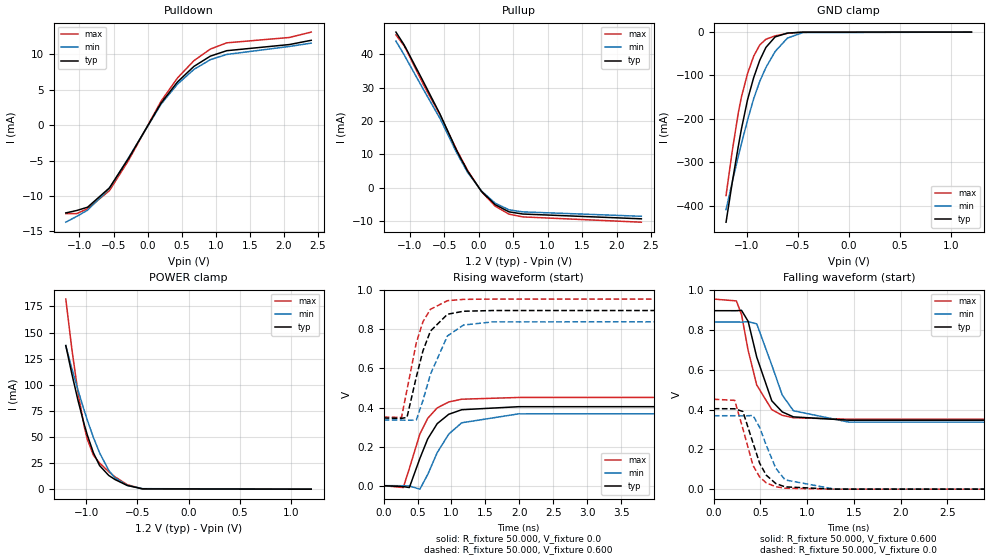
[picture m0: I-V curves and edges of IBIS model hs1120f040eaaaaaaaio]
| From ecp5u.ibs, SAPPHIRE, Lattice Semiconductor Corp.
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|   Model hs1120f040eaaaaaaaio
[Model] hs1120f040eaaaaaaaio
Model_type I/O
Polarity   Non-Inverting
Enable   Active-Low
Vinl =  0.500V
Vinh =  0.700V
Vmeas =  0.600V
Cref =  20.000pF
Rref =  50.000
Vref =  0.600V
C_comp   5.000pF   4.000pF   5.500pF
[Temperature Range]   25.000   0.125k   -40.000
[Voltage Range]   1.200V   1.140V   1.260V
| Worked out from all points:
|   slope of the pulldown table from 0 to 0.18 V, typ, clamps not added: 62.6 ohm
|   slope of the pullup table from 0 to 0.18 V, typ, clamps not added: 44.5 ohm
|   GND clamp passes 1 mA (typ) near -0.54 V on its own axis
|   POWER clamp passes 1 mA (typ) near -0.51 V on its own axis
|   rising waveform, R_fixture 50.000, V_fixture 0.0: 20-80 % time 327ps typ, 376ps min, 303ps max; typ from 0 V to 0.404 V
|   rising waveform, R_fixture 50.000, V_fixture 0.600: 20-80 % time 264ps typ, 305ps min, 239ps max; typ from 0.346 V to 0.897 V
|   falling waveform, R_fixture 50.000, V_fixture 0.600: 20-80 % time 201ps typ, 222ps min, 189ps max; typ from 0.897 V to 0.346 V
|   falling waveform, R_fixture 50.000, V_fixture 0.0: 20-80 % time 182ps typ, 204ps min, 167ps max; typ from 0.404 V to 0 V
[Pulldown]
|Voltage   I(typ)   I(min)   I(max)
-1.2V     -12.39mA   -13.7mA    -12.49mA
-1.04V    -12.05mA   -12.88mA   -12.49mA
-880mV    -11.58mA   -12mA      -11.79mA
-560mV    -8.851mA   -8.925mA   -9.245mA
-280mV    -4.688mA   -4.607mA   -4.974mA
200mV     3.164mA    3.008mA    3.437mA
440mV     6.136mA    5.828mA    6.7mA
680mV     8.315mA    7.89mA     9.126mA
920mV     9.761mA    9.262mA    10.76mA
1.16V     10.53mA    9.999mA    11.64mA
2.08V     11.4mA     11.13mA    12.4mA
2.4V      12mA       11.6mA     13.16mA
[Pullup]
|Voltage   I(typ)   I(min)   I(max)
-1.2V     46.58mA    43.89mA    45.74mA
-1.08V    42.72mA    39.74mA    42.43mA
-1.04V    41.15mA    38.23mA    40.88mA
-800mV    31.67mA    29.37mA    30.83mA
-560mV    22.01mA    20.73mA    21.77mA
-320mV    11.18mA    10.54mA    11.37mA
-160mV    4.974mA    4.595mA    5.205mA
40mV      -1.043mA   -938.5uA   -1.131mA
240mV     -5.059mA   -4.599mA   -5.498mA
440mV     -7.189mA   -6.594mA   -7.881mA
640mV     -7.846mA   -7.203mA   -8.71mA
2.36V     -9.281mA   -8.526mA   -10.29mA
[GND_clamp]
|Voltage   I(typ)   I(min)   I(max)
-1.2V     -438mA     -409mA     -376.5mA
-1.14V    -347.3mA   -346mA     -274.9mA
-1.08V    -262.9mA   -286.2mA   -185.9mA
-1.05V    -223.7mA   -257.6mA   -150mA
-990mV    -156.1mA   -203.2mA   -95.66mA
-930mV    -105mA     -153.7mA   -55.58mA
-870mV    -64.74mA   -113.2mA   -29.56mA
-810mV    -35.2mA    -81.56mA   -16.45mA
-720mV    -11.09mA   -44.69mA   -8.691mA
-600mV    -2.287mA   -13.94mA   -2.904mA
-450mV    -166.2uA   -1.247mA   -164.1uA
1.2V      0A         0A         0A
[POWER_clamp]
|Voltage   I(typ)   I(min)   I(max)
-1.2V     137.6mA    137.3mA    182.1mA
-1.14V    110.1mA    115.3mA    133.6mA
-1.08V    84.76mA    94.63mA    92.15mA
-1.02V    62.11mA    75.36mA    59.94mA
-990mV    52mA       66.3mA     47.89mA
-930mV    34.81mA    49.51mA    32.55mA
-870mV    22.62mA    34.86mA    25.07mA
-780mV    13.14mA    18.01mA    16.74mA
-720mV    9.284mA    10.72mA    11.88mA
-600mV    3.553mA    3.709mA    4.373mA
-450mV    294.8uA    471.6uA    256.4uA
1.2V      0A         0A         0A
[Ramp]
| variable   typ   min   max
dV/dt_r 0.243/0.326n   0.221/0.376n   0.271/0.306n
dV/dt_f 0.266/0.237n   0.247/0.244n   0.295/0.221n
R_load = 50.000
[Rising Waveform]
R_fixture= 50.000
V_fixture= 0.0
V_fixture_min= 0.0
V_fixture_max= 0.0
|time   V(typ)   V(min)   V(max)
0s        0V         0V         0V
289ps     -4.789mV   -413.9uV   -9.697mV
379ps     -9.66mV    -1.515mV   88.12mV
534ps     139.4mV    -17.96mV   264.5mV
650ps     239.8mV    57.5mV     344.9mV
790ps     317.5mV    169.3mV    398.1mV
960ps     365.4mV    264.1mV    428.4mV
1.151ns   388.6mV    321.8mV    442.5mV
1.99ns    404.1mV    367.5mV    451.4mV
10ns      404.4mV    368.9mV    451.6mV
[Rising Waveform]
R_fixture= 50.000
V_fixture= 0.600
V_fixture_min= 0.571
V_fixture_max= 0.631
|time   V(typ)   V(min)   V(max)
0s        346.3mV    335.9mV    351.2mV
263ps     344.3mV    335.7mV    349mV
344ps     349.5mV    334.8mV    489.9mV
481ps     555.6mV    335.6mV    730.8mV
579ps     689.6mV    435.6mV    838.7mV
690ps     791.3mV    570.7mV    902.8mV
941ps     877.3mV    766.6mV    946.7mV
1.179ns   892.7mV    822.2mV    953.5mV
1.61ns    896.3mV    838.2mV    954.9mV
10ns      896.6mV    839.7mV    955mV
[Falling Waveform]
R_fixture= 50.000
V_fixture= 0.600
V_fixture_min= 0.571
V_fixture_max= 0.631
|time   V(typ)   V(min)   V(max)
0s        896.6mV    839.7mV    955mV
242ps     896.5mV    839.7mV    945.7mV
297ps     898.2mV    839.3mV    877.3mV
368ps     843mV      841.5mV    696.6mV
460ps     663.2mV    830.3mV    523.1mV
621ps     443.8mV    623.4mV    399.5mV
733ps     388.1mV    472.9mV    371mV
853ps     363.1mV    393.9mV    358.8mV
1.445ns   346.5mV    336.8mV    351.3mV
10ns      346.3mV    335.9mV    351.2mV
[Falling Waveform]
R_fixture= 50.000
V_fixture= 0.0
V_fixture_min= 0.0
V_fixture_max= 0.0
|time   V(typ)   V(min)   V(max)
0s        404.4mV    368.9mV    451.6mV
224ps     403.8mV    368.9mV    446.2mV
312ps     390.1mV    368mV      302.8mV
420ps     232.1mV    370mV      118.9mV
491ps     130.3mV    310.5mV    61.37mV
561ps     70.66mV    221.5mV    31.86mV
664ps     28.26mV    105.2mV    12.12mV
764ps     11.56mV    46.42mV    4.735mV
1.291ns   123uV      636.8uV    38.25uV
10ns      0V         0V         0V
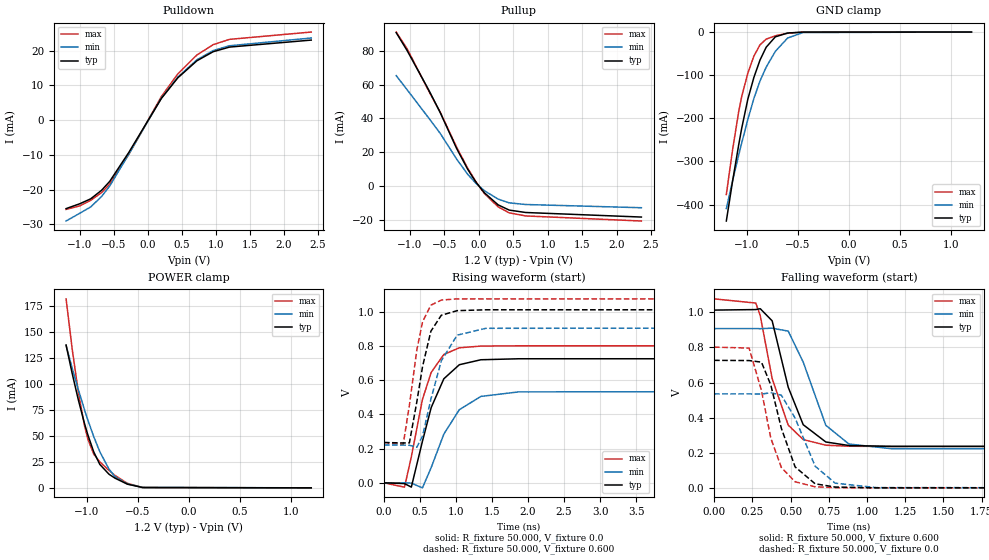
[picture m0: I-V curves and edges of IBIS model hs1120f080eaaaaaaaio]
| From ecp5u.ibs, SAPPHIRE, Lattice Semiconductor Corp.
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|   Model hs1120f080eaaaaaaaio
[Model] hs1120f080eaaaaaaaio
Model_type I/O
Polarity   Non-Inverting
Enable   Active-Low
Vinl =  0.500V
Vinh =  0.700V
Vmeas =  0.600V
Cref =  20.000pF
Rref =  50.000
Vref =  0.600V
C_comp   5.000pF   4.000pF   5.500pF
[Temperature Range]   25.000   0.125k   -40.000
[Voltage Range]   1.200V   1.140V   1.260V
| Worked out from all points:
|   slope of the pulldown table from 0 to 0.18 V, typ, clamps not added: 31.5 ohm
|   slope of the pullup table from 0 to 0.18 V, typ, clamps not added: 22.6 ohm
|   GND clamp passes 1 mA (typ) near -0.54 V on its own axis
|   POWER clamp passes 1 mA (typ) near -0.51 V on its own axis
|   rising waveform, R_fixture 50.000, V_fixture 0.0: 20-80 % time 307ps typ, 377ps min, 267ps max; typ from 0 V to 0.727 V
|   rising waveform, R_fixture 50.000, V_fixture 0.600: 20-80 % time 202ps typ, 266ps min, 177ps max; typ from 0.236 V to 1.01 V
|   falling waveform, R_fixture 50.000, V_fixture 0.600: 20-80 % time 151ps typ, 165ps min, 138ps max; typ from 1.01 V to 0.236 V
|   falling waveform, R_fixture 50.000, V_fixture 0.0: 20-80 % time 141ps typ, 161ps min, 125ps max; typ from 0.727 V to 0 V
[Pulldown]
|Voltage   I(typ)   I(min)   I(max)
-1.2V     -25.46mA   -29.03mA   -25.7mA
-1V       -24.07mA   -26.8mA    -24.67mA
-840mV    -22.66mA   -25mA      -23.11mA
-680mV    -20.21mA   -22.01mA   -20.87mA
-560mV    -17.64mA   -18.97mA   -18.42mA
-280mV    -9.315mA   -9.799mA   -9.876mA
200mV     6.283mA    6.399mA    6.82mA
440mV     12.18mA    12.4mA     13.3mA
720mV     17.09mA    17.37mA    18.76mA
960mV     19.72mA    20.05mA    21.74mA
1.2V      21.05mA    21.43mA    23.27mA
2.4V      23.06mA    23.66mA    25.38mA
[Pullup]
|Voltage   I(typ)   I(min)   I(max)
-1.2V     90.66mA    65.26mA    91.02mA
-1.04V    79.98mA    56.85mA    81mA
-720mV    56.18mA    39.79mA    55.6mA
-560mV    43.33mA    31.08mA    43.6mA
-320mV    22.01mA    15.8mA     22.77mA
-160mV    9.797mA    6.888mA    10.43mA
-40mV     2.216mA    1.527mA    2.421mA
80mV      -3.948mA   -2.709mA   -4.356mA
280mV     -11.09mA   -7.687mA   -12.27mA
440mV     -14.17mA   -9.883mA   -15.79mA
680mV     -15.6mA    -10.88mA   -17.63mA
2.36V     -18.29mA   -12.78mA   -20.63mA
[GND_clamp]
|Voltage   I(typ)   I(min)   I(max)
-1.2V     -438mA     -409mA     -376.5mA
-1.14V    -347.3mA   -346mA     -274.9mA
-1.08V    -262.9mA   -286.2mA   -185.9mA
-1.05V    -223.7mA   -257.6mA   -150mA
-990mV    -156.1mA   -203.2mA   -95.66mA
-930mV    -105mA     -153.7mA   -55.58mA
-870mV    -64.74mA   -113.2mA   -29.56mA
-810mV    -35.2mA    -81.56mA   -16.45mA
-720mV    -11.09mA   -44.69mA   -8.691mA
-600mV    -2.287mA   -13.94mA   -2.904mA
-450mV    -166.2uA   -1.247mA   -164.1uA
1.2V      0A         0A         0A
[POWER_clamp]
|Voltage   I(typ)   I(min)   I(max)
-1.2V     137.6mA    137.3mA    182.1mA
-1.14V    110.1mA    115.3mA    133.6mA
-1.08V    84.76mA    94.63mA    92.15mA
-1.02V    62.11mA    75.36mA    59.94mA
-990mV    52mA       66.3mA     47.89mA
-930mV    34.81mA    49.51mA    32.55mA
-870mV    22.62mA    34.86mA    25.07mA
-780mV    13.14mA    18.01mA    16.74mA
-720mV    9.284mA    10.72mA    11.88mA
-600mV    3.553mA    3.709mA    4.373mA
-450mV    294.8uA    471.6uA    256.4uA
1.2V      0A         0A         0A
[Ramp]
| variable   typ   min   max
dV/dt_r 0.436/0.309n   0.321/0.378n   0.481/0.269n
dV/dt_f 0.411/0.174n   0.397/0.185n   0.448/0.159n
R_load = 50.000
[Rising Waveform]
R_fixture= 50.000
V_fixture= 0.0
V_fixture_min= 0.0
V_fixture_max= 0.0
|time   V(typ)   V(min)   V(max)
0s        0V         0V         0V
285ps     -4.631mV   -474.9uV   -25.7mV
380ps     -25.16mV   -1.901mV   151.7mV
534ps     242.9mV    -29.51mV   488.3mV
656ps     441.2mV    89.85mV    646.8mV
831ps     609.1mV    285.2mV    751.4mV
1.046ns   691.4mV    428.1mV    790.5mV
1.345ns   720.5mV    505.8mV    800.6mV
1.871ns   726.3mV    532.4mV    802.1mV
10ns      726.6mV    535.5mV    802.1mV
[Rising Waveform]
R_fixture= 50.000
V_fixture= 0.600
V_fixture_min= 0.571
V_fixture_max= 0.631
|time   V(typ)   V(min)   V(max)
0s        236.1mV    221.1mV    235.9mV
267ps     233.3mV    220.9mV    224.6mV
353ps     233.7mV    219.7mV    453.6mV
456ps     473.6mV    208mV      777.3mV
536ps     681.3mV    275mV      943mV
651ps     887.3mV    488.6mV    1.04V
796ps     981.1mV    714.6mV    1.07V
1.016ns   1.008V     864.5mV    1.077V
1.415ns   1.013V     904.6mV    1.077V
10ns      1.013V     907.6mV    1.077V
[Falling Waveform]
R_fixture= 50.000
V_fixture= 0.600
V_fixture_min= 0.571
V_fixture_max= 0.631
|time   V(typ)   V(min)   V(max)
0s        1.013V     907.6mV    1.077V
273ps     1.016V     907.8mV    1.053V
302ps     1.021V     907.2mV    981.7mV
380ps     951.7mV    909.9mV    622.4mV
485ps     573.5mV    893.1mV    357.5mV
583ps     359.9mV    716.7mV    275.2mV
731ps     261.4mV    356.3mV    243mV
882ps     241.2mV    249.8mV    237.2mV
1.161ns   236.4mV    223mV      236mV
10ns      236.1mV    221.1mV    235.9mV
[Falling Waveform]
R_fixture= 50.000
V_fixture= 0.0
V_fixture_min= 0.0
V_fixture_max= 0.0
|time   V(typ)   V(min)   V(max)
0s        726.6mV    535.5mV    802.1mV
229ps     725.4mV    535.5mV    796.5mV
310ps     716.4mV    534.3mV    555.1mV
371ps     586.4mV    542.1mV    283.1mV
440ps     339.7mV    527.6mV    116.1mV
530ps     119.4mV    398mV      34.62mV
661ps     23.14mV    123.6mV    5.973mV
792ps     4.578mV    26.73mV    1.078mV
1.062ns   220uV      1.267mV    44.45uV
10ns      0V         0V         0V
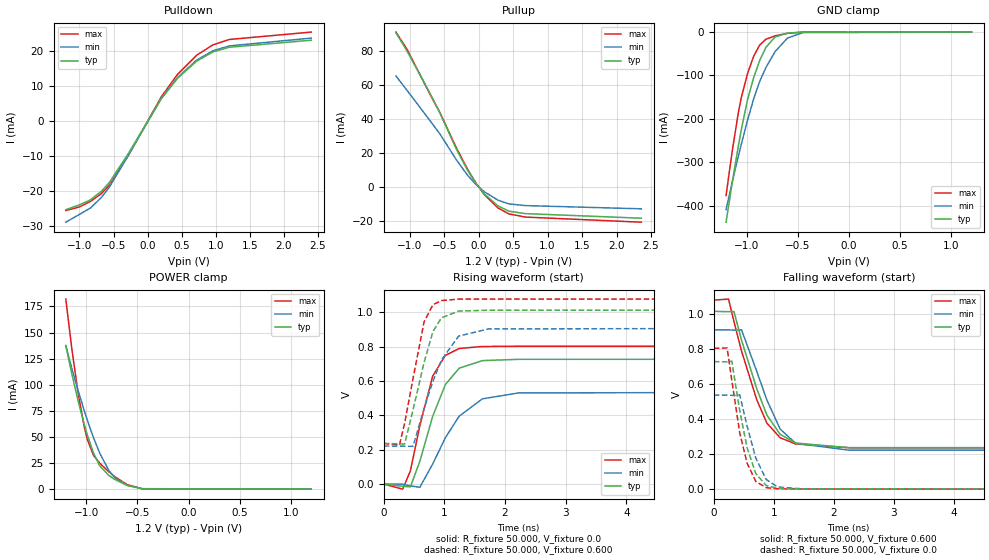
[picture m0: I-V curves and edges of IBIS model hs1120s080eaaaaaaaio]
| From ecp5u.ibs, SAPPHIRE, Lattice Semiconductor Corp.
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|   Model hs1120s080eaaaaaaaio
[Model] hs1120s080eaaaaaaaio
Model_type I/O
Polarity   Non-Inverting
Enable   Active-Low
Vinl =  0.500V
Vinh =  0.700V
Vmeas =  0.600V
Cref =  20.000pF
Rref =  50.000
Vref =  0.600V
C_comp   5.000pF   4.000pF   5.500pF
[Temperature Range]   25.000   0.125k   -40.000
[Voltage Range]   1.200V   1.140V   1.260V
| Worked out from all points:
|   slope of the pulldown table from 0 to 0.18 V, typ, clamps not added: 31.5 ohm
|   slope of the pullup table from 0 to 0.18 V, typ, clamps not added: 22.6 ohm
|   GND clamp passes 1 mA (typ) near -0.54 V on its own axis
|   POWER clamp passes 1 mA (typ) near -0.51 V on its own axis
|   rising waveform, R_fixture 50.000, V_fixture 0.0: 20-80 % time 414ps typ, 535ps min, 329ps max; typ from 0 V to 0.727 V
|   rising waveform, R_fixture 50.000, V_fixture 0.600: 20-80 % time 324ps typ, 423ps min, 265ps max; typ from 0.236 V to 1.01 V
|   falling waveform, R_fixture 50.000, V_fixture 0.600: 20-80 % time 475ps typ, 467ps min, 475ps max; typ from 1.01 V to 0.236 V
|   falling waveform, R_fixture 50.000, V_fixture 0.0: 20-80 % time 259ps typ, 268ps min, 252ps max; typ from 0.727 V to 0 V
[Pulldown]
|Voltage   I(typ)   I(min)   I(max)
-1.2V     -25.46mA   -29.03mA   -25.7mA
-1V       -24.07mA   -26.8mA    -24.67mA
-840mV    -22.66mA   -25mA      -23.11mA
-680mV    -20.21mA   -22.01mA   -20.87mA
-560mV    -17.64mA   -18.97mA   -18.42mA
-280mV    -9.315mA   -9.799mA   -9.876mA
200mV     6.283mA    6.399mA    6.82mA
440mV     12.18mA    12.4mA     13.3mA
720mV     17.09mA    17.37mA    18.76mA
960mV     19.72mA    20.05mA    21.74mA
1.2V      21.05mA    21.43mA    23.27mA
2.4V      23.06mA    23.66mA    25.38mA
[Pullup]
|Voltage   I(typ)   I(min)   I(max)
-1.2V     90.66mA    65.25mA    91.02mA
-1.04V    79.98mA    56.85mA    81mA
-720mV    56.18mA    39.79mA    55.6mA
-560mV    43.33mA    31.08mA    43.6mA
-320mV    22.01mA    15.8mA     22.77mA
-160mV    9.797mA    6.888mA    10.43mA
-40mV     2.216mA    1.527mA    2.421mA
80mV      -3.948mA   -2.709mA   -4.356mA
280mV     -11.09mA   -7.687mA   -12.27mA
440mV     -14.17mA   -9.883mA   -15.79mA
680mV     -15.6mA    -10.88mA   -17.63mA
2.36V     -18.29mA   -12.78mA   -20.63mA
[GND_clamp]
|Voltage   I(typ)   I(min)   I(max)
-1.2V     -438mA     -409mA     -376.5mA
-1.14V    -347.3mA   -346mA     -274.9mA
-1.08V    -262.9mA   -286.2mA   -185.9mA
-1.05V    -223.7mA   -257.6mA   -150mA
-990mV    -156.1mA   -203.2mA   -95.66mA
-930mV    -105mA     -153.7mA   -55.58mA
-870mV    -64.74mA   -113.2mA   -29.56mA
-810mV    -35.2mA    -81.56mA   -16.45mA
-720mV    -11.09mA   -44.69mA   -8.691mA
-600mV    -2.287mA   -13.94mA   -2.904mA
-450mV    -166.2uA   -1.247mA   -164.1uA
1.2V      0A         0A         0A
[POWER_clamp]
|Voltage   I(typ)   I(min)   I(max)
-1.2V     137.6mA    137.3mA    182.1mA
-1.14V    110.1mA    115.3mA    133.6mA
-1.08V    84.76mA    94.63mA    92.15mA
-1.02V    62.11mA    75.36mA    59.94mA
-990mV    52mA       66.3mA     47.89mA
-930mV    34.81mA    49.51mA    32.55mA
-870mV    22.62mA    34.86mA    25.07mA
-780mV    13.14mA    18.01mA    16.74mA
-720mV    9.284mA    10.72mA    11.88mA
-600mV    3.553mA    3.709mA    4.373mA
-450mV    294.8uA    471.6uA    256.4uA
1.2V      0A         0A         0A
[Ramp]
| variable   typ   min   max
dV/dt_r 0.436/0.416n   0.321/0.536n   0.481/0.332n
dV/dt_f 0.411/0.487n   0.397/0.446n   0.448/0.513n
R_load = 50.000
[Rising Waveform]
R_fixture= 50.000
V_fixture= 0.0
V_fixture_min= 0.0
V_fixture_max= 0.0
|time   V(typ)   V(min)   V(max)
0s        0V         0V         0V
314ps     -13.54mV   -930.2uV   -30.05mV
441ps     -16.38mV   -11.15mV   77.16mV
597ps     132.9mV    -18.84mV   340.3mV
808ps     394mV      116.3mV    628.2mV
1.017ns   578.9mV    269.4mV    749.1mV
1.244ns   674.3mV    394.5mV    789mV
1.627ns   718.6mV    495.9mV    800.9mV
2.225ns   726.1mV    530.5mV    802.1mV
10ns      726.6mV    535.5mV    802.1mV
[Rising Waveform]
R_fixture= 50.000
V_fixture= 0.600
V_fixture_min= 0.571
V_fixture_max= 0.631
|time   V(typ)   V(min)   V(max)
0s        236.1mV    221.1mV    235.9mV
260ps     233.9mV    221mV      227mV
345ps     233.3mV    219.8mV    352.8mV
484ps     430.9mV    219.4mV    613.9mV
666ps     707.8mV    440.6mV    943.8mV
812ps     887.4mV    597.6mV    1.044V
952ps     967.7mV    722.5mV    1.068V
1.236ns   1.007V     861mV      1.077V
1.726ns   1.012V     903.2mV    1.077V
10ns      1.013V     907.6mV    1.077V
[Falling Waveform]
R_fixture= 50.000
V_fixture= 0.600
V_fixture_min= 0.571
V_fixture_max= 0.631
|time   V(typ)   V(min)   V(max)
0s        1.013V     907.6mV    1.077V
246ps     1.011V     907.6mV    1.083V
337ps     1.012V     905.8mV    954mV
462ps     849.9mV    908.1mV    787.6mV
716ps     573.1mV    672.1mV    510mV
885ps     422.3mV    508.4mV    376.4mV
1.107ns   312.1mV    342.2mV    292.9mV
1.365ns   262.7mV    261.3mV    257.4mV
2.251ns   236.5mV    222.3mV    236.1mV
10ns      236.1mV    221.1mV    235.9mV
[Falling Waveform]
R_fixture= 50.000
V_fixture= 0.0
V_fixture_min= 0.0
V_fixture_max= 0.0
|time   V(typ)   V(min)   V(max)
0s        726.6mV    535.5mV    802.1mV
222ps     725.1mV    535.5mV    804.5mV
300ps     729.6mV    534.5mV    622mV
433ps     446.5mV    537mV      320.6mV
557ps     235.1mV    357.4mV    146.9mV
701ps     88.27mV    176.6mV    43.82mV
875ps     20.57mV    54.78mV    8.524mV
1.066ns   4.516mV    12.43mV    2.225mV
1.491ns   1.094mV    1.706mV    959.9uV
10ns      0V         0V         0V
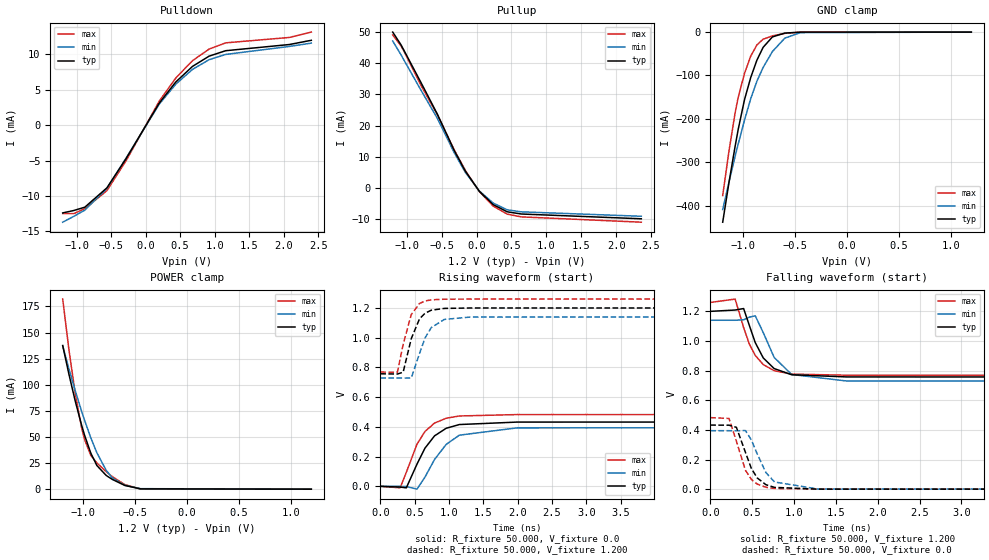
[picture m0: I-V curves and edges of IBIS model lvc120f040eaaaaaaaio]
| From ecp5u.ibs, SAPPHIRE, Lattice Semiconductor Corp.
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|   Model lvc120f040eaaaaaaaio
[Model] lvc120f040eaaaaaaaio
Model_type I/O
Polarity   Non-Inverting
Enable   Active-Low
Vinl =  0.420V
Vinh =  0.780V
Vmeas =  0.600V
Cref =  0.0F
Rref =  1.000M
Vref =  0.0V
C_comp   5.000pF   4.000pF   5.500pF
[Temperature Range]   25.000   0.125k   -40.000
[Voltage Range]   1.200V   1.140V   1.260V
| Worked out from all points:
|   slope of the pulldown table from 0 to 0.18 V, typ, clamps not added: 62.6 ohm
|   slope of the pullup table from 0 to 0.18 V, typ, clamps not added: 41.4 ohm
|   GND clamp passes 1 mA (typ) near -0.54 V on its own axis
|   POWER clamp passes 1 mA (typ) near -0.51 V on its own axis
|   rising waveform, R_fixture 50.000, V_fixture 0.0: 20-80 % time 327ps typ, 376ps min, 303ps max; typ from 0 V to 0.433 V
|   rising waveform, R_fixture 50.000, V_fixture 1.200: 20-80 % time 175ps typ, 206ps min, 158ps max; typ from 0.757 V to 1.2 V
|   falling waveform, R_fixture 50.000, V_fixture 1.200: 20-80 % time 229ps typ, 242ps min, 221ps max; typ from 1.2 V to 0.757 V
|   falling waveform, R_fixture 50.000, V_fixture 0.0: 20-80 % time 182ps typ, 204ps min, 167ps max; typ from 0.433 V to 0 V
[Pulldown]
|Voltage   I(typ)   I(min)   I(max)
-1.2V     -12.39mA   -13.7mA    -12.49mA
-1.04V    -12.05mA   -12.88mA   -12.49mA
-880mV    -11.58mA   -12mA      -11.79mA
-560mV    -8.851mA   -8.925mA   -9.245mA
-280mV    -4.688mA   -4.607mA   -4.974mA
200mV     3.164mA    3.008mA    3.437mA
440mV     6.136mA    5.828mA    6.7mA
680mV     8.315mA    7.89mA     9.126mA
920mV     9.761mA    9.262mA    10.76mA
1.16V     10.53mA    9.999mA    11.64mA
2.08V     11.4mA     11.13mA    12.4mA
2.4V      12mA       11.6mA     13.16mA
[Pullup]
|Voltage   I(typ)   I(min)   I(max)
-1.2V     50.07mA    47.18mA    49.17mA
-1.08V    45.93mA    42.73mA    45.61mA
-1.04V    44.24mA    41.1mA     43.95mA
-800mV    34.04mA    31.57mA    33.14mA
-560mV    23.66mA    22.29mA    23.4mA
-320mV    12.02mA    11.33mA    12.22mA
-160mV    5.347mA    4.94mA     5.595mA
40mV      -1.121mA   -1.009mA   -1.216mA
240mV     -5.438mA   -4.944mA   -5.91mA
440mV     -7.728mA   -7.089mA   -8.472mA
640mV     -8.434mA   -7.743mA   -9.364mA
2.36V     -9.976mA   -9.166mA   -11.07mA
[GND_clamp]
|Voltage   I(typ)   I(min)   I(max)
-1.2V     -438mA     -409mA     -376.5mA
-1.14V    -347.3mA   -346mA     -274.9mA
-1.08V    -262.9mA   -286.2mA   -185.9mA
-1.05V    -223.7mA   -257.6mA   -150mA
-990mV    -156.1mA   -203.2mA   -95.66mA
-930mV    -105mA     -153.7mA   -55.58mA
-870mV    -64.74mA   -113.2mA   -29.56mA
-810mV    -35.2mA    -81.56mA   -16.45mA
-720mV    -11.09mA   -44.69mA   -8.691mA
-600mV    -2.287mA   -13.94mA   -2.904mA
-450mV    -166.2uA   -1.247mA   -164.1uA
1.2V      0A         0A         0A
[POWER_clamp]
|Voltage   I(typ)   I(min)   I(max)
-1.2V     137.6mA    137.3mA    182.1mA
-1.14V    110.1mA    115.3mA    133.6mA
-1.08V    84.76mA    94.63mA    92.15mA
-1.02V    62.11mA    75.36mA    59.94mA
-990mV    52mA       66.3mA     47.89mA
-930mV    34.81mA    49.51mA    32.55mA
-870mV    22.62mA    34.86mA    25.07mA
-780mV    13.14mA    18.01mA    16.74mA
-720mV    9.284mA    10.72mA    11.88mA
-600mV    3.553mA    3.709mA    4.373mA
-450mV    294.8uA    471.6uA    256.4uA
1.2V      0A         0A         0A
[Ramp]
| variable   typ   min   max
dV/dt_r   0.260/0.326n   0.237/0.376n   0.290/0.306n
dV/dt_f   0.266/0.237n   0.247/0.244n   0.295/0.221n
R_load = 50.000
[Rising Waveform]
R_fixture= 50.000
V_fixture= 0.0
V_fixture_min= 0.0
V_fixture_max= 0.0
|time   V(typ)   V(min)   V(max)
0s        0V         0V         0V
289ps     -5.122mV   -442.6uV   -10.37mV
379ps     -10.33mV   -1.62mV    94.23mV
534ps     149mV      -19.21mV   282.9mV
650ps     256.4mV    61.5mV     368.9mV
790ps     339.6mV    181mV      425.7mV
960ps     390.8mV    282.4mV    458.2mV
1.151ns   415.6mV    344.2mV    473.3mV
1.99ns    432.2mV    393.1mV    482.7mV
10ns      432.5mV    394.5mV    482.9mV
[Rising Waveform]
R_fixture= 50.000
V_fixture= 1.200
V_fixture_min= 1.140
V_fixture_max= 1.260
|time   V(typ)   V(min)   V(max)
0s        757.1mV    728.8mV    768.8mV
249ps     755.6mV    728.8mV    767.7mV
333ps     768mV      727.8mV    954.4mV
451ps     993.7mV    728.5mV    1.156V
571ps     1.127V     893.7mV    1.23V
652ps     1.165V     998.9mV    1.247V
742ps     1.185V     1.068V     1.255V
932ps     1.197V     1.123V     1.259V
1.311ns   1.2V       1.139V     1.26V
10ns      1.2V       1.14V      1.26V
[Falling Waveform]
R_fixture= 50.000
V_fixture= 1.200
V_fixture_min= 1.140
V_fixture_max= 1.260
|time   V(typ)   V(min)   V(max)
0s        1.2V       1.14V      1.26V
297ps     1.209V     1.14V      1.283V
398ps     1.219V     1.143V     1.091V
466ps     1.106V     1.161V     980mV
537ps     989.3mV    1.17V      902.9mV
633ps     885.5mV    1.056V     840.7mV
763ps     813.8mV    889mV      799.4mV
972ps     772.2mV    773.8mV    776.6mV
1.633ns   757.4mV    729.7mV    769mV
10ns      757.1mV    728.8mV    768.8mV
[Falling Waveform]
R_fixture= 50.000
V_fixture= 0.0
V_fixture_min= 0.0
V_fixture_max= 0.0
|time   V(typ)   V(min)   V(max)
0s        432.5mV    394.5mV    482.9mV
224ps     431.8mV    394.5mV    477.2mV
312ps     417.3mV    393.6mV    323.8mV
420ps     248.2mV    395.7mV    127.2mV
491ps     139.3mV    332mV      65.66mV
561ps     75.6mV     236.9mV    34.09mV
664ps     30.23mV    112.5mV    12.97mV
767ps     12.04mV    48.49mV    4.923mV
1.291ns   131.7uV    681.6uV    38.3uV
10ns      0V         0V         0V
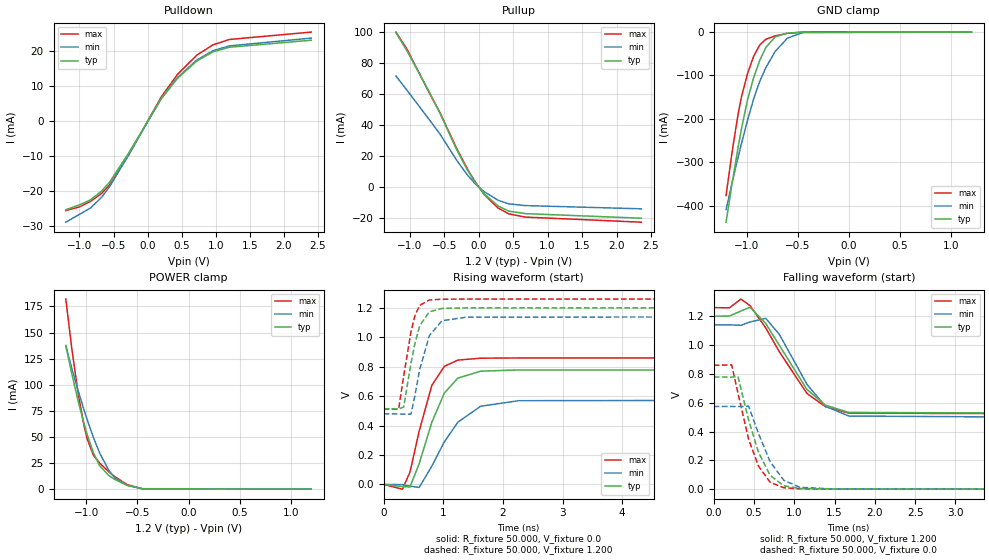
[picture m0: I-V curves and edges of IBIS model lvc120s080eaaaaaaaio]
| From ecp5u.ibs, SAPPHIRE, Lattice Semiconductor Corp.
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|   Model lvc120s080eaaaaaaaio
[Model] lvc120s080eaaaaaaaio
Model_type I/O
Polarity   Non-Inverting
Enable   Active-Low
Vinl =  0.420V
Vinh =  0.780V
Vmeas =  0.600V
Cref =  0.0F
Rref =  1.000M
Vref =  0.0V
C_comp   5.000pF   4.000pF   5.500pF
[Temperature Range]   25.000   0.125k   -40.000
[Voltage Range]   1.200V   1.140V   1.260V
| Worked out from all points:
|   slope of the pulldown table from 0 to 0.18 V, typ, clamps not added: 31.5 ohm
|   slope of the pullup table from 0 to 0.18 V, typ, clamps not added: 20.5 ohm
|   GND clamp passes 1 mA (typ) near -0.54 V on its own axis
|   POWER clamp passes 1 mA (typ) near -0.51 V on its own axis
|   rising waveform, R_fixture 50.000, V_fixture 0.0: 20-80 % time 414ps typ, 535ps min, 329ps max; typ from 0 V to 0.779 V
|   rising waveform, R_fixture 50.000, V_fixture 1.200: 20-80 % time 206ps typ, 235ps min, 188ps max; typ from 0.515 V to 1.2 V
|   falling waveform, R_fixture 50.000, V_fixture 1.200: 20-80 % time 477ps typ, 429ps min, 505ps max; typ from 1.2 V to 0.515 V
|   falling waveform, R_fixture 50.000, V_fixture 0.0: 20-80 % time 260ps typ, 268ps min, 253ps max; typ from 0.779 V to 0 V
[Pulldown]
|Voltage   I(typ)   I(min)   I(max)
-1.2V     -25.46mA   -29.03mA   -25.7mA
-1V       -24.07mA   -26.8mA    -24.67mA
-840mV    -22.66mA   -25mA      -23.11mA
-680mV    -20.21mA   -22.01mA   -20.87mA
-560mV    -17.64mA   -18.97mA   -18.42mA
-280mV    -9.315mA   -9.799mA   -9.876mA
200mV     6.283mA    6.399mA    6.82mA
440mV     12.18mA    12.4mA     13.3mA
720mV     17.09mA    17.37mA    18.76mA
960mV     19.72mA    20.05mA    21.74mA
1.2V      21.05mA    21.43mA    23.27mA
2.4V      23.06mA    23.66mA    25.38mA
[Pullup]
|Voltage   I(typ)   I(min)   I(max)
-1.2V     99.72mA    71.77mA    100.1mA
-1.04V    87.98mA    62.54mA    89.1mA
-720mV    61.79mA    43.77mA    61.16mA
-560mV    47.66mA    34.19mA    47.95mA
-320mV    24.22mA    17.38mA    25.05mA
-160mV    10.78mA    7.577mA    11.47mA
-40mV     2.437mA    1.679mA    2.663mA
80mV      -4.343mA   -2.98mA    -4.792mA
280mV     -12.2mA    -8.456mA   -13.5mA
440mV     -15.58mA   -10.87mA   -17.37mA
680mV     -17.16mA   -11.97mA   -19.4mA
2.36V     -20.12mA   -14.05mA   -22.69mA
[GND_clamp]
|Voltage   I(typ)   I(min)   I(max)
-1.2V     -438mA     -409mA     -376.5mA
-1.14V    -347.3mA   -346mA     -274.9mA
-1.08V    -262.9mA   -286.2mA   -185.9mA
-1.05V    -223.7mA   -257.6mA   -150mA
-990mV    -156.1mA   -203.2mA   -95.66mA
-930mV    -105mA     -153.7mA   -55.58mA
-870mV    -64.74mA   -113.2mA   -29.56mA
-810mV    -35.2mA    -81.56mA   -16.45mA
-720mV    -11.09mA   -44.69mA   -8.691mA
-600mV    -2.287mA   -13.94mA   -2.904mA
-450mV    -166.2uA   -1.247mA   -164.1uA
1.2V      0A         0A         0A
[POWER_clamp]
|Voltage   I(typ)   I(min)   I(max)
-1.2V     137.6mA    137.3mA    182.1mA
-1.14V    110.1mA    115.3mA    133.6mA
-1.08V    84.76mA    94.63mA    92.15mA
-1.02V    62.11mA    75.36mA    59.94mA
-990mV    52mA       66.3mA     47.89mA
-930mV    34.81mA    49.51mA    32.55mA
-870mV    22.62mA    34.86mA    25.07mA
-780mV    13.14mA    18.01mA    16.74mA
-720mV    9.284mA    10.72mA    11.88mA
-600mV    3.553mA    3.709mA    4.373mA
-450mV    294.8uA    471.6uA    256.4uA
1.2V      0A         0A         0A
[Ramp]
| variable   typ   min   max
dV/dt_r   0.463/0.416n   0.349/0.536n   0.507/0.332n
dV/dt_f   0.411/0.487n   0.397/0.446n   0.448/0.513n
R_load = 50.000
[Rising Waveform]
R_fixture= 50.000
V_fixture= 0.0
V_fixture_min= 0.0
V_fixture_max= 0.0
|time   V(typ)   V(min)   V(max)
0s        0V         0V         0V
314ps     -14.51mV   -996.9uV   -32.2mV
441ps     -17.55mV   -11.95mV   82.69mV
597ps     142.4mV    -20.19mV   364.6mV
808ps     422.2mV    124.7mV    673.1mV
1.017ns   620.4mV    288.7mV    802.6mV
1.244ns   722.5mV    422.7mV    845.1mV
1.627ns   770mV      531.5mV    858.1mV
2.264ns   778.1mV    569.2mV    859.6mV
10ns      778.7mV    573.9mV    859.6mV
[Rising Waveform]
R_fixture= 50.000
V_fixture= 1.200
V_fixture_min= 1.140
V_fixture_max= 1.260
|time   V(typ)   V(min)   V(max)
0s        515.1mV    479.1mV    513.2mV
252ps     513mV      479mV      512.4mV
336ps     526.3mV    477.7mV    737.4mV
458ps     823.1mV    478mV      1.037V
525ps     957.9mV    606.2mV    1.149V
605ps     1.079V     781.8mV    1.217V
767ps     1.174V     1.012V     1.254V
979ps     1.196V     1.113V     1.259V
1.39ns    1.2V       1.137V     1.26V
10ns      1.2V       1.14V      1.26V
[Falling Waveform]
R_fixture= 50.000
V_fixture= 1.200
V_fixture_min= 1.140
V_fixture_max= 1.260
|time   V(typ)   V(min)   V(max)
0s        1.2V       1.14V      1.26V
194ps     1.201V     1.14V      1.258V
337ps     1.236V     1.137V     1.319V
451ps     1.262V     1.16V      1.273V
645ps     1.15V      1.185V     1.119V
815ps     996.7mV    1.073V     952.5mV
1.157ns   691.8mV    727.3mV    663.9mV
1.385ns   582.9mV    575.8mV    572.6mV
1.676ns   532.5mV    507.4mV    527.5mV
10ns      515.1mV    479.1mV    513.2mV
[Falling Waveform]
R_fixture= 50.000
V_fixture= 0.0
V_fixture_min= 0.0
V_fixture_max= 0.0
|time   V(typ)   V(min)   V(max)
0s        778.7mV    573.9mV    859.6mV
222ps     777.1mV    573.9mV    862.2mV
300ps     782mV      572.8mV    666.8mV
433ps     478.7mV    575.5mV    344.7mV
556ps     254.3mV    384.7mV    159.3mV
700ps     95.85mV    190.4mV    47.69mV
868ps     23.47mV    61.85mV    9.803mV
1.07ns    4.721mV    12.95mV    2.348mV
1.469ns   1.251mV    1.979mV    1.064mV
10ns      0V         0V         0V
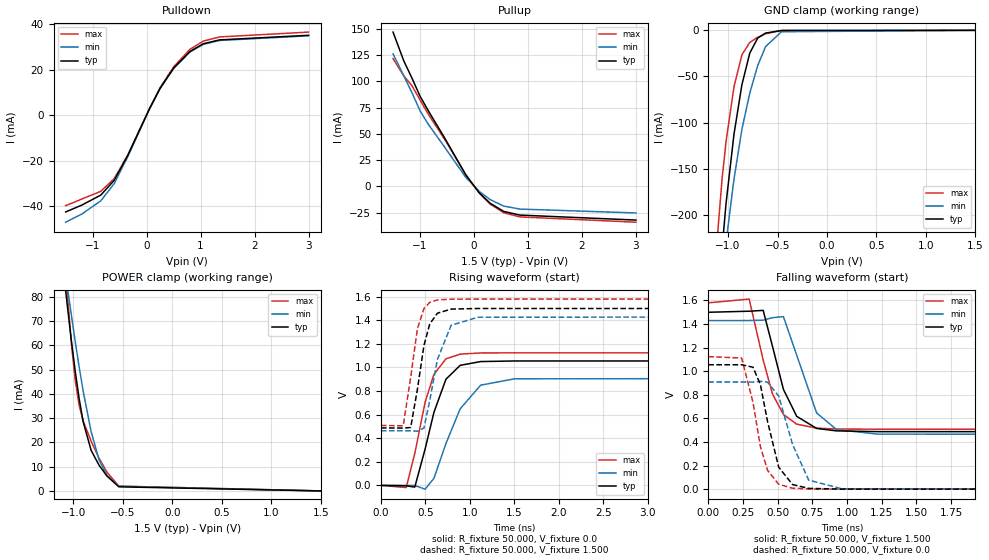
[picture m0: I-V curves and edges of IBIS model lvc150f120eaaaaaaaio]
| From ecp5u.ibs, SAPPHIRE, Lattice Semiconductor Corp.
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|   Model lvc150f120eaaaaaaaio
[Model] lvc150f120eaaaaaaaio
Model_type I/O
Polarity   Non-Inverting
Enable   Active-Low
Vinl =  0.375V
Vinh =  1.125V
Vmeas =  0.750V
Cref =  0.0F
Rref =  1.000M
Vref =  0.0V
C_comp   5.000pF   4.000pF   5.500pF
[Temperature Range]   25.000   0.125k   -40.000
[Voltage Range]   1.500V   1.430V   1.580V
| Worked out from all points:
|   slope of the pulldown table from 0 to 0.225 V, typ, clamps not added: 21 ohm
|   slope of the pullup table from 0 to 0.225 V, typ, clamps not added: 17.7 ohm
|   GND clamp passes 1 mA (typ) near -0.54 V on its own axis
|   POWER clamp passes 1 mA (typ) near -0.51 V on its own axis
|   rising waveform, R_fixture 50.000, V_fixture 0.0: 20-80 % time 227ps typ, 298ps min, 204ps max; typ from 0 V to 1.05 V
|   rising waveform, R_fixture 50.000, V_fixture 1.500: 20-80 % time 130ps typ, 162ps min, 118ps max; typ from 0.487 V to 1.5 V
|   falling waveform, R_fixture 50.000, V_fixture 1.500: 20-80 % time 149ps typ, 160ps min, 143ps max; typ from 1.5 V to 0.487 V
|   falling waveform, R_fixture 50.000, V_fixture 0.0: 20-80 % time 115ps typ, 133ps min, 105ps max; typ from 1.05 V to 0 V
[Pulldown]
|Voltage   I(typ)   I(min)   I(max)
-1.5V     -42.59mA   -47.09mA   -39.82mA
-1.2V     -39.57mA   -43.49mA   -36.91mA
-850mV    -35.19mA   -37.71mA   -33.53mA
-600mV    -28.67mA   -30.1mA    -27.92mA
-350mV    -17.76mA   -18.32mA   -17.6mA
50mV      2.612mA    2.594mA    2.654mA
250mV     11.78mA    11.69mA    12.02mA
500mV     20.64mA    20.46mA    21.18mA
800mV     27.91mA    27.63mA    28.82mA
1.05V     31.33mA    31.05mA    32.49mA
1.35V     33.02mA    32.77mA    34.32mA
3V        35.04mA    34.81mA    36.45mA
[Pullup]
|Voltage   I(typ)   I(min)   I(max)
-1.5V     146.9mA    126.2mA    121.7mA
-1.3V     119.4mA    105.3mA    105.2mA
-1.15V    103.2mA    89.23mA    95.91mA
-1V       85.93mA    72.1mA     82.36mA
-850mV    72.31mA    59.42mA    69.07mA
-550mV    46.67mA    37.82mA    45.33mA
-150mV    10.81mA    8.517mA    11.05mA
100mV     -6.214mA   -4.811mA   -6.519mA
300mV     -16.04mA   -12.52mA   -16.81mA
550mV     -23.77mA   -18.7mA    -24.99mA
850mV     -27.28mA   -21.54mA   -29.02mA
3V        -32mA      -25.22mA   -34.03mA
[GND_clamp]
|Voltage   I(typ)   I(min)   I(max)
-1.5V     -960.1mA   -762.7mA   -1.034A
-1.14V    -347.3mA   -346mA     -275mA
-1.1V     -290.2mA   -305.8mA   -213.7mA
-1.06V    -236.5mA   -267.1mA   -161mA
-1.02V    -187.7mA   -229.9mA   -120.7mA
-940mV    -112.8mA   -161.5mA   -61.34mA
-860mV    -59.06mA   -107.5mA   -26.59mA
-780mV    -24.6mA    -67.97mA   -13.06mA
-700mV    -8.431mA   -38.1mA    -7.531mA
-620mV    -2.969mA   -17.61mA   -3.668mA
-460mV    -207.8uA   -1.521mA   -211uA
1.5V      0A         0A         0A
[POWER_clamp]
|Voltage   I(typ)   I(min)   I(max)
-1.5V     267.6mA    236.4mA    479.7mA
-1.1V     90.92mA    95.54mA    105.5mA
-1.06V    76.14mA    83.93mA    81.29mA
-1.02V    62.03mA    72.49mA    60.96mA
-980mV    49.07mA    61.38mA    45.36mA
-940mV    37.73mA    50.83mA    34.98mA
-900mV    28.44mA    41.02mA    28.75mA
-820mV    16.72mA    24.41mA    20.46mA
-740mV    10.6mA     12.83mA    13.51mA
-660mV    6.131mA    6.445mA    7.75mA
-540mV    1.697mA    1.964mA    1.966mA
1.5V      0A         0A         0A
[Ramp]
| variable   typ   min   max
dV/dt_r 0.633/0.227n   0.545/0.299n   0.675/0.206n
dV/dt_f 0.608/0.153n   0.580/0.164n   0.643/0.148n
R_load = 50.000
[Rising Waveform]
R_fixture= 50.000
V_fixture= 0.0
V_fixture_min= 0.0
V_fixture_max= 0.0
|time   V(typ)   V(min)   V(max)
0s        0V         0V         0V
285ps     -3.711mV   -326.9uV   -18.48mV
381ps     -14.46mV   -1.488mV   271.3mV
497ps     308.6mV    -32.17mV   705.4mV
596ps     619.3mV    59.81mV    941.7mV
731ps     900.3mV    354.7mV    1.073V
891ps     1.018V     649.4mV    1.113V
1.121ns   1.05V      849.8mV    1.123V
1.501ns   1.055V     903.7mV    1.124V
10ns      1.055V     909mV      1.124V
[Rising Waveform]
R_fixture= 50.000
V_fixture= 1.500
V_fixture_min= 1.430
V_fixture_max= 1.580
|time   V(typ)   V(min)   V(max)
0s        487.2mV    463.2mV    508.2mV
251ps     485.9mV    463.2mV    504.8mV
335ps     490.9mV    462.4mV    917.8mV
411ps     818mV      459.3mV    1.33V
484ps     1.187V     486.7mV    1.5V
549ps     1.369V     720.3mV    1.552V
635ps     1.46V      1.068V     1.573V
790ps     1.495V     1.358V     1.579V
1.091ns   1.5V       1.426V     1.58V
10ns      1.5V       1.43V      1.58V
[Falling Waveform]
R_fixture= 50.000
V_fixture= 1.500
V_fixture_min= 1.430
V_fixture_max= 1.580
|time   V(typ)   V(min)   V(max)
0s        1.5V       1.43V      1.58V
295ps     1.509V     1.43V      1.612V
396ps     1.516V     1.433V     1.095V
463ps     1.212V     1.454V     807.2mV
542ps     845.9mV    1.463V     633.3mV
638ps     617.4mV    1.135V     551.2mV
781ps     515.1mV    647.3mV    517.4mV
925ps     494.3mV    504.6mV    510.3mV
1.225ns   487.9mV    466.6mV    508.5mV
10ns      487.2mV    463.2mV    508.2mV
[Falling Waveform]
R_fixture= 50.000
V_fixture= 0.0
V_fixture_min= 0.0
V_fixture_max= 0.0
|time   V(typ)   V(min)   V(max)
0s        1.055V     909mV      1.124V
241ps     1.055V     909mV      1.112V
323ps     1.034V     908mV      733.9mV
376ps     886.7mV    914.4mV    360.4mV
428ps     571.4mV    907.4mV    159mV
508ps     186.2mV    788.7mV    41.73mV
608ps     38.95mV    378.6mV    7.885mV
724ps     6.58mV     76.69mV    1.561mV
963ps     561.4uV    3.246mV    108.8uV
10ns      0V         0V         0V
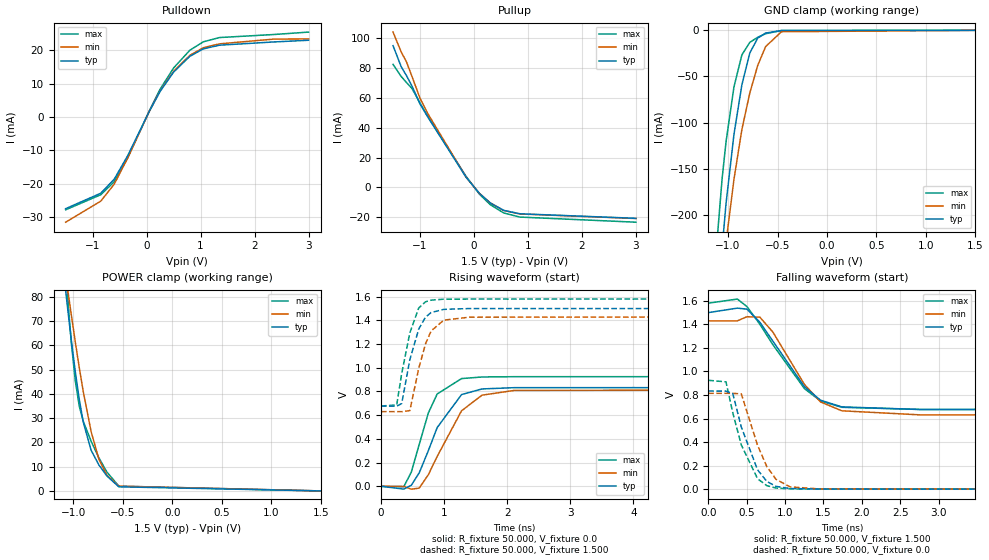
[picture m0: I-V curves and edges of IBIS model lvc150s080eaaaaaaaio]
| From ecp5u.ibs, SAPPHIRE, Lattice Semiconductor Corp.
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|   Model lvc150s080eaaaaaaaio
[Model] lvc150s080eaaaaaaaio
Model_type I/O
Polarity   Non-Inverting
Enable   Active-Low
Vinl =  0.375V
Vinh =  1.125V
Vmeas =  0.750V
Cref =  0.0F
Rref =  1.000M
Vref =  0.0V
C_comp   5.000pF   4.000pF   5.500pF
[Temperature Range]   25.000   0.125k   -40.000
[Voltage Range]   1.500V   1.430V   1.580V
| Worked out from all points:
|   slope of the pulldown table from 0 to 0.225 V, typ, clamps not added: 32.3 ohm
|   slope of the pullup table from 0 to 0.225 V, typ, clamps not added: 27.3 ohm
|   GND clamp passes 1 mA (typ) near -0.54 V on its own axis
|   POWER clamp passes 1 mA (typ) near -0.51 V on its own axis
|   rising waveform, R_fixture 50.000, V_fixture 0.0: 20-80 % time 409ps typ, 487ps min, 327ps max; typ from 0 V to 0.834 V
|   rising waveform, R_fixture 50.000, V_fixture 1.500: 20-80 % time 230ps typ, 235ps min, 210ps max; typ from 0.677 V to 1.5 V
|   falling waveform, R_fixture 50.000, V_fixture 1.500: 20-80 % time 531ps typ, 470ps min, 573ps max; typ from 1.5 V to 0.677 V
|   falling waveform, R_fixture 50.000, V_fixture 0.0: 20-80 % time 260ps typ, 270ps min, 256ps max; typ from 0.834 V to 0 V
[Pulldown]
|Voltage   I(typ)   I(min)   I(max)
-1.5V     -27.39mA   -31.43mA   -27.72mA
-850mV    -22.78mA   -25.14mA   -23.23mA
-600mV    -18.58mA   -20.07mA   -19.34mA
-350mV    -11.53mA   -12.21mA   -12.18mA
50mV      1.697mA    1.729mA    1.836mA
250mV     7.652mA    7.792mA    8.316mA
500mV     13.41mA    13.64mA    14.65mA
800mV     18.13mA    18.42mA    19.93mA
1.05V     20.35mA    20.7mA     22.46mA
1.35V     21.45mA    21.85mA    23.73mA
2.35V     22.41mA    23.26mA    24.63mA
3V        22.92mA    23.32mA    25.36mA
[Pullup]
|Voltage   I(typ)   I(min)   I(max)
-1.5V     95.01mA    104.1mA    82.46mA
-1.35V    81.01mA    90.92mA    74.41mA
-1.25V    74.86mA    84.05mA    70.27mA
-1.15V    68.02mA    74.47mA    66.36mA
-1V       55.88mA    59.73mA    56.56mA
-850mV    46.85mA    49.11mA    47.35mA
-150mV    6.997mA    7.036mA    7.57mA
100mV     -4.023mA   -3.974mA   -4.467mA
300mV     -10.39mA   -10.34mA   -11.52mA
550mV     -15.39mA   -15.45mA   -17.12mA
850mV     -17.67mA   -17.8mA    -19.88mA
3V        -20.72mA   -20.84mA   -23.31mA
[GND_clamp]
|Voltage   I(typ)   I(min)   I(max)
-1.5V     -960.1mA   -762.7mA   -1.034A
-1.14V    -347.3mA   -346mA     -275mA
-1.1V     -290.2mA   -305.8mA   -213.7mA
-1.06V    -236.5mA   -267.1mA   -161mA
-1.02V    -187.7mA   -229.9mA   -120.7mA
-940mV    -112.8mA   -161.5mA   -61.34mA
-860mV    -59.06mA   -107.5mA   -26.59mA
-780mV    -24.6mA    -67.97mA   -13.06mA
-700mV    -8.431mA   -38.1mA    -7.531mA
-620mV    -2.969mA   -17.61mA   -3.668mA
-460mV    -207.8uA   -1.521mA   -211uA
1.5V      0A         0A         0A
[POWER_clamp]
|Voltage   I(typ)   I(min)   I(max)
-1.5V     267.6mA    236.4mA    479.7mA
-1.1V     90.92mA    95.54mA    105.5mA
-1.06V    76.14mA    83.93mA    81.29mA
-1.02V    62.03mA    72.49mA    60.96mA
-980mV    49.07mA    61.38mA    45.36mA
-940mV    37.73mA    50.83mA    34.98mA
-900mV    28.44mA    41.02mA    28.75mA
-820mV    16.72mA    24.41mA    20.46mA
-740mV    10.6mA     12.83mA    13.51mA
-660mV    6.131mA    6.445mA    7.75mA
-540mV    1.697mA    1.964mA    1.966mA
1.5V      0A         0A         0A
[Ramp]
| variable   typ   min   max
dV/dt_r 0.500/0.414n   0.489/0.489n   0.555/0.333n
dV/dt_f 0.494/0.536n   0.480/0.489n   0.542/0.579n
R_load = 50.000
[Rising Waveform]
R_fixture= 50.000
V_fixture= 0.0
V_fixture_min= 0.0
V_fixture_max= 0.0
|time   V(typ)   V(min)   V(max)
0s        0V         0V         0V
363ps     -23.75mV   -946.7uV   -3.677mV
482ps     8.457mV    -24.36mV   119.4mV
608ps     114.1mV    -15.2mV    353.8mV
752ps     300.2mV    97.79mV    618.9mV
892ps     495.5mV    251.8mV    778.8mV
1.278ns   773.8mV    636.9mV    908.9mV
1.602ns   821.5mV    769mV      922.4mV
2.117ns   832.3mV    809.2mV    924.9mV
10ns      833.6mV    814.4mV    925.1mV
[Rising Waveform]
R_fixture= 50.000
V_fixture= 1.500
V_fixture_min= 1.430
V_fixture_max= 1.580
|time   V(typ)   V(min)   V(max)
0s        676.8mV    630.1mV    677mV
251ps     675.9mV    630.1mV    687mV
330ps     698.2mV    629.3mV    951.7mV
459ps     1.069V     638.7mV    1.295V
600ps     1.327V     995.5mV    1.505V
708ps     1.428V     1.203V     1.557V
795ps     1.466V     1.31V      1.571V
996ps     1.493V     1.402V     1.579V
1.398ns   1.5V       1.427V     1.58V
10ns      1.5V       1.43V      1.58V
[Falling Waveform]
R_fixture= 50.000
V_fixture= 1.500
V_fixture_min= 1.430
V_fixture_max= 1.580
|time   V(typ)   V(min)   V(max)
0s        1.5V       1.43V      1.58V
379ps     1.538V     1.43V      1.615V
504ps     1.529V     1.465V     1.551V
672ps     1.418V     1.461V     1.401V
842ps     1.257V     1.334V     1.227V
1.252ns   870mV      889.9mV    854.2mV
1.462ns   755.8mV    740.9mV    749.2mV
1.739ns   698.8mV    665.7mV    695.5mV
2.754ns   677.1mV    631.3mV    677.2mV
10ns      676.8mV    630.1mV    677mV
[Falling Waveform]
R_fixture= 50.000
V_fixture= 0.0
V_fixture_min= 0.0
V_fixture_max= 0.0
|time   V(typ)   V(min)   V(max)
0s        833.6mV    814.4mV    925.1mV
231ps     832.8mV    814.4mV    911.5mV
320ps     811.6mV    813.8mV    648.1mV
430ps     528.6mV    810mV      376.1mV
642ps     164.4mV    372.7mV    88.69mV
762ps     65.9mV     192.7mV    29.96mV
882ps     23.6mV     83.96mV    9.679mV
1.062ns   5.627mV    19.89mV    2.532mV
1.432ns   1.372mV    2.658mV    1.057mV
10ns      0V         535.1nV    0V
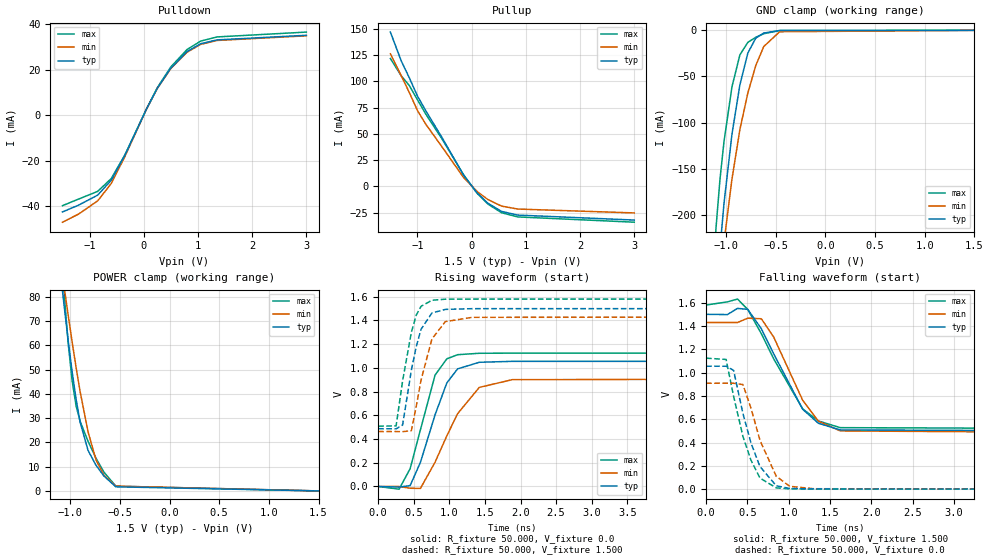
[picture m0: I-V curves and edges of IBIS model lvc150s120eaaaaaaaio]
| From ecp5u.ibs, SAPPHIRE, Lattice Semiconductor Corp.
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|   Model lvc150s120eaaaaaaaio
[Model] lvc150s120eaaaaaaaio
Model_type I/O
Polarity   Non-Inverting
Enable   Active-Low
Vinl =  0.375V
Vinh =  1.125V
Vmeas =  0.750V
Cref =  0.0F
Rref =  1.000M
Vref =  0.0V
C_comp   5.000pF   4.000pF   5.500pF
[Temperature Range]   25.000   0.125k   -40.000
[Voltage Range]   1.500V   1.430V   1.580V
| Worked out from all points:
|   slope of the pulldown table from 0 to 0.225 V, typ, clamps not added: 21 ohm
|   slope of the pullup table from 0 to 0.225 V, typ, clamps not added: 17.7 ohm
|   GND clamp passes 1 mA (typ) near -0.54 V on its own axis
|   POWER clamp passes 1 mA (typ) near -0.51 V on its own axis
|   rising waveform, R_fixture 50.000, V_fixture 0.0: 20-80 % time 344ps typ, 452ps min, 286ps max; typ from 0 V to 1.05 V
|   rising waveform, R_fixture 50.000, V_fixture 1.500: 20-80 % time 201ps typ, 220ps min, 189ps max; typ from 0.487 V to 1.5 V
|   falling waveform, R_fixture 50.000, V_fixture 1.500: 20-80 % time 438ps typ, 397ps min, 485ps max; typ from 1.5 V to 0.487 V
|   falling waveform, R_fixture 50.000, V_fixture 0.0: 20-80 % time 252ps typ, 256ps min, 249ps max; typ from 1.05 V to 0 V
[Pulldown]
|Voltage   I(typ)   I(min)   I(max)
-1.5V     -42.59mA   -47.09mA   -39.82mA
-1.2V     -39.57mA   -43.49mA   -36.91mA
-850mV    -35.19mA   -37.71mA   -33.53mA
-600mV    -28.67mA   -30.1mA    -27.92mA
-350mV    -17.76mA   -18.32mA   -17.6mA
50mV      2.612mA    2.594mA    2.654mA
250mV     11.78mA    11.69mA    12.02mA
500mV     20.64mA    20.46mA    21.18mA
800mV     27.91mA    27.63mA    28.82mA
1.05V     31.33mA    31.05mA    32.49mA
1.35V     33.02mA    32.77mA    34.32mA
3V        35.04mA    34.81mA    36.45mA
[Pullup]
|Voltage   I(typ)   I(min)   I(max)
-1.5V     146.8mA    126.1mA    121.7mA
-1.3V     119.4mA    105.3mA    105.2mA
-1.15V    103.2mA    89.22mA    95.91mA
-1V       85.93mA    72.1mA     82.36mA
-850mV    72.31mA    59.42mA    69.07mA
-550mV    46.67mA    37.82mA    45.33mA
-150mV    10.81mA    8.517mA    11.05mA
100mV     -6.214mA   -4.811mA   -6.519mA
300mV     -16.04mA   -12.52mA   -16.81mA
550mV     -23.77mA   -18.7mA    -24.99mA
850mV     -27.28mA   -21.54mA   -29.02mA
3V        -32mA      -25.22mA   -34.03mA
[GND_clamp]
|Voltage   I(typ)   I(min)   I(max)
-1.5V     -960.1mA   -762.7mA   -1.034A
-1.14V    -347.3mA   -346mA     -275mA
-1.1V     -290.2mA   -305.8mA   -213.7mA
-1.06V    -236.5mA   -267.1mA   -161mA
-1.02V    -187.7mA   -229.9mA   -120.7mA
-940mV    -112.8mA   -161.5mA   -61.34mA
-860mV    -59.06mA   -107.5mA   -26.59mA
-780mV    -24.6mA    -67.97mA   -13.06mA
-700mV    -8.431mA   -38.1mA    -7.531mA
-620mV    -2.969mA   -17.61mA   -3.668mA
-460mV    -207.8uA   -1.521mA   -211uA
1.5V      0A         0A         0A
[POWER_clamp]
|Voltage   I(typ)   I(min)   I(max)
-1.5V     267.6mA    236.4mA    479.7mA
-1.1V     90.92mA    95.54mA    105.5mA
-1.06V    76.14mA    83.93mA    81.29mA
-1.02V    62.03mA    72.49mA    60.96mA
-980mV    49.07mA    61.38mA    45.36mA
-940mV    37.73mA    50.83mA    34.98mA
-900mV    28.44mA    41.02mA    28.75mA
-820mV    16.72mA    24.41mA    20.46mA
-740mV    10.6mA     12.83mA    13.51mA
-660mV    6.131mA    6.445mA    7.75mA
-540mV    1.697mA    1.964mA    1.966mA
1.5V      0A         0A         0A
[Ramp]
| variable   typ   min   max
dV/dt_r 0.633/0.346n   0.545/0.462n   0.675/0.290n
dV/dt_f 0.608/0.446n   0.580/0.405n   0.643/0.500n
R_load = 50.000
[Rising Waveform]
R_fixture= 50.000
V_fixture= 0.0
V_fixture_min= 0.0
V_fixture_max= 0.0
|time   V(typ)   V(min)   V(max)
0s        0V         0V         0V
294ps     -4.994mV   -422.3uV   -22.58mV
449ps     7.477mV    -14.74mV   150.4mV
593ps     203.1mV    -16.42mV   477.1mV
799ps     603.6mV    204.4mV    938.7mV
964ps     872.7mV    426.3mV    1.076V
1.116ns   991.6mV    613.9mV    1.111V
1.421ns   1.047V     835.5mV    1.123V
1.885ns   1.055V     900.6mV    1.124V
10ns      1.055V     908.9mV    1.124V
[Rising Waveform]
R_fixture= 50.000
V_fixture= 1.500
V_fixture_min= 1.430
V_fixture_max= 1.580
|time   V(typ)   V(min)   V(max)
0s        487.2mV    463.2mV    508.2mV
252ps     485.9mV    463.2mV    511mV
343ps     518.3mV    462.3mV    890.4mV
466ps     980.1mV    470mV      1.299V
535ps     1.179V     675.7mV    1.445V
602ps     1.325V     896.8mV    1.519V
756ps     1.463V     1.245V     1.57V
944ps     1.493V     1.39V      1.579V
1.321ns   1.499V     1.426V     1.58V
10ns      1.5V       1.43V      1.58V
[Falling Waveform]
R_fixture= 50.000
V_fixture= 1.500
V_fixture_min= 1.430
V_fixture_max= 1.580
|time   V(typ)   V(min)   V(max)
0s        1.5V       1.43V      1.58V
258ps     1.498V     1.43V      1.607V
380ps     1.551V     1.43V      1.631V
504ps     1.543V     1.467V     1.542V
669ps     1.376V     1.462V     1.333V
819ps     1.16V      1.304V     1.117V
1.169ns   685.5mV    762.9mV    689.3mV
1.359ns   565.5mV    583.2mV    585.3mV
1.624ns   508.2mV    499.7mV    527.7mV
10ns      487.2mV    463.2mV    508.2mV
[Falling Waveform]
R_fixture= 50.000
V_fixture= 0.0
V_fixture_min= 0.0
V_fixture_max= 0.0
|time   V(typ)   V(min)   V(max)
0s        1.055V     909mV      1.124V
242ps     1.055V     909mV      1.113V
333ps     1.019V     908.6mV    796.8mV
446ps     648.6mV    897.3mV    452.1mV
543ps     396.5mV    695.4mV    248.8mV
652ps     194mV      419.4mV    95.26mV
849ps     29.36mV    110.6mV    11.11mV
1.011ns   6.285mV    24.71mV    2.82mV
1.308ns   1.948mV    3.688mV    1.355mV
10ns      0V         0V         0V
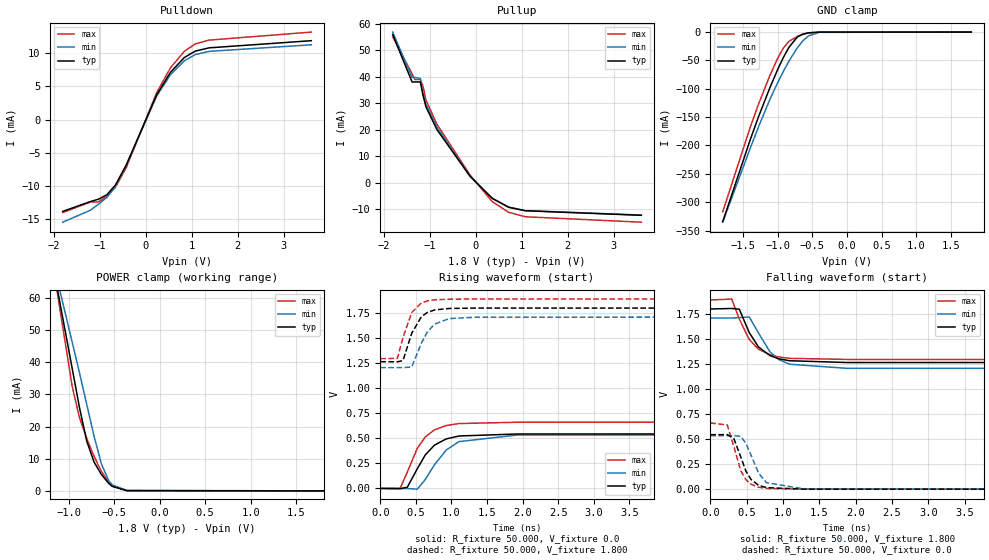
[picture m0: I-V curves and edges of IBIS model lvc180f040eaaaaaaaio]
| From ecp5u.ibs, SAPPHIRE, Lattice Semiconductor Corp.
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|   Model lvc180f040eaaaaaaaio
[Model] lvc180f040eaaaaaaaio
Model_type I/O
Polarity   Non-Inverting
Enable   Active-Low
Vinl =  0.630V
Vinh =  1.170V
Vmeas =  0.900V
Cref =  0.0F
Rref =  1.000M
Vref =  0.0V
C_comp   5.000pF   4.000pF   5.500pF
[Temperature Range]   25.000   0.125k   -40.000
[Voltage Range]   1.800V   1.710V   1.890V
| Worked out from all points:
|   slope of the pulldown table from 0 to 0.27 V, typ, clamps not added: 65.7 ohm
|   slope of the pullup table from 0 to 0.27 V, typ, clamps not added: 58.5 ohm
|   GND clamp passes 1 mA (typ) near -0.54 V on its own axis
|   POWER clamp passes 1 mA (typ) near -0.49 V on its own axis
|   rising waveform, R_fixture 50.000, V_fixture 0.0: 20-80 % time 308ps typ, 356ps min, 289ps max; typ from 0 V to 0.544 V
|   rising waveform, R_fixture 50.000, V_fixture 1.800: 20-80 % time 187ps typ, 211ps min, 167ps max; typ from 1.26 V to 1.8 V
|   falling waveform, R_fixture 50.000, V_fixture 1.800: 20-80 % time 275ps typ, 288ps min, 271ps max; typ from 1.8 V to 1.26 V
|   falling waveform, R_fixture 50.000, V_fixture 0.0: 20-80 % time 178ps typ, 202ps min, 163ps max; typ from 0.544 V to 0 V
[Pulldown]
|Voltage   I(typ)   I(min)   I(max)
-1.8V     -13.87mA   -15.5mA    -14.05mA
-1.2V     -12.39mA   -13.7mA    -12.46mA
-1.02V    -12.02mA   -12.76mA   -12.43mA
-840mV    -11.35mA   -11.76mA   -11.57mA
-660mV    -9.94mA    -10.14mA   -10.28mA
-420mV    -6.892mA   -6.861mA   -7.26mA
240mV     3.719mA    3.535mA    4.043mA
540mV     7.135mA    6.775mA    7.808mA
840mV     9.359mA    8.879mA    10.3mA
1.08V     10.34mA    9.815mA    11.42mA
1.38V     10.83mA    10.3mA     12mA
3.6V      11.91mA    11.29mA    13.21mA
[Pullup]
|Voltage   I(typ)   I(min)   I(max)
-1.8V     56.01mA    56.94mA    55.18mA
-1.38V    38.11mA    39.82mA    41.18mA
-1.32V    38.11mA    39.82mA    39.03mA
-1.2V     38.11mA    39.44mA    39.03mA
-1.14V    33.01mA    33.46mA    36.38mA
-1.08V    28.81mA    29.83mA    31.39mA
-840mV    20.13mA    21.04mA    22.15mA
-120mV    2.493mA    2.469mA    2.972mA
360mV     -5.841mA   -5.755mA   -7.05mA
720mV     -9.228mA   -9.168mA   -11.13mA
1.08V     -10.53mA   -10.48mA   -12.8mA
3.6V      -12.25mA   -12.16mA   -14.85mA
[GND_clamp]
|Voltage   I(typ)   I(min)   I(max)
-1.8V     -334.4mA   -335.3mA   -317.1mA
-1.4V     -189.3mA   -204.4mA   -167.3mA
-1.28V    -148.9mA   -166.7mA   -126.7mA
-1.12V    -99.04mA   -119.7mA   -77.45mA
-1V       -64.9mA    -88.2mA    -45.18mA
-920mV    -44.4mA    -68.92mA   -27.88mA
-840mV    -26.71mA   -51.09mA   -16.18mA
-720mV    -8.754mA   -27.82mA   -7.821mA
-640mV    -3.53mA    -15.52mA   -4.188mA
-560mV    -1.27mA    -6.791mA   -1.597mA
-400mV    -49.63uA   -425.4uA   -44.12uA
1.8V      0A         0A         0A
[POWER_clamp]
|Voltage   I(typ)   I(min)   I(max)
-1.8V     174.6mA    158.5mA    191.6mA
-1.36V    100.3mA    96.28mA    105.7mA
-1.12V    62.39mA    65.2mA     61.09mA
-960mV    38.11mA    46.28mA    32.52mA
-880mV    25.96mA    36.75mA    22.79mA
-800mV    15.45mA    26.86mA    16.3mA
-720mV    9.004mA    17.05mA    10.75mA
-640mV    5.132mA    8.487mA    6.134mA
-560mV    2.382mA    3.217mA    2.693mA
-520mV    1.425mA    1.849mA    1.506mA
-360mV    88.16uA    177.6uA    42.1uA
1.8V      0A         0A         0A
[Ramp]
| variable   typ   min   max
dV/dt_r   0.324/0.307n   0.319/0.365n   0.393/0.289n
dV/dt_f   0.321/0.278n   0.302/0.293n   0.357/0.278n
R_load = 50.000
[Rising Waveform]
R_fixture= 50.000
V_fixture= 0.0
V_fixture_min= 0.0
V_fixture_max= 0.0
|time   V(typ)   V(min)   V(max)
0s        0V         0V         0V
279ps     -2.329mV   -136.9uV   1.158mV
380ps     12.42mV    -943.8uV   162.8mV
519ps     194.9mV    -7.141mV   399.6mV
632ps     333.8mV    88.21mV    513.3mV
762ps     432.3mV    236.9mV    584.7mV
928ps     494.8mV    383.9mV    628.1mV
1.107ns   523.5mV    467.5mV    647.6mV
1.922ns   543.5mV    532.7mV    660.8mV
10ns      544mV      534.5mV    661.1mV
[Rising Waveform]
R_fixture= 50.000
V_fixture= 1.800
V_fixture_min= 1.710
V_fixture_max= 1.890
|time   V(typ)   V(min)   V(max)
0s        1.265V     1.206V     1.295V
241ps     1.264V     1.206V     1.299V
319ps     1.276V     1.206V     1.506V
442ps     1.549V     1.212V     1.755V
579ps     1.715V     1.452V     1.852V
667ps     1.759V     1.568V     1.873V
768ps     1.782V     1.641V     1.883V
968ps     1.796V     1.695V     1.889V
1.337ns   1.8V       1.709V     1.89V
10ns      1.8V       1.71V      1.89V
[Falling Waveform]
R_fixture= 50.000
V_fixture= 1.800
V_fixture_min= 1.710
V_fixture_max= 1.890
|time   V(typ)   V(min)   V(max)
0s        1.8V       1.71V      1.89V
295ps     1.805V     1.71V      1.899V
399ps     1.798V     1.713V     1.7V
536ps     1.565V     1.721V     1.495V
663ps     1.421V     1.561V     1.399V
821ps     1.335V     1.372V     1.342V
941ps     1.303V     1.296V     1.321V
1.091ns   1.283V     1.248V     1.307V
1.882ns   1.265V     1.207V     1.296V
10ns      1.265V     1.206V     1.295V
[Falling Waveform]
R_fixture= 50.000
V_fixture= 0.0
V_fixture_min= 0.0
V_fixture_max= 0.0
|time   V(typ)   V(min)   V(max)
0s        544mV      534.5mV    661.1mV
234ps     545mV      534.5mV    641.7mV
323ps     507.8mV    535.5mV    428.8mV
420ps     321.2mV    526.5mV    183.2mV
491ps     179.1mV    456.5mV    94.65mV
561ps     96.87mV    339.3mV    49.45mV
663ps     39.2mV     162.1mV    19.42mV
773ps     15.08mV    65.24mV    7.291mV
1.302ns   380.4uV    1.425mV    139.2uV
10ns      0V         0V         0V
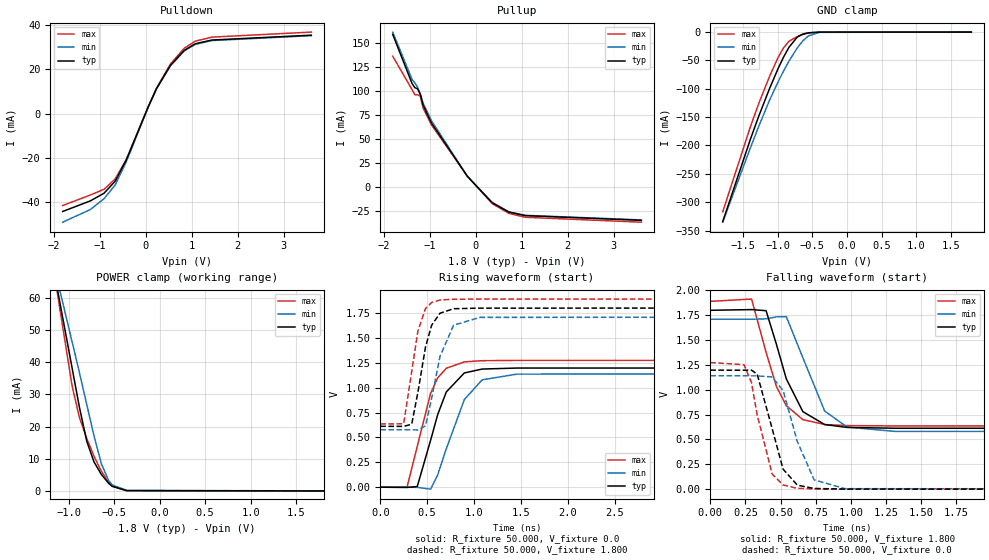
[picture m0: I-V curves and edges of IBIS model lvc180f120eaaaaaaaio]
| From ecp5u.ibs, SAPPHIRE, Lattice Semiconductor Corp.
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|   Model lvc180f120eaaaaaaaio
[Model] lvc180f120eaaaaaaaio
Model_type I/O
Polarity   Non-Inverting
Enable   Active-Low
Vinl =  0.630V
Vinh =  1.170V
Vmeas =  0.900V
Cref =  0.0F
Rref =  1.000M
Vref =  0.0V
C_comp   5.000pF   4.000pF   5.500pF
[Temperature Range]   25.000   0.125k   -40.000
[Voltage Range]   1.800V   1.710V   1.890V
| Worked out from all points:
|   slope of the pulldown table from 0 to 0.27 V, typ, clamps not added: 21.5 ohm
|   slope of the pullup table from 0 to 0.27 V, typ, clamps not added: 20.5 ohm
|   GND clamp passes 1 mA (typ) near -0.54 V on its own axis
|   POWER clamp passes 1 mA (typ) near -0.49 V on its own axis
|   rising waveform, R_fixture 50.000, V_fixture 0.0: 20-80 % time 230ps typ, 264ps min, 209ps max; typ from 0 V to 1.2 V
|   rising waveform, R_fixture 50.000, V_fixture 1.800: 20-80 % time 140ps typ, 160ps min, 120ps max; typ from 0.612 V to 1.8 V
|   falling waveform, R_fixture 50.000, V_fixture 1.800: 20-80 % time 171ps typ, 181ps min, 166ps max; typ from 1.8 V to 0.612 V
|   falling waveform, R_fixture 50.000, V_fixture 0.0: 20-80 % time 115ps typ, 136ps min, 107ps max; typ from 1.2 V to 0 V
[Pulldown]
|Voltage   I(typ)   I(min)   I(max)
-1.8V     -44.35mA   -49.21mA   -41.67mA
-1.2V     -39.57mA   -43.49mA   -36.91mA
-900mV    -36.06mA   -38.52mA   -34.28mA
-660mV    -30.62mA   -32.33mA   -29.62mA
-420mV    -21.11mA   -21.89mA   -20.84mA
60mV      3.118mA    3.096mA    3.169mA
240mV     11.37mA    11.28mA    11.6mA
540mV     21.82mA    21.62mA    22.4mA
840mV     28.62mA    28.33mA    29.57mA
1.08V     31.6mA     31.31mA    32.77mA
1.44V     33.27mA    33.03mA    34.59mA
3.6V      35.47mA    35.25mA    36.87mA
[Pullup]
|Voltage   I(typ)   I(min)   I(max)
-1.8V     158.9mA    161.3mA    136.2mA
-1.38V    107.7mA    112mA      101.3mA
-1.32V    103.4mA    108.4mA    95.98mA
-1.26V    102.1mA    103.9mA    95.98mA
-1.2V     96.41mA    96.5mA     94.37mA
-1.14V    84.99mA    87.29mA    82.11mA
-960mV    66.58mA    69.12mA    64.56mA
-180mV    10.92mA    10.85mA    11.24mA
360mV     -16.7mA    -16.38mA   -17.56mA
720mV     -26.4mA    -26.09mA   -27.73mA
1.08V     -30.14mA   -29.82mA   -31.87mA
3.6V      -35.05mA   -34.61mA   -36.99mA
[GND_clamp]
|Voltage   I(typ)   I(min)   I(max)
-1.8V     -334.4mA   -335.3mA   -317.1mA
-1.4V     -189.3mA   -204.4mA   -167.3mA
-1.28V    -148.9mA   -166.7mA   -126.7mA
-1.12V    -99.04mA   -119.7mA   -77.45mA
-1V       -64.9mA    -88.2mA    -45.18mA
-920mV    -44.4mA    -68.92mA   -27.88mA
-840mV    -26.71mA   -51.09mA   -16.18mA
-720mV    -8.754mA   -27.82mA   -7.821mA
-640mV    -3.53mA    -15.52mA   -4.188mA
-560mV    -1.27mA    -6.791mA   -1.597mA
-400mV    -49.63uA   -425.4uA   -44.12uA
1.8V      0A         0A         0A
[POWER_clamp]
|Voltage   I(typ)   I(min)   I(max)
-1.8V     174.6mA    158.5mA    191.6mA
-1.36V    100.3mA    96.28mA    105.7mA
-1.12V    62.39mA    65.2mA     61.09mA
-960mV    38.11mA    46.28mA    32.52mA
-880mV    25.96mA    36.75mA    22.79mA
-800mV    15.45mA    26.86mA    16.3mA
-720mV    9.004mA    17.05mA    10.75mA
-640mV    5.132mA    8.487mA    6.134mA
-560mV    2.382mA    3.217mA    2.693mA
-520mV    1.425mA    1.849mA    1.506mA
-360mV    88.16uA    177.6uA    42.1uA
1.8V      0A         0A         0A
[Ramp]
| variable   typ   min   max
dV/dt_r 0.719/0.233n   0.684/0.266n   0.764/0.210n
dV/dt_f 0.713/0.173n   0.679/0.185n   0.752/0.167n
R_load = 50.000
[Rising Waveform]
R_fixture= 50.000
V_fixture= 0.0
V_fixture_min= 0.0
V_fixture_max= 0.0
|time   V(typ)   V(min)   V(max)
0s        0V         0V         0V
285ps     -2.369mV   -204.9uV   1.232mV
394ps     7.143mV    -1.553mV   411.2mV
537ps     473.9mV    -19.6mV    944.8mV
612ps     730.3mV    124.1mV    1.099V
704ps     957.7mV    387.5mV    1.195V
896ps     1.148V     880.6mV    1.259V
1.086ns   1.187V     1.079V     1.271V
1.457ns   1.197V     1.136V     1.274V
10ns      1.198V     1.141V     1.274V
[Rising Waveform]
R_fixture= 50.000
V_fixture= 1.800
V_fixture_min= 1.710
V_fixture_max= 1.890
|time   V(typ)   V(min)   V(max)
0s        611.8mV    577.6mV    636mV
249ps     611mV      577.6mV    636.8mV
335ps     632.9mV    577mV      1.162V
401ps     953.6mV    575.4mV    1.57V
482ps     1.408V     615.4mV    1.795V
548ps     1.629V     896.8mV    1.856V
637ps     1.748V     1.316V     1.881V
781ps     1.793V     1.627V     1.888V
1.061ns   1.799V     1.706V     1.89V
10ns      1.8V       1.71V      1.89V
[Falling Waveform]
R_fixture= 50.000
V_fixture= 1.800
V_fixture_min= 1.710
V_fixture_max= 1.890
|time   V(typ)   V(min)   V(max)
0s        1.8V       1.71V      1.89V
294ps     1.807V     1.71V      1.913V
397ps     1.796V     1.714V     1.377V
471ps     1.456V     1.734V     1.032V
541ps     1.11V      1.736V     839.7mV
659ps     780mV      1.322V     700.1mV
814ps     650.3mV    786.3mV    650.3mV
973ps     621.4mV    624.8mV    640mV
1.313ns   613.2mV    581.3mV    636.4mV
10ns      611.8mV    577.6mV    636mV
[Falling Waveform]
R_fixture= 50.000
V_fixture= 0.0
V_fixture_min= 0.0
V_fixture_max= 0.0
|time   V(typ)   V(min)   V(max)
0s        1.198V     1.141V     1.274V
240ps     1.197V     1.141V     1.253V
293ps     1.198V     1.14V      1.073V
334ps     1.157V     1.14V      746.9mV
440ps     611mV      1.129V     152.9mV
518ps     201.7mV    992.3mV    41.6mV
620ps     40.1mV     477.5mV    8.677mV
739ps     6.928mV    93.55mV    2.14mV
959ps     1.176mV    4.74mV     392.8uV
10ns      0V         0V         0V
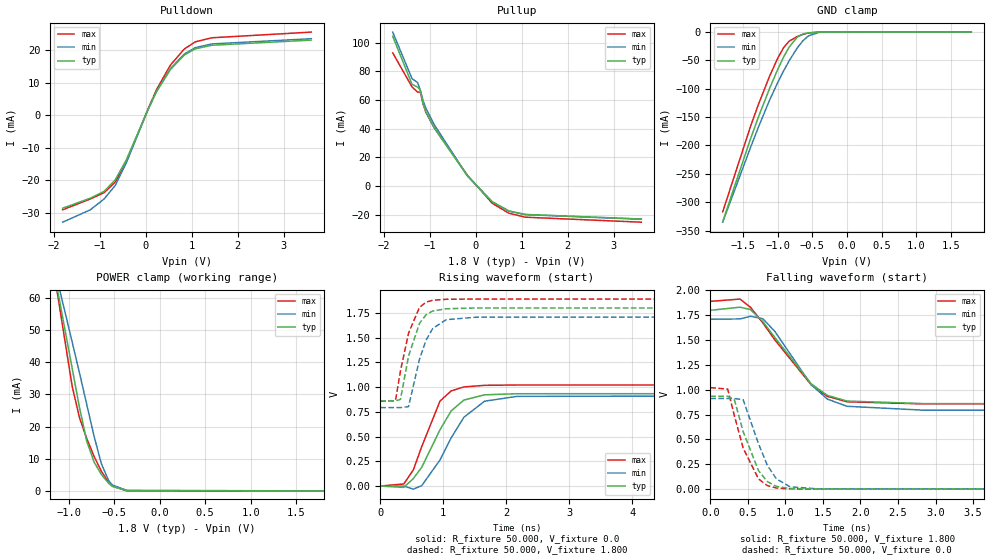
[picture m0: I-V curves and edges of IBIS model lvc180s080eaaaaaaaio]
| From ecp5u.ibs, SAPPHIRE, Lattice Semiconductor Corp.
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|   Model lvc180s080eaaaaaaaio
[Model] lvc180s080eaaaaaaaio
Model_type I/O
Polarity   Non-Inverting
Enable   Active-Low
Vinl =  0.630V
Vinh =  1.170V
Vmeas =  0.900V
Cref =  0.0F
Rref =  1.000M
Vref =  0.0V
C_comp   5.000pF   4.000pF   5.500pF
[Temperature Range]   25.000   0.125k   -40.000
[Voltage Range]   1.800V   1.710V   1.890V
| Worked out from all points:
|   slope of the pulldown table from 0 to 0.27 V, typ, clamps not added: 33.1 ohm
|   slope of the pullup table from 0 to 0.27 V, typ, clamps not added: 31.2 ohm
|   GND clamp passes 1 mA (typ) near -0.54 V on its own axis
|   POWER clamp passes 1 mA (typ) near -0.49 V on its own axis
|   rising waveform, R_fixture 50.000, V_fixture 0.0: 20-80 % time 456ps typ, 496ps min, 353ps max; typ from 0 V to 0.934 V
|   rising waveform, R_fixture 50.000, V_fixture 1.800: 20-80 % time 226ps typ, 253ps min, 221ps max; typ from 0.86 V to 1.8 V
|   falling waveform, R_fixture 50.000, V_fixture 1.800: 20-80 % time 584ps typ, 520ps min, 635ps max; typ from 1.8 V to 0.86 V
|   falling waveform, R_fixture 50.000, V_fixture 0.0: 20-80 % time 260ps typ, 271ps min, 254ps max; typ from 0.934 V to 0 V
[Pulldown]
|Voltage   I(typ)   I(min)   I(max)
-1.8V     -28.53mA   -32.84mA   -29.01mA
-1.2V     -25.46mA   -29.03mA   -25.7mA
-900mV    -23.35mA   -25.68mA   -23.75mA
-660mV    -19.84mA   -21.55mA   -20.51mA
-420mV    -13.7mA    -14.59mA   -14.42mA
60mV      2.026mA    2.064mA    2.192mA
240mV     7.384mA    7.52mA     8.023mA
540mV     14.17mA    14.41mA    15.5mA
840mV     18.59mA    18.89mA    20.45mA
1.08V     20.52mA    20.88mA    22.66mA
1.44V     21.61mA    22.02mA    23.91mA
3.6V      23.2mA     23.62mA    25.66mA
[Pullup]
|Voltage   I(typ)   I(min)   I(max)
-1.8V     104.4mA    107.3mA    92.82mA
-1.38V    70.9mA     74.87mA    69.09mA
-1.26V    68.99mA    72.12mA    65.48mA
-1.2V     66.93mA    66.81mA    65.48mA
-1.14V    57.38mA    59.48mA    57.36mA
-1.08V    51.83mA    54.35mA    51.48mA
-900mV    40.67mA    42.94mA    40.69mA
-180mV    7.161mA    7.234mA    7.646mA
360mV     -10.95mA   -10.92mA   -11.94mA
720mV     -17.31mA   -17.4mA    -18.86mA
1.08V     -19.76mA   -19.89mA   -21.68mA
3.6V      -22.97mA   -23.08mA   -25.16mA
[GND_clamp]
|Voltage   I(typ)   I(min)   I(max)
-1.8V     -334.4mA   -335.3mA   -317.1mA
-1.4V     -189.3mA   -204.4mA   -167.3mA
-1.28V    -148.9mA   -166.7mA   -126.7mA
-1.12V    -99.04mA   -119.7mA   -77.45mA
-1V       -64.9mA    -88.2mA    -45.18mA
-920mV    -44.4mA    -68.92mA   -27.88mA
-840mV    -26.71mA   -51.09mA   -16.18mA
-720mV    -8.754mA   -27.82mA   -7.821mA
-640mV    -3.53mA    -15.52mA   -4.188mA
-560mV    -1.27mA    -6.791mA   -1.597mA
-400mV    -49.63uA   -425.4uA   -44.12uA
1.8V      0A         0A         0A
[POWER_clamp]
|Voltage   I(typ)   I(min)   I(max)
-1.8V     174.6mA    158.5mA    191.6mA
-1.36V    100.3mA    96.28mA    105.7mA
-1.12V    62.39mA    65.2mA     61.09mA
-960mV    38.11mA    46.28mA    32.52mA
-880mV    25.96mA    36.75mA    22.79mA
-800mV    15.45mA    26.86mA    16.3mA
-720mV    9.004mA    17.05mA    10.75mA
-640mV    5.132mA    8.487mA    6.134mA
-560mV    2.382mA    3.217mA    2.693mA
-520mV    1.425mA    1.849mA    1.506mA
-360mV    88.16uA    177.6uA    42.1uA
1.8V      0A         0A         0A
[Ramp]
| variable   typ   min   max
dV/dt_r 0.561/0.465n   0.547/0.507n   0.613/0.354n
dV/dt_f 0.564/0.599n   0.550/0.531n   0.620/0.643n
R_load = 50.000
[Rising Waveform]
R_fixture= 50.000
V_fixture= 0.0
V_fixture_min= 0.0
V_fixture_max= 0.0
|time   V(typ)   V(min)   V(max)
0s        0V         0V         0V
373ps     -13.84mV   -622.3uV   20.67mV
525ps     75.33mV    -31.78mV   162.8mV
658ps     189mV      3.753mV    397.8mV
949ps     569mV      263.7mV    858.7mV
1.127ns   760mV      487.9mV    961.8mV
1.329ns   869.1mV    695.7mV    1.002V
1.657ns   922mV      857.5mV    1.018V
2.172ns   933mV      906.4mV    1.021V
10ns      934.5mV    912.4mV    1.022V
[Rising Waveform]
R_fixture= 50.000
V_fixture= 1.800
V_fixture_min= 1.710
V_fixture_max= 1.890
|time   V(typ)   V(min)   V(max)
0s        860mV      793.1mV    857.1mV
241ps     859.4mV    793.1mV    862.2mV
321ps     875.9mV    792.7mV    1.165V
449ps     1.314V     802.6mV    1.545V
623ps     1.645V     1.282V     1.807V
729ps     1.732V     1.476V     1.859V
832ps     1.769V     1.592V     1.878V
1.049ns   1.792V     1.682V     1.888V
1.529ns   1.8V       1.707V     1.89V
10ns      1.8V       1.71V      1.89V
[Falling Waveform]
R_fixture= 50.000
V_fixture= 1.800
V_fixture_min= 1.710
V_fixture_max= 1.890
|time   V(typ)   V(min)   V(max)
0s        1.8V       1.71V      1.89V
396ps     1.831V     1.713V     1.913V
536ps     1.807V     1.74V      1.83V
700ps     1.686V     1.715V     1.673V
860ps     1.526V     1.587V     1.502V
1.345ns   1.059V     1.05V      1.049V
1.56ns    943.1mV    906mV      933.6mV
1.821ns   886.5mV    834mV      879.1mV
2.852ns   860.5mV    794.4mV    857.5mV
10ns      860mV      793.1mV    857.1mV
[Falling Waveform]
R_fixture= 50.000
V_fixture= 0.0
V_fixture_min= 0.0
V_fixture_max= 0.0
|time   V(typ)   V(min)   V(max)
0s        934.5mV    912.4mV    1.022V
232ps     934.8mV    912.4mV    1.007V
321ps     899.4mV    912.1mV    740.2mV
438ps     579.8mV    900.2mV    412.2mV
642ps     186.2mV    457.6mV    103.3mV
760ps     76.64mV    240.2mV    35.79mV
879ps     28.1mV     104.9mV    11.78mV
1.06ns    6.621mV    24.3mV     3.046mV
1.428ns   1.58mV     3.197mV    1.122mV
10ns      0V         0V         0V
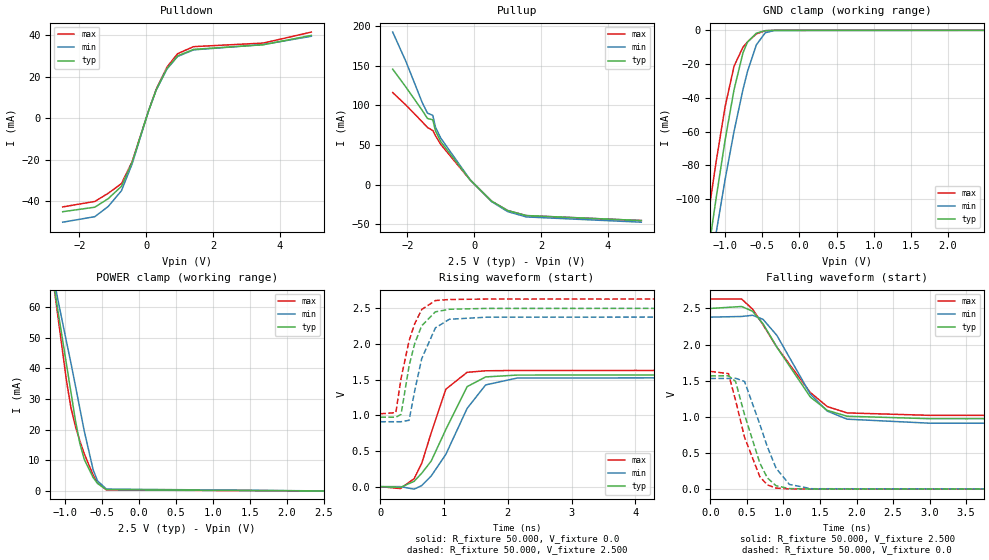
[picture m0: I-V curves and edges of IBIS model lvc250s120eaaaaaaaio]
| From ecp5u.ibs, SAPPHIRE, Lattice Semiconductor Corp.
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|   Model lvc250s120eaaaaaaaio
[Model] lvc250s120eaaaaaaaio
Model_type I/O
Polarity   Non-Inverting
Enable   Active-Low
Vinl =  0.700V
Vinh =  1.700V
Vmeas =  1.250V
Cref =  0.0F
Rref =  1.000M
Vref =  0.0V
C_comp   5.000pF   4.000pF   5.500pF
[Temperature Range]   25.000   0.125k   -40.000
[Voltage Range]   2.500V   2.380V   2.630V
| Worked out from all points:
|   slope of the pulldown table from 0 to 0.375 V, typ, clamps not added: 22.6 ohm
|   slope of the pullup table from 0 to 0.375 V, typ, clamps not added: 23.7 ohm
|   GND clamp passes 1 mA (typ) near -0.54 V on its own axis
|   POWER clamp passes 1 mA (typ) near -0.49 V on its own axis
|   rising waveform, R_fixture 50.000, V_fixture 0.0: 20-80 % time 483ps typ, 508ps min, 346ps max; typ from 0 V to 1.57 V
|   rising waveform, R_fixture 50.000, V_fixture 2.500: 20-80 % time 243ps typ, 255ps min, 253ps max; typ from 0.973 V to 2.5 V
|   falling waveform, R_fixture 50.000, V_fixture 2.500: 20-80 % time 586ps typ, 523ps min, 663ps max; typ from 2.5 V to 0.973 V
|   falling waveform, R_fixture 50.000, V_fixture 0.0: 20-80 % time 284ps typ, 314ps min, 272ps max; typ from 1.57 V to 0 V
[Pulldown]
|Voltage   I(typ)   I(min)   I(max)
-2.5V     -45.07mA   -50.12mA   -42.75mA
-1.54V    -42.89mA   -47.46mA   -40.12mA
-1.14V    -38.8mA    -42.57mA   -36.2mA
-740mV    -32.8mA    -34.91mA   -31.49mA
-420mV    -21.11mA   -21.89mA   -20.84mA
60mV      3.118mA    3.096mA    3.169mA
300mV     13.77mA    13.66mA    14.07mA
620mV     23.97mA    23.74mA    24.66mA
940mV     30.11mA    29.82mA    31.17mA
1.42V     33.22mA    32.98mA    34.53mA
3.5V      35.44mA    35.53mA    36.25mA
4.94V     39.95mA    39.54mA    41.55mA
[Pullup]
|Voltage   I(typ)   I(min)   I(max)
-2.44V    145.8mA    192.6mA    116.3mA
-2.04V    122.9mA    155.1mA    100.3mA
-1.56V    93.98mA    104mA      79.5mA
-1.4V     83.62mA    90.33mA    72.23mA
-1.24V    81.93mA    87.51mA    68.33mA
-1.16V    67.84mA    72.48mA    61.87mA
-1V       54.24mA    58.71mA    50.67mA
-120mV    5.946mA    6.135mA    5.92mA
520mV     -20.73mA   -21.37mA   -20.78mA
1V        -32.6mA    -33.92mA   -32.6mA
1.56V     -38.91mA   -40.68mA   -39.04mA
5V        -45.23mA   -47.3mA    -45.24mA
[GND_clamp]
|Voltage   I(typ)   I(min)   I(max)
-2.5V     -600.3mA   -576.2mA   -594.4mA
-1.24V    -136mA     -154.5mA   -113.9mA
-1.18V    -117.2mA   -136.7mA   -95.27mA
-1.12V    -99.04mA   -119.7mA   -77.45mA
-1V       -64.9mA    -88.21mA   -45.19mA
-880mV    -35.12mA   -59.82mA   -21.21mA
-760mV    -13.33mA   -35.03mA   -10mA
-700mV    -7.01mA    -24.46mA   -6.829mA
-580mV    -1.679mA   -8.593mA   -2.127mA
-460mV    -210.1uA   -1.441mA   -213.7uA
-340mV    -8.598uA   -109.2uA   -6.553uA
2.48V     0A         0A         0A
[POWER_clamp]
|Voltage   I(typ)   I(min)   I(max)
-2.48V    301.8mA    269mA      334.4mA
-1.16V    68.59mA    70.21mA    68.47mA
-1.1V     59.33mA    62.74mA    57.51mA
-980mV    41.18mA    48.59mA    35.82mA
-920mV    32.13mA    41.65mA    27.11mA
-860mV    23.04mA    34.34mA    21.08mA
-800mV    15.49mA    26.9mA     16.35mA
-740mV    10.29mA    19.52mA    12.1mA
-620mV    4.381mA    6.888mA    5.184mA
-560mV    2.412mA    3.25mA     2.719mA
-440mV    397.7uA    604uA      311uA
2.5V      0A         0A         0A
[Ramp]
| variable   typ   min   max
dV/dt_r 0.940/0.491n   0.919/0.522n   0.978/0.357n
dV/dt_f 0.916/0.594n   0.882/0.527n   0.965/0.667n
R_load = 50.000
[Rising Waveform]
R_fixture= 50.000
V_fixture= 0.0
V_fixture_min= 0.0
V_fixture_max= 0.0
|time   V(typ)   V(min)   V(max)
0s        0V         0V         0V
315ps     -11.33mV   -168.5uV   -27.9mV
531ps     74.25mV    -36.01mV   111.7mV
650ps     187.7mV    13.88mV    325.3mV
799ps     359.2mV    149.4mV    755.6mV
1.028ns   800.9mV    452.2mV    1.366V
1.362ns   1.402V     1.097V     1.603V
1.652ns   1.538V     1.426V     1.624V
2.144ns   1.564V     1.522V     1.629V
10ns      1.567V     1.532V     1.63V
[Rising Waveform]
R_fixture= 50.000
V_fixture= 2.500
V_fixture_min= 2.380
V_fixture_max= 2.630
|time   V(typ)   V(min)   V(max)
0s        973.5mV    909.7mV    1.021V
244ps     973.1mV    909.7mV    1.037V
326ps     1.013V     909.4mV    1.519V
452ps     1.694V     930.1mV    2.047V
540ps     2.008V     1.344V     2.285V
650ps     2.256V     1.795V     2.484V
864ps     2.451V     2.226V     2.609V
1.084ns   2.487V     2.347V     2.624V
1.67ns    2.499V     2.376V     2.63V
10ns      2.5V       2.38V      2.63V
[Falling Waveform]
R_fixture= 50.000
V_fixture= 2.500
V_fixture_min= 2.380
V_fixture_max= 2.630
|time   V(typ)   V(min)   V(max)
0s        2.5V       2.38V      2.63V
429ps     2.527V     2.389V     2.63V
578ps     2.462V     2.406V     2.491V
721ps     2.289V     2.35V      2.275V
911ps     1.964V     2.127V     1.964V
1.368ns   1.275V     1.316V     1.337V
1.6ns     1.09V      1.08V      1.143V
1.87ns    1.009V     968.5mV    1.055V
3.01ns    974.7mV    912.3mV    1.021V
10ns      973.5mV    909.7mV    1.021V
[Falling Waveform]
R_fixture= 50.000
V_fixture= 0.0
V_fixture_min= 0.0
V_fixture_max= 0.0
|time   V(typ)   V(min)   V(max)
0s        1.567V     1.532V     1.63V
249ps     1.569V     1.532V     1.598V
346ps     1.49V      1.534V     1.229V
469ps     1.029V     1.49V      717.4mV
677ps     363.3mV    899.6mV    173mV
780ps     156.9mV    588.3mV    59.33mV
900ps     47.1mV     289.8mV    15.18mV
1.082ns   7.941mV    65.53mV    3.066mV
1.384ns   2.033mV    6.038mV    1.34mV
10ns      0V         0V         0V
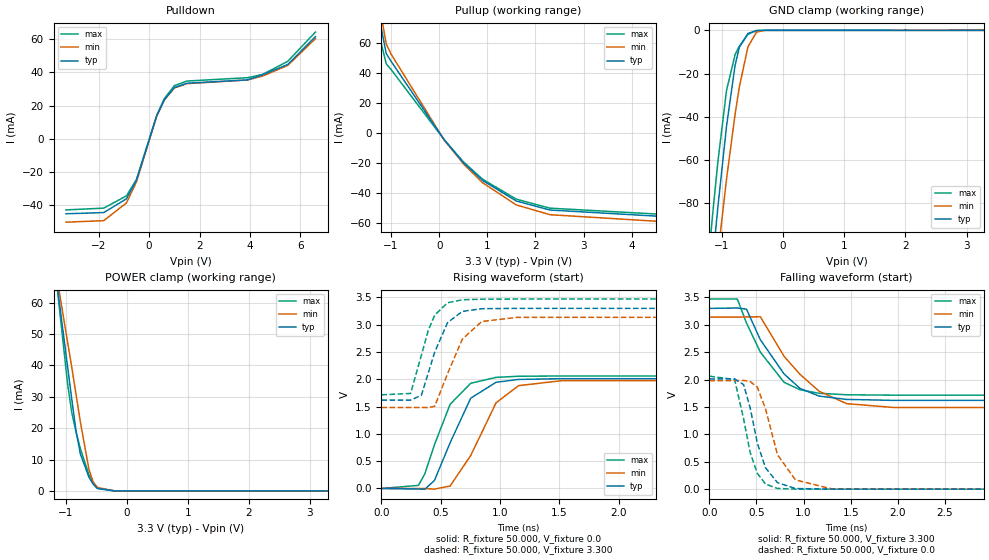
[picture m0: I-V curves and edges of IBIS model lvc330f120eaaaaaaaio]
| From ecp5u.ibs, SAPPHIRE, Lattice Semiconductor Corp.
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|   Model lvc330f120eaaaaaaaio
[Model] lvc330f120eaaaaaaaio
Model_type I/O
Polarity   Non-Inverting
Enable   Active-Low
Vinl =  0.800V
Vinh =  2.000V
Vmeas =  1.650V
Cref =  0.0F
Rref =  1.000M
Vref =  0.0V
C_comp   5.000pF   4.000pF   5.500pF
[Temperature Range]   25.000   0.125k   -40.000
[Voltage Range]   3.300V   3.140V   3.470V
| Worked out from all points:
|   slope of the pulldown table from 0 to 0.495 V, typ, clamps not added: 24.2 ohm
|   slope of the pullup table from 0 to 0.495 V, typ, clamps not added: 25.4 ohm
|   GND clamp passes 1 mA (typ) near -0.54 V on its own axis
|   POWER clamp passes 1 mA (typ) near -0.49 V on its own axis
|   rising waveform, R_fixture 50.000, V_fixture 0.0: 20-80 % time 231ps typ, 266ps min, 218ps max; typ from 0 V to 2.01 V
|   rising waveform, R_fixture 50.000, V_fixture 3.300: 20-80 % time 162ps typ, 191ps min, 142ps max; typ from 1.62 V to 3.3 V
|   falling waveform, R_fixture 50.000, V_fixture 3.300: 20-80 % time 400ps typ, 492ps min, 339ps max; typ from 3.3 V to 1.62 V
|   falling waveform, R_fixture 50.000, V_fixture 0.0: 20-80 % time 174ps typ, 208ps min, 151ps max; typ from 2.01 V to 0 V
[Pulldown]
|Voltage   I(typ)   I(min)   I(max)
-3.3V     -45.07mA   -50.13mA   -42.75mA
-1.8V     -44.35mA   -49.21mA   -41.67mA
-900mV    -36.06mA   -38.52mA   -34.28mA
-500mV    -24.74mA   -25.78mA   -24.33mA
300mV     13.77mA    13.66mA    14.07mA
600mV     23.46mA    23.24mA    24.12mA
1V        30.83mA    30.54mA    31.94mA
1.5V      33.4mA     33.17mA    34.73mA
3.9V      35.43mA    35.37mA    36.75mA
4.5V      38.49mA    37.71mA    38.7mA
5.5V      44.71mA    44.12mA    46.58mA
6.6V      61.45mA    60.23mA    64.17mA
[Pullup]
|Voltage   I(typ)   I(min)   I(max)
-3.3V     151.1mA    218mA      117.3mA
-2.3V     110.2mA    146.2mA    89.03mA
-1.4V     69.13mA    80.22mA    59.03mA
-1.2V     69.13mA    77.28mA    59.03mA
-1.1V     52.93mA    59.34mA    46.15mA
-1V       47.8mA     52.6mA     42.33mA
100mV     -4.377mA   -4.525mA   -4.284mA
500mV     -19.65mA   -20.46mA   -19.16mA
900mV     -31.58mA   -33.1mA    -30.74mA
1.6V      -45.31mA   -47.9mA    -44.09mA
2.3V      -51.33mA   -54.44mA   -50.09mA
6.6V      -59.22mA   -62.94mA   -57.69mA
[GND_clamp]
|Voltage   I(typ)   I(min)   I(max)
-3.3V     -912.7mA   -861.5mA   -922.5mA
-1.27V    -145.6mA   -163.6mA   -123.5mA
-1.2V     -123.4mA   -142.6mA   -101.4mA
-1.13V    -102mA     -122.4mA   -80.37mA
-1.06V    -81.56mA   -103.5mA   -60.64mA
-920mV    -44.4mA    -68.93mA   -27.87mA
-780mV    -16.18mA   -38.86mA   -11.24mA
-710mV    -7.839mA   -26.12mA   -7.318mA
-570mV    -1.464mA   -7.654mA   -1.852mA
-430mV    -105.8uA   -801.1uA   -99.73uA
-290mV    -1.56uA    -33.42uA   -868.4nA
3.28V     0A         0A         0A
[POWER_clamp]
|Voltage   I(typ)   I(min)   I(max)
-3.28V    471.5mA    421.2mA    516.6mA
-1.18V    71.72mA    72.75mA    72.14mA
-1.11V    60.88mA    63.98mA    59.38mA
-970mV    39.73mA    47.46mA    34.21mA
-900mV    29.12mA    39.28mA    24.89mA
-830mV    19.01mA    30.67mA    18.7mA
-760mV    11.8mA     22.01mA    13.51mA
-620mV    4.416mA    6.921mA    5.219mA
-550mV    2.174mA    2.865mA    2.414mA
-480mV    813uA      1.102mA    758.3uA
-200mV    3.62uA     22.61uA    424nA
3.3V      0A         0A         0A
[Ramp]
| variable   typ   min   max
dV/dt_r 1.207/0.233n   1.189/0.269n   1.237/0.218n
dV/dt_f 1.008/0.408n   0.994/0.499n   1.053/0.343n
R_load = 50.000
[Rising Waveform]
R_fixture= 50.000
V_fixture= 0.0
V_fixture_min= 0.0
V_fixture_max= 0.0
|time   V(typ)   V(min)   V(max)
0s        0V         0V         0V
312ps     -9.786mV   -123.4uV   56.98mV
367ps     -12.45mV   -588.9uV   273.2mV
447ps     147.2mV    -12.26mV   801.5mV
579ps     837mV      44.92mV    1.542V
753ps     1.655V     604.7mV    1.927V
967ps     1.946V     1.571V     2.036V
1.157ns   1.998V     1.884V     2.056V
1.52ns    2.011V     1.975V     2.061V
10ns      2.012V     1.981V     2.062V
[Rising Waveform]
R_fixture= 50.000
V_fixture= 3.300
V_fixture_min= 3.140
V_fixture_max= 3.470
|time   V(typ)   V(min)   V(max)
0s        1.619V     1.483V     1.716V
246ps     1.619V     1.483V     1.741V
337ps     1.708V     1.483V     2.442V
394ps     2.11V      1.482V     2.89V
449ps     2.496V     1.505V     3.176V
557ps     3.037V     2.101V     3.402V
682ps     3.244V     2.736V     3.457V
846ps     3.293V     3.059V     3.468V
1.143ns   3.3V       3.135V     3.47V
10ns      3.3V       3.14V      3.47V
[Falling Waveform]
R_fixture= 50.000
V_fixture= 3.300
V_fixture_min= 3.140
V_fixture_max= 3.470
|time   V(typ)   V(min)   V(max)
0s        3.3V       3.14V      3.47V
297ps     3.307V     3.14V      3.47V
394ps     3.286V     3.144V     3.034V
541ps     2.728V     3.147V     2.501V
793ps     2.102V     2.424V     1.95V
963ps     1.838V     2.094V     1.814V
1.165ns   1.699V     1.788V     1.75V
1.456ns   1.638V     1.561V     1.723V
1.956ns   1.621V     1.491V     1.716V
10ns      1.619V     1.483V     1.716V
[Falling Waveform]
R_fixture= 50.000
V_fixture= 0.0
V_fixture_min= 0.0
V_fixture_max= 0.0
|time   V(typ)   V(min)   V(max)
0s        2.012V     1.981V     2.062V
268ps     2.014V     1.981V     2.002V
364ps     1.907V     1.985V     1.279V
433ps     1.484V     1.964V     668.3mV
509ps     841.9mV    1.861V     289mV
595ps     392.1mV    1.472V     94.25mV
723ps     118.6mV    628mV      13.12mV
914ps     11.52mV    167.9mV    1.169mV
1.297ns   411.8uV    5.666mV    46.7uV
10ns      0V         0V         0V
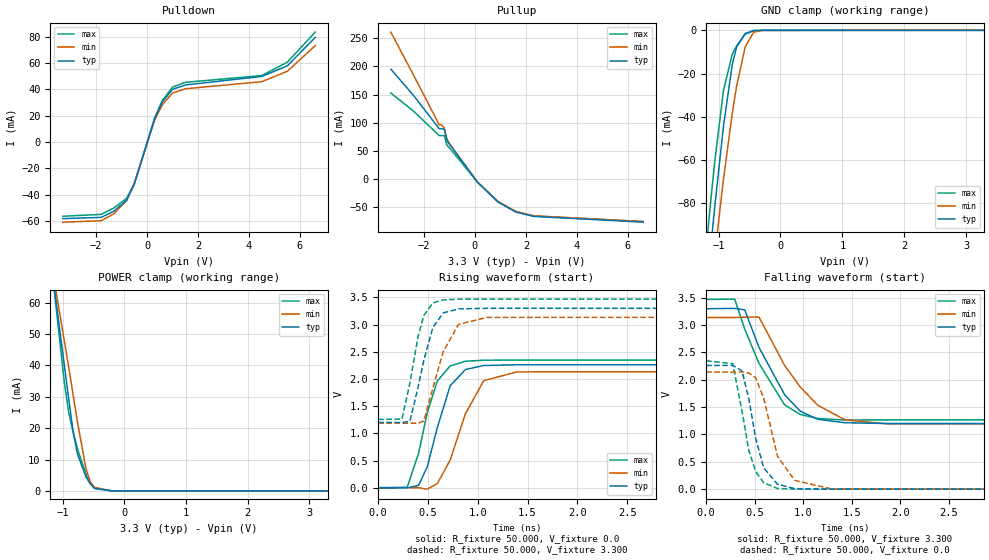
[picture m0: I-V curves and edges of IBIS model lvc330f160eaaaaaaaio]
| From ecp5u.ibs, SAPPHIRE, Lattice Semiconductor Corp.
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|   Model lvc330f160eaaaaaaaio
[Model] lvc330f160eaaaaaaaio
Model_type I/O
Polarity   Non-Inverting
Enable   Active-Low
Vinl =  0.800V
Vinh =  2.000V
Vmeas =  1.650V
Cref =  0.0F
Rref =  1.000M
Vref =  0.0V
C_comp   5.000pF   4.000pF   5.500pF
[Temperature Range]   25.000   0.125k   -40.000
[Voltage Range]   3.300V   3.140V   3.470V
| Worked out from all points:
|   slope of the pulldown table from 0 to 0.495 V, typ, clamps not added: 18.7 ohm
|   slope of the pullup table from 0 to 0.495 V, typ, clamps not added: 19.7 ohm
|   GND clamp passes 1 mA (typ) near -0.54 V on its own axis
|   POWER clamp passes 1 mA (typ) near -0.49 V on its own axis
|   rising waveform, R_fixture 50.000, V_fixture 0.0: 20-80 % time 203ps typ, 248ps min, 187ps max; typ from 0 V to 2.26 V
|   rising waveform, R_fixture 50.000, V_fixture 3.300: 20-80 % time 160ps typ, 189ps min, 134ps max; typ from 1.2 V to 3.3 V
|   falling waveform, R_fixture 50.000, V_fixture 3.300: 20-80 % time 376ps typ, 463ps min, 351ps max; typ from 3.3 V to 1.2 V
|   falling waveform, R_fixture 50.000, V_fixture 0.0: 20-80 % time 155ps typ, 190ps min, 145ps max; typ from 2.26 V to 0 V
[Pulldown]
|Voltage   I(typ)   I(min)   I(max)
-3.3V     -58.2mA    -60.91mA   -56.39mA
-1.8V     -57.26mA   -59.78mA   -54.99mA
-1.3V     -52.58mA   -54.51mA   -50.15mA
-800mV    -44.22mA   -44.44mA   -42.72mA
-500mV    -32.04mA   -31.37mA   -31.77mA
300mV     17.85mA    16.63mA    18.36mA
600mV     30.4mA     28.29mA    31.47mA
1V        39.96mA    37.2mA     41.67mA
1.5V      43.3mA     40.41mA    45.3mA
4.5V      49.76mA    45.79mA    50.43mA
5.5V      57.79mA    53.65mA    60.58mA
6.6V      79.4mA     73.23mA    83.46mA
[Pullup]
|Voltage   I(typ)   I(min)   I(max)
-3.3V     195.1mA    260.9mA    152.7mA
-2.4V     147.9mA    183.8mA    120.2mA
-1.4V     89.27mA    96.16mA    77.06mA
-1.3V     89.27mA    96.16mA    77.06mA
-1.2V     88.02mA    90.25mA    77.06mA
-1.1V     68.34mA    71.02mA    60.08mA
-1V       61.82mA    63.09mA    55.35mA
100mV     -5.661mA   -5.428mA   -5.612mA
900mV     -40.84mA   -39.7mA    -40.26mA
1.6V      -58.61mA   -57.46mA   -57.75mA
2.3V      -66.4mA    -65.3mA    -65.61mA
6.6V      -76.66mA   -75.54mA   -75.6mA
[GND_clamp]
|Voltage   I(typ)   I(min)   I(max)
-3.3V     -912.7mA   -861.5mA   -922.5mA
-1.27V    -145.6mA   -163.6mA   -123.5mA
-1.2V     -123.4mA   -142.6mA   -101.4mA
-1.13V    -102mA     -122.4mA   -80.37mA
-1.06V    -81.56mA   -103.5mA   -60.64mA
-920mV    -44.4mA    -68.93mA   -27.87mA
-780mV    -16.18mA   -38.86mA   -11.24mA
-710mV    -7.839mA   -26.12mA   -7.318mA
-570mV    -1.464mA   -7.654mA   -1.852mA
-430mV    -105.8uA   -801.1uA   -99.73uA
-290mV    -1.56uA    -33.42uA   -868.4nA
3.28V     0A         0A         0A
[POWER_clamp]
|Voltage   I(typ)   I(min)   I(max)
-3.28V    471.5mA    421.2mA    516.6mA
-1.18V    71.72mA    72.75mA    72.14mA
-1.11V    60.88mA    63.98mA    59.38mA
-970mV    39.73mA    47.46mA    34.21mA
-900mV    29.12mA    39.28mA    24.89mA
-830mV    19.01mA    30.67mA    18.7mA
-760mV    11.8mA     22.01mA    13.51mA
-620mV    4.416mA    6.921mA    5.219mA
-550mV    2.174mA    2.865mA    2.414mA
-480mV    813uA      1.102mA    758.3uA
-200mV    3.62uA     22.61uA    424nA
3.3V      0A         0A         0A
[Ramp]
| variable   typ   min   max
dV/dt_r 1.357/0.204n   1.285/0.251n   1.409/0.192n
dV/dt_f 1.260/0.379n   1.172/0.466n   1.328/0.354n
R_load = 50.000
[Rising Waveform]
R_fixture= 50.000
V_fixture= 0.0
V_fixture_min= 0.0
V_fixture_max= 0.0
|time   V(typ)   V(min)   V(max)
0s        0V         0V         0V
291ps     -3.333mV   -85.98uV   7.874mV
405ps     42.29mV    -1.906mV   627.2mV
492ps     383mV      -26.76mV   1.374V
594ps     1.108V     76.72mV    1.964V
723ps     1.876V     508.6mV    2.24V
876ps     2.174V     1.36V      2.326V
1.06ns    2.248V     1.969V     2.345V
1.394ns   2.261V     2.131V     2.348V
10ns      2.262V     2.142V     2.348V
[Rising Waveform]
R_fixture= 50.000
V_fixture= 3.300
V_fixture_min= 3.140
V_fixture_max= 3.470
|time   V(typ)   V(min)   V(max)
0s        1.2V       1.187V     1.256V
239ps     1.2V       1.187V     1.262V
318ps     1.219V     1.187V     1.921V
399ps     1.838V     1.185V     2.769V
458ps     2.341V     1.227V     3.167V
548ps     2.942V     1.825V     3.397V
652ps     3.214V     2.5V       3.455V
807ps     3.29V      3.005V     3.468V
1.096ns   3.3V       3.133V     3.47V
10ns      3.3V       3.14V      3.47V
[Falling Waveform]
R_fixture= 50.000
V_fixture= 3.300
V_fixture_min= 3.140
V_fixture_max= 3.470
|time   V(typ)   V(min)   V(max)
0s        3.3V       3.14V      3.47V
294ps     3.307V     3.14V      3.477V
398ps     3.279V     3.145V     2.926V
544ps     2.593V     3.149V     2.302V
808ps     1.728V     2.264V     1.541V
969ps     1.427V     1.869V     1.367V
1.149ns   1.278V     1.535V     1.294V
1.429ns   1.215V     1.268V     1.264V
1.859ns   1.201V     1.195V     1.268V
10ns      1.2V       1.187V     1.256V
[Falling Waveform]
R_fixture= 50.000
V_fixture= 0.0
V_fixture_min= 0.0
V_fixture_max= 0.0
|time   V(typ)   V(min)   V(max)
0s        2.262V     2.142V     2.348V
274ps     2.264V     2.142V     2.295V
369ps     2.166V     2.146V     1.434V
439ps     1.66V      2.126V     714.7mV
510ps     928.1mV    2.038V     323.4mV
593ps     391.9mV    1.663V     117.9mV
735ps     89.87mV    601.6mV    12.48mV
912ps     9.019mV    159.8mV    1.297mV
1.29ns    358.3uV    5.314mV    69.35uV
10ns      0V         0V         0V
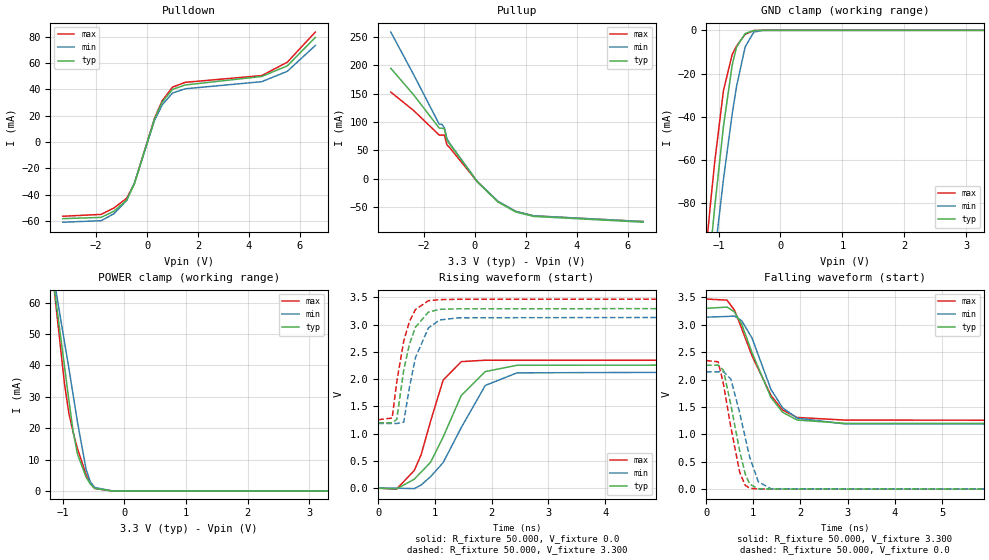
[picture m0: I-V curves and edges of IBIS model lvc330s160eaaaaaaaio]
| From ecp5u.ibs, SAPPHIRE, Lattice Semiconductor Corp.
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|   Model lvc330s160eaaaaaaaio
[Model] lvc330s160eaaaaaaaio
Model_type I/O
Polarity   Non-Inverting
Enable   Active-Low
Vinl =  0.800V
Vinh =  2.000V
Vmeas =  1.650V
Cref =  0.0F
Rref =  1.000M
Vref =  0.0V
C_comp   5.000pF   4.000pF   5.500pF
[Temperature Range]   25.000   0.125k   -40.000
[Voltage Range]   3.300V   3.140V   3.470V
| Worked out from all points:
|   slope of the pulldown table from 0 to 0.495 V, typ, clamps not added: 18.7 ohm
|   slope of the pullup table from 0 to 0.495 V, typ, clamps not added: 19.7 ohm
|   GND clamp passes 1 mA (typ) near -0.54 V on its own axis
|   POWER clamp passes 1 mA (typ) near -0.49 V on its own axis
|   rising waveform, R_fixture 50.000, V_fixture 0.0: 20-80 % time 619ps typ, 637ps min, 399ps max; typ from 0 V to 2.26 V
|   rising waveform, R_fixture 50.000, V_fixture 3.300: 20-80 % time 252ps typ, 262ps min, 242ps max; typ from 1.2 V to 3.3 V
|   falling waveform, R_fixture 50.000, V_fixture 3.300: 20-80 % time 598ps typ, 557ps min, 670ps max; typ from 3.3 V to 1.2 V
|   falling waveform, R_fixture 50.000, V_fixture 0.0: 20-80 % time 312ps typ, 346ps min, 293ps max; typ from 2.26 V to 0 V
[Pulldown]
|Voltage   I(typ)   I(min)   I(max)
-3.3V     -58.2mA    -60.91mA   -56.39mA
-1.8V     -57.26mA   -59.78mA   -54.99mA
-1.3V     -52.58mA   -54.51mA   -50.15mA
-800mV    -44.22mA   -44.44mA   -42.72mA
-500mV    -32.04mA   -31.37mA   -31.77mA
300mV     17.85mA    16.63mA    18.36mA
600mV     30.4mA     28.29mA    31.47mA
1V        39.96mA    37.2mA     41.67mA
1.5V      43.3mA     40.41mA    45.3mA
4.5V      49.76mA    45.79mA    50.43mA
5.5V      57.79mA    53.65mA    60.58mA
6.6V      79.4mA     73.23mA    83.46mA
[Pullup]
|Voltage   I(typ)   I(min)   I(max)
-3.3V     194.9mA    258.8mA    152.9mA
-2.4V     147.8mA    183.3mA    120.2mA
-1.4V     89.27mA    96.15mA    77.06mA
-1.3V     89.27mA    96.15mA    77.06mA
-1.2V     88.02mA    90.25mA    77.06mA
-1.1V     68.34mA    71.02mA    60.08mA
-1V       61.82mA    63.09mA    55.35mA
100mV     -5.661mA   -5.428mA   -5.612mA
900mV     -40.84mA   -39.7mA    -40.26mA
1.6V      -58.61mA   -57.46mA   -57.75mA
2.3V      -66.4mA    -65.3mA    -65.61mA
6.6V      -76.66mA   -75.54mA   -75.6mA
[GND_clamp]
|Voltage   I(typ)   I(min)   I(max)
-3.3V     -912.7mA   -861.5mA   -922.5mA
-1.27V    -145.6mA   -163.6mA   -123.5mA
-1.2V     -123.4mA   -142.6mA   -101.4mA
-1.13V    -102mA     -122.4mA   -80.37mA
-1.06V    -81.56mA   -103.5mA   -60.64mA
-920mV    -44.4mA    -68.93mA   -27.87mA
-780mV    -16.18mA   -38.86mA   -11.24mA
-710mV    -7.839mA   -26.12mA   -7.318mA
-570mV    -1.464mA   -7.654mA   -1.852mA
-430mV    -105.8uA   -801.1uA   -99.73uA
-290mV    -1.56uA    -33.42uA   -868.4nA
3.28V     0A         0A         0A
[POWER_clamp]
|Voltage   I(typ)   I(min)   I(max)
-3.28V    471.5mA    421.2mA    516.6mA
-1.18V    71.72mA    72.75mA    72.14mA
-1.11V    60.88mA    63.98mA    59.38mA
-970mV    39.73mA    47.46mA    34.21mA
-900mV    29.12mA    39.28mA    24.89mA
-830mV    19.01mA    30.67mA    18.7mA
-760mV    11.8mA     22.01mA    13.51mA
-620mV    4.416mA    6.921mA    5.219mA
-550mV    2.174mA    2.865mA    2.414mA
-480mV    813uA      1.102mA    758.3uA
-200mV    3.62uA     22.61uA    424nA
3.3V      0A         0A         0A
[Ramp]
| variable   typ   min   max
dV/dt_r 1.357/0.622n   1.285/0.642n   1.409/0.408n
dV/dt_f 1.260/0.609n   1.172/0.566n   1.328/0.673n
R_load = 50.000
[Rising Waveform]
R_fixture= 50.000
V_fixture= 0.0
V_fixture_min= 0.0
V_fixture_max= 0.0
|time   V(typ)   V(min)   V(max)
0s        0V         0V         0V
322ps     -15.25mV   -163.2uV   -18.77mV
634ps     162.8mV    -9.253mV   322.3mV
754ps     291.3mV    56.62mV    605.9mV
924ps     476.8mV    211.7mV    1.232V
1.144ns   936.7mV    468.1mV    1.982V
1.465ns   1.703V     1.114V     2.322V
1.886ns   2.139V     1.884V     2.348V
2.446ns   2.255V     2.116V     2.348V
10ns      2.262V     2.142V     2.348V
[Rising Waveform]
R_fixture= 50.000
V_fixture= 3.300
V_fixture_min= 3.140
V_fixture_max= 3.470
|time   V(typ)   V(min)   V(max)
0s        1.2V       1.187V     1.256V
246ps     1.2V       1.187V     1.286V
327ps     1.26V      1.187V     1.948V
450ps     2.168V     1.213V     2.7V
549ps     2.635V     1.841V     3.053V
656ps     2.953V     2.395V     3.277V
885ps     3.231V     2.94V      3.44V
1.081ns   3.281V     3.086V     3.459V
1.416ns   3.291V     3.126V     3.466V
10ns      3.3V       3.14V      3.47V
[Falling Waveform]
R_fixture= 50.000
V_fixture= 3.300
V_fixture_min= 3.140
V_fixture_max= 3.470
|time   V(typ)   V(min)   V(max)
0s        3.3V       3.14V      3.47V
444ps     3.324V     3.152V     3.451V
601ps     3.235V     3.161V     3.268V
753ps     3.014V     3.076V     2.935V
974ps     2.49V      2.758V     2.432V
1.373ns   1.676V     1.824V     1.714V
1.621ns   1.404V     1.486V     1.446V
1.931ns   1.262V     1.296V     1.309V
2.943ns   1.201V     1.191V     1.261V
10ns      1.2V       1.187V     1.256V
[Falling Waveform]
R_fixture= 50.000
V_fixture= 0.0
V_fixture_min= 0.0
V_fixture_max= 0.0
|time   V(typ)   V(min)   V(max)
0s        2.262V     2.142V     2.348V
256ps     2.264V     2.142V     2.325V
368ps     2.168V     2.147V     1.919V
524ps     1.538V     2.009V     1.13V
712ps     696.6mV    1.394V     309.6mV
829ps     277.3mV    940.4mV    69.75mV
926ps     88.38mV    578.5mV    17.78mV
1.108ns   8.78mV     133.7mV    2.914mV
1.378ns   2.285mV    7.959mV    1.464mV
10ns      0V         0V         0V
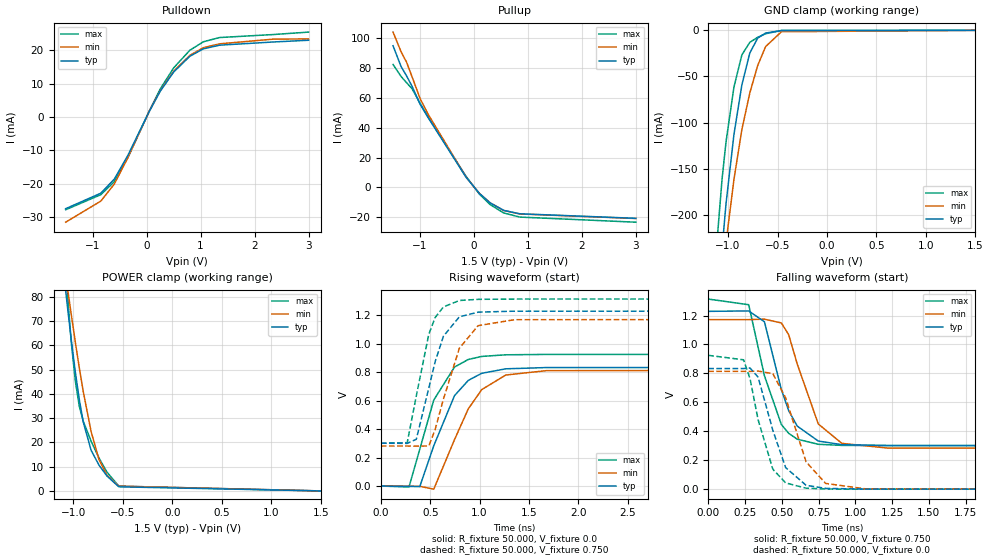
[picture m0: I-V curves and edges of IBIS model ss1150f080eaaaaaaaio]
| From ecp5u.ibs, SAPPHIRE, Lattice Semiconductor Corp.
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|   Model ss1150f080eaaaaaaaio
[Model] ss1150f080eaaaaaaaio
Model_type I/O
Polarity   Non-Inverting
Enable   Active-Low
Vinl =  0.650V
Vinh =  0.850V
Vmeas =  0.750V
Cref =  30.000pF
Rref =  50.000
Vref =  0.750V
C_comp   5.000pF   4.000pF   5.500pF
[Temperature Range]   25.000   0.125k   -40.000
[Voltage Range]   1.500V   1.430V   1.580V
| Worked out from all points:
|   slope of the pulldown table from 0 to 0.225 V, typ, clamps not added: 32.3 ohm
|   slope of the pullup table from 0 to 0.225 V, typ, clamps not added: 27.3 ohm
|   GND clamp passes 1 mA (typ) near -0.54 V on its own axis
|   POWER clamp passes 1 mA (typ) near -0.51 V on its own axis
|   rising waveform, R_fixture 50.000, V_fixture 0.0: 20-80 % time 294ps typ, 330ps min, 261ps max; typ from 0 V to 0.834 V
|   rising waveform, R_fixture 50.000, V_fixture 0.750: 20-80 % time 208ps typ, 237ps min, 179ps max; typ from 0.301 V to 1.23 V
|   falling waveform, R_fixture 50.000, V_fixture 0.750: 20-80 % time 159ps typ, 172ps min, 147ps max; typ from 1.23 V to 0.301 V
|   falling waveform, R_fixture 50.000, V_fixture 0.0: 20-80 % time 139ps typ, 160ps min, 127ps max; typ from 0.834 V to 0 V
[Pulldown]
|Voltage   I(typ)   I(min)   I(max)
-1.5V     -27.39mA   -31.43mA   -27.72mA
-850mV    -22.78mA   -25.14mA   -23.23mA
-600mV    -18.58mA   -20.07mA   -19.34mA
-350mV    -11.53mA   -12.21mA   -12.18mA
50mV      1.697mA    1.729mA    1.836mA
250mV     7.652mA    7.792mA    8.316mA
500mV     13.41mA    13.64mA    14.65mA
800mV     18.13mA    18.42mA    19.93mA
1.05V     20.35mA    20.7mA     22.46mA
1.35V     21.45mA    21.85mA    23.73mA
2.35V     22.41mA    23.26mA    24.63mA
3V        22.92mA    23.32mA    25.36mA
[Pullup]
|Voltage   I(typ)   I(min)   I(max)
-1.5V     95.03mA    104.2mA    82.46mA
-1.35V    81.02mA    90.95mA    74.41mA
-1.25V    74.86mA    84.06mA    70.27mA
-1.15V    68.02mA    74.48mA    66.36mA
-1V       55.88mA    59.73mA    56.56mA
-850mV    46.85mA    49.11mA    47.35mA
-150mV    6.997mA    7.036mA    7.57mA
100mV     -4.023mA   -3.974mA   -4.467mA
300mV     -10.39mA   -10.34mA   -11.52mA
550mV     -15.39mA   -15.45mA   -17.12mA
850mV     -17.67mA   -17.8mA    -19.88mA
3V        -20.72mA   -20.84mA   -23.31mA
[GND_clamp]
|Voltage   I(typ)   I(min)   I(max)
-1.5V     -960.1mA   -762.7mA   -1.034A
-1.14V    -347.3mA   -346mA     -275mA
-1.1V     -290.2mA   -305.8mA   -213.7mA
-1.06V    -236.5mA   -267.1mA   -161mA
-1.02V    -187.7mA   -229.9mA   -120.7mA
-940mV    -112.8mA   -161.5mA   -61.34mA
-860mV    -59.06mA   -107.5mA   -26.59mA
-780mV    -24.6mA    -67.97mA   -13.06mA
-700mV    -8.431mA   -38.1mA    -7.531mA
-620mV    -2.969mA   -17.61mA   -3.668mA
-460mV    -207.8uA   -1.521mA   -211uA
1.5V      0A         0A         0A
[POWER_clamp]
|Voltage   I(typ)   I(min)   I(max)
-1.5V     267.6mA    236.4mA    479.7mA
-1.1V     90.92mA    95.54mA    105.5mA
-1.06V    76.14mA    83.93mA    81.29mA
-1.02V    62.03mA    72.49mA    60.96mA
-980mV    49.07mA    61.38mA    45.36mA
-940mV    37.73mA    50.83mA    34.98mA
-900mV    28.44mA    41.02mA    28.75mA
-820mV    16.72mA    24.41mA    20.46mA
-740mV    10.6mA     12.83mA    13.51mA
-660mV    6.131mA    6.445mA    7.75mA
-540mV    1.697mA    1.964mA    1.966mA
1.5V      0A         0A         0A
[Ramp]
| variable   typ   min   max
dV/dt_r 0.500/0.298n   0.489/0.332n   0.555/0.259n
dV/dt_f 0.494/0.195n   0.480/0.206n   0.542/0.189n
R_load = 50.000
[Rising Waveform]
R_fixture= 50.000
V_fixture= 0.0
V_fixture_min= 0.0
V_fixture_max= 0.0
|time   V(typ)   V(min)   V(max)
0s        0V         0V         0V
285ps     -2.262mV   -324.7uV   -6.263mV
394ps     -3.981mV   -1.649mV   258.6mV
536ps     283.3mV    -21.78mV   604.6mV
746ps     635.2mV    325.9mV    836.1mV
886ps     742.6mV    542.8mV    889.6mV
1.022ns   792.3mV    677.7mV    910.9mV
1.266ns   823.9mV    780.3mV    922.4mV
1.682ns   832.8mV    811.3mV    925mV
10ns      833.6mV    814.4mV    925.1mV
[Rising Waveform]
R_fixture= 50.000
V_fixture= 0.750
V_fixture_min= 0.713
V_fixture_max= 0.789
|time   V(typ)   V(min)   V(max)
0s        301.2mV    281.5mV    301mV
267ps     299.9mV    281.4mV    305.1mV
359ps     328.7mV    280.5mV    633.8mV
486ps     689.5mV    281.8mV    1.068V
550ps     874.3mV    397.2mV    1.184V
634ps     1.053V     611mV      1.259V
795ps     1.189V     968.2mV    1.304V
985ps     1.222V     1.127V     1.312V
1.354ns   1.229V     1.169V     1.314V
10ns      1.229V     1.172V     1.314V
[Falling Waveform]
R_fixture= 50.000
V_fixture= 0.750
V_fixture_min= 0.713
V_fixture_max= 0.789
|time   V(typ)   V(min)   V(max)
0s        1.229V     1.172V     1.314V
275ps     1.232V     1.172V     1.275V
382ps     1.157V     1.175V     783.6mV
497ps     688.4mV    1.149V     446.9mV
547ps     542.2mV    1.067V     385.6mV
605ps     435.8mV    864.5mV    345.4mV
748ps     332.6mV    450.5mV    310.2mV
908ps     307.6mV    316.6mV    302.6mV
1.223ns   301.6mV    283.7mV    301.1mV
10ns      301.2mV    281.5mV    301mV
[Falling Waveform]
R_fixture= 50.000
V_fixture= 0.0
V_fixture_min= 0.0
V_fixture_max= 0.0
|time   V(typ)   V(min)   V(max)
0s        833.6mV    814.4mV    925.1mV
240ps     833.9mV    814.5mV    894.3mV
284ps     837.4mV    813.9mV    764.6mV
339ps     773.9mV    816.1mV    479.8mV
439ps     407mV      798.5mV    138.2mV
526ps     149.4mV    631.3mV    43.24mV
665ps     26.75mV    188.8mV    6.811mV
798ps     5.472mV    39.61mV    1.229mV
1.068ns   349.5uV    2.304mV    51.38uV
10ns      0V         0V         0V
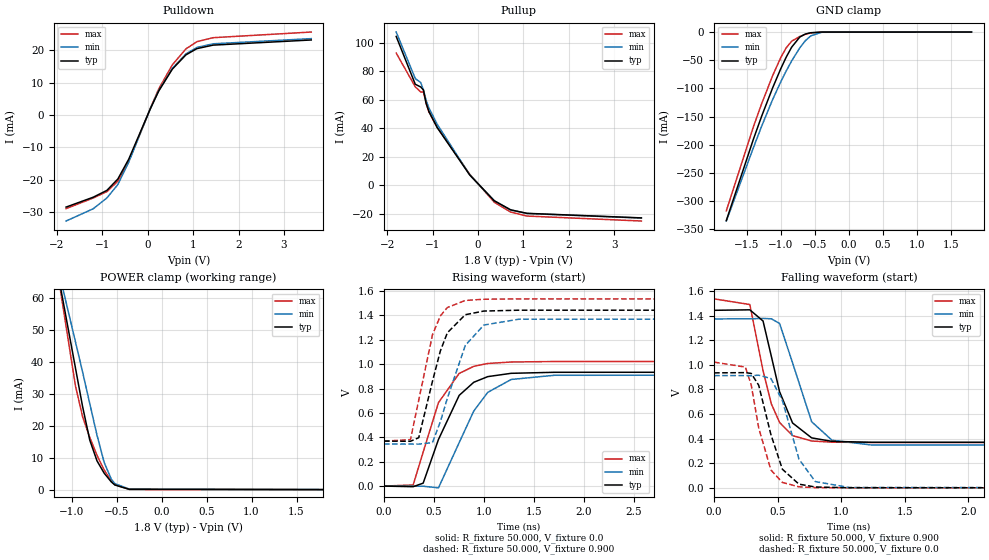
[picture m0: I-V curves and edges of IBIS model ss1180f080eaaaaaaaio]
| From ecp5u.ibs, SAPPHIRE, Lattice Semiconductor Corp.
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|   Model ss1180f080eaaaaaaaio
[Model] ss1180f080eaaaaaaaio
Model_type I/O
Polarity   Non-Inverting
Enable   Active-Low
Vinl =  0.775V
Vinh =  1.025V
Vmeas =  0.900V
Cref =  30.000pF
Rref =  50.000
Vref =  0.900V
C_comp   5.000pF   4.000pF   5.500pF
[Temperature Range]   25.000   0.125k   -40.000
[Voltage Range]   1.800V   1.710V   1.890V
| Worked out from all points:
|   slope of the pulldown table from 0 to 0.27 V, typ, clamps not added: 33.1 ohm
|   slope of the pullup table from 0 to 0.27 V, typ, clamps not added: 31.2 ohm
|   GND clamp passes 1 mA (typ) near -0.54 V on its own axis
|   POWER clamp passes 1 mA (typ) near -0.49 V on its own axis
|   rising waveform, R_fixture 50.000, V_fixture 0.0: 20-80 % time 287ps typ, 325ps min, 262ps max; typ from 0 V to 0.934 V
|   rising waveform, R_fixture 50.000, V_fixture 0.900: 20-80 % time 209ps typ, 249ps min, 185ps max; typ from 0.369 V to 1.44 V
|   falling waveform, R_fixture 50.000, V_fixture 0.900: 20-80 % time 167ps typ, 179ps min, 155ps max; typ from 1.44 V to 0.369 V
|   falling waveform, R_fixture 50.000, V_fixture 0.0: 20-80 % time 140ps typ, 159ps min, 125ps max; typ from 0.934 V to 0 V
[Pulldown]
|Voltage   I(typ)   I(min)   I(max)
-1.8V     -28.53mA   -32.84mA   -29.01mA
-1.2V     -25.46mA   -29.03mA   -25.7mA
-900mV    -23.35mA   -25.68mA   -23.75mA
-660mV    -19.84mA   -21.55mA   -20.51mA
-420mV    -13.7mA    -14.59mA   -14.42mA
60mV      2.026mA    2.064mA    2.192mA
240mV     7.384mA    7.52mA     8.023mA
540mV     14.17mA    14.41mA    15.5mA
840mV     18.59mA    18.89mA    20.45mA
1.08V     20.52mA    20.88mA    22.66mA
1.44V     21.61mA    22.02mA    23.91mA
3.6V      23.2mA     23.62mA    25.66mA
[Pullup]
|Voltage   I(typ)   I(min)   I(max)
-1.8V     104.5mA    107.6mA    92.84mA
-1.38V    70.9mA     74.9mA     69.09mA
-1.26V    68.99mA    72.12mA    65.48mA
-1.2V     66.93mA    66.81mA    65.48mA
-1.14V    57.38mA    59.48mA    57.36mA
-1.08V    51.83mA    54.35mA    51.48mA
-900mV    40.67mA    42.94mA    40.69mA
-180mV    7.161mA    7.234mA    7.646mA
360mV     -10.95mA   -10.92mA   -11.94mA
720mV     -17.31mA   -17.4mA    -18.86mA
1.08V     -19.76mA   -19.89mA   -21.68mA
3.6V      -22.97mA   -23.08mA   -25.16mA
[GND_clamp]
|Voltage   I(typ)   I(min)   I(max)
-1.8V     -334.4mA   -335.3mA   -317.1mA
-1.4V     -189.3mA   -204.4mA   -167.3mA
-1.28V    -148.9mA   -166.7mA   -126.7mA
-1.12V    -99.04mA   -119.7mA   -77.45mA
-1V       -64.9mA    -88.2mA    -45.18mA
-920mV    -44.4mA    -68.92mA   -27.88mA
-840mV    -26.71mA   -51.09mA   -16.18mA
-720mV    -8.754mA   -27.82mA   -7.821mA
-640mV    -3.53mA    -15.52mA   -4.188mA
-560mV    -1.27mA    -6.791mA   -1.597mA
-400mV    -49.63uA   -425.4uA   -44.12uA
1.8V      0A         0A         0A
[POWER_clamp]
|Voltage   I(typ)   I(min)   I(max)
-1.8V     174.6mA    158.5mA    191.6mA
-1.36V    100.3mA    96.28mA    105.7mA
-1.12V    62.39mA    65.2mA     61.09mA
-960mV    38.11mA    46.28mA    32.52mA
-880mV    25.96mA    36.75mA    22.79mA
-800mV    15.45mA    26.86mA    16.3mA
-720mV    9.004mA    17.05mA    10.75mA
-640mV    5.132mA    8.487mA    6.134mA
-560mV    2.382mA    3.217mA    2.693mA
-520mV    1.425mA    1.849mA    1.506mA
-360mV    88.16uA    177.6uA    42.1uA
1.8V      0A         0A         0A
[Ramp]
| variable   typ   min   max
dV/dt_r 0.561/0.291n   0.547/0.326n   0.613/0.263n
dV/dt_f 0.564/0.228n   0.550/0.234n   0.620/0.216n
R_load = 50.000
[Rising Waveform]
R_fixture= 50.000
V_fixture= 0.0
V_fixture_min= 0.0
V_fixture_max= 0.0
|time   V(typ)   V(min)   V(max)
0s        0V         0V         0V
292ps     -4.86mV    -190.7uV   9.259mV
392ps     24.06mV    -902.6uV   278.6mV
545ps     382.2mV    -14.42mV   684.7mV
752ps     744.1mV    356.4mV    924.1mV
898ps     851.8mV    616mV      982.6mV
1.038ns   898.1mV    769.1mV    1.006V
1.272ns   925.2mV    874.8mV    1.018V
1.704ns   933.6mV    909.1mV    1.022V
10ns      934.5mV    912.4mV    1.022V
[Rising Waveform]
R_fixture= 50.000
V_fixture= 0.900
V_fixture_min= 0.856
V_fixture_max= 0.946
|time   V(typ)   V(min)   V(max)
0s        369.2mV    344.8mV    368.5mV
265ps     367.6mV    344.8mV    381.3mV
348ps     397.2mV    344.3mV    706.5mV
485ps     859.5mV    357mV      1.241V
564ps     1.109V     528.3mV    1.396V
634ps     1.258V     720.9mV    1.465V
813ps     1.406V     1.154V     1.523V
998ps     1.436V     1.321V     1.533V
1.348ns   1.443V     1.369V     1.536V
10ns      1.443V     1.373V     1.536V
[Falling Waveform]
R_fixture= 50.000
V_fixture= 0.900
V_fixture_min= 0.856
V_fixture_max= 0.946
|time   V(typ)   V(min)   V(max)
0s        1.443V     1.373V     1.536V
281ps     1.447V     1.374V     1.49V
385ps     1.356V     1.377V     952.6mV
450ps     1.07V      1.374V     683.4mV
515ps     781.1mV    1.336V     531mV
617ps     527.2mV    1.016V     424.7mV
767ps     406.1mV    537.3mV    380.8mV
927ps     377.7mV    386.9mV    371.3mV
1.237ns   370.2mV    348.3mV    368.8mV
10ns      369.2mV    344.8mV    368.5mV
[Falling Waveform]
R_fixture= 50.000
V_fixture= 0.0
V_fixture_min= 0.0
V_fixture_max= 0.0
|time   V(typ)   V(min)   V(max)
0s        934.5mV    912.4mV    1.022V
246ps     936.4mV    912.5mV    981.5mV
292ps     930.1mV    911.7mV    836.5mV
351ps     833.7mV    915.7mV    486.3mV
447ps     432.2mV    888.4mV    144.9mV
537ps     151.3mV    709.7mV    43.85mV
667ps     30.08mV    233.8mV    8.455mV
796ps     6.839mV    50.87mV    2.073mV
1.06ns    835.9uV    3.264mV    272.9uV
10ns      0V         0V         0V
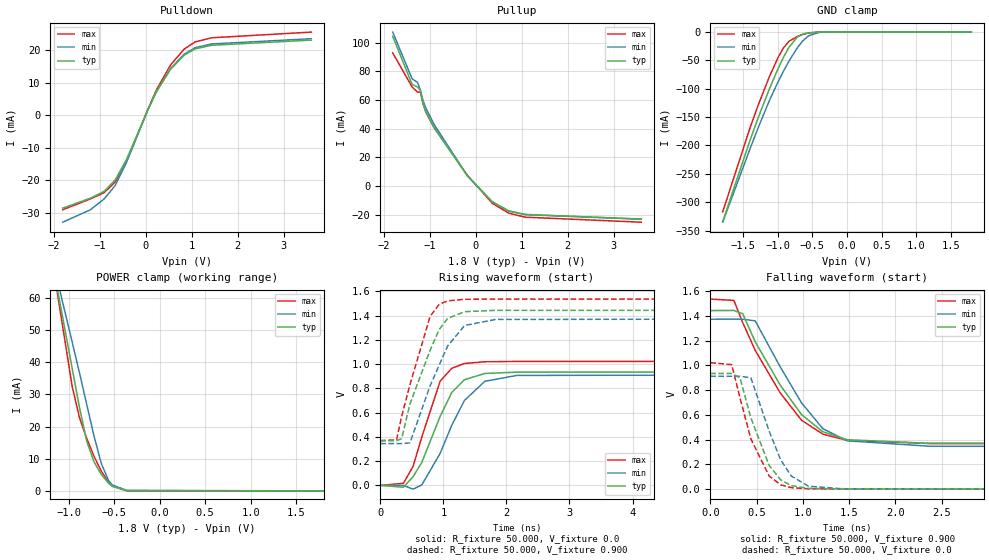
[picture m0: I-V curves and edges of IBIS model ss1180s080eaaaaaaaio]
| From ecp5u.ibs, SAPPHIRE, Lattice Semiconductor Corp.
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|   Model ss1180s080eaaaaaaaio
[Model] ss1180s080eaaaaaaaio
Model_type I/O
Polarity   Non-Inverting
Enable   Active-Low
Vinl =  0.775V
Vinh =  1.025V
Vmeas =  0.900V
Cref =  30.000pF
Rref =  50.000
Vref =  0.900V
C_comp   5.000pF   4.000pF   5.500pF
[Temperature Range]   25.000   0.125k   -40.000
[Voltage Range]   1.800V   1.710V   1.890V
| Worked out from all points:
|   slope of the pulldown table from 0 to 0.27 V, typ, clamps not added: 33.1 ohm
|   slope of the pullup table from 0 to 0.27 V, typ, clamps not added: 31.2 ohm
|   GND clamp passes 1 mA (typ) near -0.54 V on its own axis
|   POWER clamp passes 1 mA (typ) near -0.49 V on its own axis
|   rising waveform, R_fixture 50.000, V_fixture 0.0: 20-80 % time 456ps typ, 496ps min, 353ps max; typ from 0 V to 0.934 V
|   rising waveform, R_fixture 50.000, V_fixture 0.900: 20-80 % time 455ps typ, 498ps min, 372ps max; typ from 0.369 V to 1.44 V
|   falling waveform, R_fixture 50.000, V_fixture 0.900: 20-80 % time 546ps typ, 499ps min, 556ps max; typ from 1.44 V to 0.369 V
|   falling waveform, R_fixture 50.000, V_fixture 0.0: 20-80 % time 258ps typ, 269ps min, 252ps max; typ from 0.934 V to 0 V
[Pulldown]
|Voltage   I(typ)   I(min)   I(max)
-1.8V     -28.53mA   -32.84mA   -29.01mA
-1.2V     -25.46mA   -29.03mA   -25.7mA
-900mV    -23.35mA   -25.68mA   -23.75mA
-660mV    -19.84mA   -21.55mA   -20.51mA
-420mV    -13.7mA    -14.59mA   -14.42mA
60mV      2.026mA    2.064mA    2.192mA
240mV     7.384mA    7.52mA     8.023mA
540mV     14.17mA    14.41mA    15.5mA
840mV     18.59mA    18.89mA    20.45mA
1.08V     20.52mA    20.88mA    22.66mA
1.44V     21.61mA    22.02mA    23.91mA
3.6V      23.2mA     23.62mA    25.66mA
[Pullup]
|Voltage   I(typ)   I(min)   I(max)
-1.8V     104.4mA    107.3mA    92.82mA
-1.38V    70.9mA     74.87mA    69.09mA
-1.26V    68.99mA    72.12mA    65.48mA
-1.2V     66.93mA    66.81mA    65.48mA
-1.14V    57.38mA    59.48mA    57.36mA
-1.08V    51.83mA    54.35mA    51.48mA
-900mV    40.67mA    42.94mA    40.69mA
-180mV    7.161mA    7.234mA    7.646mA
360mV     -10.95mA   -10.92mA   -11.94mA
720mV     -17.31mA   -17.4mA    -18.86mA
1.08V     -19.76mA   -19.89mA   -21.68mA
3.6V      -22.97mA   -23.08mA   -25.16mA
[GND_clamp]
|Voltage   I(typ)   I(min)   I(max)
-1.8V     -334.4mA   -335.3mA   -317.1mA
-1.4V     -189.3mA   -204.4mA   -167.3mA
-1.28V    -148.9mA   -166.7mA   -126.7mA
-1.12V    -99.04mA   -119.7mA   -77.45mA
-1V       -64.9mA    -88.2mA    -45.18mA
-920mV    -44.4mA    -68.92mA   -27.88mA
-840mV    -26.71mA   -51.09mA   -16.18mA
-720mV    -8.754mA   -27.82mA   -7.821mA
-640mV    -3.53mA    -15.52mA   -4.188mA
-560mV    -1.27mA    -6.791mA   -1.597mA
-400mV    -49.63uA   -425.4uA   -44.12uA
1.8V      0A         0A         0A
[POWER_clamp]
|Voltage   I(typ)   I(min)   I(max)
-1.8V     174.6mA    158.5mA    191.6mA
-1.36V    100.3mA    96.28mA    105.7mA
-1.12V    62.39mA    65.2mA     61.09mA
-960mV    38.11mA    46.28mA    32.52mA
-880mV    25.96mA    36.75mA    22.79mA
-800mV    15.45mA    26.86mA    16.3mA
-720mV    9.004mA    17.05mA    10.75mA
-640mV    5.132mA    8.487mA    6.134mA
-560mV    2.382mA    3.217mA    2.693mA
-520mV    1.425mA    1.849mA    1.506mA
-360mV    88.16uA    177.6uA    42.1uA
1.8V      0A         0A         0A
[Ramp]
| variable   typ   min   max
dV/dt_r 0.561/0.465n   0.547/0.507n   0.613/0.353n
dV/dt_f 0.564/0.598n   0.550/0.531n   0.620/0.637n
R_load = 50.000
[Rising Waveform]
R_fixture= 50.000
V_fixture= 0.0
V_fixture_min= 0.0
V_fixture_max= 0.0
|time   V(typ)   V(min)   V(max)
0s        0V         0V         0V
367ps     -15.02mV   -588.7uV   17.05mV
520ps     71.57mV    -31.08mV   156.2mV
658ps     189mV      3.754mV    397.9mV
949ps     569.1mV    263.8mV    859.3mV
1.133ns   765.1mV    495.3mV    964.9mV
1.334ns   871.3mV    699.9mV    1.005V
1.658ns   922.7mV    858.1mV    1.019V
2.168ns   933.6mV    906.7mV    1.022V
10ns      934.5mV    912.4mV    1.022V
[Rising Waveform]
R_fixture= 50.000
V_fixture= 0.900
V_fixture_min= 0.856
V_fixture_max= 0.946
|time   V(typ)   V(min)   V(max)
0s        369.2mV    344.8mV    368.5mV
258ps     368.1mV    344.8mV    375.3mV
339ps     385.5mV    344.4mV    569.6mV
470ps     670.9mV    350.5mV    829.2mV
789ps     1.113V     819.6mV    1.392V
933ps     1.284V     990.1mV    1.492V
1.066ns   1.375V     1.147V     1.521V
1.337ns   1.432V     1.318V     1.534V
1.826ns   1.443V     1.368V     1.536V
10ns      1.443V     1.373V     1.536V
[Falling Waveform]
R_fixture= 50.000
V_fixture= 0.900
V_fixture_min= 0.856
V_fixture_max= 0.946
|time   V(typ)   V(min)   V(max)
0s        1.443V     1.373V     1.536V
255ps     1.444V     1.374V     1.525V
351ps     1.417V     1.373V     1.345V
485ps     1.191V     1.36V      1.122V
755ps     841.1mV    988.9mV    778.2mV
986ps     602.4mV    697.1mV    556.9mV
1.216ns   463.8mV    488.6mV    444.6mV
1.477ns   399.6mV    390.9mV    394.5mV
2.376ns   369.7mV    346.4mV    368.7mV
10ns      369.2mV    344.8mV    368.5mV
[Falling Waveform]
R_fixture= 50.000
V_fixture= 0.0
V_fixture_min= 0.0
V_fixture_max= 0.0
|time   V(typ)   V(min)   V(max)
0s        934.5mV    912.4mV    1.022V
232ps     934.8mV    912.4mV    1.006V
321ps     899.3mV    912.1mV    738.4mV
438ps     577.6mV    900.2mV    406.9mV
635ps     192.4mV    471.3mV    107.4mV
760ps     75.42mV    237.3mV    34.98mV
876ps     28.16mV    105.7mV    11.82mV
1.06ns    6.458mV    23.98mV    2.995mV
1.43ns    1.554mV    3.082mV    1.112mV
10ns      0V         0V         0V
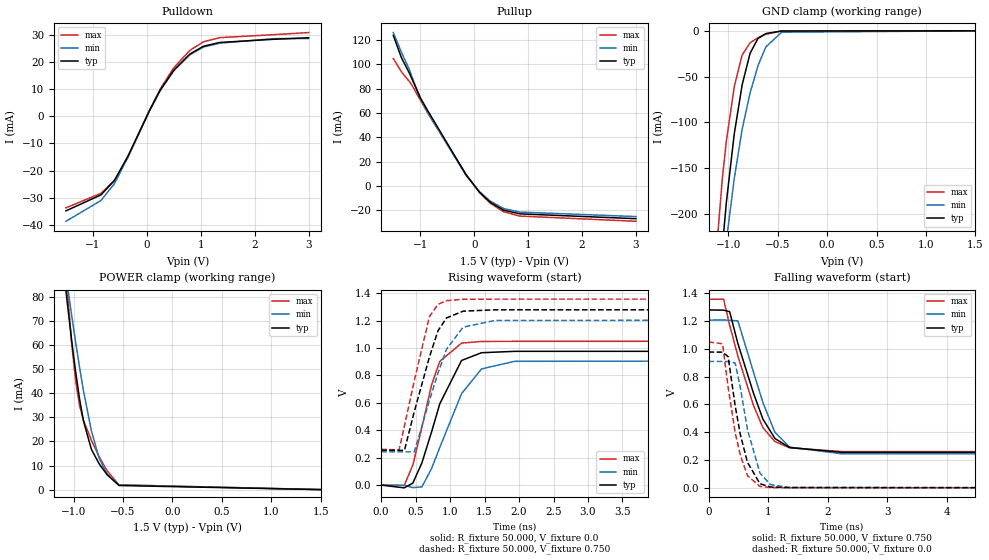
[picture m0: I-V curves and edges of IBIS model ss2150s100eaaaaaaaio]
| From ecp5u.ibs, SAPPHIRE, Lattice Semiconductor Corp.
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|   Model ss2150s100eaaaaaaaio
[Model] ss2150s100eaaaaaaaio
Model_type I/O
Polarity   Non-Inverting
Enable   Active-Low
Vinl =  0.650V
Vinh =  0.850V
Vmeas =  0.750V
Cref =  30.000pF
Rref =  50.000
Vref =  0.750V
C_comp   5.000pF   4.000pF   5.500pF
[Temperature Range]   25.000   0.125k   -40.000
[Voltage Range]   1.500V   1.430V   1.580V
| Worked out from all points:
|   slope of the pulldown table from 0 to 0.225 V, typ, clamps not added: 25.4 ohm
|   slope of the pullup table from 0 to 0.225 V, typ, clamps not added: 21 ohm
|   GND clamp passes 1 mA (typ) near -0.54 V on its own axis
|   POWER clamp passes 1 mA (typ) near -0.51 V on its own axis
|   rising waveform, R_fixture 50.000, V_fixture 0.0: 20-80 % time 375ps typ, 453ps min, 303ps max; typ from 0 V to 0.977 V
|   rising waveform, R_fixture 50.000, V_fixture 0.750: 20-80 % time 344ps typ, 374ps min, 284ps max; typ from 0.255 V to 1.28 V
|   falling waveform, R_fixture 50.000, V_fixture 0.750: 20-80 % time 481ps typ, 442ps min, 485ps max; typ from 1.28 V to 0.255 V
|   falling waveform, R_fixture 50.000, V_fixture 0.0: 20-80 % time 258ps typ, 261ps min, 252ps max; typ from 0.977 V to 0 V
[Pulldown]
|Voltage   I(typ)   I(min)   I(max)
-1.5V     -34.87mA   -38.73mA   -33.76mA
-850mV    -28.97mA   -31.05mA   -28.4mA
-600mV    -23.63mA   -24.79mA   -23.65mA
-350mV    -14.66mA   -15.1mA    -14.92mA
50mV      2.157mA    2.138mA    2.25mA
250mV     9.728mA    9.636mA    10.19mA
500mV     17.05mA    16.87mA    17.95mA
800mV     23.06mA    22.79mA    24.41mA
1.05V     25.89mA    25.61mA    27.52mA
1.35V     27.29mA    27.03mA    29.07mA
2.35V     28.47mA    28.7mA     30.17mA
3V        29.03mA    28.77mA    30.95mA
[Pullup]
|Voltage   I(typ)   I(min)   I(max)
-1.5V     123.8mA    126.1mA    104.7mA
-1.35V    105.5mA    109.9mA    93.88mA
-1.2V     92.59mA    95.57mA    85.71mA
-1.15V    87.55mA    89.22mA    82.57mA
-1V       72.57mA    72.1mA     70.63mA
-850mV    60.98mA    59.42mA    59.15mA
-150mV    9.109mA    8.517mA    9.454mA
100mV     -5.237mA   -4.811mA   -5.577mA
300mV     -13.52mA   -12.52mA   -14.38mA
550mV     -20.03mA   -18.7mA    -21.38mA
850mV     -22.99mA   -21.54mA   -24.82mA
3V        -26.97mA   -25.22mA   -29.11mA
[GND_clamp]
|Voltage   I(typ)   I(min)   I(max)
-1.5V     -960.1mA   -762.7mA   -1.034A
-1.14V    -347.3mA   -346mA     -275mA
-1.1V     -290.2mA   -305.8mA   -213.7mA
-1.06V    -236.5mA   -267.1mA   -161mA
-1.02V    -187.7mA   -229.9mA   -120.7mA
-940mV    -112.8mA   -161.5mA   -61.34mA
-860mV    -59.06mA   -107.5mA   -26.59mA
-780mV    -24.6mA    -67.97mA   -13.06mA
-700mV    -8.431mA   -38.1mA    -7.531mA
-620mV    -2.969mA   -17.61mA   -3.668mA
-460mV    -207.8uA   -1.521mA   -211uA
1.5V      0A         0A         0A
[POWER_clamp]
|Voltage   I(typ)   I(min)   I(max)
-1.5V     267.6mA    236.4mA    479.7mA
-1.1V     90.92mA    95.54mA    105.5mA
-1.06V    76.14mA    83.93mA    81.29mA
-1.02V    62.03mA    72.49mA    60.96mA
-980mV    49.07mA    61.38mA    45.36mA
-940mV    37.73mA    50.83mA    34.98mA
-900mV    28.44mA    41.02mA    28.75mA
-820mV    16.72mA    24.41mA    20.46mA
-740mV    10.6mA     12.83mA    13.51mA
-660mV    6.131mA    6.445mA    7.75mA
-540mV    1.697mA    1.964mA    1.966mA
1.5V      0A         0A         0A
[Ramp]
| variable   typ   min   max
dV/dt_r 0.586/0.379n   0.545/0.456n   0.630/0.307n
dV/dt_f 0.560/0.504n   0.534/0.448n   0.600/0.536n
R_load = 50.000
[Rising Waveform]
R_fixture= 50.000
V_fixture= 0.0
V_fixture_min= 0.0
V_fixture_max= 0.0
|time   V(typ)   V(min)   V(max)
0s        0V         0V         0V
334ps     -20.28mV   -767.3uV   -3.031mV
459ps     14.25mV    -18.27mV   146.1mV
590ps     160.8mV    -13.56mV   420.1mV
731ps     388mV      120.8mV    731.4mV
850ps     592.9mV    274.5mV    902.4mV
1.166ns   909.5mV    667.2mV    1.036V
1.456ns   965.9mV    847.9mV    1.048V
1.936ns   976mV      903mV      1.049V
10ns      976.6mV    909mV      1.049V
[Rising Waveform]
R_fixture= 50.000
V_fixture= 0.750
V_fixture_min= 0.713
V_fixture_max= 0.789
|time   V(typ)   V(min)   V(max)
0s        255mV      243mV      260.7mV
260ps     253.6mV    242.9mV    257.3mV
338ps     253.7mV    242.1mV    433mV
481ps     537.3mV    242.1mV    761.7mV
700ps     934.6mV    618.9mV    1.229V
824ps     1.126V     817.6mV    1.319V
949ps     1.22V      992.1mV    1.346V
1.188ns   1.269V     1.152V     1.356V
1.647ns   1.279V     1.201V     1.357V
10ns      1.279V     1.206V     1.357V
[Falling Waveform]
R_fixture= 50.000
V_fixture= 0.750
V_fixture_min= 0.713
V_fixture_max= 0.789
|time   V(typ)   V(min)   V(max)
0s        1.279V     1.206V     1.357V
253ps     1.278V     1.207V     1.356V
354ps     1.267V     1.205V     1.171V
493ps     1.037V     1.2V       947.1mV
753ps     682.7mV    834.1mV    594mV
913ps     494mV      612.7mV    432.4mV
1.114ns   355mV      399.3mV    332.9mV
1.359ns   289.8mV    293.4mV    288.4mV
2.239ns   255.6mV    244.5mV    260.9mV
10ns      255mV      243mV      260.7mV
[Falling Waveform]
R_fixture= 50.000
V_fixture= 0.0
V_fixture_min= 0.0
V_fixture_max= 0.0
|time   V(typ)   V(min)   V(max)
0s        976.6mV    909mV      1.049V
235ps     975.8mV    909mV      1.036V
329ps     943.8mV    908.2mV    722.9mV
446ps     592mV      897.9mV    399.6mV
534ps     382.1mV    721.2mV    233.8mV
653ps     183.6mV    419.2mV    87.71mV
863ps     29.53mV    106.3mV    10.32mV
1.039ns   6.089mV    23.17mV    2.553mV
1.353ns   1.794mV    3.382mV    1.215mV
10ns      0V         0V         0V
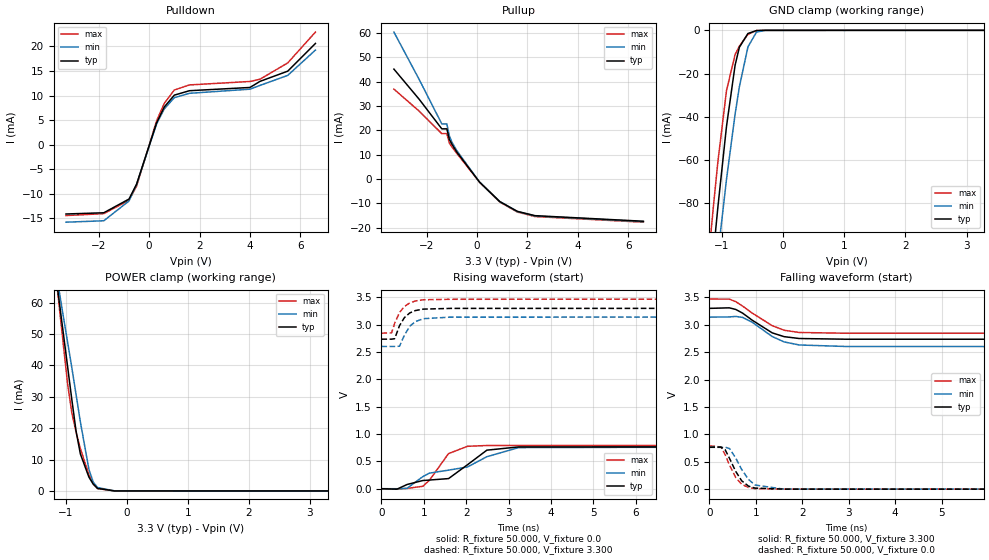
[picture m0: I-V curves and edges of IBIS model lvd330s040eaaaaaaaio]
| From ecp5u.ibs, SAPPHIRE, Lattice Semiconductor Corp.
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|   Model lvd330s040eaaaaaaaio
[Model] lvd330s040eaaaaaaaio
Model_type I/O
Polarity   Non-Inverting
Enable   Active-Low
Vinl =  0.800V
Vinh =  2.000V
Vmeas =  1.650V
Cref =  0.0F
Rref =  1.000M
Vref =  0.0V
C_comp   5.000pF   4.000pF   5.500pF
[Temperature Range]   25.000   0.125k   -40.000
[Voltage Range]   3.300V   3.140V   3.470V
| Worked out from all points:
|   slope of the pulldown table from 0 to 0.495 V, typ, clamps not added: 73.9 ohm
|   slope of the pullup table from 0 to 0.495 V, typ, clamps not added: 86.8 ohm
|   GND clamp passes 1 mA (typ) near -0.54 V on its own axis
|   POWER clamp passes 1 mA (typ) near -0.49 V on its own axis
|   rising waveform, R_fixture 50.000, V_fixture 0.0: 20-80 % time 1.24ns typ, 1.67ns min, 436ps max; typ from 0 V to 0.766 V
|   rising waveform, R_fixture 50.000, V_fixture 3.300: 20-80 % time 255ps typ, 259ps min, 269ps max; typ from 2.74 V to 3.3 V
|   falling waveform, R_fixture 50.000, V_fixture 3.300: 20-80 % time 606ps typ, 585ps min, 676ps max; typ from 3.3 V to 2.74 V
|   falling waveform, R_fixture 50.000, V_fixture 0.0: 20-80 % time 289ps typ, 327ps min, 275ps max; typ from 0.766 V to 0 V
[Pulldown]
|Voltage   I(typ)   I(min)   I(max)
-3.3V     -14.12mA   -15.79mA   -14.44mA
-1.8V     -13.87mA   -15.5mA    -14.05mA
-800mV    -11.08mA   -11.47mA   -11.33mA
-500mV    -8.065mA   -8.084mA   -8.464mA
300mV     4.505mA    4.281mA    4.905mA
600mV     7.672mA    7.282mA    8.406mA
1V        10.09mA    9.572mA    11.13mA
1.6V      10.99mA    10.46mA    12.17mA
4V        11.65mA    11.3mA     12.87mA
4.4V      12.89mA    12.07mA    13.33mA
5.5V      14.97mA    14.11mA    16.65mA
6.6V      20.62mA    19.27mA    22.93mA
[Pullup]
|Voltage   I(typ)   I(min)   I(max)
-3.3V     45.12mA    60.32mA    36.91mA
-2.3V     32.78mA    40.92mA    27.9mA
-1.4V     20.6mA     22.62mA    18.63mA
-1.2V     20.6mA     22.62mA    18.63mA
-1.1V     16.28mA    17.72mA    14.76mA
-1V       14.3mA     15.15mA    13.16mA
-800mV    10.99mA    11.6mA     10.49mA
100mV     -1.283mA   -1.261mA   -1.317mA
900mV     -9.251mA   -9.225mA   -9.451mA
1.6V      -13.28mA   -13.35mA   -13.56mA
2.3V      -15.04mA   -15.17mA   -15.41mA
6.6V      -17.33mA   -17.5mA    -17.72mA
[GND_clamp]
|Voltage   I(typ)   I(min)   I(max)
-3.3V     -912.7mA   -861.5mA   -922.5mA
-1.27V    -145.6mA   -163.6mA   -123.5mA
-1.2V     -123.4mA   -142.6mA   -101.4mA
-1.13V    -102mA     -122.4mA   -80.37mA
-1.06V    -81.56mA   -103.5mA   -60.64mA
-920mV    -44.4mA    -68.93mA   -27.87mA
-780mV    -16.18mA   -38.86mA   -11.24mA
-710mV    -7.839mA   -26.12mA   -7.318mA
-570mV    -1.464mA   -7.654mA   -1.852mA
-430mV    -105.8uA   -801.1uA   -99.73uA
-290mV    -1.56uA    -33.42uA   -868.4nA
3.28V     0A         0A         0A
[POWER_clamp]
|Voltage   I(typ)   I(min)   I(max)
-3.28V    471.5mA    421.2mA    516.6mA
-1.18V    71.72mA    72.75mA    72.14mA
-1.11V    60.88mA    63.98mA    59.38mA
-970mV    39.73mA    47.46mA    34.21mA
-900mV    29.12mA    39.28mA    24.89mA
-830mV    19.01mA    30.67mA    18.7mA
-760mV    11.8mA     22.01mA    13.51mA
-620mV    4.416mA    6.921mA    5.219mA
-550mV    2.174mA    2.865mA    2.414mA
-480mV    813uA      1.102mA    758.3uA
-200mV    3.62uA     22.61uA    424nA
3.3V      0A         0A         0A
[Ramp]
| variable   typ   min   max
dV/dt_r 0.460/1.202n   0.458/1.651n   0.475/0.445n
dV/dt_f 0.338/0.612n   0.322/0.595n   0.375/0.683n
R_load = 50.000
[Rising Waveform]
R_fixture= 50.000
V_fixture= 0.0
V_fixture_min= 0.0
V_fixture_max= 0.0
|time   V(typ)   V(min)   V(max)
0s        0V         0V         0V
367ps     -8.56mV    -500.4uV   -7.617mV
605ps     76.98mV    7.013mV    5.424mV
977ps     149.7mV    220.9mV    44.21mV
1.131ns   158.2mV    284.9mV    153.3mV
1.584ns   184.9mV    339.9mV    642.4mV
2.031ns   438.6mV    397.7mV    775.8mV
2.488ns   705.2mV    585.5mV    790.3mV
3.238ns   764.3mV    752.2mV    791.8mV
10ns      765.9mV    763.5mV    791.9mV
[Rising Waveform]
R_fixture= 50.000
V_fixture= 3.300
V_fixture_min= 3.140
V_fixture_max= 3.470
|time   V(typ)   V(min)   V(max)
0s        2.736V     2.603V     2.846V
239ps     2.736V     2.603V     2.852V
312ps     2.745V     2.603V     3.026V
426ps     2.982V     2.607V     3.223V
541ps     3.13V      2.807V     3.333V
668ps     3.216V     2.972V     3.399V
801ps     3.26V      3.058V     3.435V
991ps     3.286V     3.111V     3.457V
1.614ns   3.299V     3.139V     3.466V
10ns      3.3V       3.14V      3.47V
[Falling Waveform]
R_fixture= 50.000
V_fixture= 3.300
V_fixture_min= 3.140
V_fixture_max= 3.470
|time   V(typ)   V(min)   V(max)
0s        3.3V       3.14V      3.47V
429ps     3.31V      3.144V     3.469V
569ps     3.28V      3.153V     3.422V
716ps     3.213V     3.135V     3.341V
923ps     3.084V     3.047V     3.214V
1.353ns   2.853V     2.786V     2.984V
1.609ns   2.784V     2.688V     2.901V
1.933ns   2.75V      2.632V     2.86V
2.953ns   2.737V     2.604V     2.846V
10ns      2.736V     2.603V     2.846V
[Falling Waveform]
R_fixture= 50.000
V_fixture= 0.0
V_fixture_min= 0.0
V_fixture_max= 0.0
|time   V(typ)   V(min)   V(max)
0s        765.9mV    763.5mV    791.8mV
250ps     767.5mV    763.5mV    769.7mV
340ps     719.8mV    766.1mV    628.3mV
433ps     563.3mV    741.5mV    440.1mV
566ps     326.1mV    570.6mV    213.6mV
695ps     153.7mV    359.4mV    89.77mV
842ps     55.24mV    178.1mV    29.77mV
982ps     19.56mV    75.42mV    10.04mV
1.599ns   639.8uV    1.688mV    664.8uV
10ns      0V         0V         0V
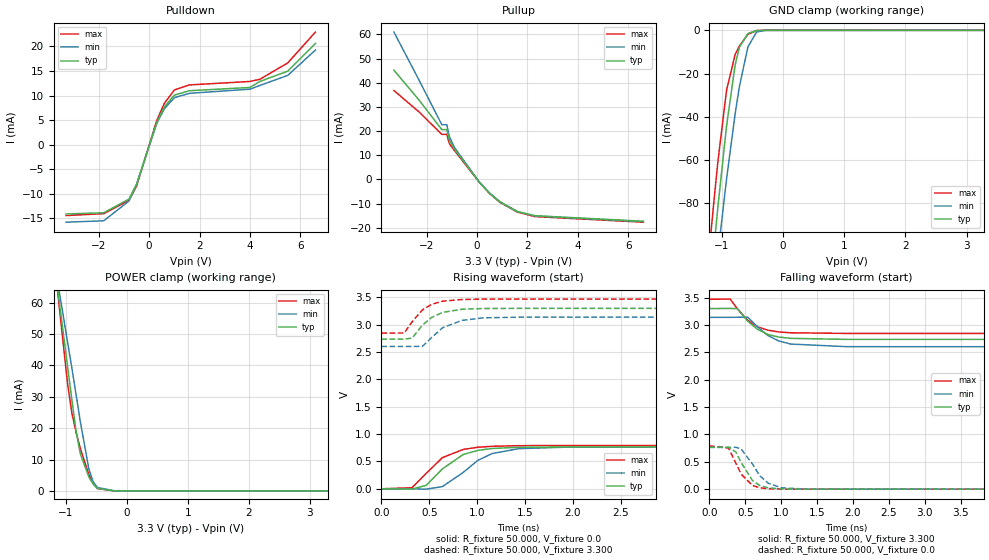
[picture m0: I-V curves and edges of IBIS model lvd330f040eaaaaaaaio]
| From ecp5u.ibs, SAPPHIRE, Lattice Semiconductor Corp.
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|   Model lvd330f040eaaaaaaaio
[Model] lvd330f040eaaaaaaaio
Model_type I/O
Polarity   Non-Inverting
Enable   Active-Low
Vinl =  0.800V
Vinh =  2.000V
Vmeas =  1.650V
Cref =  0.0F
Rref =  1.000M
Vref =  0.0V
C_comp   5.000pF   4.000pF   5.500pF
[Temperature Range]   25.000   0.125k   -40.000
[Voltage Range]   3.300V   3.140V   3.470V
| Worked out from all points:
|   slope of the pulldown table from 0 to 0.495 V, typ, clamps not added: 73.9 ohm
|   slope of the pullup table from 0 to 0.495 V, typ, clamps not added: 86.8 ohm
|   GND clamp passes 1 mA (typ) near -0.54 V on its own axis
|   POWER clamp passes 1 mA (typ) near -0.49 V on its own axis
|   rising waveform, R_fixture 50.000, V_fixture 0.0: 20-80 % time 307ps typ, 345ps min, 291ps max; typ from 0 V to 0.766 V
|   rising waveform, R_fixture 50.000, V_fixture 3.300: 20-80 % time 219ps typ, 243ps min, 200ps max; typ from 2.74 V to 3.3 V
|   falling waveform, R_fixture 50.000, V_fixture 3.300: 20-80 % time 312ps typ, 338ps min, 302ps max; typ from 3.3 V to 2.74 V
|   falling waveform, R_fixture 50.000, V_fixture 0.0: 20-80 % time 206ps typ, 232ps min, 187ps max; typ from 0.766 V to 0 V
[Pulldown]
|Voltage   I(typ)   I(min)   I(max)
-3.3V     -14.12mA   -15.79mA   -14.44mA
-1.8V     -13.87mA   -15.5mA    -14.05mA
-800mV    -11.08mA   -11.47mA   -11.33mA
-500mV    -8.065mA   -8.084mA   -8.464mA
300mV     4.505mA    4.281mA    4.905mA
600mV     7.672mA    7.282mA    8.406mA
1V        10.09mA    9.572mA    11.13mA
1.6V      10.99mA    10.46mA    12.17mA
4V        11.65mA    11.3mA     12.87mA
4.4V      12.89mA    12.07mA    13.33mA
5.5V      14.97mA    14.11mA    16.65mA
6.6V      20.62mA    19.27mA    22.93mA
[Pullup]
|Voltage   I(typ)   I(min)   I(max)
-3.3V     45.2mA     60.96mA    36.78mA
-2.3V     32.8mA     41.03mA    27.88mA
-1.4V     20.6mA     22.63mA    18.63mA
-1.2V     20.6mA     22.63mA    18.63mA
-1.1V     16.28mA    17.72mA    14.76mA
-900mV    12.53mA    13.27mA    11.96mA
100mV     -1.283mA   -1.261mA   -1.317mA
500mV     -5.756mA   -5.702mA   -5.893mA
900mV     -9.251mA   -9.225mA   -9.451mA
1.6V      -13.28mA   -13.35mA   -13.56mA
2.3V      -15.04mA   -15.17mA   -15.41mA
6.6V      -17.33mA   -17.5mA    -17.72mA
[GND_clamp]
|Voltage   I(typ)   I(min)   I(max)
-3.3V     -912.7mA   -861.5mA   -922.5mA
-1.27V    -145.6mA   -163.6mA   -123.5mA
-1.2V     -123.4mA   -142.6mA   -101.4mA
-1.13V    -102mA     -122.4mA   -80.37mA
-1.06V    -81.56mA   -103.5mA   -60.64mA
-920mV    -44.4mA    -68.93mA   -27.87mA
-780mV    -16.18mA   -38.86mA   -11.24mA
-710mV    -7.839mA   -26.12mA   -7.318mA
-570mV    -1.464mA   -7.654mA   -1.852mA
-430mV    -105.8uA   -801.1uA   -99.73uA
-290mV    -1.56uA    -33.42uA   -868.4nA
3.28V     0A         0A         0A
[POWER_clamp]
|Voltage   I(typ)   I(min)   I(max)
-3.28V    471.5mA    421.2mA    516.6mA
-1.18V    71.72mA    72.75mA    72.14mA
-1.11V    60.88mA    63.98mA    59.38mA
-970mV    39.73mA    47.46mA    34.21mA
-900mV    29.12mA    39.28mA    24.89mA
-830mV    19.01mA    30.67mA    18.7mA
-760mV    11.8mA     22.01mA    13.51mA
-620mV    4.416mA    6.921mA    5.219mA
-550mV    2.174mA    2.865mA    2.414mA
-480mV    813uA      1.102mA    758.3uA
-200mV    3.62uA     22.61uA    424nA
3.3V      0A         0A         0A
[Ramp]
| variable   typ   min   max
dV/dt_r 0.460/0.311n   0.458/0.346n   0.475/0.292n
dV/dt_f 0.338/0.317n   0.322/0.336n   0.375/0.301n
R_load = 50.000
[Rising Waveform]
R_fixture= 50.000
V_fixture= 0.0
V_fixture_min= 0.0
V_fixture_max= 0.0
|time   V(typ)   V(min)   V(max)
0s        0V         0V         0V
319ps     -6.333mV   -79.81uV   18.62mV
467ps     62.16mV    -7.378mV   281.7mV
637ps     364.7mV    40.03mV    570mV
854ps     627.1mV    299.6mV    719.5mV
1.005ns   701.8mV    518.1mV    758.8mV
1.154ns   736.1mV    643.4mV    776.6mV
1.432ns   758.8mV    733.3mV    788.3mV
1.926ns   765.4mV    760.9mV    791.6mV
10ns      765.9mV    763.5mV    791.9mV
[Rising Waveform]
R_fixture= 50.000
V_fixture= 3.300
V_fixture_min= 3.140
V_fixture_max= 3.470
|time   V(typ)   V(min)   V(max)
0s        2.736V     2.603V     2.846V
238ps     2.736V     2.603V     2.85V
321ps     2.757V     2.603V     3.057V
427ps     2.992V     2.605V     3.271V
522ps     3.132V     2.762V     3.373V
638ps     3.226V     2.945V     3.431V
841ps     3.284V     3.08V      3.462V
1.06ns    3.297V     3.126V     3.469V
1.452ns   3.3V       3.139V     3.47V
10ns      3.3V       3.14V      3.47V
[Falling Waveform]
R_fixture= 50.000
V_fixture= 3.300
V_fixture_min= 3.140
V_fixture_max= 3.470
|time   V(typ)   V(min)   V(max)
0s        3.3V       3.14V      3.47V
289ps     3.303V     3.14V      3.474V
390ps     3.299V     3.142V     3.296V
533ps     3.071V     3.144V     3.088V
670ps     2.922V     2.968V     2.968V
820ps     2.825V     2.803V     2.904V
969ps     2.779V     2.708V     2.873V
1.131ns   2.756V     2.652V     2.858V
1.911ns   2.737V     2.604V     2.846V
10ns      2.736V     2.603V     2.846V
[Falling Waveform]
R_fixture= 50.000
V_fixture= 0.0
V_fixture_min= 0.0
V_fixture_max= 0.0
|time   V(typ)   V(min)   V(max)
0s        765.9mV    763.5mV    791.8mV
269ps     765.6mV    763.2mV    749.9mV
370ps     677.8mV    765.3mV    471.5mV
443ps     485.6mV    733.2mV    275.5mV
600ps     159.4mV    461.1mV    67.23mV
702ps     66.66mV    244.8mV    25.81mV
821ps     23.06mV    107.1mV    8.501mV
1.011ns   4.353mV    23.66mV    1.479mV
1.361ns   244.8uV    1.445mV    68.1uV
10ns      0V         0V         0V
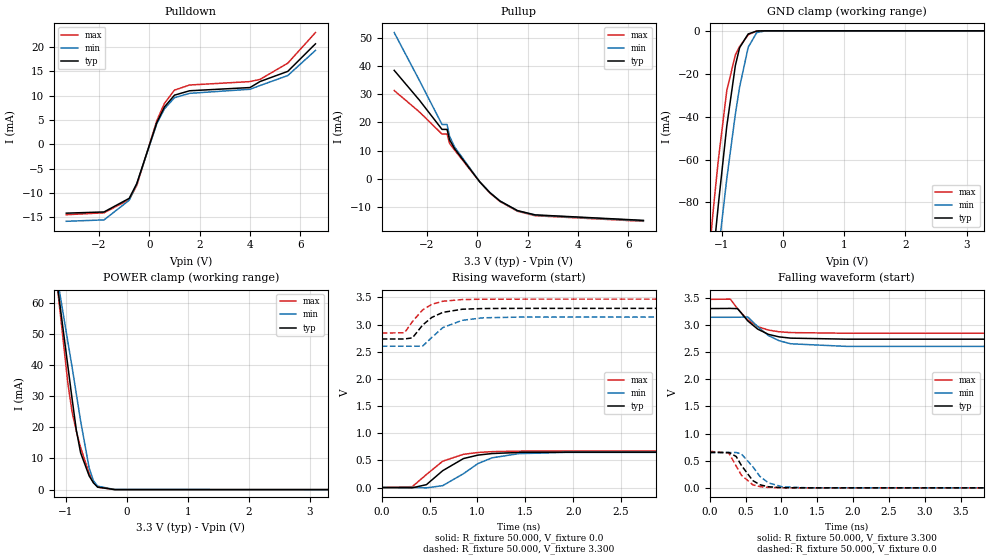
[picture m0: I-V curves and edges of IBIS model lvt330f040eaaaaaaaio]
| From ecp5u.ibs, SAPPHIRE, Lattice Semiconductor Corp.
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|   Model lvt330f040eaaaaaaaio
[Model] lvt330f040eaaaaaaaio
Model_type I/O
Polarity   Non-Inverting
Enable   Active-Low
Vinl =  0.800V
Vinh =  2.000V
Vmeas =  1.650V
Cref =  0.0F
Rref =  1.000M
Vref =  0.0V
C_comp   5.000pF   4.000pF   5.500pF
[Temperature Range]   25.000   0.125k   -40.000
[Voltage Range]   3.300V   3.140V   3.470V
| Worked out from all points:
|   slope of the pulldown table from 0 to 0.495 V, typ, clamps not added: 73.9 ohm
|   slope of the pullup table from 0 to 0.495 V, typ, clamps not added: 102 ohm
|   GND clamp passes 1 mA (typ) near -0.54 V on its own axis
|   POWER clamp passes 1 mA (typ) near -0.49 V on its own axis
|   rising waveform, R_fixture 50.000, V_fixture 0.0: 20-80 % time 307ps typ, 345ps min, 291ps max; typ from 0 V to 0.652 V
|   rising waveform, R_fixture 50.000, V_fixture 3.300: 20-80 % time 219ps typ, 243ps min, 200ps max; typ from 2.74 V to 3.3 V
|   falling waveform, R_fixture 50.000, V_fixture 3.300: 20-80 % time 312ps typ, 338ps min, 302ps max; typ from 3.3 V to 2.74 V
|   falling waveform, R_fixture 50.000, V_fixture 0.0: 20-80 % time 206ps typ, 232ps min, 187ps max; typ from 0.652 V to 0 V
[Pulldown]
|Voltage   I(typ)   I(min)   I(max)
-3.3V     -14.12mA   -15.79mA   -14.44mA
-1.8V     -13.87mA   -15.5mA    -14.05mA
-800mV    -11.08mA   -11.47mA   -11.33mA
-500mV    -8.065mA   -8.084mA   -8.464mA
300mV     4.505mA    4.281mA    4.905mA
600mV     7.672mA    7.282mA    8.406mA
1V        10.09mA    9.572mA    11.13mA
1.6V      10.99mA    10.46mA    12.17mA
4V        11.65mA    11.3mA     12.87mA
4.4V      12.89mA    12.07mA    13.33mA
5.5V      14.97mA    14.11mA    16.65mA
6.6V      20.62mA    19.27mA    22.93mA
[Pullup]
|Voltage   I(typ)   I(min)   I(max)
-3.3V     38.45mA    51.85mA    31.29mA
-2.3V     27.9mA     34.9mA     23.72mA
-1.4V     17.52mA    19.25mA    15.85mA
-1.2V     17.52mA    19.25mA    15.85mA
-1.1V     13.85mA    15.07mA    12.55mA
-900mV    10.66mA    11.29mA    10.18mA
100mV     -1.091mA   -1.073mA   -1.12mA
500mV     -4.896mA   -4.85mA    -5.012mA
900mV     -7.869mA   -7.846mA   -8.039mA
1.6V      -11.29mA   -11.36mA   -11.53mA
2.3V      -12.79mA   -12.9mA    -13.1mA
6.6V      -14.74mA   -14.89mA   -15.07mA
[GND_clamp]
|Voltage   I(typ)   I(min)   I(max)
-3.3V     -912.7mA   -861.5mA   -922.5mA
-1.27V    -145.6mA   -163.6mA   -123.5mA
-1.2V     -123.4mA   -142.6mA   -101.4mA
-1.13V    -102mA     -122.4mA   -80.37mA
-1.06V    -81.56mA   -103.5mA   -60.64mA
-920mV    -44.4mA    -68.93mA   -27.87mA
-780mV    -16.18mA   -38.86mA   -11.24mA
-710mV    -7.839mA   -26.12mA   -7.318mA
-570mV    -1.464mA   -7.654mA   -1.852mA
-430mV    -105.8uA   -801.1uA   -99.73uA
-290mV    -1.56uA    -33.42uA   -868.4nA
3.28V     0A         0A         0A
[POWER_clamp]
|Voltage   I(typ)   I(min)   I(max)
-3.28V    471.5mA    421.2mA    516.6mA
-1.18V    71.72mA    72.75mA    72.14mA
-1.11V    60.88mA    63.98mA    59.38mA
-970mV    39.73mA    47.46mA    34.21mA
-900mV    29.12mA    39.28mA    24.89mA
-830mV    19.01mA    30.67mA    18.7mA
-760mV    11.8mA     22.01mA    13.51mA
-620mV    4.416mA    6.921mA    5.219mA
-550mV    2.174mA    2.865mA    2.414mA
-480mV    813uA      1.102mA    758.3uA
-200mV    3.62uA     22.61uA    424nA
3.3V      0A         0A         0A
[Ramp]
| variable   typ   min   max
dV/dt_r   0.394/0.311n   0.393/0.346n   0.407/0.292n
dV/dt_f   0.338/0.317n   0.322/0.336n   0.375/0.301n
R_load = 50.000
[Rising Waveform]
R_fixture= 50.000
V_fixture= 0.0
V_fixture_min= 0.0
V_fixture_max= 0.0
|time   V(typ)   V(min)   V(max)
0s        0V         0V         0V
319ps     -5.387mV   -79.81uV   15.84mV
467ps     52.87mV    -6.276mV   239.6mV
637ps     310.2mV    34.05mV    484.8mV
854ps     533.4mV    254.8mV    612mV
1.005ns   596.9mV    440.7mV    645.4mV
1.154ns   626.1mV    547.3mV    660.6mV
1.432ns   645.4mV    623.8mV    670.5mV
1.926ns   651mV      647.2mV    673.3mV
10ns      651.5mV    649.4mV    673.5mV
[Rising Waveform]
R_fixture= 50.000
V_fixture= 3.300
V_fixture_min= 3.140
V_fixture_max= 3.470
|time   V(typ)   V(min)   V(max)
0s        2.736V     2.603V     2.846V
238ps     2.736V     2.603V     2.85V
321ps     2.757V     2.603V     3.057V
427ps     2.992V     2.605V     3.271V
522ps     3.132V     2.762V     3.373V
638ps     3.226V     2.945V     3.431V
841ps     3.284V     3.08V      3.462V
1.06ns    3.297V     3.126V     3.469V
1.452ns   3.3V       3.139V     3.47V
10ns      3.3V       3.14V      3.47V
[Falling Waveform]
R_fixture= 50.000
V_fixture= 3.300
V_fixture_min= 3.140
V_fixture_max= 3.470
|time   V(typ)   V(min)   V(max)
0s        3.3V       3.14V      3.47V
289ps     3.303V     3.14V      3.474V
390ps     3.299V     3.142V     3.296V
533ps     3.071V     3.144V     3.088V
670ps     2.922V     2.968V     2.968V
820ps     2.825V     2.803V     2.904V
969ps     2.779V     2.708V     2.873V
1.131ns   2.756V     2.652V     2.858V
1.911ns   2.737V     2.604V     2.846V
10ns      2.736V     2.603V     2.846V
[Falling Waveform]
R_fixture= 50.000
V_fixture= 0.0
V_fixture_min= 0.0
V_fixture_max= 0.0
|time   V(typ)   V(min)   V(max)
0s        651.5mV    649.4mV    673.5mV
269ps     651.2mV    649.2mV    637.8mV
370ps     576.6mV    651mV      401mV
443ps     413mV      623.7mV    234.3mV
600ps     135.6mV    392.2mV    57.19mV
702ps     56.7mV     208.3mV    21.95mV
821ps     19.62mV    91.12mV    7.231mV
1.011ns   3.702mV    20.12mV    1.258mV
1.361ns   208.2uV    1.229mV    68.1uV
10ns      0V         0V         0V
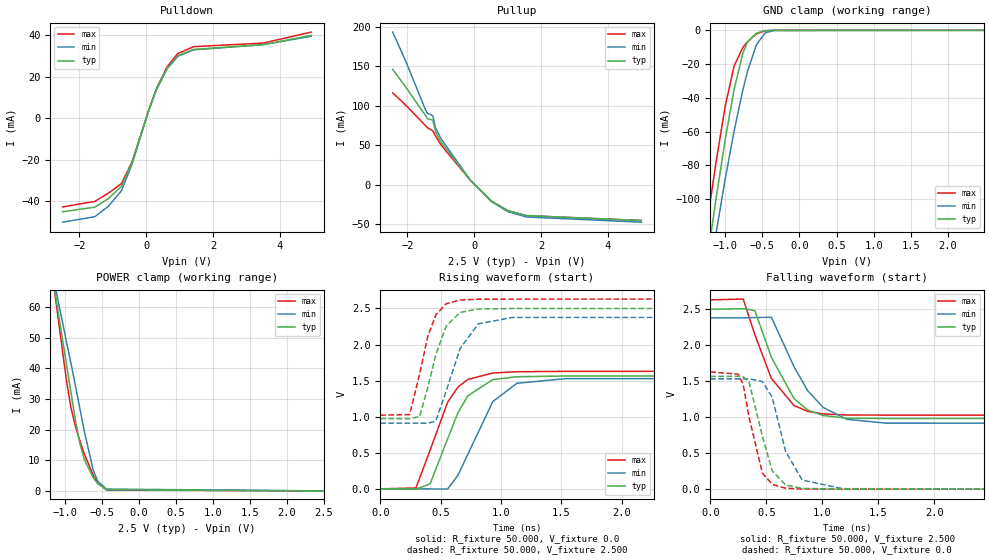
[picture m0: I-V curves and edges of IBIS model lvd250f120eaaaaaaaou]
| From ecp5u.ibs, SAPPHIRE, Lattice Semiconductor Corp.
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|   Model lvd250f120eaaaaaaaou
[Model] lvd250f120eaaaaaaaou
Model_type  Output
Polarity   Non-Inverting
Enable   Active-Low
Vmeas =  1.250V
Cref =  0.0F
Rref =  1.000M
Vref =  0.0V
C_comp   5.000pF   4.000pF   5.500pF
[Temperature Range]   25.000   0.125k   -40.000
[Voltage Range]   2.500V   2.380V   2.630V
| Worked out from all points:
|   slope of the pulldown table from 0 to 0.375 V, typ, clamps not added: 22.6 ohm
|   slope of the pullup table from 0 to 0.375 V, typ, clamps not added: 23.7 ohm
|   GND clamp passes 1 mA (typ) near -0.54 V on its own axis
|   POWER clamp passes 1 mA (typ) near -0.49 V on its own axis
|   rising waveform, R_fixture 50.000, V_fixture 0.0: 20-80 % time 230ps typ, 260ps min, 218ps max; typ from 0 V to 1.57 V
|   rising waveform, R_fixture 50.000, V_fixture 2.500: 20-80 % time 151ps typ, 182ps min, 136ps max; typ from 0.973 V to 2.5 V
|   falling waveform, R_fixture 50.000, V_fixture 2.500: 20-80 % time 269ps typ, 316ps min, 255ps max; typ from 2.5 V to 0.973 V
|   falling waveform, R_fixture 50.000, V_fixture 0.0: 20-80 % time 135ps typ, 163ps min, 123ps max; typ from 1.57 V to 0 V
[Pulldown]
|Voltage   I(typ)   I(min)   I(max)
-2.5V     -45.07mA   -50.12mA   -42.75mA
-1.54V    -42.89mA   -47.46mA   -40.12mA
-1.14V    -38.8mA    -42.57mA   -36.2mA
-740mV    -32.8mA    -34.91mA   -31.49mA
-420mV    -21.11mA   -21.89mA   -20.84mA
60mV      3.118mA    3.096mA    3.169mA
300mV     13.77mA    13.66mA    14.07mA
620mV     23.97mA    23.75mA    24.66mA
940mV     30.11mA    29.82mA    31.17mA
1.42V     33.22mA    32.98mA    34.53mA
3.5V      35.44mA    35.53mA    36.25mA
4.94V     39.95mA    39.54mA    41.55mA
[Pullup]
|Voltage   I(typ)   I(min)   I(max)
-2.44V    146mA      193.2mA    116.3mA
-2.04V    123mA      155.4mA    100.3mA
-1.48V    88.98mA    97.05mA    75.83mA
-1.4V     83.62mA    90.35mA    72.23mA
-1.24V    81.93mA    87.51mA    68.33mA
-1.16V    67.84mA    72.48mA    61.87mA
-1V       54.24mA    58.71mA    50.67mA
-120mV    5.946mA    6.135mA    5.92mA
520mV     -20.73mA   -21.37mA   -20.78mA
1V        -32.6mA    -33.92mA   -32.6mA
1.56V     -38.91mA   -40.68mA   -39.04mA
5V        -45.23mA   -47.3mA    -45.24mA
[GND_clamp]
|Voltage   I(typ)   I(min)   I(max)
-2.5V     -600.3mA   -576.2mA   -594.4mA
-1.24V    -136mA     -154.5mA   -113.9mA
-1.18V    -117.2mA   -136.7mA   -95.27mA
-1.12V    -99.04mA   -119.7mA   -77.45mA
-1V       -64.9mA    -88.21mA   -45.19mA
-880mV    -35.12mA   -59.82mA   -21.21mA
-760mV    -13.33mA   -35.03mA   -10mA
-700mV    -7.01mA    -24.46mA   -6.829mA
-580mV    -1.679mA   -8.593mA   -2.127mA
-460mV    -210.1uA   -1.441mA   -213.7uA
-340mV    -8.598uA   -109.2uA   -6.553uA
2.48V     0A         0A         0A
[POWER_clamp]
|Voltage   I(typ)   I(min)   I(max)
-2.48V    301.8mA    269mA      334.4mA
-1.16V    68.59mA    70.21mA    68.47mA
-1.1V     59.33mA    62.74mA    57.51mA
-980mV    41.18mA    48.59mA    35.82mA
-920mV    32.13mA    41.65mA    27.11mA
-860mV    23.04mA    34.34mA    21.08mA
-800mV    15.49mA    26.9mA     16.35mA
-740mV    10.29mA    19.52mA    12.1mA
-620mV    4.381mA    6.888mA    5.184mA
-560mV    2.412mA    3.25mA     2.719mA
-440mV    397.7uA    604uA      311uA
2.5V      0A         0A         0A
[Ramp]
| variable   typ   min   max
dV/dt_r 0.940/0.232n   0.919/0.263n   0.978/0.221n
dV/dt_f 0.916/0.269n   0.882/0.314n   0.965/0.256n
R_load = 50.000
[Rising Waveform]
R_fixture= 50.000
V_fixture= 0.0
V_fixture_min= 0.0
V_fixture_max= 0.0
|time   V(typ)   V(min)   V(max)
0s        0V         0V         0V
295ps     -4.969mV   -128.8uV   11.06mV
412ps     67.41mV    -1.643mV   532.5mV
557ps     689.5mV    -3.146mV   1.199V
642ps     1.051V     184.5mV    1.408V
725ps     1.29V      479mV      1.516V
932ps     1.514V     1.21V      1.605V
1.132ns   1.553V     1.463V     1.623V
1.535ns   1.564V     1.527V     1.628V
10ns      1.567V     1.532V     1.63V
[Rising Waveform]
R_fixture= 50.000
V_fixture= 2.500
V_fixture_min= 2.380
V_fixture_max= 2.630
|time   V(typ)   V(min)   V(max)
0s        973.5mV    909.7mV    1.021V
243ps     973mV      909.7mV    1.029V
325ps     1.001V     909.4mV    1.585V
392ps     1.395V     909mV      2.103V
459ps     1.855V     937.4mV    2.408V
545ps     2.254V     1.351V     2.565V
660ps     2.445V     1.942V     2.617V
811ps     2.492V     2.286V     2.628V
1.091ns   2.499V     2.375V     2.63V
10ns      2.5V       2.38V      2.63V
[Falling Waveform]
R_fixture= 50.000
V_fixture= 2.500
V_fixture_min= 2.380
V_fixture_max= 2.630
|time   V(typ)   V(min)   V(max)
0s        2.5V       2.38V      2.63V
294ps     2.507V     2.38V      2.641V
398ps     2.481V     2.384V     2.145V
545ps     1.833V     2.388V     1.539V
747ps     1.257V     1.702V     1.162V
870ps     1.099V     1.366V     1.081V
1.007ns   1.023V     1.135V     1.045V
1.22ns    986mV      970.3mV    1.03V
1.561ns   981.9mV    917.9mV    1.029V
10ns      973.5mV    909.7mV    1.021V
[Falling Waveform]
R_fixture= 50.000
V_fixture= 0.0
V_fixture_min= 0.0
V_fixture_max= 0.0
|time   V(typ)   V(min)   V(max)
0s        1.567V     1.532V     1.63V
249ps     1.568V     1.532V     1.597V
294ps     1.562V     1.532V     1.452V
346ps     1.49V      1.534V     1.002V
464ps     740.3mV    1.495V     227.3mV
552ps     257mV      1.278V     66.51mV
672ps     58.61mV    526.4mV    12.98mV
820ps     10.46mV    126.1mV    2.461mV
1.181ns   673.4uV    6.526mV    146.5uV
10ns      0V         0V         0V
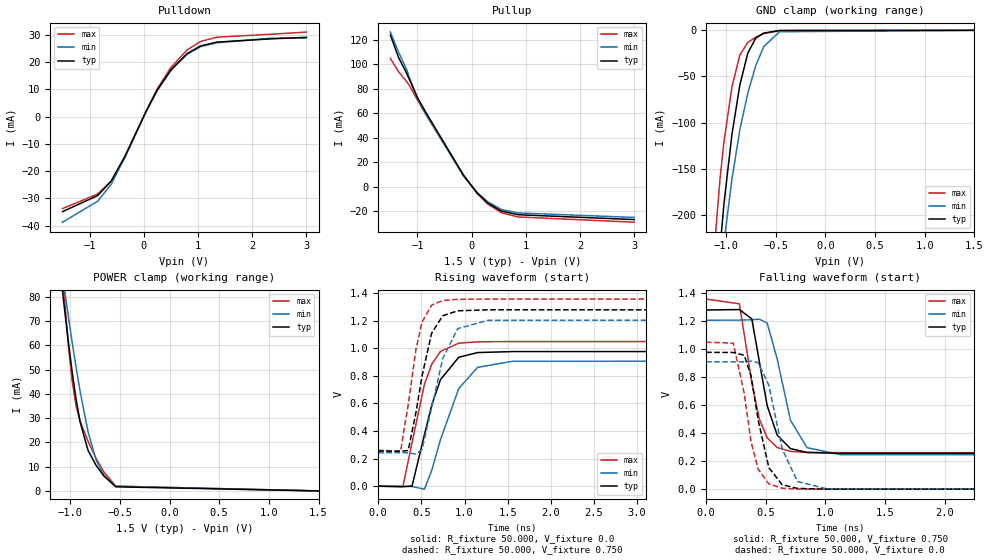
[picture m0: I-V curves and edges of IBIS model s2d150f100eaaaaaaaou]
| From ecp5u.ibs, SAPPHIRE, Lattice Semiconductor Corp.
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|   Model s2d150f100eaaaaaaaou
[Model] s2d150f100eaaaaaaaou
Model_type  Output
Polarity   Non-Inverting
Enable   Active-Low
Vmeas =  0.750V
Cref =  30.000pF
Rref =  50.000
Vref =  0.750V
C_comp   5.000pF   4.000pF   5.500pF
[Temperature Range]   25.000   0.125k   -40.000
[Voltage Range]   1.500V   1.430V   1.580V
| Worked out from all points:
|   slope of the pulldown table from 0 to 0.225 V, typ, clamps not added: 25.4 ohm
|   slope of the pullup table from 0 to 0.225 V, typ, clamps not added: 21 ohm
|   GND clamp passes 1 mA (typ) near -0.54 V on its own axis
|   POWER clamp passes 1 mA (typ) near -0.51 V on its own axis
|   rising waveform, R_fixture 50.000, V_fixture 0.0: 20-80 % time 254ps typ, 298ps min, 227ps max; typ from 0 V to 0.977 V
|   rising waveform, R_fixture 50.000, V_fixture 0.750: 20-80 % time 184ps typ, 218ps min, 160ps max; typ from 0.255 V to 1.28 V
|   falling waveform, R_fixture 50.000, V_fixture 0.750: 20-80 % time 141ps typ, 154ps min, 131ps max; typ from 1.28 V to 0.255 V
|   falling waveform, R_fixture 50.000, V_fixture 0.0: 20-80 % time 125ps typ, 144ps min, 115ps max; typ from 0.977 V to 0 V
[Pulldown]
|Voltage   I(typ)   I(min)   I(max)
-1.5V     -34.87mA   -38.73mA   -33.76mA
-850mV    -28.97mA   -31.05mA   -28.4mA
-600mV    -23.63mA   -24.79mA   -23.65mA
-350mV    -14.66mA   -15.1mA    -14.92mA
50mV      2.157mA    2.138mA    2.25mA
250mV     9.728mA    9.636mA    10.19mA
500mV     17.05mA    16.87mA    17.95mA
800mV     23.06mA    22.79mA    24.41mA
1.05V     25.89mA    25.61mA    27.52mA
1.35V     27.29mA    27.03mA    29.07mA
2.35V     28.47mA    28.7mA     30.17mA
3V        29.03mA    28.77mA    30.95mA
[Pullup]
|Voltage   I(typ)   I(min)   I(max)
-1.5V     123.8mA    126.2mA    104.7mA
-1.35V    105.5mA    109.9mA    93.88mA
-1.2V     92.59mA    95.57mA    85.71mA
-1.15V    87.55mA    89.23mA    82.57mA
-1V       72.57mA    72.1mA     70.63mA
-850mV    60.98mA    59.42mA    59.15mA
-150mV    9.109mA    8.517mA    9.454mA
100mV     -5.237mA   -4.811mA   -5.577mA
300mV     -13.52mA   -12.52mA   -14.38mA
550mV     -20.03mA   -18.7mA    -21.38mA
850mV     -22.99mA   -21.54mA   -24.82mA
3V        -26.97mA   -25.22mA   -29.11mA
[GND_clamp]
|Voltage   I(typ)   I(min)   I(max)
-1.5V     -960.1mA   -762.7mA   -1.034A
-1.14V    -347.3mA   -346mA     -275mA
-1.1V     -290.2mA   -305.8mA   -213.7mA
-1.06V    -236.5mA   -267.1mA   -161mA
-1.02V    -187.7mA   -229.9mA   -120.7mA
-940mV    -112.8mA   -161.5mA   -61.34mA
-860mV    -59.06mA   -107.5mA   -26.59mA
-780mV    -24.6mA    -67.97mA   -13.06mA
-700mV    -8.431mA   -38.1mA    -7.531mA
-620mV    -2.969mA   -17.61mA   -3.668mA
-460mV    -207.8uA   -1.521mA   -211uA
1.5V      0A         0A         0A
[POWER_clamp]
|Voltage   I(typ)   I(min)   I(max)
-1.5V     267.6mA    236.4mA    479.7mA
-1.1V     90.92mA    95.54mA    105.5mA
-1.06V    76.14mA    83.93mA    81.29mA
-1.02V    62.03mA    72.49mA    60.96mA
-980mV    49.07mA    61.38mA    45.36mA
-940mV    37.73mA    50.83mA    34.98mA
-900mV    28.44mA    41.02mA    28.75mA
-820mV    16.72mA    24.41mA    20.46mA
-740mV    10.6mA     12.83mA    13.51mA
-660mV    6.131mA    6.445mA    7.75mA
-540mV    1.697mA    1.964mA    1.966mA
1.5V      0A         0A         0A
[Ramp]
| variable   typ   min   max
dV/dt_r 0.586/0.257n   0.545/0.300n   0.630/0.230n
dV/dt_f 0.560/0.174n   0.534/0.184n   0.600/0.165n
R_load = 50.000
[Rising Waveform]
R_fixture= 50.000
V_fixture= 0.0
V_fixture_min= 0.0
V_fixture_max= 0.0
|time   V(typ)   V(min)   V(max)
0s        0V         0V         0V
286ps     -3.639mV   -359uV     -2.987mV
392ps     980.5uV    -2.068mV   314.5mV
536ps     373.5mV    -21.53mV   739.9mV
622ps     592.2mV    117.7mV    886.2mV
722ps     773mV      338.8mV    977.4mV
933ps     934.9mV    707.5mV    1.037V
1.152ns   968.9mV    861.9mV    1.047V
1.554ns   976.2mV    905.7mV    1.049V
10ns      976.6mV    909mV      1.049V
[Rising Waveform]
R_fixture= 50.000
V_fixture= 0.750
V_fixture_min= 0.713
V_fixture_max= 0.789
|time   V(typ)   V(min)   V(max)
0s        255mV      243mV      260.7mV
259ps     253.5mV    242.9mV    253.4mV
348ps     258.9mV    242mV      592.8mV
438ps     536.1mV    232.6mV    992.8mV
508ps     799.1mV    267.6mV    1.191V
619ps     1.109V     567.2mV    1.313V
748ps     1.236V     925mV      1.347V
922ps     1.272V     1.143V     1.355V
1.272ns   1.279V     1.203V     1.357V
10ns      1.279V     1.206V     1.357V
[Falling Waveform]
R_fixture= 50.000
V_fixture= 0.750
V_fixture_min= 0.713
V_fixture_max= 0.789
|time   V(typ)   V(min)   V(max)
0s        1.279V     1.206V     1.357V
279ps     1.282V     1.207V     1.323V
383ps     1.215V     1.209V     759.9mV
446ps     910.9mV    1.214V     501.4mV
512ps     595.6mV    1.185V     366.4mV
596ps     384.9mV    927.4mV    297.1mV
707ps     289.7mV    491.7mV    269.7mV
846ps     262mV      296.4mV    262.3mV
1.124ns   255.5mV    246.2mV    260.7mV
10ns      255mV      243mV      260.7mV
[Falling Waveform]
R_fixture= 50.000
V_fixture= 0.0
V_fixture_min= 0.0
V_fixture_max= 0.0
|time   V(typ)   V(min)   V(max)
0s        976.6mV    909mV      1.049V
228ps     975.6mV    909mV      1.042V
320ps     955.4mV    907.9mV    681.6mV
377ps     807.5mV    914.6mV    336.5mV
436ps     494.2mV    902.9mV    143.4mV
526ps     153.3mV    741.4mV    36.7mV
637ps     31.78mV    287.8mV    6.994mV
765ps     5.562mV    54.9mV     1.132mV
1.005ns   404uV      3.098mV    56.64uV
10ns      0V         0V         0V
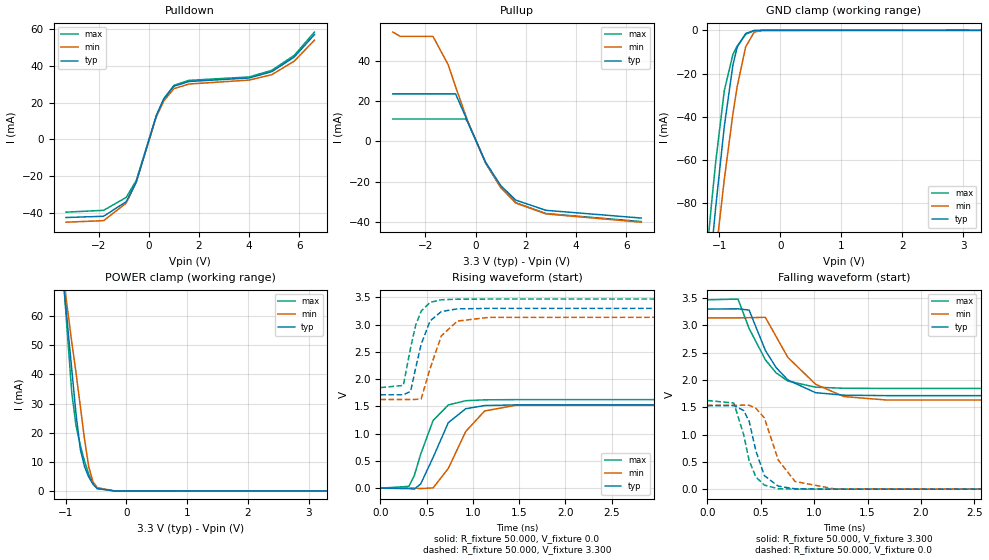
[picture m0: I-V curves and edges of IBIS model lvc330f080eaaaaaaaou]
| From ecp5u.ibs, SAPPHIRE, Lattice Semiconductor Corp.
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|   Model lvc330f080eaaaaaaaou
[Model] lvc330f080eaaaaaaaou
Model_type  Output
Polarity   Non-Inverting
Enable   Active-Low
Vmeas =  1.650V
Cref =  0.0F
Rref =  1.000M
Vref =  0.0V
C_comp   5.000pF   4.000pF   5.500pF
[Temperature Range]   25.000   0.125k   -40.000
[Voltage Range]   3.300V   3.140V   3.470V
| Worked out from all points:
|   slope of the pulldown table from 0 to 0.495 V, typ, clamps not added: 25.7 ohm
|   slope of the pullup table from 0 to 0.495 V, typ, clamps not added: 39.4 ohm
|   GND clamp passes 1 mA (typ) near -0.54 V on its own axis
|   POWER clamp passes 1 mA (typ) near -0.49 V on its own axis
|   rising waveform, R_fixture 50.000, V_fixture 0.0: 20-80 % time 232ps typ, 279ps min, 205ps max; typ from 0 V to 1.53 V
|   rising waveform, R_fixture 50.000, V_fixture 3.300: 20-80 % time 148ps typ, 171ps min, 128ps max; typ from 1.71 V to 3.3 V
|   falling waveform, R_fixture 50.000, V_fixture 3.300: 20-80 % time 284ps typ, 373ps min, 269ps max; typ from 3.3 V to 1.71 V
|   falling waveform, R_fixture 50.000, V_fixture 0.0: 20-80 % time 124ps typ, 168ps min, 116ps max; typ from 1.53 V to 0 V
[Pulldown]
|Voltage   I(typ)   I(min)   I(max)
-3.3V     -42.56mA   -45.11mA   -39.64mA
-1.8V     -41.88mA   -44.27mA   -38.64mA
-900mV    -33.92mA   -34.73mA   -31.6mA
-500mV    -23.27mA   -23.29mA   -22.42mA
300mV     12.95mA    12.36mA    12.96mA
600mV     22.06mA    21.03mA    22.23mA
1V        28.99mA    27.65mA    29.45mA
1.6V      31.58mA    30.21mA    32.2mA
4V        33.5mA     32.36mA    34.07mA
4.9V      36.93mA    35.29mA    37.66mA
5.8V      44.95mA    42.72mA    45.88mA
6.6V      57.17mA    54.1mA     58.52mA
[Pullup]
|Voltage   I(typ)   I(min)   I(max)
-3.3V     23.51mA    54.2mA     11.05mA
-3V       23.51mA    52.06mA    11.05mA
-1.7V     23.51mA    52.06mA    11.05mA
-1.1V     23.51mA    38.15mA    11.05mA
-800mV    23.51mA    27.14mA    11.05mA
-400mV    12.23mA    13.01mA    11.05mA
-300mV    9.026mA    9.528mA    9.252mA
400mV     -10.43mA   -10.76mA   -10.92mA
1V        -21.99mA   -22.91mA   -22.96mA
1.6V      -29.24mA   -30.68mA   -30.52mA
2.8V      -34.29mA   -36.08mA   -35.89mA
6.6V      -38.14mA   -40.19mA   -39.87mA
[GND_clamp]
|Voltage   I(typ)   I(min)   I(max)
-3.3V     -912.7mA   -861.5mA   -922.5mA
-1.27V    -145.6mA   -163.6mA   -123.5mA
-1.2V     -123.4mA   -142.6mA   -101.4mA
-1.13V    -102mA     -122.4mA   -80.37mA
-1.06V    -81.56mA   -103.5mA   -60.64mA
-920mV    -44.4mA    -68.93mA   -27.87mA
-780mV    -16.18mA   -38.86mA   -11.24mA
-710mV    -7.839mA   -26.12mA   -7.318mA
-570mV    -1.464mA   -7.654mA   -1.852mA
-430mV    -105.8uA   -801.1uA   -99.73uA
-290mV    -1.56uA    -33.42uA   -868.4nA
3.28V     0A         0A         0A
[POWER_clamp]
|Voltage   I(typ)   I(min)   I(max)
-3.28V    889.6mA    708.9mA    1.058A
-1.11V    88.63mA    85.92mA    94.1mA
-1.04V    72.5mA     73.68mA    73.39mA
-900mV    41.77mA    51.14mA    33.83mA
-830mV    26.51mA    40.62mA    22.43mA
-760mV    14.38mA    29.24mA    15.78mA
-690mV    8.342mA    17.8mA     10.23mA
-620mV    4.786mA    8.257mA    5.778mA
-550mV    2.295mA    3.118mA    2.584mA
-480mV    835uA      1.137mA    782uA
-200mV    3.621uA    22.63uA    424nA
3.3V      0A         0A         0A
[Ramp]
| variable   typ   min   max
dV/dt_r 0.918/0.232n   0.922/0.282n   0.975/0.208n
dV/dt_f 0.952/0.284n   0.908/0.371n   0.975/0.271n
R_load = 50.000
[Rising Waveform]
R_fixture= 50.000
V_fixture= 0.0
V_fixture_min= 0.0
V_fixture_max= 0.0
|time   V(typ)   V(min)   V(max)
0s        0V         0V         0V
308ps     -8.276mV   -79.32uV   33.03mV
367ps     -18.26mV   -270uV     232.1mV
436ps     77.28mV    -7.047mV   624.6mV
570ps     563.7mV    4.525mV    1.241V
735ps     1.203V     363.3mV    1.527V
923ps     1.458V     1.041V     1.605V
1.128ns   1.516V     1.417V     1.621V
1.478ns   1.529V     1.525V     1.625V
10ns      1.53V      1.536V     1.625V
[Rising Waveform]
R_fixture= 50.000
V_fixture= 3.300
V_fixture_min= 3.140
V_fixture_max= 3.470
|time   V(typ)   V(min)   V(max)
0s        1.713V     1.627V     1.845V
248ps     1.713V     1.627V     1.885V
327ps     1.776V     1.627V     2.577V
383ps     2.215V     1.628V     2.998V
441ps     2.641V     1.637V     3.248V
538ps     3.069V     2.197V     3.41V
659ps     3.241V     2.795V     3.457V
833ps     3.29V      3.066V     3.468V
1.172ns   3.299V     3.134V     3.47V
10ns      3.3V       3.14V      3.47V
[Falling Waveform]
R_fixture= 50.000
V_fixture= 3.300
V_fixture_min= 3.140
V_fixture_max= 3.470
|time   V(typ)   V(min)   V(max)
0s        3.3V       3.14V      3.47V
288ps     3.305V     3.14V      3.484V
392ps     3.283V     3.143V     2.945V
544ps     2.544V     3.149V     2.371V
644ps     2.23V      2.8V       2.133V
754ps     2.002V     2.416V     1.982V
1.014ns   1.768V     1.923V     1.869V
1.279ns   1.723V     1.697V     1.849V
1.678ns   1.714V     1.634V     1.846V
10ns      1.713V     1.627V     1.845V
[Falling Waveform]
R_fixture= 50.000
V_fixture= 0.0
V_fixture_min= 0.0
V_fixture_max= 0.0
|time   V(typ)   V(min)   V(max)
0s        1.53V      1.536V     1.625V
249ps     1.532V     1.536V     1.579V
341ps     1.441V     1.54V      998.3mV
392ps     1.247V     1.538V     528.1mV
455ps     703.7mV    1.483V     222.6mV
535ps     247.3mV    1.306V     74.53mV
664ps     55.25mV    536.3mV    8.166mV
822ps     6.38mV     140.8mV    1.034mV
1.193ns   226.2uV    4.428mV    39.01uV
10ns      0V         0V         0V
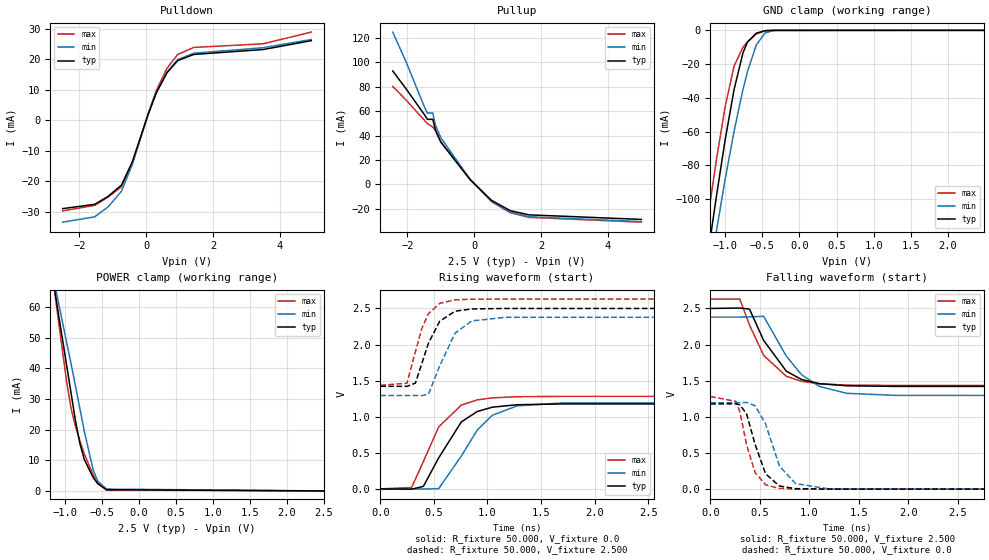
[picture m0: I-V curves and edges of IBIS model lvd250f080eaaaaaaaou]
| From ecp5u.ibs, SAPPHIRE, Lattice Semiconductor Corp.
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|   Model lvd250f080eaaaaaaaou
[Model] lvd250f080eaaaaaaaou
Model_type  Output
Polarity   Non-Inverting
Enable   Active-Low
Vmeas =  1.250V
Cref =  0.0F
Rref =  1.000M
Vref =  0.0V
C_comp   5.000pF   4.000pF   5.500pF
[Temperature Range]   25.000   0.125k   -40.000
[Voltage Range]   2.500V   2.380V   2.630V
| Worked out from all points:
|   slope of the pulldown table from 0 to 0.375 V, typ, clamps not added: 34.9 ohm
|   slope of the pullup table from 0 to 0.375 V, typ, clamps not added: 37.3 ohm
|   GND clamp passes 1 mA (typ) near -0.54 V on its own axis
|   POWER clamp passes 1 mA (typ) near -0.49 V on its own axis
|   rising waveform, R_fixture 50.000, V_fixture 0.0: 20-80 % time 282ps typ, 315ps min, 259ps max; typ from 0 V to 1.18 V
|   rising waveform, R_fixture 50.000, V_fixture 2.500: 20-80 % time 167ps typ, 191ps min, 145ps max; typ from 1.42 V to 2.5 V
|   falling waveform, R_fixture 50.000, V_fixture 2.500: 20-80 % time 297ps typ, 347ps min, 281ps max; typ from 2.5 V to 1.42 V
|   falling waveform, R_fixture 50.000, V_fixture 0.0: 20-80 % time 155ps typ, 186ps min, 137ps max; typ from 1.18 V to 0 V
[Pulldown]
|Voltage   I(typ)   I(min)   I(max)
-2.5V     -29mA      -33.45mA   -29.74mA
-1.54V    -27.59mA   -31.68mA   -27.93mA
-1.14V    -24.97mA   -28.41mA   -25.2mA
-740mV    -21.24mA   -23.27mA   -21.81mA
-420mV    -13.7mA    -14.59mA   -14.42mA
60mV      2.026mA    2.064mA    2.192mA
300mV     8.946mA    9.108mA    9.732mA
620mV     15.57mA    15.83mA    17.06mA
940mV     19.56mA    19.88mA    21.55mA
1.42V     21.58mA    21.99mA    23.88mA
3.5V      23.2mA     23.8mA     25.08mA
4.94V     26.12mA    26.49mA    28.92mA
[Pullup]
|Voltage   I(typ)   I(min)   I(max)
-2.44V    93.04mA    124.9mA    80.33mA
-2.04V    78.37mA    100.5mA    69.18mA
-1.48V    56.75mA    62.82mA    52.24mA
-1.4V     53.32mA    58.5mA     49.81mA
-1.24V    53.32mA    58.5mA     47.1mA
-1.16V    44.56mA    48.35mA    43.82mA
-1V       34.69mA    38.28mA    34.86mA
-120mV    3.778mA    3.962mA    4.059mA
520mV     -13.17mA   -13.8mA    -14.24mA
1.08V     -21.58mA   -22.85mA   -23.28mA
1.64V     -24.99mA   -26.54mA   -27.06mA
5V        -28.73mA   -30.54mA   -31.01mA
[GND_clamp]
|Voltage   I(typ)   I(min)   I(max)
-2.5V     -600.3mA   -576.2mA   -594.4mA
-1.24V    -136mA     -154.5mA   -113.9mA
-1.18V    -117.2mA   -136.7mA   -95.27mA
-1.12V    -99.04mA   -119.7mA   -77.45mA
-1V       -64.9mA    -88.21mA   -45.19mA
-880mV    -35.12mA   -59.82mA   -21.21mA
-760mV    -13.33mA   -35.03mA   -10mA
-700mV    -7.01mA    -24.46mA   -6.829mA
-580mV    -1.679mA   -8.593mA   -2.127mA
-460mV    -210.1uA   -1.441mA   -213.7uA
-340mV    -8.598uA   -109.2uA   -6.553uA
2.48V     0A         0A         0A
[POWER_clamp]
|Voltage   I(typ)   I(min)   I(max)
-2.48V    301.8mA    269mA      334.4mA
-1.16V    68.59mA    70.21mA    68.47mA
-1.1V     59.33mA    62.74mA    57.51mA
-980mV    41.18mA    48.59mA    35.82mA
-920mV    32.13mA    41.65mA    27.11mA
-860mV    23.04mA    34.34mA    21.08mA
-800mV    15.49mA    26.9mA     16.35mA
-740mV    10.29mA    19.52mA    12.1mA
-620mV    4.381mA    6.888mA    5.184mA
-560mV    2.412mA    3.25mA     2.719mA
-440mV    397.7uA    604uA      311uA
2.5V      0A         0A         0A
[Ramp]
| variable   typ   min   max
dV/dt_r 0.707/0.284n   0.717/0.318n   0.769/0.261n
dV/dt_f 0.647/0.298n   0.652/0.348n   0.717/0.279n
R_load = 50.000
[Rising Waveform]
R_fixture= 50.000
V_fixture= 0.0
V_fixture_min= 0.0
V_fixture_max= 0.0
|time   V(typ)   V(min)   V(max)
0s        0V         0V         0V
292ps     -3.832mV   -119.6uV   18.83mV
402ps     34.54mV    -1.774mV   378.3mV
545ps     429.9mV    3.273mV    859mV
757ps     929.2mV    456.7mV    1.162V
906ps     1.073V     817.8mV    1.234V
1.046ns   1.132V     1.02V      1.261V
1.276ns   1.166V     1.15V      1.277V
1.701ns   1.177V     1.191V     1.282V
10ns      1.179V     1.196V     1.282V
[Rising Waveform]
R_fixture= 50.000
V_fixture= 2.500
V_fixture_min= 2.380
V_fixture_max= 2.630
|time   V(typ)   V(min)   V(max)
0s        1.421V     1.294V     1.435V
249ps     1.421V     1.294V     1.464V
328ps     1.466V     1.294V     1.904V
389ps     1.742V     1.293V     2.228V
449ps     2.017V     1.311V     2.425V
554ps     2.322V     1.703V     2.571V
697ps     2.462V     2.156V     2.619V
853ps     2.493V     2.327V     2.628V
1.169ns   2.5V       2.377V     2.63V
10ns      2.5V       2.38V      2.63V
[Falling Waveform]
R_fixture= 50.000
V_fixture= 2.500
V_fixture_min= 2.380
V_fixture_max= 2.630
|time   V(typ)   V(min)   V(max)
0s        2.5V       2.38V      2.63V
298ps     2.506V     2.38V      2.63V
396ps     2.491V     2.384V     2.27V
539ps     2.057V     2.391V     1.85V
767ps     1.633V     1.841V     1.562V
920ps     1.518V     1.585V     1.492V
1.1ns     1.46V      1.422V     1.457V
1.38ns    1.43V      1.326V     1.44V
1.88ns    1.422V     1.297V     1.435V
10ns      1.421V     1.294V     1.435V
[Falling Waveform]
R_fixture= 50.000
V_fixture= 0.0
V_fixture_min= 0.0
V_fixture_max= 0.0
|time   V(typ)   V(min)   V(max)
0s        1.179V     1.196V     1.282V
260ps     1.181V     1.196V     1.214V
299ps     1.165V     1.195V     1.07V
366ps     1.044V     1.2V       614.7mV
452ps     620.9mV    1.154V     231.5mV
558ps     212.8mV    905mV      60.11mV
697ps     44.2mV     322.2mV    10.3mV
860ps     7.049mV    77.06mV    1.75mV
1.191ns   544.5uV    4.406mV    115.8uV
10ns      0V         0V         0V
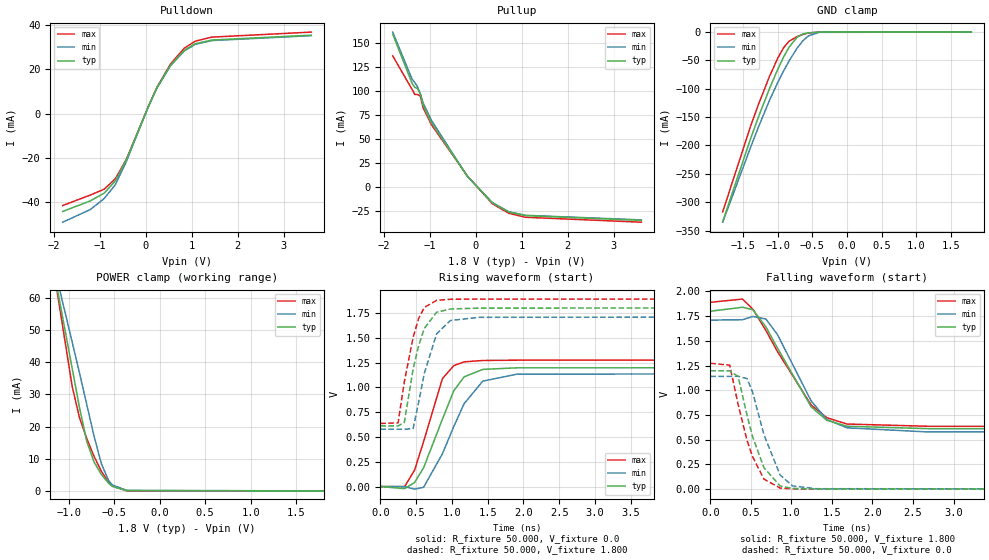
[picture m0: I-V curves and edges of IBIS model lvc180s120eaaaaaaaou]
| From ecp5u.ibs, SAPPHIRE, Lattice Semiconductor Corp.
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|   Model lvc180s120eaaaaaaaou
[Model] lvc180s120eaaaaaaaou
Model_type  Output
Polarity   Non-Inverting
Enable   Active-Low
Vmeas =  0.900V
Cref =  0.0F
Rref =  1.000M
Vref =  0.0V
C_comp   5.000pF   4.000pF   5.500pF
[Temperature Range]   25.000   0.125k   -40.000
[Voltage Range]   1.800V   1.710V   1.890V
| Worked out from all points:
|   slope of the pulldown table from 0 to 0.27 V, typ, clamps not added: 21.5 ohm
|   slope of the pullup table from 0 to 0.27 V, typ, clamps not added: 20.5 ohm
|   GND clamp passes 1 mA (typ) near -0.54 V on its own axis
|   POWER clamp passes 1 mA (typ) near -0.49 V on its own axis
|   rising waveform, R_fixture 50.000, V_fixture 0.0: 20-80 % time 382ps typ, 428ps min, 300ps max; typ from 0 V to 1.2 V
|   rising waveform, R_fixture 50.000, V_fixture 1.800: 20-80 % time 218ps typ, 226ps min, 208ps max; typ from 0.612 V to 1.8 V
|   falling waveform, R_fixture 50.000, V_fixture 1.800: 20-80 % time 488ps typ, 436ps min, 544ps max; typ from 1.8 V to 0.612 V
|   falling waveform, R_fixture 50.000, V_fixture 0.0: 20-80 % time 251ps typ, 259ps min, 251ps max; typ from 1.2 V to 0 V
[Pulldown]
|Voltage   I(typ)   I(min)   I(max)
-1.8V     -44.35mA   -49.21mA   -41.67mA
-1.2V     -39.57mA   -43.49mA   -36.91mA
-900mV    -36.06mA   -38.52mA   -34.28mA
-660mV    -30.62mA   -32.33mA   -29.62mA
-420mV    -21.11mA   -21.89mA   -20.84mA
60mV      3.118mA    3.096mA    3.169mA
240mV     11.37mA    11.28mA    11.6mA
540mV     21.82mA    21.62mA    22.4mA
840mV     28.62mA    28.33mA    29.57mA
1.08V     31.6mA     31.31mA    32.77mA
1.44V     33.27mA    33.03mA    34.59mA
3.6V      35.47mA    35.25mA    36.87mA
[Pullup]
|Voltage   I(typ)   I(min)   I(max)
-1.8V     158.8mA    160.9mA    136.2mA
-1.38V    107.7mA    112mA      101.3mA
-1.32V    103.4mA    108.4mA    95.98mA
-1.26V    102.1mA    103.9mA    95.98mA
-1.2V     96.41mA    96.5mA     94.37mA
-1.14V    84.99mA    87.29mA    82.11mA
-960mV    66.58mA    69.12mA    64.56mA
-180mV    10.92mA    10.85mA    11.24mA
360mV     -16.7mA    -16.38mA   -17.56mA
720mV     -26.4mA    -26.09mA   -27.73mA
1.08V     -30.14mA   -29.82mA   -31.87mA
3.6V      -35.05mA   -34.61mA   -36.99mA
[GND_clamp]
|Voltage   I(typ)   I(min)   I(max)
-1.8V     -334.4mA   -335.3mA   -317.1mA
-1.4V     -189.3mA   -204.4mA   -167.3mA
-1.28V    -148.9mA   -166.7mA   -126.7mA
-1.12V    -99.04mA   -119.7mA   -77.45mA
-1V       -64.9mA    -88.2mA    -45.18mA
-920mV    -44.4mA    -68.92mA   -27.88mA
-840mV    -26.71mA   -51.09mA   -16.18mA
-720mV    -8.754mA   -27.82mA   -7.821mA
-640mV    -3.53mA    -15.52mA   -4.188mA
-560mV    -1.27mA    -6.791mA   -1.597mA
-400mV    -49.63uA   -425.4uA   -44.12uA
1.8V      0A         0A         0A
[POWER_clamp]
|Voltage   I(typ)   I(min)   I(max)
-1.8V     174.6mA    158.5mA    191.6mA
-1.36V    100.3mA    96.28mA    105.7mA
-1.12V    62.39mA    65.2mA     61.09mA
-960mV    38.11mA    46.28mA    32.52mA
-880mV    25.96mA    36.75mA    22.79mA
-800mV    15.45mA    26.86mA    16.3mA
-720mV    9.004mA    17.05mA    10.75mA
-640mV    5.132mA    8.487mA    6.134mA
-560mV    2.382mA    3.217mA    2.693mA
-520mV    1.425mA    1.849mA    1.506mA
-360mV    88.16uA    177.6uA    42.1uA
1.8V      0A         0A         0A
[Ramp]
| variable   typ   min   max
dV/dt_r 0.719/0.388n   0.684/0.438n   0.764/0.304n
dV/dt_f 0.713/0.499n   0.679/0.440n   0.752/0.551n
R_load = 50.000
[Rising Waveform]
R_fixture= 50.000
V_fixture= 0.0
V_fixture_min= 0.0
V_fixture_max= 0.0
|time   V(typ)   V(min)   V(max)
0s        0V         0V         0V
341ps     -20.49mV   -580.5uV   530.5uV
479ps     40.77mV    -26.23mV   165.6mV
605ps     189.2mV    -7.443mV   453.2mV
868ps     679.1mV    330.5mV    1.088V
1.027ns   965.7mV    605.3mV    1.219V
1.171ns   1.106V     835.6mV    1.257V
1.432ns   1.181V     1.063V     1.271V
1.91ns    1.197V     1.133V     1.274V
10ns      1.198V     1.141V     1.274V
[Rising Waveform]
R_fixture= 50.000
V_fixture= 1.800
V_fixture_min= 1.710
V_fixture_max= 1.890
|time   V(typ)   V(min)   V(max)
0s        611.8mV    577.6mV    636mV
249ps     611.1mV    577.6mV    642.4mV
336ps     646.6mV    576.9mV    1.057V
459ps     1.185V     584.9mV    1.504V
535ps     1.418V     847.1mV    1.693V
615ps     1.594V     1.141V     1.806V
787ps     1.757V     1.54V      1.877V
980ps     1.79V      1.674V     1.888V
1.384ns   1.799V     1.706V     1.89V
10ns      1.8V       1.71V      1.89V
[Falling Waveform]
R_fixture= 50.000
V_fixture= 1.800
V_fixture_min= 1.710
V_fixture_max= 1.890
|time   V(typ)   V(min)   V(max)
0s        1.8V       1.71V      1.89V
397ps     1.84V      1.714V     1.923V
525ps     1.816V     1.747V     1.821V
686ps     1.642V     1.721V     1.605V
827ps     1.429V     1.566V     1.394V
1.245ns   831.8mV    891mV      850.5mV
1.437ns   696.9mV    704.8mV    723.1mV
1.686ns   636.3mV    620.6mV    658.8mV
2.685ns   612.1mV    578.8mV    636.1mV
10ns      611.8mV    577.6mV    636mV
[Falling Waveform]
R_fixture= 50.000
V_fixture= 0.0
V_fixture_min= 0.0
V_fixture_max= 0.0
|time   V(typ)   V(min)   V(max)
0s        1.198V     1.141V     1.274V
240ps     1.197V     1.141V     1.254V
343ps     1.14V      1.142V     858.5mV
454ps     745.2mV    1.118V     490mV
521ps     532mV      983.9mV    330.3mV
662ps     217.6mV    550.9mV    101.3mV
861ps     32.3mV     143.3mV    11.73mV
1.015ns   7.591mV    33.17mV    3.326mV
1.296ns   2.293mV    4.812mV    1.483mV
10ns      0V         0V         0V
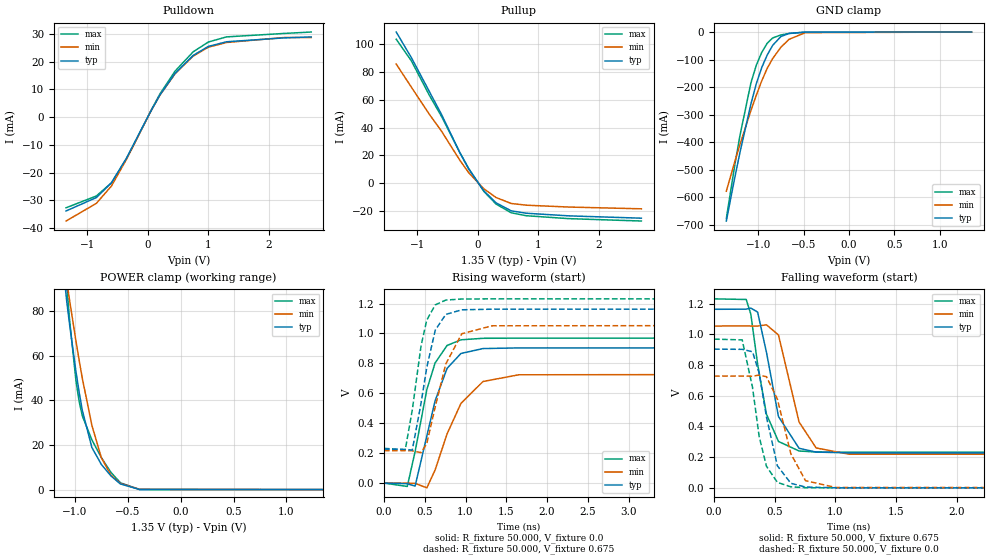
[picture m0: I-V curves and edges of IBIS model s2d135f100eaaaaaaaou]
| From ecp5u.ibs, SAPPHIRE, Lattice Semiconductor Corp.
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|   Model s2d135f100eaaaaaaaou
[Model] s2d135f100eaaaaaaaou
Model_type  Output
Polarity   Non-Inverting
Enable   Active-Low
Vmeas =  0.675V
Cref =  30.000pF
Rref =  50.000
Vref =  0.675V
C_comp   5.000pF   4.000pF   5.500pF
[Temperature Range]   25.000   0.125k   -40.000
[Voltage Range]   1.350V   1.280V   1.420V
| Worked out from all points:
|   slope of the pulldown table from 0 to 0.203 V, typ, clamps not added: 25.1 ohm
|   slope of the pullup table from 0 to 0.203 V, typ, clamps not added: 19.5 ohm
|   GND clamp passes 1 mA (typ) near -0.54 V on its own axis
|   POWER clamp passes 1 mA (typ) near -0.51 V on its own axis
|   rising waveform, R_fixture 50.000, V_fixture 0.0: 20-80 % time 259ps typ, 345ps min, 230ps max; typ from 0 V to 0.904 V
|   rising waveform, R_fixture 50.000, V_fixture 0.675: 20-80 % time 182ps typ, 238ps min, 161ps max; typ from 0.227 V to 1.16 V
|   falling waveform, R_fixture 50.000, V_fixture 0.675: 20-80 % time 137ps typ, 152ps min, 127ps max; typ from 1.16 V to 0.227 V
|   falling waveform, R_fixture 50.000, V_fixture 0.0: 20-80 % time 127ps typ, 148ps min, 113ps max; typ from 0.904 V to 0 V
[Pulldown]
|Voltage   I(typ)   I(min)   I(max)
-1.35V    -33.78mA   -37.41mA   -32.64mA
-850mV    -28.97mA   -31.05mA   -28.4mA
-600mV    -23.63mA   -24.79mA   -23.65mA
-350mV    -14.66mA   -15.1mA    -14.92mA
50mV      2.157mA    2.138mA    2.25mA
200mV     7.987mA    7.913mA    8.357mA
450mV     15.76mA    15.6mA     16.57mA
750mV     22.25mA    22mA       23.54mA
1V        25.47mA    25.19mA    27.06mA
1.3V      27.15mA    26.89mA    28.91mA
2.25V     28.55mA    28.68mA    30.15mA
2.7V      28.9mA     28.68mA    30.66mA
[Pullup]
|Voltage   I(typ)   I(min)   I(max)
-1.35V    108.6mA    85.6mA     103.4mA
-1.1V     90.26mA    69.04mA    87.95mA
-800mV    65.64mA    49.36mA    62.97mA
-600mV    49.28mA    37.29mA    47.89mA
-300mV    22.03mA    16.59mA    22.16mA
-150mV    10.08mA    7.445mA    10.4mA
100mV     -5.613mA   -4.06mA    -5.96mA
300mV     -14.08mA   -10.26mA   -14.96mA
550mV     -19.83mA   -14.55mA   -21.23mA
800mV     -21.55mA   -15.77mA   -23.33mA
1.5V      -23.43mA   -17.1mA    -25.43mA
2.7V      -25.1mA    -18.37mA   -27.13mA
[GND_clamp]
|Voltage   I(typ)   I(min)   I(max)
-1.35V    -687.3mA   -578.9mA   -678.1mA
-1.26V    -534.3mA   -475.1mA   -489.7mA
-1.2V     -438.1mA   -409.1mA   -376.7mA
-1.08V    -262.9mA   -286.2mA   -185.9mA
-1.02V    -187.7mA   -229.9mA   -120.7mA
-960mV    -129.1mA   -177.6mA   -73.95mA
-900mV    -83.6mA    -132.1mA   -40.76mA
-840mV    -48.57mA   -96.56mA   -21.66mA
-750mV    -16.65mA   -55.68mA   -10.64mA
-660mV    -4.958mA   -26.68mA   -5.448mA
-480mV    -317.7uA   -2.229mA   -341.9uA
1.35V     0A         0A         0A
[POWER_clamp]
|Voltage   I(typ)   I(min)   I(max)
-1.35V    211.5mA    193mA      324.9mA
-1.08V    85.33mA    94.25mA    92.93mA
-1.05V    73.76mA    84.65mA    75.65mA
-990mV    52.73mA    66.45mA    48.6mA
-960mV    43.53mA    57.9mA     39.38mA
-930mV    35.42mA    49.79mA    33mA
-840mV    18.88mA    28.82mA    22.31mA
-750mV    11.24mA    14.22mA    14.3mA
-660mV    6.13mA     6.499mA    7.742mA
-570mV    2.538mA    2.795mA    3.049mA
-390mV    57.41uA    134.8uA    35.81uA
1.35V     0A         0A         0A
[Ramp]
| variable   typ   min   max
dV/dt_r 0.542/0.260n   0.437/0.346n   0.581/0.233n
dV/dt_f 0.511/0.163n   0.485/0.173n   0.546/0.153n
R_load = 50.000
[Rising Waveform]
R_fixture= 50.000
V_fixture= 0.0
V_fixture_min= 0.0
V_fixture_max= 0.0
|time   V(typ)   V(min)   V(max)
0s        0V         0V         0V
286ps     -4.285mV   -438.7uV   -22.54mV
382ps     -20.1mV    -1.727mV   210.6mV
526ps     315.1mV    -31.84mV   625.3mV
627ps     549.6mV    87.38mV    802.5mV
774ps     766.8mV    328.9mV    919.7mV
944ps     866.2mV    532.4mV    957.4mV
1.214ns   898.9mV    678.7mV    967.5mV
1.653ns   903.3mV    723.7mV    968.6mV
10ns      903.5mV    728.2mV    968.6mV
[Rising Waveform]
R_fixture= 50.000
V_fixture= 0.675
V_fixture_min= 0.642
V_fixture_max= 0.710
|time   V(typ)   V(min)   V(max)
0s        227.4mV    216.8mV    232.4mV
261ps     225.4mV    216.7mV    221.5mV
347ps     219.8mV    215.7mV    486.9mV
454ps     531.1mV    203.3mV    914mV
524ps     770.2mV    261.8mV    1.088V
629ps     1.022V     510.2mV    1.191V
758ps     1.127V     795.7mV    1.223V
954ps     1.158V     997.7mV    1.23V
1.324ns   1.162V     1.051V     1.231V
10ns      1.163V     1.054V     1.231V
[Falling Waveform]
R_fixture= 50.000
V_fixture= 0.675
V_fixture_min= 0.642
V_fixture_max= 0.710
|time   V(typ)   V(min)   V(max)
0s        1.163V     1.054V     1.231V
265ps     1.164V     1.055V     1.227V
303ps     1.171V     1.054V     1.132V
359ps     1.145V     1.054V     806.1mV
432ps     883.1mV    1.062V     479.9mV
531ps     464.7mV    996mV      302.3mV
701ps     257.5mV    428.7mV    240mV
842ps     232.9mV    259.8mV    233.6mV
1.112ns   227.7mV    219.2mV    232.4mV
10ns      227.4mV    216.8mV    232.4mV
[Falling Waveform]
R_fixture= 50.000
V_fixture= 0.0
V_fixture_min= 0.0
V_fixture_max= 0.0
|time   V(typ)   V(min)   V(max)
0s        903.5mV    728.2mV    968.6mV
232ps     902.3mV    728.2mV    963.7mV
317ps     886.6mV    727.1mV    654.5mV
372ps     747.3mV    734.3mV    334mV
432ps     461.7mV    724mV      140.6mV
522ps     143.7mV    578.2mV    35.77mV
633ps     29.57mV    222.5mV    6.677mV
754ps     5.437mV    46.81mV    1.146mV
1.003ns   267.6uV    2.198mV    49.35uV
10ns      0V         0V         0V
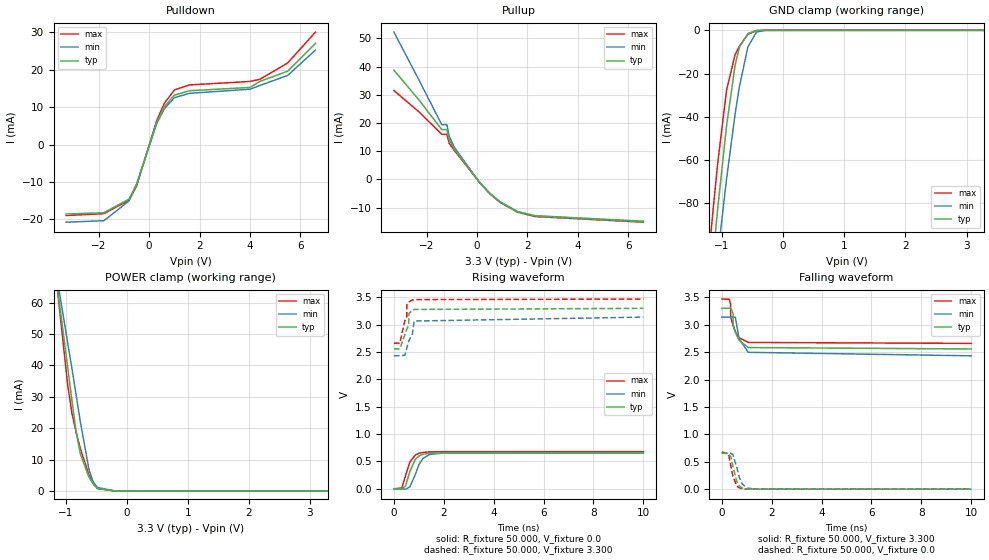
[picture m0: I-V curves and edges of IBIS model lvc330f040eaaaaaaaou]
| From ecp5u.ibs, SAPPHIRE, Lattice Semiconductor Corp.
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|   Model lvc330f040eaaaaaaaou
[Model] lvc330f040eaaaaaaaou
Model_type  Output
Polarity   Non-Inverting
Enable   Active-Low
Vmeas =  1.650V
Cref =  0.0F
Rref =  1.000M
Vref =  0.0V
C_comp   5.000pF   4.000pF   5.500pF
[Temperature Range]   25.000   0.125k   -40.000
[Voltage Range]   3.300V   3.140V   3.470V
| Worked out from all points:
|   slope of the pulldown table from 0 to 0.495 V, typ, clamps not added: 56.3 ohm
|   slope of the pullup table from 0 to 0.495 V, typ, clamps not added: 101 ohm
|   GND clamp passes 1 mA (typ) near -0.54 V on its own axis
|   POWER clamp passes 1 mA (typ) near -0.49 V on its own axis
|   rising waveform, R_fixture 50.000, V_fixture 0.0: 20-80 % time 307ps typ, 345ps min, 291ps max; typ from 0 V to 0.656 V
|   rising waveform, R_fixture 50.000, V_fixture 3.300: 20-80 % time 218ps typ, 233ps min, 212ps max; typ from 2.56 V to 3.3 V
|   falling waveform, R_fixture 50.000, V_fixture 3.300: 20-80 % time 250ps typ, 266ps min, 250ps max; typ from 3.3 V to 2.56 V
|   falling waveform, R_fixture 50.000, V_fixture 0.0: 20-80 % time 206ps typ, 232ps min, 187ps max; typ from 0.656 V to 0 V
[Pulldown]
|Voltage   I(typ)   I(min)   I(max)
-3.3V     -18.53mA   -20.72mA   -18.94mA
-1.8V     -18.2mA    -20.34mA   -18.44mA
-800mV    -14.54mA   -15.05mA   -14.87mA
-500mV    -10.58mA   -10.61mA   -11.11mA
300mV     5.912mA    5.618mA    6.436mA
600mV     10.07mA    9.555mA    11.03mA
1V        13.23mA    12.56mA    14.61mA
1.6V      14.42mA    13.72mA    15.97mA
4V        15.29mA    14.82mA    16.89mA
4.4V      16.91mA    15.84mA    17.49mA
5.5V      19.65mA    18.51mA    21.85mA
6.6V      27.06mA    25.28mA    30.09mA
[Pullup]
|Voltage   I(typ)   I(min)   I(max)
-3.3V     38.74mA    52.25mA    31.53mA
-2.3V     28.11mA    35.16mA    23.9mA
-1.4V     17.65mA    19.39mA    15.97mA
-1.2V     17.65mA    19.39mA    15.97mA
-1.1V     13.95mA    15.19mA    12.65mA
-900mV    10.74mA    11.38mA    10.25mA
100mV     -1.099mA   -1.081mA   -1.129mA
500mV     -4.933mA   -4.887mA   -5.051mA
900mV     -7.929mA   -7.906mA   -8.101mA
1.6V      -11.38mA   -11.44mA   -11.62mA
2.3V      -12.89mA   -13mA      -13.2mA
6.6V      -14.85mA   -15mA      -15.19mA
[GND_clamp]
|Voltage   I(typ)   I(min)   I(max)
-3.3V     -912.7mA   -861.5mA   -922.5mA
-1.27V    -145.6mA   -163.6mA   -123.5mA
-1.2V     -123.4mA   -142.6mA   -101.4mA
-1.13V    -102mA     -122.4mA   -80.37mA
-1.06V    -81.56mA   -103.5mA   -60.64mA
-920mV    -44.4mA    -68.93mA   -27.87mA
-780mV    -16.18mA   -38.86mA   -11.24mA
-710mV    -7.839mA   -26.12mA   -7.318mA
-570mV    -1.464mA   -7.654mA   -1.852mA
-430mV    -105.8uA   -801.1uA   -99.73uA
-290mV    -1.56uA    -33.42uA   -868.4nA
3.28V     0A         0A         0A
[POWER_clamp]
|Voltage   I(typ)   I(min)   I(max)
-3.28V    471.5mA    421.2mA    516.6mA
-1.18V    71.72mA    72.75mA    72.14mA
-1.11V    60.88mA    63.98mA    59.38mA
-970mV    39.73mA    47.46mA    34.21mA
-900mV    29.12mA    39.28mA    24.89mA
-830mV    19.01mA    30.67mA    18.7mA
-760mV    11.8mA     22.01mA    13.51mA
-620mV    4.416mA    6.921mA    5.219mA
-550mV    2.174mA    2.865mA    2.414mA
-480mV    813uA      1.102mA    758.3uA
-200mV    3.62uA     22.61uA    424nA
3.3V      0A         0A         0A
[Ramp]
| variable   typ   min   max
dV/dt_r   0.397/0.311n   0.396/0.346n   0.410/0.292n
dV/dt_f   0.443/0.317n   0.421/0.336n   0.491/0.301n
R_load = 50.000
[Rising Waveform]
R_fixture= 50.000
V_fixture= 0.0
V_fixture_min= 0.0
V_fixture_max= 0.0
|time   V(typ)   V(min)   V(max)
0s        0V         0V         0V
319ps     -5.428mV   -79.81uV   15.96mV
467ps     53.27mV    -6.324mV   241.4mV
637ps     312.5mV    34.31mV    488.5mV
854ps     537.5mV    256.8mV    616.7mV
1.005ns   601.5mV    444.1mV    650.4mV
1.154ns   630.9mV    551.5mV    665.6mV
1.432ns   650.3mV    628.5mV    675.6mV
1.926ns   656mV      652.2mV    678.5mV
10ns      656.5mV    654.4mV    678.7mV
[Rising Waveform]
R_fixture= 50.000
V_fixture= 3.300
V_fixture_min= 3.140
V_fixture_max= 3.470
|time   V(typ)   V(min)   V(max)
0s        2.559V     2.434V     2.661V
238ps     2.559V     2.434V     2.665V
437ps     2.815V     2.442V     3.072V
515ps     2.921V     2.57V      3.149V
520ps     2.927V     2.58V      3.372V
593ps     2.99V      2.7V       3.414V
600ps     3.202V     2.709V     3.417V
743ps     3.266V     2.838V     3.453V
810ps     3.28V      3.068V     3.46V
10ns      3.3V       3.14V      3.47V
[Falling Waveform]
R_fixture= 50.000
V_fixture= 3.300
V_fixture_min= 3.140
V_fixture_max= 3.470
|time   V(typ)   V(min)   V(max)
0s        3.3V       3.14V      3.47V
299ps     3.303V     3.14V      3.467V
350ps     3.308V     3.14V      3.376V
355ps     3.308V     3.14V      3.147V
453ps     3.201V     3.146V     2.985V
455ps     2.99V      3.146V     2.982V
543ps     2.859V     3.138V     2.877V
691ps     2.716V     2.749V     2.765V
1.061ns   2.585V     2.498V     2.678V
10ns      2.559V     2.434V     2.661V
[Falling Waveform]
R_fixture= 50.000
V_fixture= 0.0
V_fixture_min= 0.0
V_fixture_max= 0.0
|time   V(typ)   V(min)   V(max)
0s        656.5mV    654.4mV    678.7mV
269ps     656.2mV    654.2mV    642.7mV
370ps     580.9mV    656mV      404.1mV
443ps     416.2mV    628.5mV    236.1mV
600ps     136.6mV    395.2mV    57.63mV
702ps     57.13mV    209.9mV    22.12mV
821ps     19.77mV    91.82mV    7.286mV
1.011ns   3.731mV    20.28mV    1.268mV
1.361ns   209.8uV    1.238mV    68.1uV
10ns      0V         0V         0V
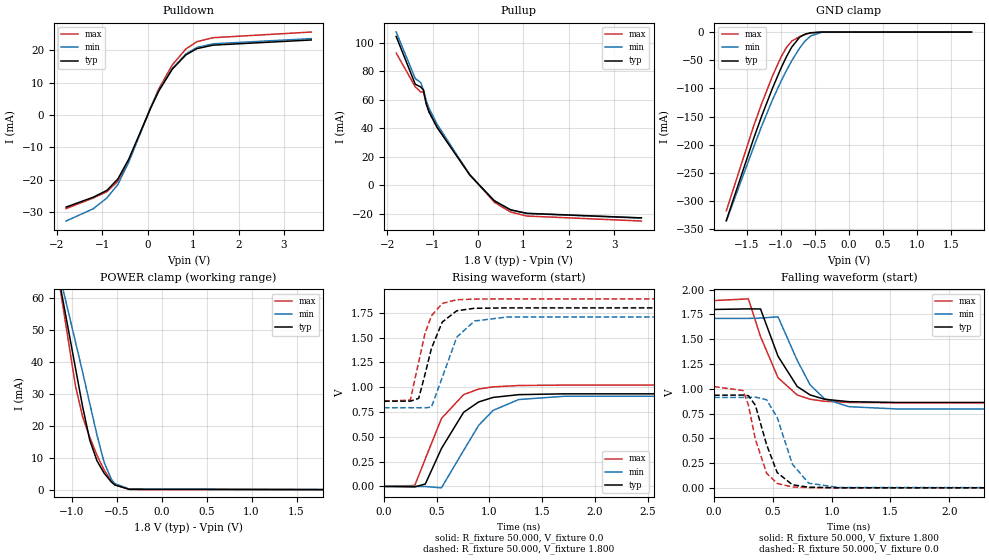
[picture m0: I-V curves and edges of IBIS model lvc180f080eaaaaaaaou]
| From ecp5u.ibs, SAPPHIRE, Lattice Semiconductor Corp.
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|   Model lvc180f080eaaaaaaaou
[Model] lvc180f080eaaaaaaaou
Model_type  Output
Polarity   Non-Inverting
Enable   Active-Low
Vmeas =  0.900V
Cref =  0.0F
Rref =  1.000M
Vref =  0.0V
C_comp   5.000pF   4.000pF   5.500pF
[Temperature Range]   25.000   0.125k   -40.000
[Voltage Range]   1.800V   1.710V   1.890V
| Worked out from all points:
|   slope of the pulldown table from 0 to 0.27 V, typ, clamps not added: 33.1 ohm
|   slope of the pullup table from 0 to 0.27 V, typ, clamps not added: 31.2 ohm
|   GND clamp passes 1 mA (typ) near -0.54 V on its own axis
|   POWER clamp passes 1 mA (typ) near -0.49 V on its own axis
|   rising waveform, R_fixture 50.000, V_fixture 0.0: 20-80 % time 287ps typ, 325ps min, 263ps max; typ from 0 V to 0.934 V
|   rising waveform, R_fixture 50.000, V_fixture 1.800: 20-80 % time 156ps typ, 184ps min, 139ps max; typ from 0.86 V to 1.8 V
|   falling waveform, R_fixture 50.000, V_fixture 1.800: 20-80 % time 226ps typ, 229ps min, 216ps max; typ from 1.8 V to 0.86 V
|   falling waveform, R_fixture 50.000, V_fixture 0.0: 20-80 % time 141ps typ, 160ps min, 126ps max; typ from 0.934 V to 0 V
[Pulldown]
|Voltage   I(typ)   I(min)   I(max)
-1.8V     -28.53mA   -32.84mA   -29.01mA
-1.2V     -25.46mA   -29.03mA   -25.7mA
-900mV    -23.35mA   -25.68mA   -23.75mA
-660mV    -19.84mA   -21.55mA   -20.51mA
-420mV    -13.7mA    -14.59mA   -14.42mA
60mV      2.026mA    2.064mA    2.192mA
240mV     7.384mA    7.52mA     8.023mA
540mV     14.17mA    14.41mA    15.5mA
840mV     18.59mA    18.89mA    20.45mA
1.08V     20.52mA    20.88mA    22.66mA
1.44V     21.61mA    22.02mA    23.91mA
3.6V      23.2mA     23.62mA    25.66mA
[Pullup]
|Voltage   I(typ)   I(min)   I(max)
-1.8V     104.5mA    107.6mA    92.84mA
-1.38V    70.9mA     74.9mA     69.09mA
-1.26V    68.99mA    72.12mA    65.48mA
-1.2V     66.93mA    66.81mA    65.48mA
-1.14V    57.38mA    59.48mA    57.36mA
-1.08V    51.83mA    54.35mA    51.48mA
-900mV    40.67mA    42.94mA    40.69mA
-180mV    7.161mA    7.234mA    7.646mA
360mV     -10.95mA   -10.92mA   -11.94mA
720mV     -17.31mA   -17.4mA    -18.86mA
1.08V     -19.76mA   -19.89mA   -21.68mA
3.6V      -22.97mA   -23.08mA   -25.16mA
[GND_clamp]
|Voltage   I(typ)   I(min)   I(max)
-1.8V     -334.4mA   -335.3mA   -317.1mA
-1.4V     -189.3mA   -204.4mA   -167.3mA
-1.28V    -148.9mA   -166.7mA   -126.7mA
-1.12V    -99.04mA   -119.7mA   -77.45mA
-1V       -64.9mA    -88.2mA    -45.18mA
-920mV    -44.4mA    -68.92mA   -27.88mA
-840mV    -26.71mA   -51.09mA   -16.18mA
-720mV    -8.754mA   -27.82mA   -7.821mA
-640mV    -3.53mA    -15.52mA   -4.188mA
-560mV    -1.27mA    -6.791mA   -1.597mA
-400mV    -49.63uA   -425.4uA   -44.12uA
1.8V      0A         0A         0A
[POWER_clamp]
|Voltage   I(typ)   I(min)   I(max)
-1.8V     174.6mA    158.5mA    191.6mA
-1.36V    100.3mA    96.28mA    105.7mA
-1.12V    62.39mA    65.2mA     61.09mA
-960mV    38.11mA    46.28mA    32.52mA
-880mV    25.96mA    36.75mA    22.79mA
-800mV    15.45mA    26.86mA    16.3mA
-720mV    9.004mA    17.05mA    10.75mA
-640mV    5.132mA    8.487mA    6.134mA
-560mV    2.382mA    3.217mA    2.693mA
-520mV    1.425mA    1.849mA    1.506mA
-360mV    88.16uA    177.6uA    42.1uA
1.8V      0A         0A         0A
[Ramp]
| variable   typ   min   max
dV/dt_r 0.561/0.291n   0.547/0.327n   0.613/0.263n
dV/dt_f 0.564/0.229n   0.550/0.235n   0.620/0.219n
R_load = 50.000
[Rising Waveform]
R_fixture= 50.000
V_fixture= 0.0
V_fixture_min= 0.0
V_fixture_max= 0.0
|time   V(typ)   V(min)   V(max)
0s        0V         0V         0V
292ps     -4.859mV   -190.7uV   9.257mV
392ps     24.05mV    -902.6uV   278.5mV
545ps     382.1mV    -14.42mV   684.5mV
755ps     747mV      362.5mV    925mV
898ps     851.4mV    615.8mV    981.2mV
1.035ns   896.9mV    766.4mV    1.003V
1.278ns   924.8mV    875.7mV    1.017V
1.714ns   933mV      908.8mV    1.021V
10ns      934.5mV    912.4mV    1.022V
[Rising Waveform]
R_fixture= 50.000
V_fixture= 1.800
V_fixture_min= 1.710
V_fixture_max= 1.890
|time   V(typ)   V(min)   V(max)
0s        860mV      793.1mV    857.1mV
250ps     859.1mV    793.1mV    870.8mV
329ps     887mV      792.7mV    1.252V
390ps     1.132V     792.2mV    1.545V
450ps     1.391V     798.8mV    1.719V
553ps     1.657V     1.099V     1.844V
690ps     1.77V      1.504V     1.881V
858ps     1.795V     1.667V     1.888V
1.167ns   1.799V     1.707V     1.89V
10ns      1.8V       1.71V      1.89V
[Falling Waveform]
R_fixture= 50.000
V_fixture= 1.800
V_fixture_min= 1.710
V_fixture_max= 1.890
|time   V(typ)   V(min)   V(max)
0s        1.8V       1.71V      1.89V
292ps     1.806V     1.71V      1.907V
395ps     1.805V     1.713V     1.527V
544ps     1.328V     1.726V     1.111V
707ps     1.023V     1.287V     937.4mV
817ps     937.5mV    1.039V     894.1mV
939ps     894.3mV    899.3mV    873.5mV
1.147ns   869.4mV    818.9mV    861.9mV
1.549ns   861.6mV    796.5mV    858.4mV
10ns      860mV      793.1mV    857.1mV
[Falling Waveform]
R_fixture= 50.000
V_fixture= 0.0
V_fixture_min= 0.0
V_fixture_max= 0.0
|time   V(typ)   V(min)   V(max)
0s        934.5mV    912.4mV    1.022V
246ps     936.4mV    912.5mV    981.7mV
292ps     930.1mV    911.7mV    837.4mV
351ps     834mV      915.7mV    490mV
447ps     434.7mV    888.5mV    147.5mV
537ps     154.2mV    710.3mV    44.54mV
666ps     30.97mV    238.6mV    8.952mV
805ps     6.529mV    46.85mV    2.04mV
1.063ns   904.5uV    3.25mV     294.1uV
10ns      0V         0V         0V
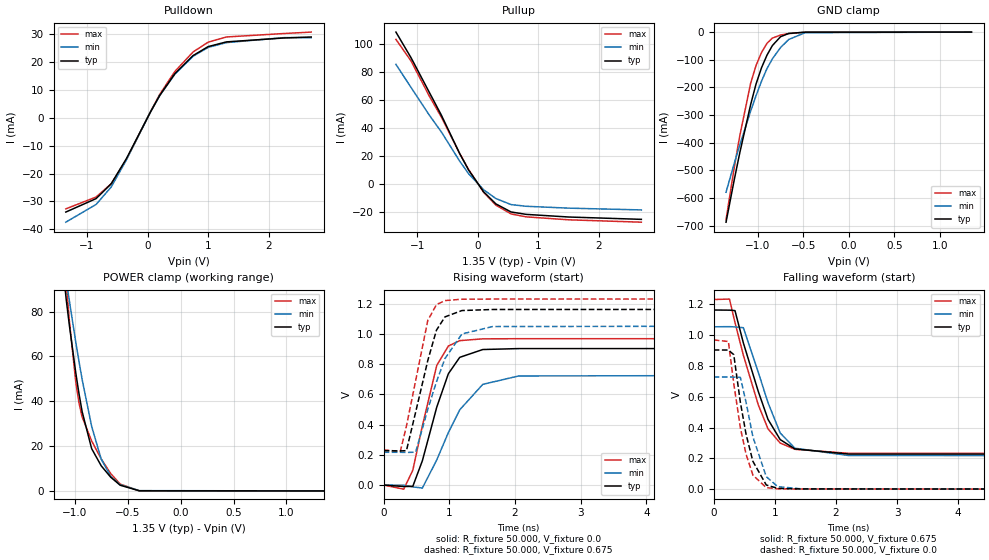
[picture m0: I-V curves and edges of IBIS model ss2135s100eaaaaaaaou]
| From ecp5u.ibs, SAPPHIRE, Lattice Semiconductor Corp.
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|   Model ss2135s100eaaaaaaaou
[Model] ss2135s100eaaaaaaaou
Model_type  Output
Polarity   Non-Inverting
Enable   Active-Low
Vmeas =  0.675V
Cref =  30.000pF
Rref =  50.000
Vref =  0.675V
C_comp   5.000pF   4.000pF   5.500pF
[Temperature Range]   25.000   0.125k   -40.000
[Voltage Range]   1.350V   1.280V   1.420V
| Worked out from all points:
|   slope of the pulldown table from 0 to 0.203 V, typ, clamps not added: 25.1 ohm
|   slope of the pullup table from 0 to 0.203 V, typ, clamps not added: 19.5 ohm
|   GND clamp passes 1 mA (typ) near -0.54 V on its own axis
|   POWER clamp passes 1 mA (typ) near -0.51 V on its own axis
|   rising waveform, R_fixture 50.000, V_fixture 0.0: 20-80 % time 368ps typ, 503ps min, 297ps max; typ from 0 V to 0.904 V
|   rising waveform, R_fixture 50.000, V_fixture 0.675: 20-80 % time 314ps typ, 391ps min, 269ps max; typ from 0.227 V to 1.16 V
|   falling waveform, R_fixture 50.000, V_fixture 0.675: 20-80 % time 465ps typ, 440ps min, 461ps max; typ from 1.16 V to 0.227 V
|   falling waveform, R_fixture 50.000, V_fixture 0.0: 20-80 % time 259ps typ, 262ps min, 250ps max; typ from 0.904 V to 0 V
[Pulldown]
|Voltage   I(typ)   I(min)   I(max)
-1.35V    -33.78mA   -37.41mA   -32.64mA
-850mV    -28.97mA   -31.05mA   -28.4mA
-600mV    -23.63mA   -24.79mA   -23.65mA
-350mV    -14.66mA   -15.1mA    -14.92mA
50mV      2.157mA    2.138mA    2.25mA
200mV     7.987mA    7.913mA    8.357mA
450mV     15.76mA    15.6mA     16.57mA
750mV     22.25mA    22mA       23.54mA
1V        25.47mA    25.19mA    27.06mA
1.3V      27.15mA    26.89mA    28.91mA
2.25V     28.55mA    28.68mA    30.15mA
2.7V      28.9mA     28.68mA    30.66mA
[Pullup]
|Voltage   I(typ)   I(min)   I(max)
-1.35V    108.6mA    85.56mA    103.4mA
-1.1V     90.26mA    69.04mA    87.95mA
-800mV    65.64mA    49.36mA    62.97mA
-600mV    49.28mA    37.29mA    47.89mA
-300mV    22.03mA    16.59mA    22.16mA
-150mV    10.08mA    7.445mA    10.4mA
100mV     -5.613mA   -4.06mA    -5.96mA
300mV     -14.08mA   -10.26mA   -14.96mA
550mV     -19.83mA   -14.55mA   -21.23mA
800mV     -21.55mA   -15.77mA   -23.33mA
1.5V      -23.43mA   -17.1mA    -25.43mA
2.7V      -25.1mA    -18.37mA   -27.13mA
[GND_clamp]
|Voltage   I(typ)   I(min)   I(max)
-1.35V    -687.3mA   -578.9mA   -678.1mA
-1.26V    -534.3mA   -475.1mA   -489.7mA
-1.2V     -438.1mA   -409.1mA   -376.7mA
-1.08V    -262.9mA   -286.2mA   -185.9mA
-1.02V    -187.7mA   -229.9mA   -120.7mA
-960mV    -129.1mA   -177.6mA   -73.95mA
-900mV    -83.6mA    -132.1mA   -40.76mA
-840mV    -48.57mA   -96.56mA   -21.66mA
-750mV    -16.65mA   -55.68mA   -10.64mA
-660mV    -4.958mA   -26.68mA   -5.448mA
-480mV    -317.7uA   -2.229mA   -341.9uA
1.35V     0A         0A         0A
[POWER_clamp]
|Voltage   I(typ)   I(min)   I(max)
-1.35V    211.5mA    193mA      324.9mA
-1.08V    85.33mA    94.25mA    92.93mA
-1.05V    73.76mA    84.65mA    75.65mA
-990mV    52.73mA    66.45mA    48.6mA
-960mV    43.53mA    57.9mA     39.38mA
-930mV    35.42mA    49.79mA    33mA
-840mV    18.88mA    28.82mA    22.31mA
-750mV    11.24mA    14.22mA    14.3mA
-660mV    6.13mA     6.499mA    7.742mA
-570mV    2.538mA    2.795mA    3.049mA
-390mV    57.41uA    134.8uA    35.81uA
1.35V     0A         0A         0A
[Ramp]
| variable   typ   min   max
dV/dt_r 0.542/0.372n   0.437/0.507n   0.581/0.299n
dV/dt_f 0.511/0.477n   0.485/0.422n   0.546/0.508n
R_load = 50.000
[Rising Waveform]
R_fixture= 50.000
V_fixture= 0.0
V_fixture_min= 0.0
V_fixture_max= 0.0
|time   V(typ)   V(min)   V(max)
0s        0V         0V         0V
306ps     -9.832mV   -698.3uV   -27.3mV
444ps     -8.644mV   -12.22mV   98.03mV
590ps     161.2mV    -19.77mV   392.1mV
809ps     515.8mV    166.6mV    792mV
986ps     737.2mV    347.6mV    920.4mV
1.159ns   845.3mV    498mV      955.8mV
1.51ns    897mV      666.4mV    967.7mV
2.056ns   903.2mV    722mV      968.6mV
10ns      903.5mV    728.2mV    968.6mV
[Rising Waveform]
R_fixture= 50.000
V_fixture= 0.675
V_fixture_min= 0.642
V_fixture_max= 0.710
|time   V(typ)   V(min)   V(max)
0s        227.4mV    216.8mV    232.4mV
254ps     225.8mV    216.7mV    222.6mV
347ps     227.6mV    215.7mV    389.8mV
487ps     482mV      217.4mV    690.2mV
672ps     823.6mV    500.8mV    1.089V
804ps     1.025V     683mV      1.194V
934ps     1.113V     837mV      1.221V
1.192ns   1.155V     1V         1.23V
1.659ns   1.162V     1.049V     1.231V
10ns      1.163V     1.054V     1.231V
[Falling Waveform]
R_fixture= 50.000
V_fixture= 0.675
V_fixture_min= 0.642
V_fixture_max= 0.710
|time   V(typ)   V(min)   V(max)
0s        1.163V     1.054V     1.231V
257ps     1.162V     1.055V     1.234V
347ps     1.159V     1.053V     1.082V
484ps     949.4mV    1.048V     869.9mV
728ps     634.7mV    758.8mV    547.5mV
888ps     452.5mV    560.9mV    391.4mV
1.087ns   321.7mV    364.6mV    299.2mV
1.328ns   261.2mV    265.8mV    258.8mV
2.209ns   227.9mV    218.3mV    232.6mV
10ns      227.4mV    216.8mV    232.4mV
[Falling Waveform]
R_fixture= 50.000
V_fixture= 0.0
V_fixture_min= 0.0
V_fixture_max= 0.0
|time   V(typ)   V(min)   V(max)
0s        903.5mV    728.2mV    968.6mV
239ps     903.1mV    728.2mV    958.5mV
327ps     873.2mV    727.5mV    686.1mV
435ps     564.4mV    725.7mV    398.6mV
529ps     355.1mV    562.5mV    225.8mV
640ps     180.7mV    339.5mV    91.38mV
859ps     27.17mV    81.38mV    9.9mV
1.047ns   5.169mV    16.42mV    2.349mV
1.427ns   1.494mV    2.294mV    1.124mV
10ns      0V         0V         0V
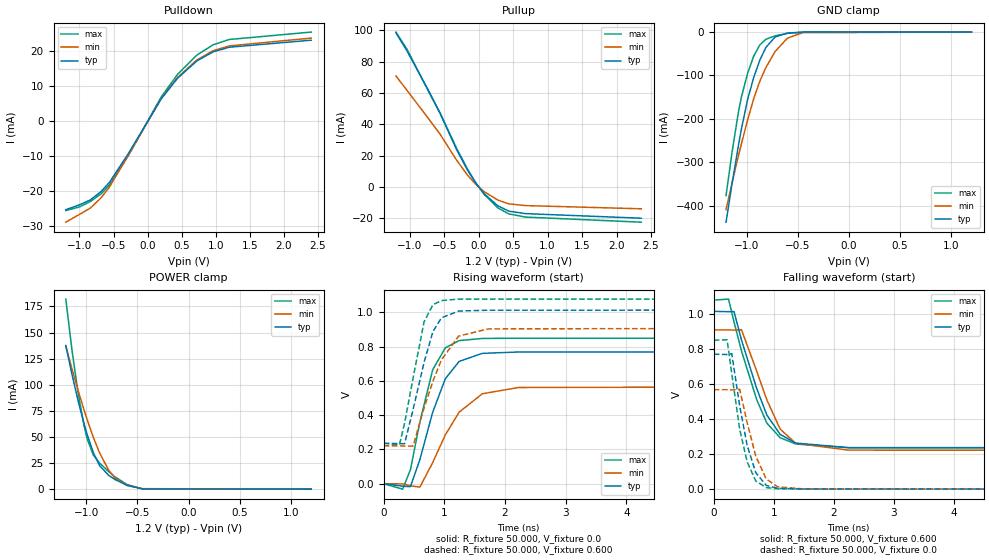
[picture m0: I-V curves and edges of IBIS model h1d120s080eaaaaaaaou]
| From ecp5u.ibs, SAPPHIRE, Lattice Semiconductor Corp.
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|   Model h1d120s080eaaaaaaaou
[Model] h1d120s080eaaaaaaaou
Model_type  Output
Polarity   Non-Inverting
Enable   Active-Low
Vmeas =  0.600V
Cref =  20.000pF
Rref =  50.000
Vref =  0.600V
C_comp   5.000pF   4.000pF   5.500pF
[Temperature Range]   25.000   0.125k   -40.000
[Voltage Range]   1.200V   1.140V   1.260V
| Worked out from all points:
|   slope of the pulldown table from 0 to 0.18 V, typ, clamps not added: 31.5 ohm
|   slope of the pullup table from 0 to 0.18 V, typ, clamps not added: 20.8 ohm
|   GND clamp passes 1 mA (typ) near -0.54 V on its own axis
|   POWER clamp passes 1 mA (typ) near -0.51 V on its own axis
|   rising waveform, R_fixture 50.000, V_fixture 0.0: 20-80 % time 414ps typ, 535ps min, 329ps max; typ from 0 V to 0.769 V
|   rising waveform, R_fixture 50.000, V_fixture 0.600: 20-80 % time 324ps typ, 423ps min, 265ps max; typ from 0.236 V to 1.01 V
|   falling waveform, R_fixture 50.000, V_fixture 0.600: 20-80 % time 475ps typ, 467ps min, 475ps max; typ from 1.01 V to 0.236 V
|   falling waveform, R_fixture 50.000, V_fixture 0.0: 20-80 % time 259ps typ, 268ps min, 252ps max; typ from 0.769 V to 0 V
[Pulldown]
|Voltage   I(typ)   I(min)   I(max)
-1.2V     -25.46mA   -29.03mA   -25.7mA
-1V       -24.07mA   -26.8mA    -24.67mA
-840mV    -22.66mA   -25mA      -23.11mA
-680mV    -20.21mA   -22.01mA   -20.87mA
-560mV    -17.64mA   -18.97mA   -18.42mA
-280mV    -9.315mA   -9.799mA   -9.876mA
200mV     6.283mA    6.399mA    6.82mA
440mV     12.18mA    12.4mA     13.3mA
720mV     17.09mA    17.37mA    18.76mA
960mV     19.72mA    20.05mA    21.74mA
1.2V      21.05mA    21.43mA    23.27mA
2.4V      23.06mA    23.66mA    25.38mA
[Pullup]
|Voltage   I(typ)   I(min)   I(max)
-1.2V     98.36mA    70.8mA     98.76mA
-1.04V    86.78mA    61.68mA    87.88mA
-720mV    60.95mA    43.17mA    60.32mA
-560mV    47.01mA    33.72mA    47.3mA
-320mV    23.89mA    17.14mA    24.7mA
-160mV    10.63mA    7.474mA    11.31mA
-40mV     2.404mA    1.656mA    2.627mA
80mV      -4.283mA   -2.939mA   -4.726mA
280mV     -12.04mA   -8.34mA    -13.32mA
440mV     -15.37mA   -10.72mA   -17.13mA
680mV     -16.93mA   -11.81mA   -19.13mA
2.36V     -19.85mA   -13.86mA   -22.39mA
[GND_clamp]
|Voltage   I(typ)   I(min)   I(max)
-1.2V     -438mA     -409mA     -376.5mA
-1.14V    -347.3mA   -346mA     -274.9mA
-1.08V    -262.9mA   -286.2mA   -185.9mA
-1.05V    -223.7mA   -257.6mA   -150mA
-990mV    -156.1mA   -203.2mA   -95.66mA
-930mV    -105mA     -153.7mA   -55.58mA
-870mV    -64.74mA   -113.2mA   -29.56mA
-810mV    -35.2mA    -81.56mA   -16.45mA
-720mV    -11.09mA   -44.69mA   -8.691mA
-600mV    -2.287mA   -13.94mA   -2.904mA
-450mV    -166.2uA   -1.247mA   -164.1uA
1.2V      0A         0A         0A
[POWER_clamp]
|Voltage   I(typ)   I(min)   I(max)
-1.2V     137.6mA    137.3mA    182.1mA
-1.14V    110.1mA    115.3mA    133.6mA
-1.08V    84.76mA    94.63mA    92.15mA
-1.02V    62.11mA    75.36mA    59.94mA
-990mV    52mA       66.3mA     47.89mA
-930mV    34.81mA    49.51mA    32.55mA
-870mV    22.62mA    34.86mA    25.07mA
-780mV    13.14mA    18.01mA    16.74mA
-720mV    9.284mA    10.72mA    11.88mA
-600mV    3.553mA    3.709mA    4.373mA
-450mV    294.8uA    471.6uA    256.4uA
1.2V      0A         0A         0A
[Ramp]
| variable   typ   min   max
dV/dt_r   0.459/0.416n   0.345/0.536n   0.481/0.332n
dV/dt_f   0.411/0.487n   0.397/0.446n   0.448/0.513n
R_load = 50.000
[Rising Waveform]
R_fixture= 50.000
V_fixture= 0.0
V_fixture_min= 0.0
V_fixture_max= 0.0
|time   V(typ)   V(min)   V(max)
0s        0V         0V         0V
314ps     -14.33mV   -984.2uV   -31.79mV
441ps     -17.33mV   -11.8mV    81.64mV
597ps     140.6mV    -19.94mV   360mV
808ps     416.8mV    123.1mV    664.6mV
1.017ns   612.5mV    285.1mV    792.6mV
1.244ns   713.4mV    417.3mV    834.8mV
1.627ns   760.3mV    524.7mV    847.3mV
2.225ns   768.3mV    561.3mV    848.6mV
10ns      768.8mV    566.5mV    848.6mV
[Rising Waveform]
R_fixture= 50.000
V_fixture= 0.600
V_fixture_min= 0.571
V_fixture_max= 0.631
|time   V(typ)   V(min)   V(max)
0s        236.1mV    221.1mV    235.9mV
260ps     233.9mV    221mV      227mV
345ps     233.3mV    219.8mV    352.8mV
484ps     430.9mV    219.4mV    613.9mV
666ps     707.8mV    440.6mV    943.8mV
812ps     887.4mV    597.6mV    1.044V
952ps     967.7mV    722.5mV    1.068V
1.236ns   1.007V     861mV      1.077V
1.726ns   1.012V     903.2mV    1.077V
10ns      1.013V     907.6mV    1.077V
[Falling Waveform]
R_fixture= 50.000
V_fixture= 0.600
V_fixture_min= 0.571
V_fixture_max= 0.631
|time   V(typ)   V(min)   V(max)
0s        1.013V     907.6mV    1.077V
246ps     1.011V     907.6mV    1.083V
337ps     1.012V     905.8mV    954mV
462ps     849.9mV    908.1mV    787.6mV
716ps     573.1mV    672.1mV    510mV
885ps     422.3mV    508.4mV    376.4mV
1.107ns   312.1mV    342.2mV    292.9mV
1.365ns   262.7mV    261.3mV    257.4mV
2.251ns   236.5mV    222.3mV    236.1mV
10ns      236.1mV    221.1mV    235.9mV
[Falling Waveform]
R_fixture= 50.000
V_fixture= 0.0
V_fixture_min= 0.0
V_fixture_max= 0.0
|time   V(typ)   V(min)   V(max)
0s        768.8mV    566.6mV    848.7mV
222ps     767.1mV    566.6mV    851.1mV
300ps     772mV      565.5mV    658mV
433ps     472.3mV    568.1mV    339.2mV
557ps     248.7mV    378.1mV    155.4mV
701ps     93.39mV    186.9mV    46.36mV
875ps     21.76mV    57.95mV    9.019mV
1.066ns   4.778mV    13.16mV    2.354mV
1.491ns   1.157mV    1.805mV    1.016mV
10ns      0V         0V         0V
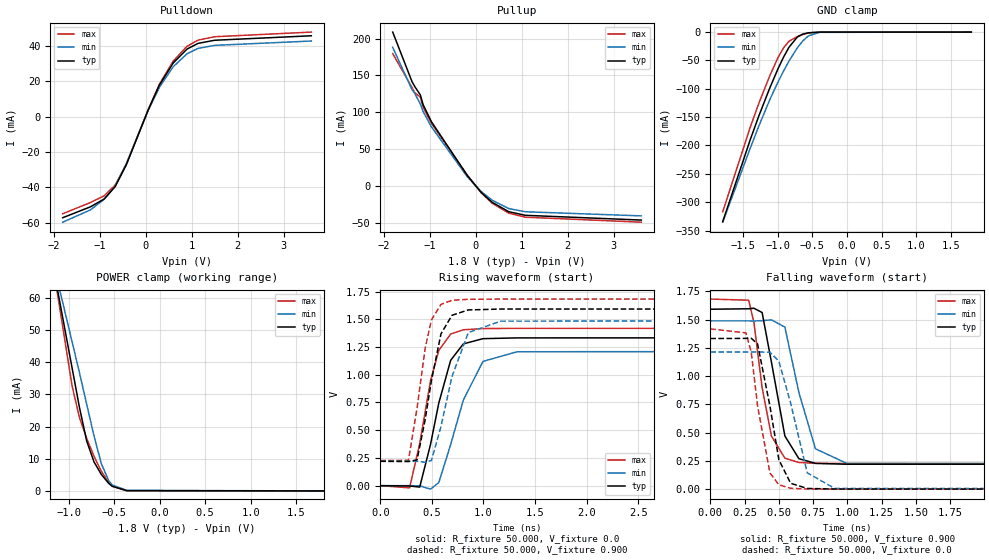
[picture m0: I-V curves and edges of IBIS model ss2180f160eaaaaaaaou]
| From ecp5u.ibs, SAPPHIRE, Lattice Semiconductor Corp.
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|   Model ss2180f160eaaaaaaaou
[Model] ss2180f160eaaaaaaaou
Model_type  Output
Polarity   Non-Inverting
Enable   Active-Low
Vmeas =  0.900V
Cref =  30.000pF
Rref =  50.000
Vref =  0.900V
C_comp   5.000pF   4.000pF   5.500pF
[Temperature Range]   25.000   0.125k   -40.000
[Voltage Range]   1.800V   1.710V   1.890V
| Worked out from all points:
|   slope of the pulldown table from 0 to 0.27 V, typ, clamps not added: 16.6 ohm
|   slope of the pullup table from 0 to 0.27 V, typ, clamps not added: 15.6 ohm
|   GND clamp passes 1 mA (typ) near -0.54 V on its own axis
|   POWER clamp passes 1 mA (typ) near -0.49 V on its own axis
|   rising waveform, R_fixture 50.000, V_fixture 0.0: 20-80 % time 192ps typ, 241ps min, 171ps max; typ from 0 V to 1.33 V
|   rising waveform, R_fixture 50.000, V_fixture 0.900: 20-80 % time 156ps typ, 196ps min, 135ps max; typ from 0.219 V to 1.59 V
|   falling waveform, R_fixture 50.000, V_fixture 0.900: 20-80 % time 115ps typ, 134ps min, 107ps max; typ from 1.59 V to 0.219 V
|   falling waveform, R_fixture 50.000, V_fixture 0.0: 20-80 % time 102ps typ, 124ps min, 92ps max; typ from 1.33 V to 0 V
[Pulldown]
|Voltage   I(typ)   I(min)   I(max)
-1.8V     -57.26mA   -59.78mA   -54.99mA
-1.2V     -51.09mA   -52.83mA   -48.7mA
-900mV    -46.65mA   -46.82mA   -44.83mA
-660mV    -39.62mA   -39.31mA   -38.72mA
-420mV    -27.34mA   -26.64mA   -27.21mA
60mV      4.04mA     3.769mA    4.134mA
300mV     17.85mA    16.63mA    18.36mA
600mV     30.4mA     28.29mA    31.47mA
900mV     38.31mA    35.64mA    39.89mA
1.14V     41.54mA    38.7mA     43.38mA
1.5V      43.3mA     40.41mA    45.3mA
3.6V      45.84mA    42.87mA    47.93mA
[Pullup]
|Voltage   I(typ)   I(min)   I(max)
-1.8V     208.8mA    188.2mA    179.7mA
-1.38V    141.5mA    130.6mA    133.6mA
-1.32V    134.9mA    125.5mA    126.6mA
-1.2V     123.7mA    111.3mA    120.7mA
-1.14V    110.5mA    101.2mA    107mA
-960mV    87.38mA    80.47mA    85.17mA
-180mV    14.35mA    12.65mA    14.86mA
120mV     -8.407mA   -7.262mA   -8.924mA
360mV     -21.95mA   -19.1mA    -23.21mA
720mV     -34.68mA   -30.43mA   -36.67mA
1.08V     -39.59mA   -34.77mA   -42.14mA
3.6V      -46.04mA   -40.36mA   -48.91mA
[GND_clamp]
|Voltage   I(typ)   I(min)   I(max)
-1.8V     -334.4mA   -335.3mA   -317.1mA
-1.4V     -189.3mA   -204.4mA   -167.3mA
-1.28V    -148.9mA   -166.7mA   -126.7mA
-1.12V    -99.04mA   -119.7mA   -77.45mA
-1V       -64.9mA    -88.2mA    -45.18mA
-920mV    -44.4mA    -68.92mA   -27.88mA
-840mV    -26.71mA   -51.09mA   -16.18mA
-720mV    -8.754mA   -27.82mA   -7.821mA
-640mV    -3.53mA    -15.52mA   -4.188mA
-560mV    -1.27mA    -6.791mA   -1.597mA
-400mV    -49.63uA   -425.4uA   -44.12uA
1.8V      0A         0A         0A
[POWER_clamp]
|Voltage   I(typ)   I(min)   I(max)
-1.8V     174.6mA    158.5mA    191.6mA
-1.36V    100.3mA    96.28mA    105.7mA
-1.12V    62.39mA    65.2mA     61.09mA
-960mV    38.11mA    46.28mA    32.52mA
-880mV    25.96mA    36.75mA    22.79mA
-800mV    15.45mA    26.86mA    16.3mA
-720mV    9.004mA    17.05mA    10.75mA
-640mV    5.132mA    8.487mA    6.134mA
-560mV    2.382mA    3.217mA    2.693mA
-520mV    1.425mA    1.849mA    1.506mA
-360mV    88.16uA    177.6uA    42.1uA
1.8V      0A         0A         0A
[Ramp]
| variable   typ   min   max
dV/dt_r 0.561/0.198n   0.497/0.255n   0.601/0.174n
dV/dt_f 0.563/0.131n   0.519/0.151n   0.597/0.124n
R_load = 25.000
[Rising Waveform]
R_fixture= 50.000
V_fixture= 0.0
V_fixture_min= 0.0
V_fixture_max= 0.0
|time   V(typ)   V(min)   V(max)
0s        0V         0V         0V
284ps     -2.795mV   -213.4uV   -19.91mV
382ps     -13.01mV   -1.326mV   379.2mV
487ps     372.3mV    -31.66mV   947.4mV
567ps     744.3mV    27.67mV    1.219V
682ps     1.13V      370.3mV    1.367V
805ps     1.278V     771.8mV    1.405V
995ps     1.325V     1.12V      1.416V
1.325ns   1.332V     1.207V     1.418V
10ns      1.333V     1.214V     1.418V
[Rising Waveform]
R_fixture= 50.000
V_fixture= 0.900
V_fixture_min= 0.856
V_fixture_max= 0.946
|time   V(typ)   V(min)   V(max)
0s        219.4mV    220mV      226.7mV
273ps     217.5mV    219.8mV    228.9mV
356ps     232.4mV    219.2mV    696.7mV
435ps     595.2mV    211.1mV    1.239V
495ps     943.2mV    226.3mV    1.493V
588ps     1.368V     532.7mV    1.634V
695ps     1.536V     984.6mV    1.671V
853ps     1.584V     1.38V      1.68V
1.168ns   1.592V     1.483V     1.682V
10ns      1.592V     1.489V     1.682V
[Falling Waveform]
R_fixture= 50.000
V_fixture= 0.900
V_fixture_min= 0.856
V_fixture_max= 0.946
|time   V(typ)   V(min)   V(max)
0s        1.592V     1.489V     1.682V
280ps     1.596V     1.489V     1.672V
318ps     1.601V     1.488V     1.477V
378ps     1.563V     1.491V     898.2mV
446ps     1.123V     1.498V     469.4mV
544ps     470.6mV    1.434V     274.2mV
646ps     269.8mV    856.2mV    236.2mV
767ps     228.1mV    357.4mV    228.8mV
997ps     220.6mV    227mV      227.1mV
10ns      219.4mV    220mV      226.7mV
[Falling Waveform]
R_fixture= 50.000
V_fixture= 0.0
V_fixture_min= 0.0
V_fixture_max= 0.0
|time   V(typ)   V(min)   V(max)
0s        1.333V     1.214V     1.418V
260ps     1.334V     1.214V     1.383V
299ps     1.335V     1.213V     1.211V
345ps     1.284V     1.214V     735.7mV
435ps     734.8mV    1.211V     143.9mV
500ps     260.4mV    1.132V     38.88mV
586ps     51.75mV    760.8mV    8.005mV
707ps     6.479mV    144.8mV    1.618mV
907ps     1.076mV    6.466mV    377.6uV
10ns      0V         0V         0V
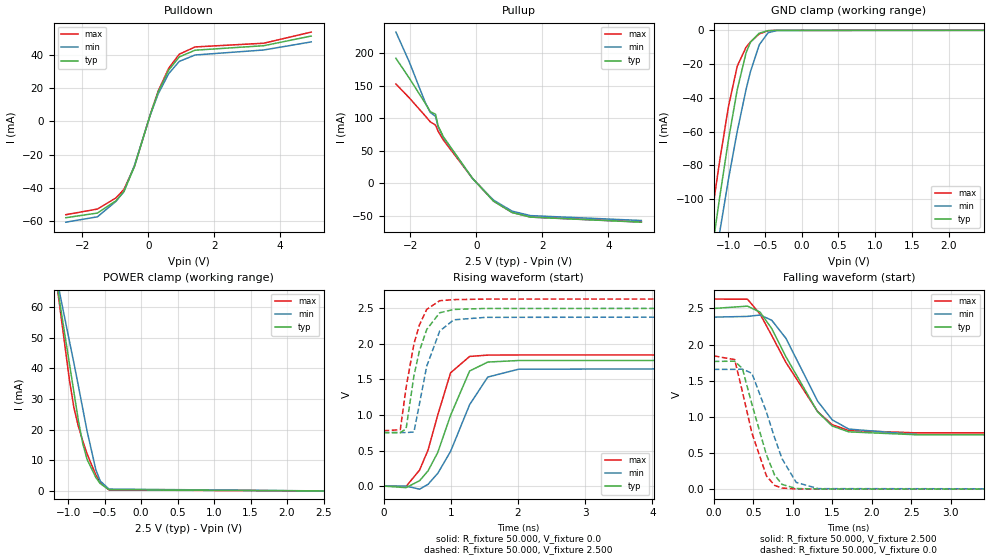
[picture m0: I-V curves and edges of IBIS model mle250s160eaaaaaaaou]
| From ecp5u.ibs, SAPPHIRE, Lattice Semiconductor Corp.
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|   Model mle250s160eaaaaaaaou
[Model] mle250s160eaaaaaaaou
Model_type  Output
Polarity   Non-Inverting
Enable   Active-Low
Vmeas =  1.250V
Cref =  3.000pF
Rref =  50.000
Vref =  1.250V
C_comp   5.000pF   4.000pF   5.500pF
[Temperature Range]   25.000   0.125k   -40.000
[Voltage Range]   2.500V   2.380V   2.630V
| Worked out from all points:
|   slope of the pulldown table from 0 to 0.375 V, typ, clamps not added: 17.5 ohm
|   slope of the pullup table from 0 to 0.375 V, typ, clamps not added: 18 ohm
|   GND clamp passes 1 mA (typ) near -0.54 V on its own axis
|   POWER clamp passes 1 mA (typ) near -0.49 V on its own axis
|   rising waveform, R_fixture 50.000, V_fixture 0.0: 20-80 % time 403ps typ, 457ps min, 339ps max; typ from 0 V to 1.77 V
|   rising waveform, R_fixture 50.000, V_fixture 2.500: 20-80 % time 240ps typ, 248ps min, 228ps max; typ from 0.752 V to 2.5 V
|   falling waveform, R_fixture 50.000, V_fixture 2.500: 20-80 % time 525ps typ, 471ps min, 591ps max; typ from 2.5 V to 0.752 V
|   falling waveform, R_fixture 50.000, V_fixture 0.0: 20-80 % time 277ps typ, 306ps min, 257ps max; typ from 1.77 V to 0 V
[Pulldown]
|Voltage   I(typ)   I(min)   I(max)
-2.5V     -58.2mA    -60.91mA   -56.39mA
-1.54V    -55.38mA   -57.65mA   -52.96mA
-980mV    -47.99mA   -48.34mA   -46.23mA
-740mV    -42.44mA   -42.44mA   -41.18mA
-420mV    -27.34mA   -26.64mA   -27.21mA
60mV      4.04mA     3.769mA    4.134mA
300mV     17.85mA    16.63mA    18.36mA
620mV     31.07mA    28.91mA    32.17mA
940mV     39.03mA    36.32mA    40.66mA
1.42V     43.07mA    40.18mA    45.04mA
3.5V      45.79mA    43.2mA     47.28mA
4.94V     51.63mA    48.08mA    54.02mA
[Pullup]
|Voltage   I(typ)   I(min)   I(max)
-2.44V    192mA      232.2mA    152.5mA
-2.04V    161.9mA    187mA      131.5mA
-1.56V    123.7mA    125.3mA    104.1mA
-1.4V     110.1mA    108.8mA    94.53mA
-1.24V    106.2mA    102.8mA    89.45mA
-1.16V    88.16mA    86.54mA    79.94mA
-1V       71.3mA     70.61mA    66.43mA
-120mV    7.839mA    7.396mA    7.763mA
520mV     -27.33mA   -25.76mA   -27.24mA
1.08V     -44.77mA   -42.65mA   -44.53mA
1.64V     -51.84mA   -49.54mA   -51.76mA
5V        -59.63mA   -57.03mA   -59.32mA
[GND_clamp]
|Voltage   I(typ)   I(min)   I(max)
-2.5V     -600.3mA   -576.2mA   -594.4mA
-1.24V    -136mA     -154.5mA   -113.9mA
-1.18V    -117.2mA   -136.7mA   -95.27mA
-1.12V    -99.04mA   -119.7mA   -77.45mA
-1V       -64.9mA    -88.21mA   -45.19mA
-880mV    -35.12mA   -59.82mA   -21.21mA
-760mV    -13.33mA   -35.03mA   -10mA
-700mV    -7.01mA    -24.46mA   -6.829mA
-580mV    -1.679mA   -8.593mA   -2.127mA
-460mV    -210.1uA   -1.441mA   -213.7uA
-340mV    -8.598uA   -109.2uA   -6.553uA
2.48V     0A         0A         0A
[POWER_clamp]
|Voltage   I(typ)   I(min)   I(max)
-2.48V    301.8mA    269mA      334.4mA
-1.16V    68.59mA    70.21mA    68.47mA
-1.1V     59.33mA    62.74mA    57.51mA
-980mV    41.18mA    48.59mA    35.82mA
-920mV    32.13mA    41.65mA    27.11mA
-860mV    23.04mA    34.34mA    21.08mA
-800mV    15.49mA    26.9mA     16.35mA
-740mV    10.29mA    19.52mA    12.1mA
-620mV    4.381mA    6.888mA    5.184mA
-560mV    2.412mA    3.25mA     2.719mA
-440mV    397.7uA    604uA      311uA
2.5V      0A         0A         0A
[Ramp]
| variable   typ   min   max
dV/dt_r 1.060/0.407n   0.994/0.470n   1.106/0.347n
dV/dt_f 1.049/0.528n   0.976/0.483n   1.111/0.595n
R_load = 50.000
[Rising Waveform]
R_fixture= 50.000
V_fixture= 0.0
V_fixture_min= 0.0
V_fixture_max= 0.0
|time   V(typ)   V(min)   V(max)
0s        0V         0V         0V
334ps     -22.11mV   -266.8uV   -5.143mV
535ps     75.98mV    -43.25mV   225.5mV
661ps     214.1mV    25.08mV    508mV
806ps     474.3mV    180.2mV    1.002V
996ps     995.6mV    487.6mV    1.593V
1.279ns   1.618V     1.144V     1.823V
1.549ns   1.744V     1.533V     1.842V
2.009ns   1.766V     1.644V     1.844V
10ns      1.767V     1.657V     1.844V
[Rising Waveform]
R_fixture= 50.000
V_fixture= 2.500
V_fixture_min= 2.380
V_fixture_max= 2.630
|time   V(typ)   V(min)   V(max)
0s        751.8mV    752.6mV    778.5mV
248ps     751.2mV    752.6mV    793.2mV
334ps     805.8mV    752.3mV    1.386V
451ps     1.552V     760.4mV    2.001V
531ps     1.897V     1.148V     2.262V
641ps     2.202V     1.686V     2.485V
834ps     2.437V     2.18V      2.607V
1.043ns   2.484V     2.338V     2.622V
1.516ns   2.498V     2.373V     2.63V
10ns      2.5V       2.38V      2.63V
[Falling Waveform]
R_fixture= 50.000
V_fixture= 2.500
V_fixture_min= 2.380
V_fixture_max= 2.630
|time   V(typ)   V(min)   V(max)
0s        2.5V       2.38V      2.63V
427ps     2.532V     2.39V      2.628V
587ps     2.449V     2.409V     2.422V
734ps     2.221V     2.337V     2.126V
914ps     1.832V     2.087V     1.753V
1.316ns   1.068V     1.217V     1.073V
1.5ns     873.9mV    959.3mV    891.8mV
1.71ns    792.7mV    831.2mV    812.4mV
2.57ns    752.7mV    756mV      778.8mV
10ns      751.8mV    752.6mV    778.5mV
[Falling Waveform]
R_fixture= 50.000
V_fixture= 0.0
V_fixture_min= 0.0
V_fixture_max= 0.0
|time   V(typ)   V(min)   V(max)
0s        1.767V     1.657V     1.844V
265ps     1.771V     1.657V     1.792V
363ps     1.668V     1.66V      1.347V
483ps     1.175V     1.604V     776.7mV
667ps     475.7mV    1.066V     184.6mV
770ps     196mV      714.4mV    52.49mV
865ps     66.1mV     420.9mV    15.35mV
1.044ns   8.875mV    93.96mV    3.111mV
1.324ns   2.541mV    7.248mV    1.521mV
10ns      0V         0V         0V
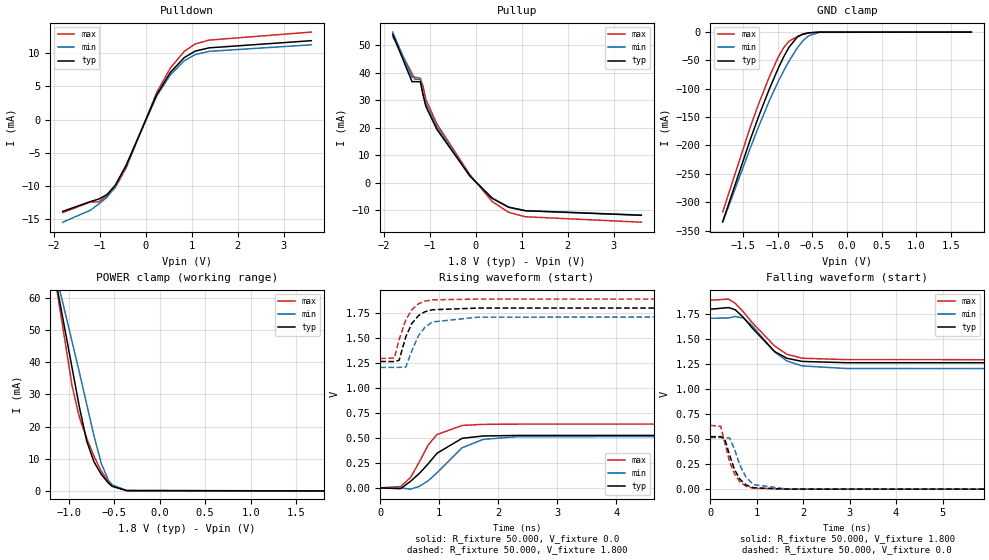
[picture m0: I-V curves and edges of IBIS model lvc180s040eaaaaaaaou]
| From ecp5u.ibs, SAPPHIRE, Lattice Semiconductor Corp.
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|   Model lvc180s040eaaaaaaaou
[Model] lvc180s040eaaaaaaaou
Model_type  Output
Polarity   Non-Inverting
Enable   Active-Low
Vmeas =  0.900V
Cref =  0.0F
Rref =  1.000M
Vref =  0.0V
C_comp   5.000pF   4.000pF   5.500pF
[Temperature Range]   25.000   0.125k   -40.000
[Voltage Range]   1.800V   1.710V   1.890V
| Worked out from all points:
|   slope of the pulldown table from 0 to 0.27 V, typ, clamps not added: 65.7 ohm
|   slope of the pullup table from 0 to 0.27 V, typ, clamps not added: 60.6 ohm
|   GND clamp passes 1 mA (typ) near -0.54 V on its own axis
|   POWER clamp passes 1 mA (typ) near -0.49 V on its own axis
|   rising waveform, R_fixture 50.000, V_fixture 0.0: 20-80 % time 509ps typ, 539ps min, 377ps max; typ from 0 V to 0.525 V
|   rising waveform, R_fixture 50.000, V_fixture 1.800: 20-80 % time 230ps typ, 260ps min, 228ps max; typ from 1.26 V to 1.8 V
|   falling waveform, R_fixture 50.000, V_fixture 1.800: 20-80 % time 637ps typ, 609ps min, 716ps max; typ from 1.8 V to 1.26 V
|   falling waveform, R_fixture 50.000, V_fixture 0.0: 20-80 % time 259ps typ, 284ps min, 258ps max; typ from 0.525 V to 0 V
[Pulldown]
|Voltage   I(typ)   I(min)   I(max)
-1.8V     -13.87mA   -15.5mA    -14.05mA
-1.2V     -12.39mA   -13.7mA    -12.46mA
-1.02V    -12.02mA   -12.76mA   -12.43mA
-840mV    -11.35mA   -11.76mA   -11.57mA
-660mV    -9.94mA    -10.14mA   -10.28mA
-420mV    -6.892mA   -6.861mA   -7.26mA
240mV     3.719mA    3.535mA    4.043mA
540mV     7.135mA    6.775mA    7.808mA
840mV     9.359mA    8.879mA    10.3mA
1.08V     10.34mA    9.814mA    11.42mA
1.38V     10.83mA    10.3mA     12mA
3.6V      11.91mA    11.29mA    13.21mA
[Pullup]
|Voltage   I(typ)   I(min)   I(max)
-1.8V     54.03mA    54.83mA    53.25mA
-1.38V    36.79mA    38.42mA    39.74mA
-1.32V    36.79mA    38.42mA    37.67mA
-1.2V     36.79mA    38.06mA    37.67mA
-1.14V    31.86mA    32.3mA     35.11mA
-1.08V    27.81mA    28.79mA    30.3mA
-840mV    19.42mA    20.31mA    21.38mA
-120mV    2.406mA    2.383mA    2.868mA
360mV     -5.638mA   -5.554mA   -6.804mA
720mV     -8.906mA   -8.849mA   -10.75mA
1.08V     -10.17mA   -10.11mA   -12.35mA
3.6V      -11.82mA   -11.74mA   -14.33mA
[GND_clamp]
|Voltage   I(typ)   I(min)   I(max)
-1.8V     -334.4mA   -335.3mA   -317.1mA
-1.4V     -189.3mA   -204.4mA   -167.3mA
-1.28V    -148.9mA   -166.7mA   -126.7mA
-1.12V    -99.04mA   -119.7mA   -77.45mA
-1V       -64.9mA    -88.2mA    -45.18mA
-920mV    -44.4mA    -68.92mA   -27.88mA
-840mV    -26.71mA   -51.09mA   -16.18mA
-720mV    -8.754mA   -27.82mA   -7.821mA
-640mV    -3.53mA    -15.52mA   -4.188mA
-560mV    -1.27mA    -6.791mA   -1.597mA
-400mV    -49.63uA   -425.4uA   -44.12uA
1.8V      0A         0A         0A
[POWER_clamp]
|Voltage   I(typ)   I(min)   I(max)
-1.8V     174.6mA    158.5mA    191.6mA
-1.36V    100.3mA    96.28mA    105.7mA
-1.12V    62.39mA    65.2mA     61.09mA
-960mV    38.11mA    46.28mA    32.52mA
-880mV    25.96mA    36.75mA    22.79mA
-800mV    15.45mA    26.86mA    16.3mA
-720mV    9.004mA    17.05mA    10.75mA
-640mV    5.132mA    8.487mA    6.134mA
-560mV    2.382mA    3.217mA    2.693mA
-520mV    1.425mA    1.849mA    1.506mA
-360mV    88.16uA    177.6uA    42.1uA
1.8V      0A         0A         0A
[Ramp]
| variable   typ   min   max
dV/dt_r   0.314/0.518n   0.308/0.553n   0.381/0.379n
dV/dt_f   0.321/0.642n   0.302/0.625n   0.357/0.729n
R_load = 50.000
[Rising Waveform]
R_fixture= 50.000
V_fixture= 0.0
V_fixture_min= 0.0
V_fixture_max= 0.0
|time   V(typ)   V(min)   V(max)
0s        0V         0V         0V
345ps     -8.379mV   -388.8uV   12.9mV
513ps     65.64mV    -13.1mV    104.1mV
658ps     142.5mV    14.11mV    256.3mV
811ps     240.3mV    70.7mV     428.8mV
961ps     346.6mV    150.9mV    533.7mV
1.387ns   496mV      401.5mV    624.9mV
1.737ns   519.2mV    484.4mV    635.6mV
2.316ns   524.6mV    512.5mV    637.9mV
10ns      525.1mV    515.9mV    638mV
[Rising Waveform]
R_fixture= 50.000
V_fixture= 1.800
V_fixture_min= 1.710
V_fixture_max= 1.890
|time   V(typ)   V(min)   V(max)
0s        1.265V     1.206V     1.295V
240ps     1.264V     1.206V     1.3V
319ps     1.277V     1.206V     1.485V
433ps     1.514V     1.21V      1.682V
534ps     1.645V     1.373V     1.783V
648ps     1.725V     1.524V     1.843V
755ps     1.763V     1.607V     1.869V
884ps     1.783V     1.661V     1.882V
1.66ns    1.8V       1.709V     1.89V
10ns      1.8V       1.71V      1.89V
[Falling Waveform]
R_fixture= 50.000
V_fixture= 1.800
V_fixture_min= 1.710
V_fixture_max= 1.890
|time   V(typ)   V(min)   V(max)
0s        1.8V       1.71V      1.89V
394ps     1.817V     1.713V     1.902V
538ps     1.795V     1.728V     1.859V
708ps     1.721V     1.713V     1.776V
894ps     1.617V     1.64V      1.671V
1.384ns   1.377V     1.375V     1.433V
1.649ns   1.31V      1.283V     1.35V
1.978ns   1.278V     1.233V     1.31V
2.944ns   1.265V     1.207V     1.296V
10ns      1.265V     1.206V     1.295V
[Falling Waveform]
R_fixture= 50.000
V_fixture= 0.0
V_fixture_min= 0.0
V_fixture_max= 0.0
|time   V(typ)   V(min)   V(max)
0s        525.1mV    515.9mV    638mV
225ps     525.4mV    515.9mV    629mV
313ps     502.5mV    516.1mV    465.2mV
419ps     335.5mV    510.7mV    270.4mV
523ps     194.9mV    396.5mV    151.5mV
638ps     99.04mV    239.3mV    72.61mV
774ps     40.63mV    116.7mV    27.74mV
934ps     13.62mV    44.73mV    8.764mV
1.654ns   554.5uV    1.396mV    587.1uV
10ns      0V         0V         0V
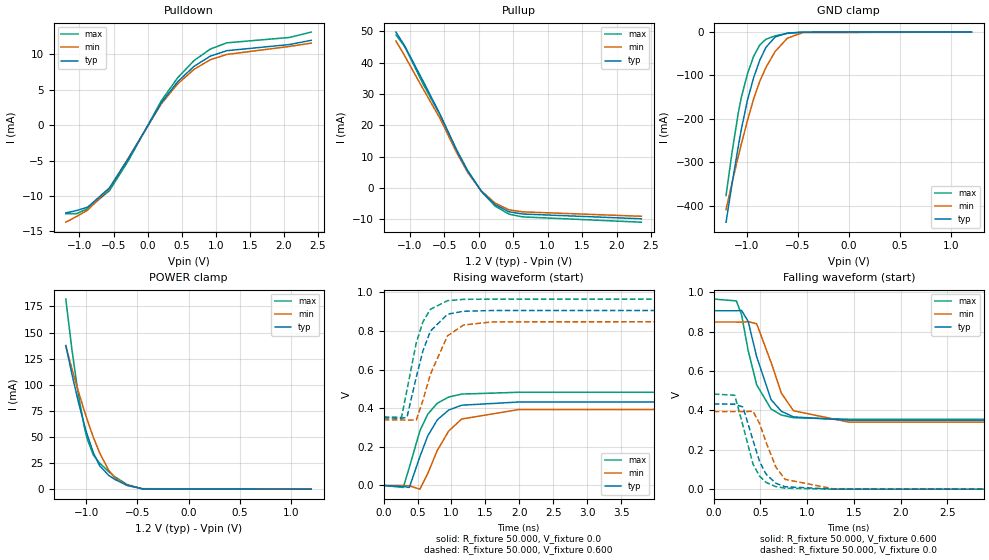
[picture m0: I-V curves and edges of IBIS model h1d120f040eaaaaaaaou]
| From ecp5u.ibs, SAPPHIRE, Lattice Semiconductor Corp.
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|   Model h1d120f040eaaaaaaaou
[Model] h1d120f040eaaaaaaaou
Model_type  Output
Polarity   Non-Inverting
Enable   Active-Low
Vmeas =  0.600V
Cref =  20.000pF
Rref =  50.000
Vref =  0.600V
C_comp   5.000pF   4.000pF   5.500pF
[Temperature Range]   25.000   0.125k   -40.000
[Voltage Range]   1.200V   1.140V   1.260V
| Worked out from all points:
|   slope of the pulldown table from 0 to 0.18 V, typ, clamps not added: 62.6 ohm
|   slope of the pullup table from 0 to 0.18 V, typ, clamps not added: 41.6 ohm
|   GND clamp passes 1 mA (typ) near -0.54 V on its own axis
|   POWER clamp passes 1 mA (typ) near -0.51 V on its own axis
|   rising waveform, R_fixture 50.000, V_fixture 0.0: 20-80 % time 327ps typ, 376ps min, 303ps max; typ from 0 V to 0.433 V
|   rising waveform, R_fixture 50.000, V_fixture 0.600: 20-80 % time 264ps typ, 305ps min, 239ps max; typ from 0.35 V to 0.906 V
|   falling waveform, R_fixture 50.000, V_fixture 0.600: 20-80 % time 201ps typ, 222ps min, 189ps max; typ from 0.906 V to 0.35 V
|   falling waveform, R_fixture 50.000, V_fixture 0.0: 20-80 % time 182ps typ, 204ps min, 167ps max; typ from 0.433 V to 0 V
[Pulldown]
|Voltage   I(typ)   I(min)   I(max)
-1.2V     -12.39mA   -13.7mA    -12.49mA
-1.04V    -12.05mA   -12.88mA   -12.49mA
-880mV    -11.58mA   -12mA      -11.79mA
-560mV    -8.851mA   -8.925mA   -9.245mA
-280mV    -4.688mA   -4.607mA   -4.974mA
200mV     3.164mA    3.008mA    3.437mA
440mV     6.136mA    5.828mA    6.7mA
680mV     8.315mA    7.89mA     9.126mA
920mV     9.761mA    9.262mA    10.76mA
1.16V     10.53mA    9.999mA    11.64mA
2.08V     11.4mA     11.13mA    12.4mA
2.4V      12mA       11.6mA     13.16mA
[Pullup]
|Voltage   I(typ)   I(min)   I(max)
-1.2V     49.81mA    46.94mA    48.92mA
-1.08V    45.69mA    42.51mA    45.38mA
-1.04V    44.01mA    40.89mA    43.73mA
-800mV    33.87mA    31.41mA    32.97mA
-560mV    23.54mA    22.17mA    23.28mA
-320mV    11.96mA    11.27mA    12.16mA
-160mV    5.32mA     4.915mA    5.567mA
40mV      -1.115mA   -1.004mA   -1.21mA
240mV     -5.411mA   -4.919mA   -5.88mA
440mV     -7.689mA   -7.053mA   -8.429mA
640mV     -8.391mA   -7.704mA   -9.316mA
2.36V     -9.926mA   -9.119mA   -11.01mA
[GND_clamp]
|Voltage   I(typ)   I(min)   I(max)
-1.2V     -438mA     -409mA     -376.5mA
-1.14V    -347.3mA   -346mA     -274.9mA
-1.08V    -262.9mA   -286.2mA   -185.9mA
-1.05V    -223.7mA   -257.6mA   -150mA
-990mV    -156.1mA   -203.2mA   -95.66mA
-930mV    -105mA     -153.7mA   -55.58mA
-870mV    -64.74mA   -113.2mA   -29.56mA
-810mV    -35.2mA    -81.56mA   -16.45mA
-720mV    -11.09mA   -44.69mA   -8.691mA
-600mV    -2.287mA   -13.94mA   -2.904mA
-450mV    -166.2uA   -1.247mA   -164.1uA
1.2V      0A         0A         0A
[POWER_clamp]
|Voltage   I(typ)   I(min)   I(max)
-1.2V     137.6mA    137.3mA    182.1mA
-1.14V    110.1mA    115.3mA    133.6mA
-1.08V    84.76mA    94.63mA    92.15mA
-1.02V    62.11mA    75.36mA    59.94mA
-990mV    52mA       66.3mA     47.89mA
-930mV    34.81mA    49.51mA    32.55mA
-870mV    22.62mA    34.86mA    25.07mA
-780mV    13.14mA    18.01mA    16.74mA
-720mV    9.284mA    10.72mA    11.88mA
-600mV    3.553mA    3.709mA    4.373mA
-450mV    294.8uA    471.6uA    256.4uA
1.2V      0A         0A         0A
[Ramp]
| variable   typ   min   max
dV/dt_r   0.258/0.326n   0.236/0.376n   0.288/0.306n
dV/dt_f   0.266/0.237n   0.247/0.244n   0.295/0.221n
R_load = 50.000
[Rising Waveform]
R_fixture= 50.000
V_fixture= 0.0
V_fixture_min= 0.0
V_fixture_max= 0.0
|time   V(typ)   V(min)   V(max)
0s        0V         0V         0V
289ps     -5.122mV   -442.6uV   -10.37mV
379ps     -10.33mV   -1.62mV    94.24mV
534ps     149mV      -19.21mV   282.9mV
650ps     256.4mV    61.5mV     368.9mV
790ps     339.6mV    181mV      425.7mV
960ps     390.8mV    282.4mV    458.2mV
1.151ns   415.7mV    344.2mV    473.3mV
1.99ns    432.2mV    393.1mV    482.7mV
10ns      432.5mV    394.5mV    482.9mV
[Rising Waveform]
R_fixture= 50.000
V_fixture= 0.600
V_fixture_min= 0.571
V_fixture_max= 0.631
|time   V(typ)   V(min)   V(max)
0s        350.1mV    339.6mV    355.1mV
263ps     348mV      339.4mV    352.8mV
344ps     353.3mV    338.5mV    495.3mV
481ps     561.7mV    339.3mV    738.8mV
579ps     697.2mV    440.4mV    848mV
690ps     800mV      577mV      912.7mV
941ps     886.9mV    775mV      957.1mV
1.179ns   902.5mV    831.2mV    964mV
1.61ns    906.2mV    847.5mV    965.4mV
10ns      906.4mV    848.9mV    965.5mV
[Falling Waveform]
R_fixture= 50.000
V_fixture= 0.600
V_fixture_min= 0.571
V_fixture_max= 0.631
|time   V(typ)   V(min)   V(max)
0s        906.4mV    848.9mV    965.5mV
242ps     906.3mV    848.9mV    956.1mV
297ps     908.1mV    848.5mV    886.9mV
368ps     852.3mV    850.8mV    704.2mV
459ps     672.7mV    840mV      530.2mV
613ps     454.9mV    644.2mV    407mV
723ps     395.7mV    488.1mV    376.7mV
853ps     367.1mV    398.3mV    362.8mV
1.445ns   350.3mV    340.5mV    355.2mV
10ns      350.1mV    339.6mV    355.1mV
[Falling Waveform]
R_fixture= 50.000
V_fixture= 0.0
V_fixture_min= 0.0
V_fixture_max= 0.0
|time   V(typ)   V(min)   V(max)
0s        432.5mV    394.5mV    482.9mV
224ps     431.8mV    394.5mV    477.2mV
312ps     417.3mV    393.6mV    323.8mV
420ps     248.2mV    395.7mV    127.2mV
491ps     139.3mV    332mV      65.63mV
561ps     75.57mV    236.9mV    34.08mV
664ps     30.22mV    112.5mV    12.96mV
764ps     12.36mV    49.65mV    5.064mV
1.291ns   131.5uV    681.1uV    38.25uV
10ns      0V         0V         0V
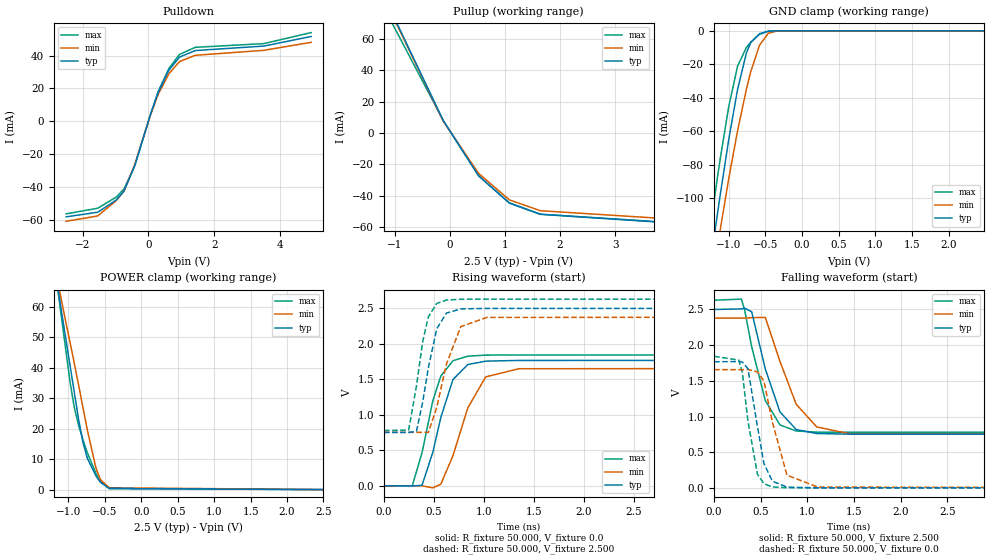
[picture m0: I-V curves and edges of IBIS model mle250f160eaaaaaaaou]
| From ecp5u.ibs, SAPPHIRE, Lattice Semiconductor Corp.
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|   Model mle250f160eaaaaaaaou
[Model] mle250f160eaaaaaaaou
Model_type  Output
Polarity   Non-Inverting
Enable   Active-Low
Vmeas =  1.250V
Cref =  3.000pF
Rref =  50.000
Vref =  1.250V
C_comp   5.000pF   4.000pF   5.500pF
[Temperature Range]   25.000   0.125k   -40.000
[Voltage Range]   2.500V   2.380V   2.630V
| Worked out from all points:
|   slope of the pulldown table from 0 to 0.375 V, typ, clamps not added: 17.5 ohm
|   slope of the pullup table from 0 to 0.375 V, typ, clamps not added: 18 ohm
|   GND clamp passes 1 mA (typ) near -0.54 V on its own axis
|   POWER clamp passes 1 mA (typ) near -0.49 V on its own axis
|   rising waveform, R_fixture 50.000, V_fixture 0.0: 20-80 % time 195ps typ, 236ps min, 181ps max; typ from 0 V to 1.77 V
|   rising waveform, R_fixture 50.000, V_fixture 2.500: 20-80 % time 136ps typ, 170ps min, 120ps max; typ from 0.752 V to 2.5 V
|   falling waveform, R_fixture 50.000, V_fixture 2.500: 20-80 % time 227ps typ, 280ps min, 208ps max; typ from 2.5 V to 0.752 V
|   falling waveform, R_fixture 50.000, V_fixture 0.0: 20-80 % time 122ps typ, 152ps min, 108ps max; typ from 1.77 V to 0 V
[Pulldown]
|Voltage   I(typ)   I(min)   I(max)
-2.5V     -58.2mA    -60.91mA   -56.39mA
-1.54V    -55.38mA   -57.65mA   -52.96mA
-980mV    -47.99mA   -48.34mA   -46.23mA
-740mV    -42.44mA   -42.44mA   -41.18mA
-420mV    -27.34mA   -26.64mA   -27.21mA
60mV      4.04mA     3.769mA    4.134mA
300mV     17.85mA    16.63mA    18.36mA
620mV     31.07mA    28.91mA    32.17mA
940mV     39.03mA    36.32mA    40.66mA
1.42V     43.07mA    40.18mA    45.04mA
3.5V      45.79mA    43.2mA     47.28mA
4.94V     51.63mA    48.08mA    54.02mA
[Pullup]
|Voltage   I(typ)   I(min)   I(max)
-2.44V    192.3mA    233mA      152.5mA
-2.04V    162mA      187.4mA    131.5mA
-1.56V    123.7mA    125.4mA    104.1mA
-1.4V     110.1mA    108.9mA    94.53mA
-1.24V    106.2mA    102.8mA    89.45mA
-1.16V    88.16mA    86.55mA    79.94mA
-1.08V    78.55mA    77.58mA    71.97mA
-120mV    7.839mA    7.396mA    7.763mA
520mV     -27.33mA   -25.76mA   -27.24mA
1.08V     -44.77mA   -42.65mA   -44.53mA
1.64V     -51.84mA   -49.54mA   -51.76mA
5V        -59.63mA   -57.03mA   -59.32mA
[GND_clamp]
|Voltage   I(typ)   I(min)   I(max)
-2.5V     -600.3mA   -576.2mA   -594.4mA
-1.24V    -136mA     -154.5mA   -113.9mA
-1.18V    -117.2mA   -136.7mA   -95.27mA
-1.12V    -99.04mA   -119.7mA   -77.45mA
-1V       -64.9mA    -88.21mA   -45.19mA
-880mV    -35.12mA   -59.82mA   -21.21mA
-760mV    -13.33mA   -35.03mA   -10mA
-700mV    -7.01mA    -24.46mA   -6.829mA
-580mV    -1.679mA   -8.593mA   -2.127mA
-460mV    -210.1uA   -1.441mA   -213.7uA
-340mV    -8.598uA   -109.2uA   -6.553uA
2.48V     0A         0A         0A
[POWER_clamp]
|Voltage   I(typ)   I(min)   I(max)
-2.48V    301.8mA    269mA      334.4mA
-1.16V    68.59mA    70.21mA    68.47mA
-1.1V     59.33mA    62.74mA    57.51mA
-980mV    41.18mA    48.59mA    35.82mA
-920mV    32.13mA    41.65mA    27.11mA
-860mV    23.04mA    34.34mA    21.08mA
-800mV    15.49mA    26.9mA     16.35mA
-740mV    10.29mA    19.52mA    12.1mA
-620mV    4.381mA    6.888mA    5.184mA
-560mV    2.412mA    3.25mA     2.719mA
-440mV    397.7uA    604uA      311uA
2.5V      0A         0A         0A
[Ramp]
| variable   typ   min   max
dV/dt_r 1.060/0.198n   0.994/0.239n   1.106/0.185n
dV/dt_f 1.049/0.228n   0.976/0.281n   1.111/0.209n
R_load = 50.000
[Rising Waveform]
R_fixture= 50.000
V_fixture= 0.0
V_fixture_min= 0.0
V_fixture_max= 0.0
|time   V(typ)   V(min)   V(max)
0s        0V         0V         0V
283ps     -2.887mV   -102.8uV   -1.84mV
381ps     6.271mV    -755.5uV   467.2mV
489ps     473.4mV    -29.7mV    1.199V
569ps     965mV      23.25mV    1.547V
690ps     1.497V     424.4mV    1.762V
838ps     1.708V     1.096V     1.826V
1.017ns   1.756V     1.534V     1.841V
1.348ns   1.766V     1.649V     1.843V
10ns      1.767V     1.657V     1.844V
[Rising Waveform]
R_fixture= 50.000
V_fixture= 2.500
V_fixture_min= 2.380
V_fixture_max= 2.630
|time   V(typ)   V(min)   V(max)
0s        751.8mV    752.6mV    778.5mV
247ps     751.2mV    752.6mV    784.6mV
325ps     766.2mV    752.3mV    1.407V
388ps     1.184V     751.9mV    2.036V
444ps     1.663V     751.2mV    2.38V
528ps     2.212V     1.104V     2.569V
624ps     2.433V     1.713V     2.617V
768ps     2.492V     2.242V     2.628V
1.027ns   2.499V     2.372V     2.63V
10ns      2.5V       2.38V      2.63V
[Falling Waveform]
R_fixture= 50.000
V_fixture= 2.500
V_fixture_min= 2.380
V_fixture_max= 2.630
|time   V(typ)   V(min)   V(max)
0s        2.5V       2.38V      2.63V
293ps     2.508V     2.38V      2.645V
327ps     2.518V     2.379V     2.497V
403ps     2.468V     2.385V     1.978V
549ps     1.666V     2.389V     1.224V
706ps     1.065V     1.773V     881.8mV
880ps     817.6mV    1.172V     797.3mV
1.101ns   761.3mV    852.9mV    781.1mV
1.445ns   752.8mV    760.7mV    778.6mV
10ns      751.8mV    752.6mV    778.5mV
[Falling Waveform]
R_fixture= 50.000
V_fixture= 0.0
V_fixture_min= 0.0
V_fixture_max= 0.0
|time   V(typ)   V(min)   V(max)
0s        1.767V     1.657V     1.844V
266ps     1.77V      1.657V     1.79V
303ps     1.763V     1.656V     1.612V
363ps     1.67V      1.66V      933.7mV
465ps     858.3mV    1.625V     190.1mV
534ps     341.2mV    1.498V     58.7mV
625ps     92.85mV    920.6mV    12.21mV
781ps     10.9mV     178.3mV    1.985mV
1.112ns   905.2uV    10.23mV    182.3uV
10ns      0V         0V         0V
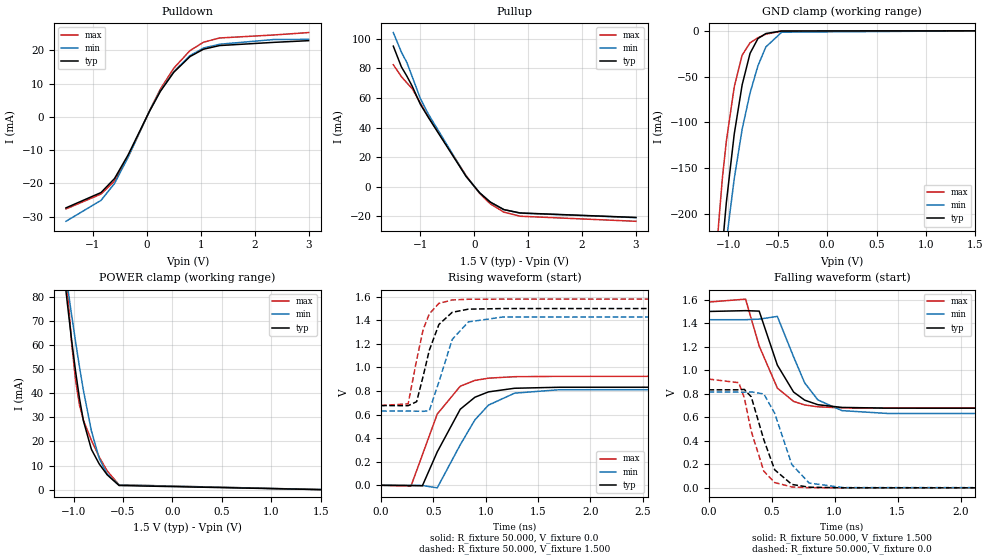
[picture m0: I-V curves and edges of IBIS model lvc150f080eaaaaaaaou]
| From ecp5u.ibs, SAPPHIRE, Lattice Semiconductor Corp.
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|   Model lvc150f080eaaaaaaaou
[Model] lvc150f080eaaaaaaaou
Model_type  Output
Polarity   Non-Inverting
Enable   Active-Low
Vmeas =  0.750V
Cref =  0.0F
Rref =  1.000M
Vref =  0.0V
C_comp   5.000pF   4.000pF   5.500pF
[Temperature Range]   25.000   0.125k   -40.000
[Voltage Range]   1.500V   1.430V   1.580V
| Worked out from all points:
|   slope of the pulldown table from 0 to 0.225 V, typ, clamps not added: 32.3 ohm
|   slope of the pullup table from 0 to 0.225 V, typ, clamps not added: 27.3 ohm
|   GND clamp passes 1 mA (typ) near -0.54 V on its own axis
|   POWER clamp passes 1 mA (typ) near -0.51 V on its own axis
|   rising waveform, R_fixture 50.000, V_fixture 0.0: 20-80 % time 294ps typ, 330ps min, 261ps max; typ from 0 V to 0.834 V
|   rising waveform, R_fixture 50.000, V_fixture 1.500: 20-80 % time 154ps typ, 172ps min, 132ps max; typ from 0.677 V to 1.5 V
|   falling waveform, R_fixture 50.000, V_fixture 1.500: 20-80 % time 196ps typ, 202ps min, 185ps max; typ from 1.5 V to 0.677 V
|   falling waveform, R_fixture 50.000, V_fixture 0.0: 20-80 % time 140ps typ, 161ps min, 128ps max; typ from 0.834 V to 0 V
[Pulldown]
|Voltage   I(typ)   I(min)   I(max)
-1.5V     -27.39mA   -31.43mA   -27.72mA
-850mV    -22.78mA   -25.14mA   -23.23mA
-600mV    -18.58mA   -20.07mA   -19.34mA
-350mV    -11.53mA   -12.21mA   -12.18mA
50mV      1.697mA    1.729mA    1.836mA
250mV     7.652mA    7.792mA    8.316mA
500mV     13.41mA    13.64mA    14.65mA
800mV     18.13mA    18.42mA    19.93mA
1.05V     20.35mA    20.7mA     22.46mA
1.35V     21.45mA    21.85mA    23.73mA
2.35V     22.41mA    23.26mA    24.63mA
3V        22.92mA    23.32mA    25.36mA
[Pullup]
|Voltage   I(typ)   I(min)   I(max)
-1.5V     95.03mA    104.2mA    82.46mA
-1.35V    81.02mA    90.95mA    74.41mA
-1.25V    74.86mA    84.06mA    70.27mA
-1.15V    68.02mA    74.48mA    66.36mA
-1V       55.88mA    59.73mA    56.56mA
-850mV    46.85mA    49.11mA    47.35mA
-150mV    6.997mA    7.036mA    7.57mA
100mV     -4.023mA   -3.974mA   -4.467mA
300mV     -10.39mA   -10.34mA   -11.52mA
550mV     -15.39mA   -15.45mA   -17.12mA
850mV     -17.67mA   -17.8mA    -19.88mA
3V        -20.72mA   -20.84mA   -23.31mA
[GND_clamp]
|Voltage   I(typ)   I(min)   I(max)
-1.5V     -960.1mA   -762.7mA   -1.034A
-1.14V    -347.3mA   -346mA     -275mA
-1.1V     -290.2mA   -305.8mA   -213.7mA
-1.06V    -236.5mA   -267.1mA   -161mA
-1.02V    -187.7mA   -229.9mA   -120.7mA
-940mV    -112.8mA   -161.5mA   -61.34mA
-860mV    -59.06mA   -107.5mA   -26.59mA
-780mV    -24.6mA    -67.97mA   -13.06mA
-700mV    -8.431mA   -38.1mA    -7.531mA
-620mV    -2.969mA   -17.61mA   -3.668mA
-460mV    -207.8uA   -1.521mA   -211uA
1.5V      0A         0A         0A
[POWER_clamp]
|Voltage   I(typ)   I(min)   I(max)
-1.5V     267.6mA    236.4mA    479.7mA
-1.1V     90.92mA    95.54mA    105.5mA
-1.06V    76.14mA    83.93mA    81.29mA
-1.02V    62.03mA    72.49mA    60.96mA
-980mV    49.07mA    61.38mA    45.36mA
-940mV    37.73mA    50.83mA    34.98mA
-900mV    28.44mA    41.02mA    28.75mA
-820mV    16.72mA    24.41mA    20.46mA
-740mV    10.6mA     12.83mA    13.51mA
-660mV    6.131mA    6.445mA    7.75mA
-540mV    1.697mA    1.964mA    1.966mA
1.5V      0A         0A         0A
[Ramp]
| variable   typ   min   max
dV/dt_r 0.500/0.299n   0.489/0.333n   0.555/0.259n
dV/dt_f 0.494/0.196n   0.480/0.207n   0.542/0.190n
R_load = 50.000
[Rising Waveform]
R_fixture= 50.000
V_fixture= 0.0
V_fixture_min= 0.0
V_fixture_max= 0.0
|time   V(typ)   V(min)   V(max)
0s        0V         0V         0V
285ps     -2.262mV   -324.6uV   -6.262mV
394ps     -3.981mV   -1.649mV   258.5mV
536ps     283.3mV    -21.77mV   604.4mV
756ps     645.5mV    343.7mV    840.8mV
896ps     747.3mV    555.2mV    890.1mV
1.026ns   792.9mV    680.5mV    909.2mV
1.276ns   823.6mV    782mV      921.7mV
1.706ns   832.2mV    811.2mV    924.6mV
10ns      833.6mV    814.4mV    925.1mV
[Rising Waveform]
R_fixture= 50.000
V_fixture= 1.500
V_fixture_min= 1.430
V_fixture_max= 1.580
|time   V(typ)   V(min)   V(max)
0s        676.8mV    630.1mV    677mV
258ps     675.7mV    630mV      691.4mV
339ps     709.7mV    629.3mV    1.063V
402ps     928.1mV    627.6mV    1.323V
460ps     1.146V     632.9mV    1.455V
552ps     1.365V     877.3mV    1.544V
679ps     1.468V     1.238V     1.573V
834ps     1.495V     1.387V     1.579V
1.161ns   1.5V       1.428V     1.58V
10ns      1.5V       1.43V      1.58V
[Falling Waveform]
R_fixture= 50.000
V_fixture= 1.500
V_fixture_min= 1.430
V_fixture_max= 1.580
|time   V(typ)   V(min)   V(max)
0s        1.5V       1.43V      1.58V
294ps     1.507V     1.43V      1.605V
402ps     1.503V     1.435V     1.206V
546ps     1.044V     1.458V     848.7mV
675ps     814.7mV    1.114V     735.2mV
763ps     745.9mV    892.4mV    704.9mV
868ps     707.1mV    747.5mV    689.2mV
1.059ns   684.1mV    656.7mV    680.3mV
1.422ns   677.9mV    632.7mV    677.8mV
10ns      676.8mV    630.1mV    677mV
[Falling Waveform]
R_fixture= 50.000
V_fixture= 0.0
V_fixture_min= 0.0
V_fixture_max= 0.0
|time   V(typ)   V(min)   V(max)
0s        833.6mV    814.4mV    925.1mV
240ps     833.9mV    814.5mV    894.4mV
284ps     837.4mV    813.9mV    765.1mV
339ps     774mV      816.1mV    481.6mV
439ps     408.2mV    798.5mV    141.1mV
525ps     153.6mV    634.2mV    44.85mV
661ps     29.16mV    198.4mV    7.55mV
799ps     5.488mV    40.56mV    1.444mV
1.069ns   486.4uV    2.263mV    88.69uV
10ns      0V         539.2nV    0V
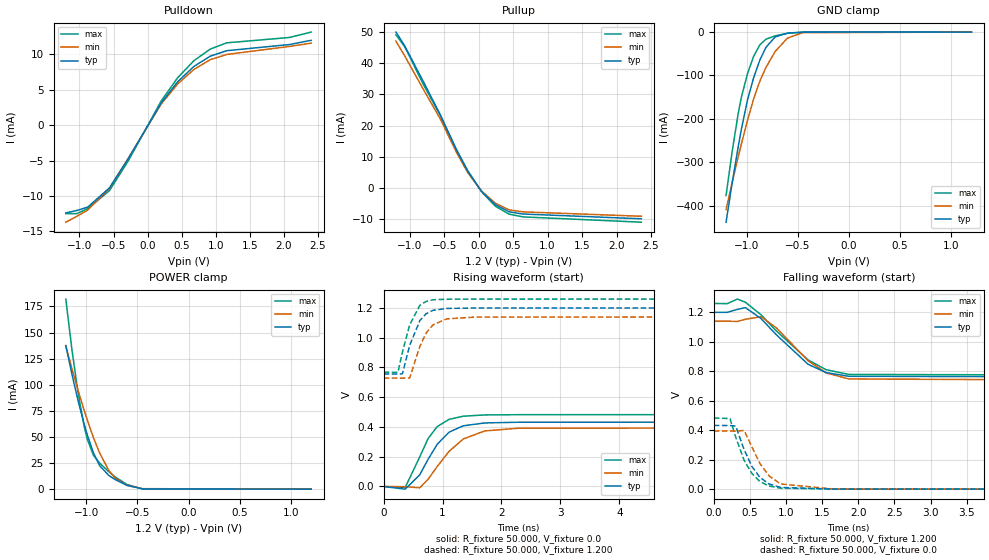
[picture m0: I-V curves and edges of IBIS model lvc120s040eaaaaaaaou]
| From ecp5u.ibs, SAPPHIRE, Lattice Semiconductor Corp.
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|   Model lvc120s040eaaaaaaaou
[Model] lvc120s040eaaaaaaaou
Model_type  Output
Polarity   Non-Inverting
Enable   Active-Low
Vmeas =  0.600V
Cref =  0.0F
Rref =  1.000M
Vref =  0.0V
C_comp   5.000pF   4.000pF   5.500pF
[Temperature Range]   25.000   0.125k   -40.000
[Voltage Range]   1.200V   1.140V   1.260V
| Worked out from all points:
|   slope of the pulldown table from 0 to 0.18 V, typ, clamps not added: 62.6 ohm
|   slope of the pullup table from 0 to 0.18 V, typ, clamps not added: 41.4 ohm
|   GND clamp passes 1 mA (typ) near -0.54 V on its own axis
|   POWER clamp passes 1 mA (typ) near -0.51 V on its own axis
|   rising waveform, R_fixture 50.000, V_fixture 0.0: 20-80 % time 425ps typ, 526ps min, 357ps max; typ from 0 V to 0.433 V
|   rising waveform, R_fixture 50.000, V_fixture 1.200: 20-80 % time 234ps typ, 257ps min, 217ps max; typ from 0.757 V to 1.2 V
|   falling waveform, R_fixture 50.000, V_fixture 1.200: 20-80 % time 563ps typ, 527ps min, 637ps max; typ from 1.2 V to 0.757 V
|   falling waveform, R_fixture 50.000, V_fixture 0.0: 20-80 % time 262ps typ, 284ps min, 260ps max; typ from 0.433 V to 0 V
[Pulldown]
|Voltage   I(typ)   I(min)   I(max)
-1.2V     -12.39mA   -13.7mA    -12.49mA
-1.04V    -12.05mA   -12.88mA   -12.49mA
-880mV    -11.58mA   -12mA      -11.79mA
-560mV    -8.851mA   -8.925mA   -9.245mA
-280mV    -4.688mA   -4.607mA   -4.974mA
200mV     3.164mA    3.008mA    3.437mA
440mV     6.136mA    5.828mA    6.7mA
680mV     8.315mA    7.89mA     9.126mA
920mV     9.761mA    9.262mA    10.76mA
1.16V     10.53mA    9.999mA    11.64mA
2.08V     11.4mA     11.13mA    12.4mA
2.4V      12mA       11.6mA     13.16mA
[Pullup]
|Voltage   I(typ)   I(min)   I(max)
-1.2V     50.07mA    47.17mA    49.17mA
-1.08V    45.93mA    42.72mA    45.61mA
-1.04V    44.24mA    41.1mA     43.95mA
-800mV    34.04mA    31.57mA    33.14mA
-560mV    23.66mA    22.29mA    23.4mA
-320mV    12.02mA    11.33mA    12.22mA
-160mV    5.347mA    4.94mA     5.595mA
40mV      -1.121mA   -1.009mA   -1.216mA
240mV     -5.438mA   -4.944mA   -5.91mA
440mV     -7.728mA   -7.089mA   -8.472mA
640mV     -8.434mA   -7.743mA   -9.364mA
2.36V     -9.976mA   -9.166mA   -11.07mA
[GND_clamp]
|Voltage   I(typ)   I(min)   I(max)
-1.2V     -438mA     -409mA     -376.5mA
-1.14V    -347.3mA   -346mA     -274.9mA
-1.08V    -262.9mA   -286.2mA   -185.9mA
-1.05V    -223.7mA   -257.6mA   -150mA
-990mV    -156.1mA   -203.2mA   -95.66mA
-930mV    -105mA     -153.7mA   -55.58mA
-870mV    -64.74mA   -113.2mA   -29.56mA
-810mV    -35.2mA    -81.56mA   -16.45mA
-720mV    -11.09mA   -44.69mA   -8.691mA
-600mV    -2.287mA   -13.94mA   -2.904mA
-450mV    -166.2uA   -1.247mA   -164.1uA
1.2V      0A         0A         0A
[POWER_clamp]
|Voltage   I(typ)   I(min)   I(max)
-1.2V     137.6mA    137.3mA    182.1mA
-1.14V    110.1mA    115.3mA    133.6mA
-1.08V    84.76mA    94.63mA    92.15mA
-1.02V    62.11mA    75.36mA    59.94mA
-990mV    52mA       66.3mA     47.89mA
-930mV    34.81mA    49.51mA    32.55mA
-870mV    22.62mA    34.86mA    25.07mA
-780mV    13.14mA    18.01mA    16.74mA
-720mV    9.284mA    10.72mA    11.88mA
-600mV    3.553mA    3.709mA    4.373mA
-450mV    294.8uA    471.6uA    256.4uA
1.2V      0A         0A         0A
[Ramp]
| variable   typ   min   max
dV/dt_r   0.260/0.432n   0.237/0.528n   0.290/0.362n
dV/dt_f   0.266/0.571n   0.247/0.546n   0.295/0.640n
R_load = 50.000
[Rising Waveform]
R_fixture= 50.000
V_fixture= 0.0
V_fixture_min= 0.0
V_fixture_max= 0.0
|time   V(typ)   V(min)   V(max)
0s        0V         0V         0V
366ps     -17.93mV   -1.319mV   -5.917mV
611ps     77.71mV    -8.803mV   197.7mV
755ps     183.4mV    48.86mV    322.7mV
910ps     284.2mV    134.9mV    403mV
1.111ns   365.4mV    236.4mV    451.4mV
1.351ns   408mV      319.3mV    472.6mV
1.716ns   427.3mV    373.5mV    481mV
2.291ns   432mV      391.8mV    482.8mV
10ns      432.5mV    394.5mV    482.9mV
[Rising Waveform]
R_fixture= 50.000
V_fixture= 1.200
V_fixture_min= 1.140
V_fixture_max= 1.260
|time   V(typ)   V(min)   V(max)
0s        757.1mV    728.8mV    768.8mV
242ps     755.8mV    728.8mV    767.1mV
319ps     757.8mV    727.9mV    903.9mV
441ps     948mV      728.7mV    1.086V
615ps     1.116V     942.7mV    1.218V
720ps     1.161V     1.031V     1.244V
834ps     1.184V     1.086V     1.255V
1.07ns    1.197V     1.127V     1.259V
1.56ns    1.2V       1.139V     1.26V
10ns      1.2V       1.14V      1.26V
[Falling Waveform]
R_fixture= 50.000
V_fixture= 1.200
V_fixture_min= 1.140
V_fixture_max= 1.260
|time   V(typ)   V(min)   V(max)
0s        1.2V       1.14V      1.26V
186ps     1.2V       1.14V      1.259V
327ps     1.22V      1.138V     1.29V
439ps     1.232V     1.153V     1.268V
655ps     1.157V     1.17V      1.183V
865ps     1.048V     1.095V     1.074V
1.305ns   847.5mV    871.4mV    877mV
1.555ns   791.1mV    789.2mV    810.6mV
1.868ns   766mV      748mV      778.6mV
10ns      757.1mV    728.8mV    768.8mV
[Falling Waveform]
R_fixture= 50.000
V_fixture= 0.0
V_fixture_min= 0.0
V_fixture_max= 0.0
|time   V(typ)   V(min)   V(max)
0s        432.5mV    394.5mV    482.9mV
224ps     431.8mV    394.5mV    479.2mV
303ps     428.2mV    393.5mV    353.3mV
420ps     268.6mV    398.8mV    195.5mV
527ps     154.4mV    287.6mV    107mV
638ps     80.25mV    174.4mV    52.17mV
765ps     34.94mV    90.16mV    21.13mV
925ps     11.59mV    35.03mV    6.657mV
1.657ns   452.3uV    977.8uV    537.2uV
10ns      0V         0V         0V
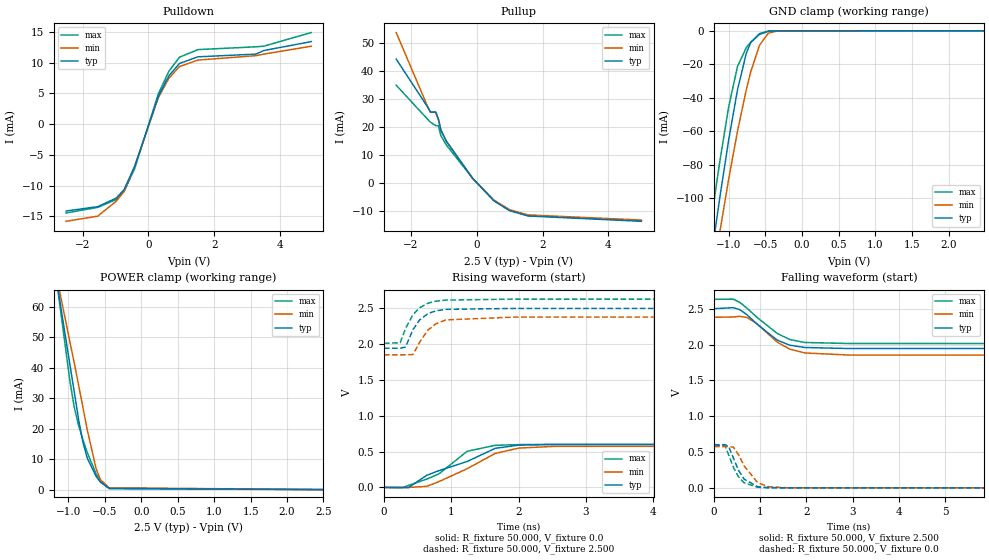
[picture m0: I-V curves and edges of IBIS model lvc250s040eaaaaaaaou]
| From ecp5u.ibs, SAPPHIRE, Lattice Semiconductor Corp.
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|   Model lvc250s040eaaaaaaaou
[Model] lvc250s040eaaaaaaaou
Model_type  Output
Polarity   Non-Inverting
Enable   Active-Low
Vmeas =  1.250V
Cref =  0.0F
Rref =  1.000M
Vref =  0.0V
C_comp   5.000pF   4.000pF   5.500pF
[Temperature Range]   25.000   0.125k   -40.000
[Voltage Range]   2.500V   2.380V   2.630V
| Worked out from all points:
|   slope of the pulldown table from 0 to 0.375 V, typ, clamps not added: 69.2 ohm
|   slope of the pullup table from 0 to 0.375 V, typ, clamps not added: 79.2 ohm
|   GND clamp passes 1 mA (typ) near -0.54 V on its own axis
|   POWER clamp passes 1 mA (typ) near -0.49 V on its own axis
|   rising waveform, R_fixture 50.000, V_fixture 0.0: 20-80 % time 913ps typ, 706ps min, 535ps max; typ from 0 V to 0.602 V
|   rising waveform, R_fixture 50.000, V_fixture 2.500: 20-80 % time 227ps typ, 257ps min, 239ps max; typ from 1.94 V to 2.5 V
|   falling waveform, R_fixture 50.000, V_fixture 2.500: 20-80 % time 625ps typ, 602ps min, 699ps max; typ from 2.5 V to 1.94 V
|   falling waveform, R_fixture 50.000, V_fixture 0.0: 20-80 % time 269ps typ, 331ps min, 263ps max; typ from 0.602 V to 0 V
[Pulldown]
|Voltage   I(typ)   I(min)   I(max)
-2.5V     -14.12mA   -15.79mA   -14.44mA
-1.54V    -13.41mA   -14.95mA   -13.53mA
-980mV    -12.03mA   -12.53mA   -12.26mA
-740mV    -10.64mA   -10.95mA   -10.92mA
-420mV    -6.892mA   -6.861mA   -7.26mA
300mV     4.505mA    4.281mA    4.905mA
620mV     7.84mA     7.441mA    8.594mA
940mV     9.849mA    9.346mA    10.86mA
1.5V      10.93mA    10.4mA     12.1mA
3.26V     11.37mA    11.12mA    12.56mA
3.5V      11.95mA    11.37mA    12.66mA
4.94V     13.4mA     12.65mA    14.87mA
[Pullup]
|Voltage   I(typ)   I(min)   I(max)
-2.44V    44.19mA    53.62mA    34.87mA
-1.48V    27mA       27.11mA    22.71mA
-1.4V     25.36mA    25.26mA    21.73mA
-1.24V    25.36mA    25.26mA    20.52mA
-1.16V    22.88mA    22.7mA     20.52mA
-1.08V    18.79mA    18.9mA     16.81mA
-920mV    14.91mA    15.07mA    13.66mA
-120mV    1.78mA     1.699mA    1.74mA
520mV     -6.204mA   -5.916mA   -6.107mA
1V        -9.754mA   -9.39mA    -9.578mA
1.56V     -11.64mA   -11.26mA   -11.47mA
5V        -13.53mA   -13.09mA   -13.29mA
[GND_clamp]
|Voltage   I(typ)   I(min)   I(max)
-2.5V     -600.3mA   -576.2mA   -594.4mA
-1.24V    -136mA     -154.5mA   -113.9mA
-1.18V    -117.2mA   -136.7mA   -95.27mA
-1.12V    -99.04mA   -119.7mA   -77.45mA
-1V       -64.9mA    -88.21mA   -45.19mA
-880mV    -35.12mA   -59.82mA   -21.21mA
-760mV    -13.33mA   -35.03mA   -10mA
-700mV    -7.01mA    -24.46mA   -6.829mA
-580mV    -1.679mA   -8.593mA   -2.127mA
-460mV    -210.1uA   -1.441mA   -213.7uA
-340mV    -8.598uA   -109.2uA   -6.553uA
2.48V     0A         0A         0A
[POWER_clamp]
|Voltage   I(typ)   I(min)   I(max)
-2.48V    301.8mA    269mA      334.4mA
-1.16V    68.59mA    70.21mA    68.47mA
-1.1V     59.33mA    62.74mA    57.51mA
-980mV    41.18mA    48.59mA    35.82mA
-920mV    32.13mA    41.65mA    27.11mA
-860mV    23.04mA    34.34mA    21.08mA
-800mV    15.49mA    26.9mA     16.35mA
-740mV    10.29mA    19.52mA    12.1mA
-620mV    4.381mA    6.888mA    5.184mA
-560mV    2.412mA    3.25mA     2.719mA
-440mV    397.7uA    604uA      311uA
2.5V      0A         0A         0A
[Ramp]
| variable   typ   min   max
dV/dt_r   0.362/0.911n   0.347/0.712n   0.361/0.539n
dV/dt_f   0.334/0.632n   0.317/0.609n   0.370/0.706n
R_load = 50.000
[Rising Waveform]
R_fixture= 50.000
V_fixture= 0.0
V_fixture_min= 0.0
V_fixture_max= 0.0
|time   V(typ)   V(min)   V(max)
0s        0V         0V         0V
271ps     -1.029mV   -55.49uV   -6.273mV
362ps     -3.943mV   -393.5uV   27.16mV
636ps     169.2mV    14.46mV    115.8mV
816ps     233.7mV    80.79mV    188mV
1.236ns   361.8mV    260.6mV    504.3mV
1.653ns   545.7mV    474.4mV    587.9mV
2.004ns   591mV      549.4mV    598mV
2.535ns   601.1mV    573.5mV    600mV
10ns      602mV      576.6mV    600.1mV
[Rising Waveform]
R_fixture= 50.000
V_fixture= 2.500
V_fixture_min= 2.380
V_fixture_max= 2.630
|time   V(typ)   V(min)   V(max)
0s        1.944V     1.852V     2.013V
241ps     1.944V     1.852V     2.021V
321ps     1.962V     1.852V     2.221V
431ps     2.204V     1.857V     2.413V
531ps     2.34V      2.03V      2.51V
652ps     2.427V     2.196V     2.572V
773ps     2.467V     2.286V     2.602V
922ps     2.487V     2.34V      2.617V
1.935ns   2.5V       2.379V     2.63V
10ns      2.5V       2.38V      2.63V
[Falling Waveform]
R_fixture= 50.000
V_fixture= 2.500
V_fixture_min= 2.380
V_fixture_max= 2.630
|time   V(typ)   V(min)   V(max)
0s        2.5V       2.38V      2.63V
415ps     2.514V     2.384V     2.633V
558ps     2.486V     2.393V     2.587V
716ps     2.413V     2.376V     2.505V
936ps     2.281V     2.286V     2.375V
1.366ns   2.062V     2.034V     2.155V
1.635ns   1.991V     1.936V     2.07V
1.966ns   1.958V     1.882V     2.028V
2.92ns    1.944V     1.853V     2.014V
10ns      1.944V     1.852V     2.013V
[Falling Waveform]
R_fixture= 50.000
V_fixture= 0.0
V_fixture_min= 0.0
V_fixture_max= 0.0
|time   V(typ)   V(min)   V(max)
0s        602mV      576.6mV    600.1mV
236ps     603.1mV    576.6mV    584.7mV
318ps     575mV      577.7mV    458.8mV
421ps     412.6mV    567mV      281.9mV
531ps     243mV      460.5mV    152.9mV
650ps     121.5mV    306.5mV    70.73mV
946ps     15.75mV    71.28mV    8.067mV
1.17ns    3.538mV    16.98mV    1.92mV
1.585ns   615.3uV    1.893mV    627.4uV
10ns      0V         0V         0V
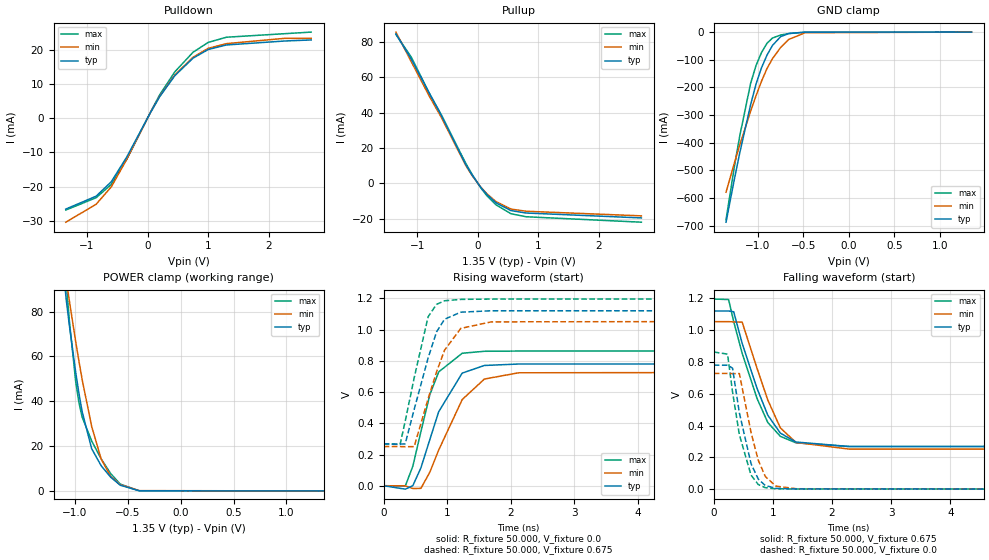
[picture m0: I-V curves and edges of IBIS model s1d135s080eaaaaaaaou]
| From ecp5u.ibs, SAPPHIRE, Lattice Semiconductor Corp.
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|   Model s1d135s080eaaaaaaaou
[Model] s1d135s080eaaaaaaaou
Model_type  Output
Polarity   Non-Inverting
Enable   Active-Low
Vmeas =  0.675V
Cref =  30.000pF
Rref =  50.000
Vref =  0.675V
C_comp   5.000pF   4.000pF   5.500pF
[Temperature Range]   25.000   0.125k   -40.000
[Voltage Range]   1.350V   1.280V   1.420V
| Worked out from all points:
|   slope of the pulldown table from 0 to 0.203 V, typ, clamps not added: 31.9 ohm
|   slope of the pullup table from 0 to 0.203 V, typ, clamps not added: 25 ohm
|   GND clamp passes 1 mA (typ) near -0.54 V on its own axis
|   POWER clamp passes 1 mA (typ) near -0.51 V on its own axis
|   rising waveform, R_fixture 50.000, V_fixture 0.0: 20-80 % time 409ps typ, 504ps min, 331ps max; typ from 0 V to 0.78 V
|   rising waveform, R_fixture 50.000, V_fixture 0.675: 20-80 % time 352ps typ, 392ps min, 284ps max; typ from 0.268 V to 1.12 V
|   falling waveform, R_fixture 50.000, V_fixture 0.675: 20-80 % time 496ps typ, 470ps min, 499ps max; typ from 1.12 V to 0.268 V
|   falling waveform, R_fixture 50.000, V_fixture 0.0: 20-80 % time 259ps typ, 267ps min, 253ps max; typ from 0.78 V to 0 V
[Pulldown]
|Voltage   I(typ)   I(min)   I(max)
-1.35V    -26.53mA   -30.36mA   -26.81mA
-850mV    -22.78mA   -25.14mA   -23.23mA
-600mV    -18.58mA   -20.07mA   -19.34mA
-350mV    -11.53mA   -12.21mA   -12.18mA
50mV      1.697mA    1.729mA    1.836mA
200mV     6.283mA    6.399mA    6.82mA
450mV     12.4mA     12.61mA    13.53mA
750mV     17.5mA     17.78mA    19.22mA
1V        20.02mA    20.36mA    22.09mA
1.3V      21.34mA    21.73mA    23.6mA
2.25V     22.49mA    23.26mA    24.62mA
2.7V      22.81mA    23.26mA    25.1mA
[Pullup]
|Voltage   I(typ)   I(min)   I(max)
-1.35V    84.54mA    85.56mA    84.2mA
-1.1V     70.51mA    69.04mA    71.6mA
-800mV    51.07mA    49.36mA    51mA
-600mV    38.33mA    37.29mA    38.78mA
-200mV    10.78mA    10.31mA    11.47mA
-100mV    5.067mA    4.773mA    5.489mA
50mV      -2.275mA   -2.112mA   -2.515mA
150mV     -6.276mA   -5.848mA   -6.932mA
300mV     -10.95mA   -10.26mA   -12.1mA
550mV     -15.42mA   -14.55mA   -17.18mA
800mV     -16.76mA   -15.77mA   -18.88mA
2.7V      -19.53mA   -18.37mA   -21.95mA
[GND_clamp]
|Voltage   I(typ)   I(min)   I(max)
-1.35V    -687.3mA   -578.9mA   -678.1mA
-1.26V    -534.3mA   -475.1mA   -489.7mA
-1.2V     -438.1mA   -409.1mA   -376.7mA
-1.08V    -262.9mA   -286.2mA   -185.9mA
-1.02V    -187.7mA   -229.9mA   -120.7mA
-960mV    -129.1mA   -177.6mA   -73.95mA
-900mV    -83.6mA    -132.1mA   -40.76mA
-840mV    -48.57mA   -96.56mA   -21.66mA
-750mV    -16.65mA   -55.68mA   -10.64mA
-660mV    -4.958mA   -26.68mA   -5.448mA
-480mV    -317.7uA   -2.229mA   -341.9uA
1.35V     0A         0A         0A
[POWER_clamp]
|Voltage   I(typ)   I(min)   I(max)
-1.35V    211.5mA    193mA      324.9mA
-1.08V    85.33mA    94.25mA    92.93mA
-1.05V    73.76mA    84.65mA    75.65mA
-990mV    52.73mA    66.45mA    48.6mA
-960mV    43.53mA    57.9mA     39.38mA
-930mV    35.42mA    49.79mA    33mA
-840mV    18.88mA    28.82mA    22.31mA
-750mV    11.24mA    14.22mA    14.3mA
-660mV    6.13mA     6.499mA    7.742mA
-570mV    2.538mA    2.795mA    3.049mA
-390mV    57.41uA    134.8uA    35.81uA
1.35V     0A         0A         0A
[Ramp]
| variable   typ   min   max
dV/dt_r 0.468/0.414n   0.437/0.507n   0.518/0.332n
dV/dt_f 0.454/0.511n   0.438/0.461n   0.496/0.548n
R_load = 50.000
[Rising Waveform]
R_fixture= 50.000
V_fixture= 0.0
V_fixture_min= 0.0
V_fixture_max= 0.0
|time   V(typ)   V(min)   V(max)
0s        0V         0V         0V
342ps     -22.05mV   -1.057mV   -888.7uV
460ps     651.2uV    -17.76mV   125.3mV
587ps     114.6mV    -17.05mV   346.6mV
728ps     296.1mV    87mV       583.3mV
867ps     474mV      228.4mV    729.2mV
1.238ns   721.7mV    552.2mV    848.9mV
1.587ns   770.5mV    683.5mV    861.4mV
2.127ns   779.8mV    723.6mV    862.9mV
10ns      780.5mV    728.2mV    862.9mV
[Rising Waveform]
R_fixture= 50.000
V_fixture= 0.675
V_fixture_min= 0.642
V_fixture_max= 0.710
|time   V(typ)   V(min)   V(max)
0s        268.3mV    251mV      268.1mV
259ps     266.8mV    250.9mV    264.2mV
339ps     268.1mV    249.9mV    411.6mV
481ps     488.7mV    250.5mV    691mV
700ps     817.5mV    556.9mV    1.082V
833ps     985.1mV    729.1mV    1.162V
960ps     1.067V     868.9mV    1.185V
1.216ns   1.112V     1.008V     1.194V
1.696ns   1.121V     1.05V      1.196V
10ns      1.121V     1.054V     1.196V
[Falling Waveform]
R_fixture= 50.000
V_fixture= 0.675
V_fixture_min= 0.642
V_fixture_max= 0.710
|time   V(typ)   V(min)   V(max)
0s        1.121V     1.054V     1.196V
251ps     1.121V     1.054V     1.193V
337ps     1.116V     1.052V     1.054V
480ps     917.3mV    1.051V     855.1mV
732ps     633.8mV    759.8mV    570.4mV
913ps     465.7mV    561.4mV    419.7mV
1.126ns   352.5mV    385.5mV    332.4mV
1.39ns    296.6mV    293.9mV    291.4mV
2.283ns   268.7mV    252.3mV    268.3mV
10ns      268.3mV    251mV      268.1mV
[Falling Waveform]
R_fixture= 50.000
V_fixture= 0.0
V_fixture_min= 0.0
V_fixture_max= 0.0
|time   V(typ)   V(min)   V(max)
0s        780.5mV    728.2mV    862.9mV
233ps     780mV      728.2mV    849.8mV
317ps     761.7mV    727mV      613mV
433ps     479.4mV    727.4mV    341.9mV
630ps     160.3mV    356.3mV    88.64mV
753ps     63.44mV    181.5mV    29.03mV
870ps     23.29mV    80.49mV    9.533mV
1.05ns    5.326mV    19.17mV    2.482mV
1.4ns     1.406mV    2.612mV    1.076mV
10ns      0V         0V         0V
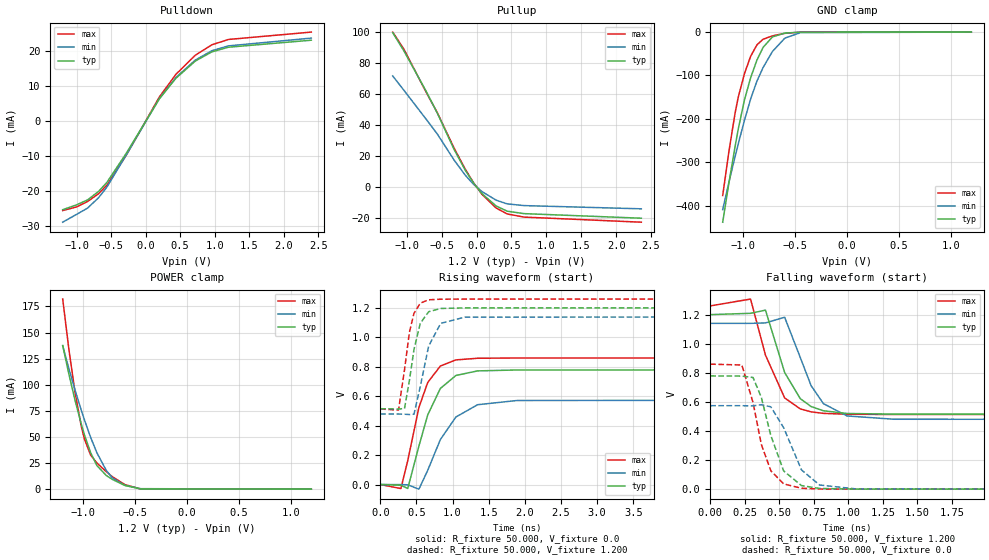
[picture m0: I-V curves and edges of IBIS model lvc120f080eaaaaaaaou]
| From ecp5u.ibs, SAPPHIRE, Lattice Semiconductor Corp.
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|   Model lvc120f080eaaaaaaaou
[Model] lvc120f080eaaaaaaaou
Model_type  Output
Polarity   Non-Inverting
Enable   Active-Low
Vmeas =  0.600V
Cref =  0.0F
Rref =  1.000M
Vref =  0.0V
C_comp   5.000pF   4.000pF   5.500pF
[Temperature Range]   25.000   0.125k   -40.000
[Voltage Range]   1.200V   1.140V   1.260V
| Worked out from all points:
|   slope of the pulldown table from 0 to 0.18 V, typ, clamps not added: 31.5 ohm
|   slope of the pullup table from 0 to 0.18 V, typ, clamps not added: 20.5 ohm
|   GND clamp passes 1 mA (typ) near -0.54 V on its own axis
|   POWER clamp passes 1 mA (typ) near -0.51 V on its own axis
|   rising waveform, R_fixture 50.000, V_fixture 0.0: 20-80 % time 307ps typ, 377ps min, 267ps max; typ from 0 V to 0.779 V
|   rising waveform, R_fixture 50.000, V_fixture 1.200: 20-80 % time 143ps typ, 183ps min, 127ps max; typ from 0.515 V to 1.2 V
|   falling waveform, R_fixture 50.000, V_fixture 1.200: 20-80 % time 170ps typ, 179ps min, 158ps max; typ from 1.2 V to 0.515 V
|   falling waveform, R_fixture 50.000, V_fixture 0.0: 20-80 % time 141ps typ, 161ps min, 125ps max; typ from 0.779 V to 0 V
[Pulldown]
|Voltage   I(typ)   I(min)   I(max)
-1.2V     -25.46mA   -29.03mA   -25.7mA
-1V       -24.07mA   -26.8mA    -24.67mA
-840mV    -22.66mA   -25mA      -23.11mA
-680mV    -20.21mA   -22.01mA   -20.87mA
-560mV    -17.64mA   -18.97mA   -18.42mA
-280mV    -9.315mA   -9.799mA   -9.876mA
200mV     6.283mA    6.399mA    6.82mA
440mV     12.18mA    12.4mA     13.3mA
720mV     17.09mA    17.37mA    18.76mA
960mV     19.72mA    20.05mA    21.74mA
1.2V      21.05mA    21.43mA    23.27mA
2.4V      23.06mA    23.66mA    25.38mA
[Pullup]
|Voltage   I(typ)   I(min)   I(max)
-1.2V     99.72mA    71.78mA    100.1mA
-1.04V    87.98mA    62.54mA    89.1mA
-720mV    61.79mA    43.77mA    61.16mA
-560mV    47.66mA    34.19mA    47.95mA
-320mV    24.22mA    17.38mA    25.05mA
-160mV    10.78mA    7.577mA    11.47mA
-40mV     2.437mA    1.679mA    2.663mA
80mV      -4.343mA   -2.98mA    -4.792mA
280mV     -12.2mA    -8.456mA   -13.5mA
440mV     -15.58mA   -10.87mA   -17.37mA
680mV     -17.16mA   -11.97mA   -19.4mA
2.36V     -20.12mA   -14.05mA   -22.69mA
[GND_clamp]
|Voltage   I(typ)   I(min)   I(max)
-1.2V     -438mA     -409mA     -376.5mA
-1.14V    -347.3mA   -346mA     -274.9mA
-1.08V    -262.9mA   -286.2mA   -185.9mA
-1.05V    -223.7mA   -257.6mA   -150mA
-990mV    -156.1mA   -203.2mA   -95.66mA
-930mV    -105mA     -153.7mA   -55.58mA
-870mV    -64.74mA   -113.2mA   -29.56mA
-810mV    -35.2mA    -81.56mA   -16.45mA
-720mV    -11.09mA   -44.69mA   -8.691mA
-600mV    -2.287mA   -13.94mA   -2.904mA
-450mV    -166.2uA   -1.247mA   -164.1uA
1.2V      0A         0A         0A
[POWER_clamp]
|Voltage   I(typ)   I(min)   I(max)
-1.2V     137.6mA    137.3mA    182.1mA
-1.14V    110.1mA    115.3mA    133.6mA
-1.08V    84.76mA    94.63mA    92.15mA
-1.02V    62.11mA    75.36mA    59.94mA
-990mV    52mA       66.3mA     47.89mA
-930mV    34.81mA    49.51mA    32.55mA
-870mV    22.62mA    34.86mA    25.07mA
-780mV    13.14mA    18.01mA    16.74mA
-720mV    9.284mA    10.72mA    11.88mA
-600mV    3.553mA    3.709mA    4.373mA
-450mV    294.8uA    471.6uA    256.4uA
1.2V      0A         0A         0A
[Ramp]
| variable   typ   min   max
dV/dt_r   0.463/0.309n   0.349/0.378n   0.507/0.269n
dV/dt_f   0.411/0.174n   0.397/0.185n   0.448/0.159n
R_load = 50.000
[Rising Waveform]
R_fixture= 50.000
V_fixture= 0.0
V_fixture_min= 0.0
V_fixture_max= 0.0
|time   V(typ)   V(min)   V(max)
0s        0V         0V         0V
285ps     -4.963mV   -508.9uV   -27.54mV
380ps     -26.96mV   -2.037mV   162.6mV
534ps     260.3mV    -31.62mV   523.2mV
656ps     472.8mV    96.28mV    693mV
831ps     652.8mV    305.6mV    805.1mV
1.046ns   740.8mV    458.8mV    846.7mV
1.346ns   772mV      542.2mV    857.8mV
1.891ns   778.2mV    570.8mV    859.6mV
10ns      778.7mV    573.9mV    859.6mV
[Rising Waveform]
R_fixture= 50.000
V_fixture= 1.200
V_fixture_min= 1.140
V_fixture_max= 1.260
|time   V(typ)   V(min)   V(max)
0s        515.1mV    479.1mV    513.2mV
252ps     512.9mV    479mV      505.7mV
335ps     516.3mV    477.7mV    778.5mV
403ps     707.1mV    475.4mV    1.035V
466ps     917.3mV    477.9mV    1.163V
553ps     1.095V     665.7mV    1.232V
669ps     1.174V     940.6mV    1.255V
836ps     1.196V     1.095V     1.259V
1.167ns   1.2V       1.137V     1.26V
10ns      1.2V       1.14V      1.26V
[Falling Waveform]
R_fixture= 50.000
V_fixture= 1.200
V_fixture_min= 1.140
V_fixture_max= 1.260
|time   V(typ)   V(min)   V(max)
0s        1.2V       1.14V      1.26V
292ps     1.209V     1.14V      1.307V
400ps     1.231V     1.143V     921.6mV
539ps     802.3mV    1.182V     627.5mV
652ps     622.5mV    905.8mV    552mV
731ps     568mV      711.3mV    531.5mV
820ps     538.9mV    588mV      521.2mV
991ps     520.4mV    503.4mV    515.1mV
1.331ns   515.5mV    480.7mV    513.4mV
10ns      515.1mV    479.1mV    513.2mV
[Falling Waveform]
R_fixture= 50.000
V_fixture= 0.0
V_fixture_min= 0.0
V_fixture_max= 0.0
|time   V(typ)   V(min)   V(max)
0s        778.7mV    573.9mV    859.6mV
229ps     777.4mV    573.9mV    853.6mV
310ps     767.8mV    572.6mV    595.2mV
370ps     631.5mV    580.8mV    307.8mV
439ps     368.2mV    566.2mV    126.3mV
532ps     125.1mV    422.2mV    35.94mV
661ps     24.73mV    132.5mV    6.371mV
792ps     4.872mV    28.67mV    1.15mV
1.059ns   241.6uV    1.403mV    45.71uV
10ns      0V         0V         0V
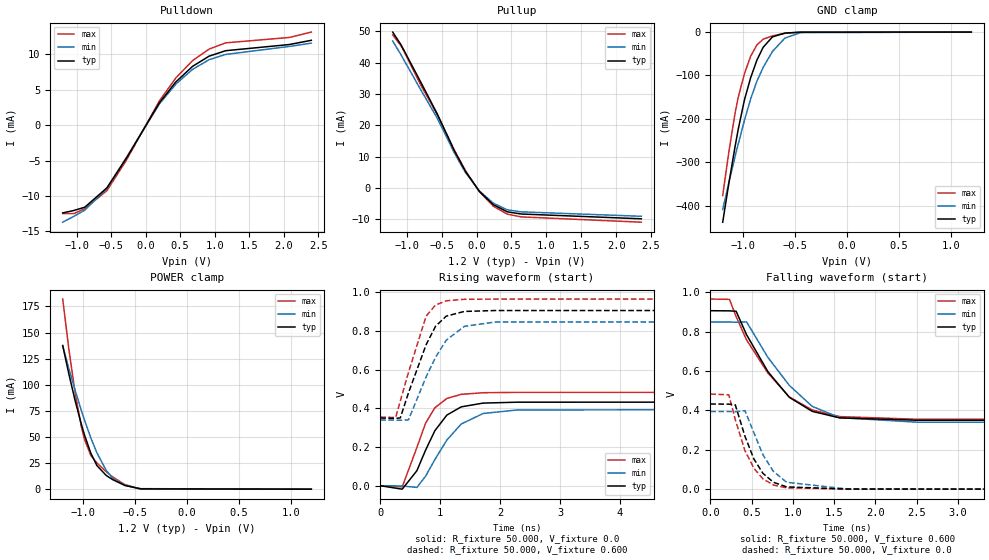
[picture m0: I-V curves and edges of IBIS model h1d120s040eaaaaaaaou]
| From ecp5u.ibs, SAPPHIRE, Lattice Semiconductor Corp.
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|   Model h1d120s040eaaaaaaaou
[Model] h1d120s040eaaaaaaaou
Model_type  Output
Polarity   Non-Inverting
Enable   Active-Low
Vmeas =  0.600V
Cref =  20.000pF
Rref =  50.000
Vref =  0.600V
C_comp   5.000pF   4.000pF   5.500pF
[Temperature Range]   25.000   0.125k   -40.000
[Voltage Range]   1.200V   1.140V   1.260V
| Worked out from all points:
|   slope of the pulldown table from 0 to 0.18 V, typ, clamps not added: 62.6 ohm
|   slope of the pullup table from 0 to 0.18 V, typ, clamps not added: 41.6 ohm
|   GND clamp passes 1 mA (typ) near -0.54 V on its own axis
|   POWER clamp passes 1 mA (typ) near -0.51 V on its own axis
|   rising waveform, R_fixture 50.000, V_fixture 0.0: 20-80 % time 425ps typ, 526ps min, 357ps max; typ from 0 V to 0.433 V
|   rising waveform, R_fixture 50.000, V_fixture 0.600: 20-80 % time 415ps typ, 493ps min, 342ps max; typ from 0.35 V to 0.906 V
|   falling waveform, R_fixture 50.000, V_fixture 0.600: 20-80 % time 543ps typ, 586ps min, 590ps max; typ from 0.906 V to 0.35 V
|   falling waveform, R_fixture 50.000, V_fixture 0.0: 20-80 % time 261ps typ, 284ps min, 260ps max; typ from 0.433 V to 0 V
[Pulldown]
|Voltage   I(typ)   I(min)   I(max)
-1.2V     -12.39mA   -13.7mA    -12.49mA
-1.04V    -12.05mA   -12.88mA   -12.49mA
-880mV    -11.58mA   -12mA      -11.79mA
-560mV    -8.851mA   -8.925mA   -9.245mA
-280mV    -4.688mA   -4.607mA   -4.974mA
200mV     3.164mA    3.008mA    3.437mA
440mV     6.136mA    5.828mA    6.7mA
680mV     8.315mA    7.89mA     9.126mA
920mV     9.761mA    9.262mA    10.76mA
1.16V     10.53mA    9.999mA    11.64mA
2.08V     11.4mA     11.13mA    12.4mA
2.4V      12mA       11.6mA     13.16mA
[Pullup]
|Voltage   I(typ)   I(min)   I(max)
-1.2V     49.81mA    46.93mA    48.92mA
-1.08V    45.69mA    42.51mA    45.38mA
-1.04V    44.01mA    40.89mA    43.73mA
-800mV    33.87mA    31.41mA    32.97mA
-560mV    23.54mA    22.17mA    23.28mA
-320mV    11.96mA    11.27mA    12.16mA
-160mV    5.32mA     4.915mA    5.567mA
40mV      -1.115mA   -1.004mA   -1.21mA
240mV     -5.411mA   -4.919mA   -5.88mA
440mV     -7.689mA   -7.053mA   -8.429mA
640mV     -8.391mA   -7.704mA   -9.316mA
2.36V     -9.926mA   -9.119mA   -11.01mA
[GND_clamp]
|Voltage   I(typ)   I(min)   I(max)
-1.2V     -438mA     -409mA     -376.5mA
-1.14V    -347.3mA   -346mA     -274.9mA
-1.08V    -262.9mA   -286.2mA   -185.9mA
-1.05V    -223.7mA   -257.6mA   -150mA
-990mV    -156.1mA   -203.2mA   -95.66mA
-930mV    -105mA     -153.7mA   -55.58mA
-870mV    -64.74mA   -113.2mA   -29.56mA
-810mV    -35.2mA    -81.56mA   -16.45mA
-720mV    -11.09mA   -44.69mA   -8.691mA
-600mV    -2.287mA   -13.94mA   -2.904mA
-450mV    -166.2uA   -1.247mA   -164.1uA
1.2V      0A         0A         0A
[POWER_clamp]
|Voltage   I(typ)   I(min)   I(max)
-1.2V     137.6mA    137.3mA    182.1mA
-1.14V    110.1mA    115.3mA    133.6mA
-1.08V    84.76mA    94.63mA    92.15mA
-1.02V    62.11mA    75.36mA    59.94mA
-990mV    52mA       66.3mA     47.89mA
-930mV    34.81mA    49.51mA    32.55mA
-870mV    22.62mA    34.86mA    25.07mA
-780mV    13.14mA    18.01mA    16.74mA
-720mV    9.284mA    10.72mA    11.88mA
-600mV    3.553mA    3.709mA    4.373mA
-450mV    294.8uA    471.6uA    256.4uA
1.2V      0A         0A         0A
[Ramp]
| variable   typ   min   max
dV/dt_r   0.258/0.432n   0.236/0.528n   0.288/0.362n
dV/dt_f   0.266/0.570n   0.247/0.546n   0.295/0.639n
R_load = 50.000
[Rising Waveform]
R_fixture= 50.000
V_fixture= 0.0
V_fixture_min= 0.0
V_fixture_max= 0.0
|time   V(typ)   V(min)   V(max)
0s        0V         0V         0V
366ps     -17.93mV   -1.319mV   -5.917mV
611ps     77.72mV    -8.804mV   197.7mV
755ps     183.4mV    48.86mV    322.8mV
910ps     284.2mV    134.9mV    403mV
1.111ns   365.4mV    236.4mV    451.4mV
1.351ns   408mV      319.3mV    472.6mV
1.716ns   427.3mV    373.5mV    481mV
2.281ns   432mV      391.7mV    482.8mV
10ns      432.5mV    394.5mV    482.9mV
[Rising Waveform]
R_fixture= 50.000
V_fixture= 0.600
V_fixture_min= 0.571
V_fixture_max= 0.631
|time   V(typ)   V(min)   V(max)
0s        350.1mV    339.6mV    355.1mV
256ps     348.5mV    339.5mV    352.8mV
334ps     350.5mV    338.6mV    437.9mV
470ps     480.2mV    340.4mV    585.8mV
765ps     729.6mV    563.1mV    877.3mV
922ps     824.8mV    664.2mV    934.8mV
1.1ns     877.1mV    752.7mV    956.5mV
1.401ns   901.5mV    824.1mV    964.3mV
1.911ns   906.1mV    846.5mV    965.4mV
10ns      906.4mV    848.9mV    965.5mV
[Falling Waveform]
R_fixture= 50.000
V_fixture= 0.600
V_fixture_min= 0.571
V_fixture_max= 0.631
|time   V(typ)   V(min)   V(max)
0s        906.4mV    848.9mV    965.5mV
232ps     905.6mV    848.9mV    964mV
313ps     903.6mV    847.9mV    876.8mV
439ps     784.8mV    849.8mV    758.4mV
698ps     596.8mV    669.1mV    589.7mV
957ps     466.5mV    527.1mV    468.6mV
1.235ns   395.2mV    420.3mV    402.2mV
1.568ns   361.9mV    363.3mV    368.5mV
2.498ns   350.2mV    340.3mV    355.2mV
10ns      350.1mV    339.6mV    355.1mV
[Falling Waveform]
R_fixture= 50.000
V_fixture= 0.0
V_fixture_min= 0.0
V_fixture_max= 0.0
|time   V(typ)   V(min)   V(max)
0s        432.5mV    394.5mV    482.9mV
224ps     431.8mV    394.5mV    479.2mV
303ps     428.2mV    393.5mV    353.2mV
420ps     268.6mV    398.8mV    195.5mV
528ps     153.5mV    286.4mV    106.4mV
638ps     80.22mV    174.4mV    52.15mV
765ps     34.92mV    90.14mV    21.11mV
925ps     11.58mV    35.01mV    6.653mV
1.656ns   454.5uV    981.2uV    539.1uV
10ns      0V         0V         0V
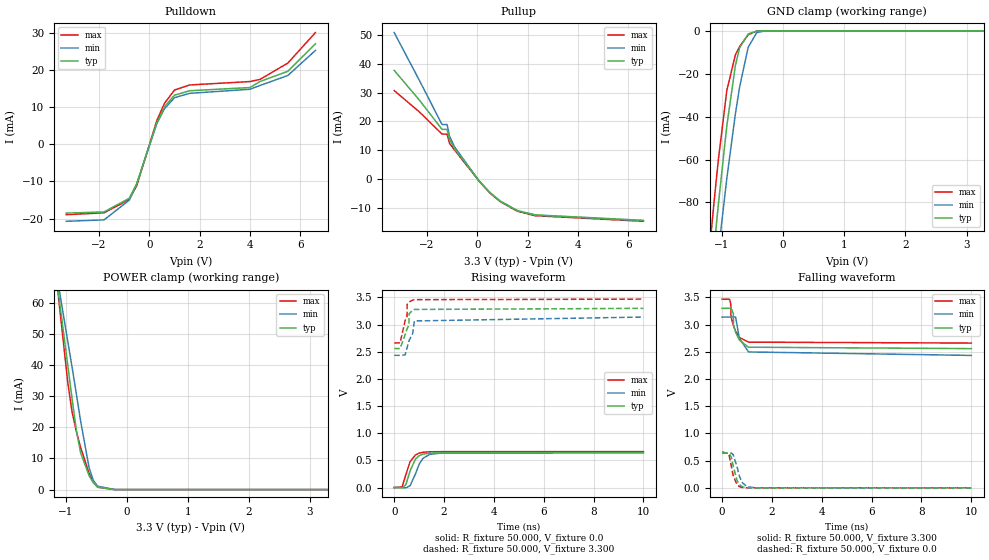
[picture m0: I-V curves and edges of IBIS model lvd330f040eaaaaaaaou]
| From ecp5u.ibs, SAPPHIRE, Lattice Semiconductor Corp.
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|   Model lvd330f040eaaaaaaaou
[Model] lvd330f040eaaaaaaaou
Model_type  Output
Polarity   Non-Inverting
Enable   Active-Low
Vmeas =  1.650V
Cref =  0.0F
Rref =  1.000M
Vref =  0.0V
C_comp   5.000pF   4.000pF   5.500pF
[Temperature Range]   25.000   0.125k   -40.000
[Voltage Range]   3.300V   3.140V   3.470V
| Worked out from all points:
|   slope of the pulldown table from 0 to 0.495 V, typ, clamps not added: 56.4 ohm
|   slope of the pullup table from 0 to 0.495 V, typ, clamps not added: 104 ohm
|   GND clamp passes 1 mA (typ) near -0.54 V on its own axis
|   POWER clamp passes 1 mA (typ) near -0.49 V on its own axis
|   rising waveform, R_fixture 50.000, V_fixture 0.0: 20-80 % time 307ps typ, 345ps min, 291ps max; typ from 0 V to 0.64 V
|   rising waveform, R_fixture 50.000, V_fixture 3.300: 20-80 % time 218ps typ, 233ps min, 212ps max; typ from 2.56 V to 3.3 V
|   falling waveform, R_fixture 50.000, V_fixture 3.300: 20-80 % time 250ps typ, 266ps min, 250ps max; typ from 3.3 V to 2.56 V
|   falling waveform, R_fixture 50.000, V_fixture 0.0: 20-80 % time 206ps typ, 232ps min, 187ps max; typ from 0.64 V to 0 V
[Pulldown]
|Voltage   I(typ)   I(min)   I(max)
-3.3V     -18.5mA    -20.7mA    -18.92mA
-1.8V     -18.18mA   -20.32mA   -18.42mA
-800mV    -14.52mA   -15.03mA   -14.85mA
-500mV    -10.57mA   -10.59mA   -11.09mA
300mV     5.904mA    5.61mA     6.427mA
600mV     10.05mA    9.542mA    11.01mA
1V        13.22mA    12.54mA    14.59mA
1.6V      14.4mA     13.7mA     15.95mA
4V        15.26mA    14.8mA     16.87mA
4.4V      16.89mA    15.82mA    17.46mA
5.5V      19.62mA    18.49mA    21.82mA
6.6V      27.03mA    25.25mA    30.04mA
[Pullup]
|Voltage   I(typ)   I(min)   I(max)
-3.3V     37.75mA    50.9mA     30.71mA
-2.3V     27.39mA    34.26mA    23.28mA
-1.4V     17.2mA     18.89mA    15.56mA
-1.2V     17.2mA     18.89mA    15.56mA
-1.1V     13.59mA    14.8mA     12.32mA
-900mV    10.46mA    11.08mA    9.989mA
100mV     -1.071mA   -1.053mA   -1.1mA
500mV     -4.806mA   -4.761mA   -4.92mA
900mV     -7.725mA   -7.703mA   -7.892mA
1.6V      -11.09mA   -11.15mA   -11.32mA
2.3V      -12.56mA   -12.67mA   -12.86mA
6.6V      -14.47mA   -14.62mA   -14.8mA
[GND_clamp]
|Voltage   I(typ)   I(min)   I(max)
-3.3V     -912.7mA   -861.5mA   -922.5mA
-1.27V    -145.6mA   -163.6mA   -123.5mA
-1.2V     -123.4mA   -142.6mA   -101.4mA
-1.13V    -102mA     -122.4mA   -80.37mA
-1.06V    -81.56mA   -103.5mA   -60.64mA
-920mV    -44.4mA    -68.93mA   -27.87mA
-780mV    -16.18mA   -38.86mA   -11.24mA
-710mV    -7.839mA   -26.12mA   -7.318mA
-570mV    -1.464mA   -7.654mA   -1.852mA
-430mV    -105.8uA   -801.1uA   -99.73uA
-290mV    -1.56uA    -33.42uA   -868.4nA
3.28V     0A         0A         0A
[POWER_clamp]
|Voltage   I(typ)   I(min)   I(max)
-3.28V    471.5mA    421.2mA    516.6mA
-1.18V    71.72mA    72.75mA    72.14mA
-1.11V    60.88mA    63.98mA    59.38mA
-970mV    39.73mA    47.46mA    34.21mA
-900mV    29.12mA    39.28mA    24.89mA
-830mV    19.01mA    30.67mA    18.7mA
-760mV    11.8mA     22.01mA    13.51mA
-620mV    4.416mA    6.921mA    5.219mA
-550mV    2.174mA    2.865mA    2.414mA
-480mV    813uA      1.102mA    758.3uA
-200mV    3.62uA     22.61uA    424nA
3.3V      0A         0A         0A
[Ramp]
| variable   typ   min   max
dV/dt_r   0.387/0.311n   0.386/0.346n   0.399/0.292n
dV/dt_f   0.442/0.317n   0.421/0.336n   0.490/0.301n
R_load = 50.000
[Rising Waveform]
R_fixture= 50.000
V_fixture= 0.0
V_fixture_min= 0.0
V_fixture_max= 0.0
|time   V(typ)   V(min)   V(max)
0s        0V         0V         0V
319ps     -5.288mV   -79.81uV   15.55mV
467ps     51.9mV     -6.161mV   235.2mV
637ps     304.5mV    33.43mV    475.9mV
854ps     523.7mV    250.2mV    600.8mV
1.005ns   586mV      432.7mV    633.6mV
1.154ns   614.6mV    537.2mV    648.5mV
1.432ns   633.6mV    612.3mV    658.2mV
1.926ns   639.1mV    635.3mV    661mV
10ns      639.5mV    637.5mV    661.2mV
[Rising Waveform]
R_fixture= 50.000
V_fixture= 3.300
V_fixture_min= 3.140
V_fixture_max= 3.470
|time   V(typ)   V(min)   V(max)
0s        2.56V      2.435V     2.662V
238ps     2.56V      2.435V     2.666V
437ps     2.817V     2.443V     3.073V
515ps     2.923V     2.571V     3.151V
520ps     2.928V     2.581V     3.372V
593ps     2.991V     2.701V     3.414V
600ps     3.202V     2.71V      3.417V
743ps     3.266V     2.839V     3.453V
810ps     3.28V      3.068V     3.46V
10ns      3.3V       3.14V      3.47V
[Falling Waveform]
R_fixture= 50.000
V_fixture= 3.300
V_fixture_min= 3.140
V_fixture_max= 3.470
|time   V(typ)   V(min)   V(max)
0s        3.3V       3.14V      3.47V
299ps     3.303V     3.14V      3.467V
350ps     3.308V     3.14V      3.376V
355ps     3.308V     3.14V      3.148V
453ps     3.201V     3.146V     2.986V
455ps     2.991V     3.146V     2.984V
543ps     2.861V     3.138V     2.878V
691ps     2.717V     2.75V      2.766V
1.061ns   2.586V     2.499V     2.679V
10ns      2.56V      2.435V     2.662V
[Falling Waveform]
R_fixture= 50.000
V_fixture= 0.0
V_fixture_min= 0.0
V_fixture_max= 0.0
|time   V(typ)   V(min)   V(max)
0s        639.5mV    637.5mV    661.2mV
269ps     639.3mV    637.3mV    626.1mV
370ps     566mV      639mV      393.7mV
443ps     405.4mV    612.3mV    230mV
600ps     133.1mV    385mV      56.14mV
702ps     55.66mV    204.4mV    21.55mV
821ps     19.26mV    89.45mV    7.098mV
1.011ns   3.635mV    19.75mV    1.235mV
1.361ns   204.4uV    1.206mV    68.1uV
10ns      0V         0V         0V
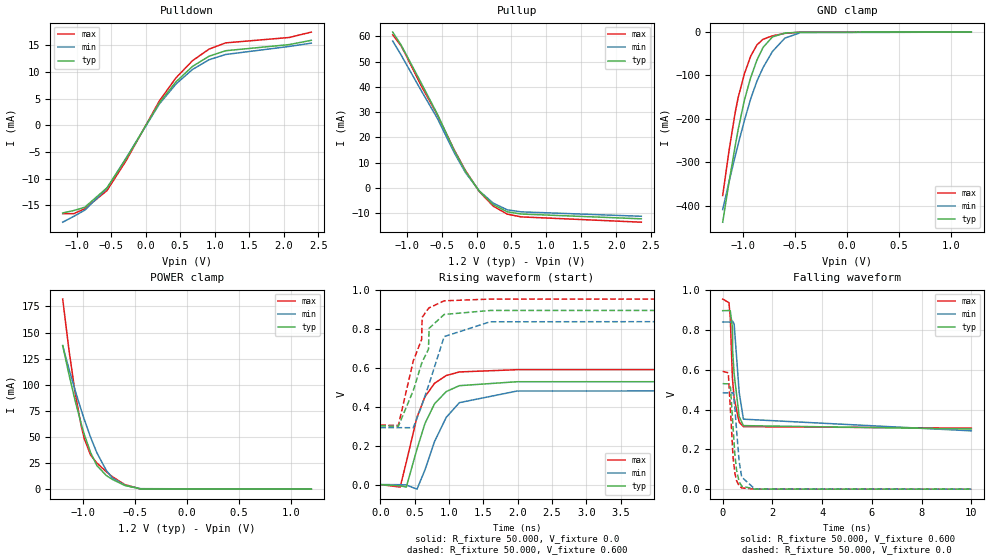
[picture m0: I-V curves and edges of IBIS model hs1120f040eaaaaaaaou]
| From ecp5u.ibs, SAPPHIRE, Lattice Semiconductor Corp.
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|   Model hs1120f040eaaaaaaaou
[Model] hs1120f040eaaaaaaaou
Model_type  Output
Polarity   Non-Inverting
Enable   Active-Low
Vmeas =  0.600V
Cref =  20.000pF
Rref =  50.000
Vref =  0.600V
C_comp   5.000pF   4.000pF   5.500pF
[Temperature Range]   25.000   0.125k   -40.000
[Voltage Range]   1.200V   1.140V   1.260V
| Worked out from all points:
|   slope of the pulldown table from 0 to 0.18 V, typ, clamps not added: 47.3 ohm
|   slope of the pullup table from 0 to 0.18 V, typ, clamps not added: 33.5 ohm
|   GND clamp passes 1 mA (typ) near -0.54 V on its own axis
|   POWER clamp passes 1 mA (typ) near -0.51 V on its own axis
|   rising waveform, R_fixture 50.000, V_fixture 0.0: 20-80 % time 327ps typ, 376ps min, 303ps max; typ from 0 V to 0.53 V
|   rising waveform, R_fixture 50.000, V_fixture 0.600: 20-80 % time 273ps typ, 289ps min, 258ps max; typ from 0.302 V to 0.897 V
|   falling waveform, R_fixture 50.000, V_fixture 0.600: 20-80 % time 180ps typ, 194ps min, 173ps max; typ from 0.897 V to 0.302 V
|   falling waveform, R_fixture 50.000, V_fixture 0.0: 20-80 % time 182ps typ, 204ps min, 167ps max; typ from 0.53 V to 0 V
[Pulldown]
|Voltage   I(typ)   I(min)   I(max)
-1.2V     -16.42mA   -18.15mA   -16.55mA
-1.04V    -15.97mA   -17.06mA   -16.55mA
-880mV    -15.35mA   -15.9mA    -15.62mA
-560mV    -11.73mA   -11.83mA   -12.25mA
-280mV    -6.212mA   -6.104mA   -6.591mA
200mV     4.193mA    3.985mA    4.554mA
440mV     8.13mA     7.722mA    8.878mA
680mV     11.02mA    10.45mA    12.09mA
920mV     12.93mA    12.27mA    14.26mA
1.16V     13.95mA    13.25mA    15.42mA
2.08V     15.1mA     14.75mA    16.43mA
2.4V      15.9mA     15.37mA    17.44mA
[Pullup]
|Voltage   I(typ)   I(min)   I(max)
-1.2V     61.71mA    58.15mA    60.61mA
-1.08V    56.61mA    52.66mA    56.22mA
-1.04V    54.53mA    50.65mA    54.17mA
-800mV    41.96mA    38.92mA    40.85mA
-560mV    29.16mA    27.47mA    28.85mA
-320mV    14.81mA    13.96mA    15.06mA
-160mV    6.591mA    6.089mA    6.897mA
40mV      -1.382mA   -1.244mA   -1.499mA
240mV     -6.703mA   -6.094mA   -7.284mA
440mV     -9.525mA   -8.737mA   -10.44mA
640mV     -10.4mA    -9.544mA   -11.54mA
2.36V     -12.3mA    -11.3mA    -13.64mA
[GND_clamp]
|Voltage   I(typ)   I(min)   I(max)
-1.2V     -438mA     -409mA     -376.5mA
-1.14V    -347.3mA   -346mA     -274.9mA
-1.08V    -262.9mA   -286.2mA   -185.9mA
-1.05V    -223.7mA   -257.6mA   -150mA
-990mV    -156.1mA   -203.2mA   -95.66mA
-930mV    -105mA     -153.7mA   -55.58mA
-870mV    -64.74mA   -113.2mA   -29.56mA
-810mV    -35.2mA    -81.56mA   -16.45mA
-720mV    -11.09mA   -44.69mA   -8.691mA
-600mV    -2.287mA   -13.94mA   -2.904mA
-450mV    -166.2uA   -1.247mA   -164.1uA
1.2V      0A         0A         0A
[POWER_clamp]
|Voltage   I(typ)   I(min)   I(max)
-1.2V     137.6mA    137.3mA    182.1mA
-1.14V    110.1mA    115.3mA    133.6mA
-1.08V    84.76mA    94.63mA    92.15mA
-1.02V    62.11mA    75.36mA    59.94mA
-990mV    52mA       66.3mA     47.89mA
-930mV    34.81mA    49.51mA    32.55mA
-870mV    22.62mA    34.86mA    25.07mA
-780mV    13.14mA    18.01mA    16.74mA
-720mV    9.284mA    10.72mA    11.88mA
-600mV    3.553mA    3.709mA    4.373mA
-450mV    294.8uA    471.6uA    256.4uA
1.2V      0A         0A         0A
[Ramp]
| variable   typ   min   max
dV/dt_r   0.314/0.326n   0.288/0.376n   0.350/0.306n
dV/dt_f   0.324/0.237n   0.301/0.244n   0.357/0.221n
R_load = 50.000
[Rising Waveform]
R_fixture= 50.000
V_fixture= 0.0
V_fixture_min= 0.0
V_fixture_max= 0.0
|time   V(typ)   V(min)   V(max)
0s        0V         0V         0V
289ps     -6.276mV   -542.3uV   -12.71mV
379ps     -12.66mV   -1.985mV   115.5mV
534ps     182.6mV    -23.53mV   346.6mV
650ps     314.2mV    75.35mV    452mV
790ps     416mV      221.8mV    521.6mV
960ps     478.8mV    346.1mV    561.4mV
1.151ns   509.2mV    421.7mV    579.9mV
1.99ns    529.5mV    481.6mV    591.4mV
10ns      529.9mV    483.3mV    591.7mV
[Rising Waveform]
R_fixture= 50.000
V_fixture= 0.600
V_fixture_min= 0.571
V_fixture_max= 0.631
|time   V(typ)   V(min)   V(max)
0s        302.1mV    293mV      306.4mV
263ps     300.4mV    292.9mV    304.5mV
481ps     484.8mV    292.8mV    637.6mV
602ps     623.9mV    404.7mV    747mV
609ps     630.3mV    412.3mV    860.9mV
702ps     697.3mV    509.8mV    907.1mV
710ps     804.2mV    517.5mV    909.8mV
930ps     875.8mV    761.7mV    946mV
1.599ns   896.3mV    838.1mV    954.9mV
10ns      896.6mV    839.7mV    955mV
[Falling Waveform]
R_fixture= 50.000
V_fixture= 0.600
V_fixture_min= 0.571
V_fixture_max= 0.631
|time   V(typ)   V(min)   V(max)
0s        896.6mV    839.7mV    955mV
251ps     897.3mV    839.7mV    937mV
305ps     895.9mV    839.1mV    860.7mV
388ps     816.1mV    843.3mV    566.5mV
396ps     801.9mV    843.8mV    551.3mV
398ps     696.6mV    843.8mV    547.7mV
460ps     578.6mV    830.3mV    456.4mV
663ps     364.2mV    485.6mV    336.6mV
833ps     319.2mV    351.6mV    314.2mV
10ns      302.1mV    293mV      306.4mV
[Falling Waveform]
R_fixture= 50.000
V_fixture= 0.0
V_fixture_min= 0.0
V_fixture_max= 0.0
|time   V(typ)   V(min)   V(max)
0s        529.9mV    483.3mV    591.7mV
224ps     529.1mV    483.3mV    584.7mV
312ps     511.2mV    482.2mV    396.7mV
420ps     304.1mV    484.8mV    155.8mV
491ps     170.7mV    406.8mV    80.41mV
561ps     92.59mV    290.2mV    41.75mV
664ps     37.02mV    137.9mV    15.88mV
764ps     15.14mV    60.82mV    6.204mV
1.291ns   161.1uV    834.4uV    38.25uV
10ns      0V         0V         0V
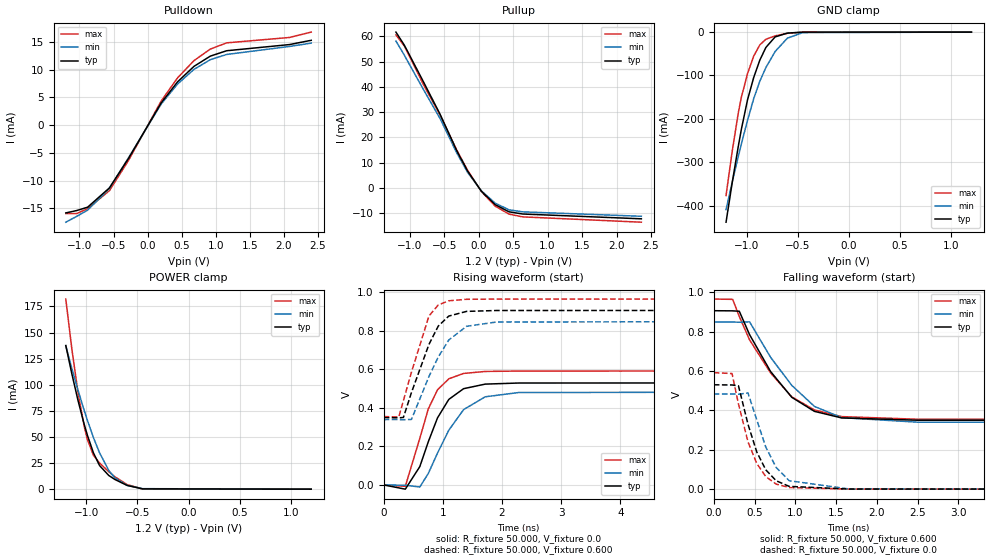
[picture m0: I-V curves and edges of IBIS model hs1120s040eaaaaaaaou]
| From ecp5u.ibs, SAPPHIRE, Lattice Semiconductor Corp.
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|   Model hs1120s040eaaaaaaaou
[Model] hs1120s040eaaaaaaaou
Model_type  Output
Polarity   Non-Inverting
Enable   Active-Low
Vmeas =  0.600V
Cref =  20.000pF
Rref =  50.000
Vref =  0.600V
C_comp   5.000pF   4.000pF   5.500pF
[Temperature Range]   25.000   0.125k   -40.000
[Voltage Range]   1.200V   1.140V   1.260V
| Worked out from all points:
|   slope of the pulldown table from 0 to 0.18 V, typ, clamps not added: 49.1 ohm
|   slope of the pullup table from 0 to 0.18 V, typ, clamps not added: 33.5 ohm
|   GND clamp passes 1 mA (typ) near -0.54 V on its own axis
|   POWER clamp passes 1 mA (typ) near -0.51 V on its own axis
|   rising waveform, R_fixture 50.000, V_fixture 0.0: 20-80 % time 425ps typ, 526ps min, 357ps max; typ from 0 V to 0.53 V
|   rising waveform, R_fixture 50.000, V_fixture 0.600: 20-80 % time 415ps typ, 493ps min, 342ps max; typ from 0.35 V to 0.906 V
|   falling waveform, R_fixture 50.000, V_fixture 0.600: 20-80 % time 543ps typ, 586ps min, 590ps max; typ from 0.906 V to 0.35 V
|   falling waveform, R_fixture 50.000, V_fixture 0.0: 20-80 % time 261ps typ, 284ps min, 260ps max; typ from 0.53 V to 0 V
[Pulldown]
|Voltage   I(typ)   I(min)   I(max)
-1.2V     -15.8mA    -17.47mA   -15.92mA
-1.04V    -15.37mA   -16.42mA   -15.92mA
-880mV    -14.77mA   -15.3mA    -15.03mA
-560mV    -11.29mA   -11.38mA   -11.79mA
-280mV    -5.978mA   -5.873mA   -6.342mA
200mV     4.035mA    3.835mA    4.382mA
440mV     7.823mA    7.431mA    8.543mA
680mV     10.6mA     10.06mA    11.64mA
920mV     12.45mA    11.81mA    13.72mA
1.16V     13.42mA    12.75mA    14.84mA
2.08V     14.53mA    14.19mA    15.81mA
2.4V      15.3mA     14.79mA    16.78mA
[Pullup]
|Voltage   I(typ)   I(min)   I(max)
-1.2V     61.71mA    58.15mA    60.61mA
-1.08V    56.61mA    52.66mA    56.22mA
-1.04V    54.53mA    50.65mA    54.17mA
-800mV    41.96mA    38.92mA    40.85mA
-560mV    29.16mA    27.47mA    28.85mA
-320mV    14.81mA    13.96mA    15.06mA
-160mV    6.591mA    6.089mA    6.897mA
40mV      -1.382mA   -1.244mA   -1.499mA
240mV     -6.703mA   -6.094mA   -7.284mA
440mV     -9.525mA   -8.737mA   -10.44mA
640mV     -10.4mA    -9.544mA   -11.54mA
2.36V     -12.3mA    -11.3mA    -13.64mA
[GND_clamp]
|Voltage   I(typ)   I(min)   I(max)
-1.2V     -438mA     -409mA     -376.5mA
-1.14V    -347.3mA   -346mA     -274.9mA
-1.08V    -262.9mA   -286.2mA   -185.9mA
-1.05V    -223.7mA   -257.6mA   -150mA
-990mV    -156.1mA   -203.2mA   -95.66mA
-930mV    -105mA     -153.7mA   -55.58mA
-870mV    -64.74mA   -113.2mA   -29.56mA
-810mV    -35.2mA    -81.56mA   -16.45mA
-720mV    -11.09mA   -44.69mA   -8.691mA
-600mV    -2.287mA   -13.94mA   -2.904mA
-450mV    -166.2uA   -1.247mA   -164.1uA
1.2V      0A         0A         0A
[POWER_clamp]
|Voltage   I(typ)   I(min)   I(max)
-1.2V     137.6mA    137.3mA    182.1mA
-1.14V    110.1mA    115.3mA    133.6mA
-1.08V    84.76mA    94.63mA    92.15mA
-1.02V    62.11mA    75.36mA    59.94mA
-990mV    52mA       66.3mA     47.89mA
-930mV    34.81mA    49.51mA    32.55mA
-870mV    22.62mA    34.86mA    25.07mA
-780mV    13.14mA    18.01mA    16.74mA
-720mV    9.284mA    10.72mA    11.88mA
-600mV    3.553mA    3.709mA    4.373mA
-450mV    294.8uA    471.6uA    256.4uA
1.2V      0A         0A         0A
[Ramp]
| variable   typ   min   max
dV/dt_r   0.314/0.432n   0.288/0.528n   0.350/0.362n
dV/dt_f   0.316/0.570n   0.294/0.546n   0.349/0.639n
R_load = 50.000
[Rising Waveform]
R_fixture= 50.000
V_fixture= 0.0
V_fixture_min= 0.0
V_fixture_max= 0.0
|time   V(typ)   V(min)   V(max)
0s        0V         0V         0V
366ps     -21.97mV   -1.616mV   -7.251mV
611ps     95.24mV    -10.79mV   242.2mV
755ps     224.7mV    59.88mV    395.5mV
910ps     348.3mV    165.3mV    493.9mV
1.101ns   444.4mV    284.3mV    551.3mV
1.351ns   500mV      391.3mV    579.2mV
1.716ns   523.7mV    457.8mV    589.5mV
2.281ns   529.4mV    480mV      591.6mV
10ns      530.1mV    483.4mV    591.8mV
[Rising Waveform]
R_fixture= 50.000
V_fixture= 0.600
V_fixture_min= 0.571
V_fixture_max= 0.631
|time   V(typ)   V(min)   V(max)
0s        350.1mV    339.6mV    355.1mV
256ps     348.5mV    339.5mV    352.8mV
334ps     350.5mV    338.6mV    437.9mV
470ps     480.2mV    340.4mV    585.8mV
765ps     729.6mV    563.1mV    877.3mV
922ps     824.8mV    664.2mV    934.8mV
1.1ns     877.1mV    752.7mV    956.5mV
1.401ns   901.5mV    824.1mV    964.3mV
1.911ns   906.1mV    846.5mV    965.4mV
10ns      906.4mV    848.9mV    965.5mV
[Falling Waveform]
R_fixture= 50.000
V_fixture= 0.600
V_fixture_min= 0.571
V_fixture_max= 0.631
|time   V(typ)   V(min)   V(max)
0s        906.4mV    848.9mV    965.5mV
232ps     905.6mV    848.9mV    964mV
313ps     903.6mV    847.9mV    876.8mV
439ps     784.8mV    849.8mV    758.4mV
698ps     596.8mV    669.1mV    589.7mV
957ps     466.5mV    527.1mV    468.6mV
1.235ns   395.2mV    420.3mV    402.2mV
1.568ns   361.9mV    363.3mV    368.5mV
2.498ns   350.2mV    340.3mV    355.2mV
10ns      350.1mV    339.6mV    355.1mV
[Falling Waveform]
R_fixture= 50.000
V_fixture= 0.0
V_fixture_min= 0.0
V_fixture_max= 0.0
|time   V(typ)   V(min)   V(max)
0s        530.1mV    483.4mV    591.8mV
224ps     529.2mV    483.4mV    587.2mV
303ps     524.7mV    482.2mV    432.9mV
420ps     329.2mV    488.7mV    239.5mV
528ps     188.1mV    351mV      130.3mV
638ps     98.31mV    213.7mV    63.91mV
765ps     42.8mV     110.5mV    25.87mV
925ps     14.2mV     42.91mV    8.153mV
1.656ns   557uV      1.202mV    660.6uV
10ns      0V         0V         0V
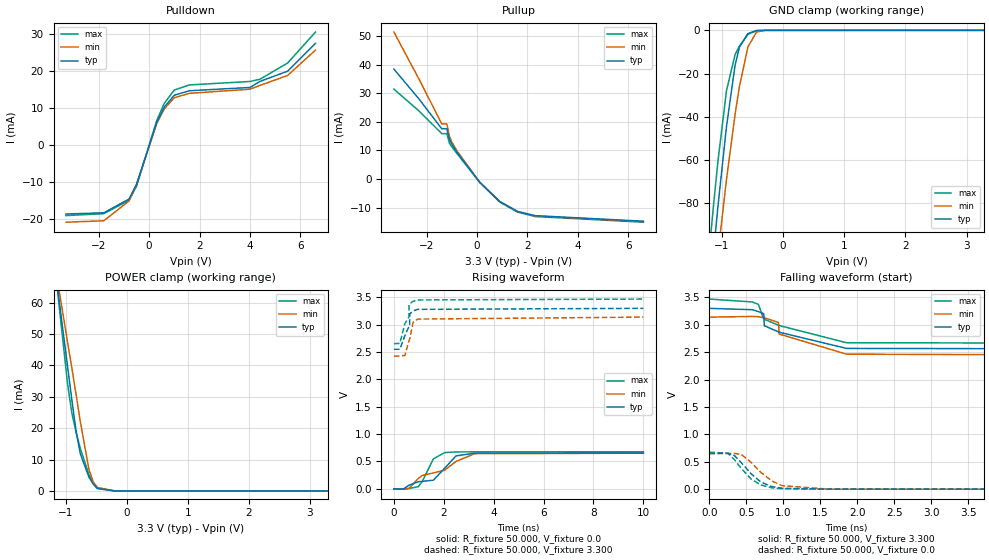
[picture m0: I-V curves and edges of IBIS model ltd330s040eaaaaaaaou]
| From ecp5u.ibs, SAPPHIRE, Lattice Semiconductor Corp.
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|   Model ltd330s040eaaaaaaaou
[Model] ltd330s040eaaaaaaaou
Model_type  Output
Polarity   Non-Inverting
Enable   Active-Low
Vmeas =  1.650V
Cref =  0.0F
Rref =  1.000M
Vref =  0.0V
C_comp   5.000pF   4.000pF   5.500pF
[Temperature Range]   25.000   0.125k   -40.000
[Voltage Range]   3.300V   3.140V   3.470V
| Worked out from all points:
|   slope of the pulldown table from 0 to 0.495 V, typ, clamps not added: 55.7 ohm
|   slope of the pullup table from 0 to 0.495 V, typ, clamps not added: 102 ohm
|   GND clamp passes 1 mA (typ) near -0.54 V on its own axis
|   POWER clamp passes 1 mA (typ) near -0.49 V on its own axis
|   rising waveform, R_fixture 50.000, V_fixture 0.0: 20-80 % time 1.24ns typ, 1.67ns min, 436ps max; typ from 0 V to 0.653 V
|   rising waveform, R_fixture 50.000, V_fixture 3.300: 20-80 % time 254ps typ, 253ps min, 296ps max; typ from 2.55 V to 3.3 V
|   falling waveform, R_fixture 50.000, V_fixture 3.300: 20-80 % time 516ps typ, 482ps min, 612ps max; typ from 3.3 V to 2.55 V
|   falling waveform, R_fixture 50.000, V_fixture 0.0: 20-80 % time 289ps typ, 327ps min, 275ps max; typ from 0.653 V to 0 V
[Pulldown]
|Voltage   I(typ)   I(min)   I(max)
-3.3V     -18.73mA   -20.94mA   -19.15mA
-1.8V     -18.4mA    -20.56mA   -18.64mA
-800mV    -14.7mA    -15.21mA   -15.03mA
-500mV    -10.7mA    -10.72mA   -11.22mA
300mV     5.975mA    5.678mA    6.504mA
600mV     10.17mA    9.657mA    11.15mA
1V        13.37mA    12.69mA    14.76mA
1.6V      14.57mA    13.87mA    16.14mA
4V        15.45mA    14.98mA    17.07mA
4.4V      17.09mA    16.01mA    17.67mA
5.5V      19.86mA    18.71mA    22.08mA
6.6V      27.35mA    25.55mA    30.41mA
[Pullup]
|Voltage   I(typ)   I(min)   I(max)
-3.3V     38.47mA    51.42mA    31.46mA
-2.3V     27.95mA    34.88mA    23.78mA
-1.4V     17.56mA    19.29mA    15.88mA
-1.2V     17.56mA    19.29mA    15.88mA
-1.1V     13.88mA    15.11mA    12.58mA
-1V       12.19mA    12.92mA    11.22mA
-800mV    9.372mA    9.892mA    8.947mA
100mV     -1.093mA   -1.075mA   -1.123mA
900mV     -7.886mA   -7.864mA   -8.057mA
1.6V      -11.32mA   -11.38mA   -11.56mA
2.3V      -12.82mA   -12.93mA   -13.13mA
6.6V      -14.77mA   -14.92mA   -15.11mA
[GND_clamp]
|Voltage   I(typ)   I(min)   I(max)
-3.3V     -912.7mA   -861.5mA   -922.5mA
-1.27V    -145.6mA   -163.6mA   -123.5mA
-1.2V     -123.4mA   -142.6mA   -101.4mA
-1.13V    -102mA     -122.4mA   -80.37mA
-1.06V    -81.56mA   -103.5mA   -60.64mA
-920mV    -44.4mA    -68.93mA   -27.87mA
-780mV    -16.18mA   -38.86mA   -11.24mA
-710mV    -7.839mA   -26.12mA   -7.318mA
-570mV    -1.464mA   -7.654mA   -1.852mA
-430mV    -105.8uA   -801.1uA   -99.73uA
-290mV    -1.56uA    -33.42uA   -868.4nA
3.28V     0A         0A         0A
[POWER_clamp]
|Voltage   I(typ)   I(min)   I(max)
-3.28V    471.5mA    421.2mA    516.6mA
-1.18V    71.72mA    72.75mA    72.14mA
-1.11V    60.88mA    63.98mA    59.38mA
-970mV    39.73mA    47.46mA    34.21mA
-900mV    29.12mA    39.28mA    24.89mA
-830mV    19.01mA    30.67mA    18.7mA
-760mV    11.8mA     22.01mA    13.51mA
-620mV    4.416mA    6.921mA    5.219mA
-550mV    2.174mA    2.865mA    2.414mA
-480mV    813uA      1.102mA    758.3uA
-200mV    3.62uA     22.61uA    424nA
3.3V      0A         0A         0A
[Ramp]
| variable   typ   min   max
dV/dt_r   0.394/1.202n   0.394/1.651n   0.408/0.445n
dV/dt_f   0.447/0.612n   0.426/0.595n   0.496/0.683n
R_load = 50.000
[Rising Waveform]
R_fixture= 50.000
V_fixture= 0.0
V_fixture_min= 0.0
V_fixture_max= 0.0
|time   V(typ)   V(min)   V(max)
0s        0V         0V         0V
367ps     -7.298mV   -426.6uV   -6.494mV
605ps     65.63mV    5.979mV    4.624mV
977ps     127.6mV    188.3mV    37.69mV
1.131ns   134.9mV    242.9mV    130.7mV
1.584ns   157.6mV    289.8mV    547.6mV
2.031ns   373.9mV    339mV      661.4mV
2.488ns   601.2mV    499.1mV    673.7mV
3.238ns   651.6mV    641.2mV    675mV
10ns      653mV      650.9mV    675.1mV
[Rising Waveform]
R_fixture= 50.000
V_fixture= 3.300
V_fixture_min= 3.140
V_fixture_max= 3.470
|time   V(typ)   V(min)   V(max)
0s        2.552V     2.428V     2.654V
239ps     2.552V     2.428V     2.66V
436ps     2.797V     2.438V     3.017V
601ps     2.964V     2.704V     3.143V
607ps     2.968V     2.711V     3.373V
631ps     2.982V     2.737V     3.384V
637ps     3.2V       2.743V     3.387V
768ps     3.252V     3.042V     3.428V
950ps     3.282V     3.104V     3.454V
10ns      3.3V       3.14V      3.47V
[Falling Waveform]
R_fixture= 50.000
V_fixture= 3.300
V_fixture_min= 3.140
V_fixture_max= 3.470
|time   V(typ)   V(min)   V(max)
0s        3.3V       3.14V      3.47V
580ps     3.276V     3.153V     3.417V
662ps     3.241V     3.147V     3.373V
735ps     3.202V     3.13V      3.105V
742ps     2.982V     3.128V     3.102V
766ps     2.969V     3.12V      3.088V
933ps     2.871V     3.042V     2.992V
943ps     2.865V     2.832V     2.987V
1.853ns   2.569V     2.464V     2.673V
10ns      2.552V     2.428V     2.654V
[Falling Waveform]
R_fixture= 50.000
V_fixture= 0.0
V_fixture_min= 0.0
V_fixture_max= 0.0
|time   V(typ)   V(min)   V(max)
0s        653mV      650.9mV    675mV
250ps     654.3mV    650.9mV    656.2mV
340ps     613.6mV    653.1mV    535.6mV
433ps     480.2mV    632.1mV    375.2mV
566ps     278mV      486.5mV    182.1mV
695ps     131mV      306.4mV    76.53mV
842ps     47.09mV    151.8mV    25.38mV
982ps     16.67mV    64.3mV     8.562mV
1.599ns   545.4uV    1.439mV    566.7uV
10ns      0V         0V         0V
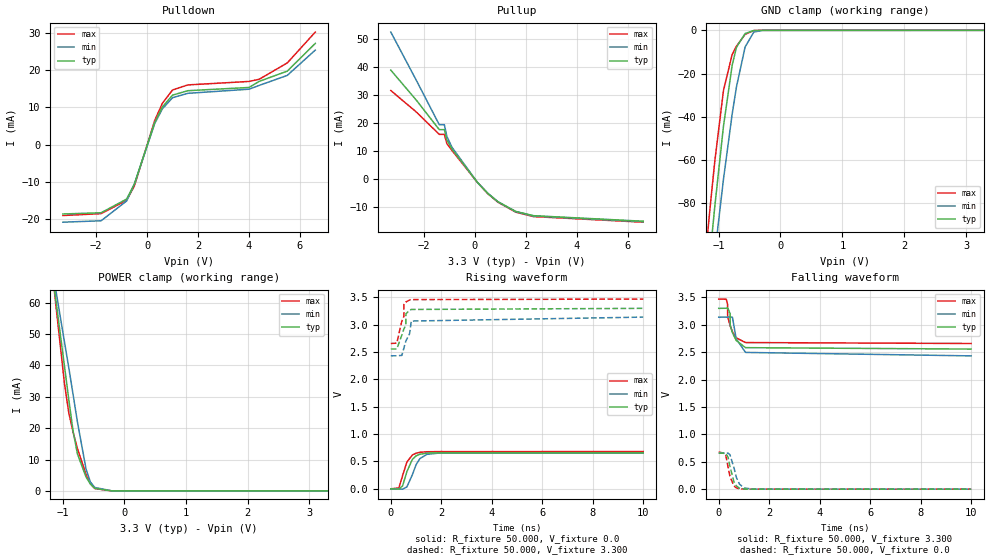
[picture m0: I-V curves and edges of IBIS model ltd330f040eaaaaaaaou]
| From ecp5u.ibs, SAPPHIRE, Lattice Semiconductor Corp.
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|   Model ltd330f040eaaaaaaaou
[Model] ltd330f040eaaaaaaaou
Model_type  Output
Polarity   Non-Inverting
Enable   Active-Low
Vmeas =  1.650V
Cref =  0.0F
Rref =  1.000M
Vref =  0.0V
C_comp   5.000pF   4.000pF   5.500pF
[Temperature Range]   25.000   0.125k   -40.000
[Voltage Range]   3.300V   3.140V   3.470V
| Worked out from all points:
|   slope of the pulldown table from 0 to 0.495 V, typ, clamps not added: 56.2 ohm
|   slope of the pullup table from 0 to 0.495 V, typ, clamps not added: 101 ohm
|   GND clamp passes 1 mA (typ) near -0.54 V on its own axis
|   POWER clamp passes 1 mA (typ) near -0.49 V on its own axis
|   rising waveform, R_fixture 50.000, V_fixture 0.0: 20-80 % time 307ps typ, 345ps min, 291ps max; typ from 0 V to 0.659 V
|   rising waveform, R_fixture 50.000, V_fixture 3.300: 20-80 % time 217ps typ, 233ps min, 212ps max; typ from 2.56 V to 3.3 V
|   falling waveform, R_fixture 50.000, V_fixture 3.300: 20-80 % time 249ps typ, 265ps min, 249ps max; typ from 3.3 V to 2.56 V
|   falling waveform, R_fixture 50.000, V_fixture 0.0: 20-80 % time 206ps typ, 232ps min, 187ps max; typ from 0.659 V to 0 V
[Pulldown]
|Voltage   I(typ)   I(min)   I(max)
-3.3V     -18.58mA   -20.78mA   -18.99mA
-1.8V     -18.25mA   -20.4mA    -18.49mA
-800mV    -14.58mA   -15.09mA   -14.91mA
-500mV    -10.61mA   -10.64mA   -11.14mA
300mV     5.928mA    5.633mA    6.453mA
600mV     10.09mA    9.581mA    11.06mA
1V        13.27mA    12.59mA    14.65mA
1.6V      14.46mA    13.76mA    16.01mA
4V        15.33mA    14.86mA    16.94mA
4.4V      16.96mA    15.88mA    17.53mA
5.5V      19.7mA     18.56mA    21.9mA
6.6V      27.14mA    25.35mA    30.17mA
[Pullup]
|Voltage   I(typ)   I(min)   I(max)
-3.3V     38.87mA    52.42mA    31.63mA
-2.3V     28.2mA     35.27mA    23.97mA
-1.4V     17.71mA    19.46mA    16.02mA
-1.2V     17.71mA    19.46mA    16.02mA
-1.1V     14mA       15.24mA    12.69mA
-900mV    10.78mA    11.41mA    10.29mA
100mV     -1.103mA   -1.084mA   -1.133mA
500mV     -4.949mA   -4.903mA   -5.067mA
900mV     -7.954mA   -7.931mA   -8.126mA
1.6V      -11.41mA   -11.48mA   -11.66mA
2.3V      -12.93mA   -13.04mA   -13.25mA
6.6V      -14.9mA    -15.05mA   -15.24mA
[GND_clamp]
|Voltage   I(typ)   I(min)   I(max)
-3.3V     -912.7mA   -861.5mA   -922.5mA
-1.27V    -145.6mA   -163.6mA   -123.5mA
-1.2V     -123.4mA   -142.6mA   -101.4mA
-1.13V    -102mA     -122.4mA   -80.37mA
-1.06V    -81.56mA   -103.5mA   -60.64mA
-920mV    -44.4mA    -68.93mA   -27.87mA
-780mV    -16.18mA   -38.86mA   -11.24mA
-710mV    -7.839mA   -26.12mA   -7.318mA
-570mV    -1.464mA   -7.654mA   -1.852mA
-430mV    -105.8uA   -801.1uA   -99.73uA
-290mV    -1.56uA    -33.42uA   -868.4nA
3.28V     0A         0A         0A
[POWER_clamp]
|Voltage   I(typ)   I(min)   I(max)
-3.28V    471.5mA    421.2mA    516.6mA
-1.18V    71.72mA    72.75mA    72.14mA
-1.11V    60.88mA    63.98mA    59.38mA
-970mV    39.73mA    47.46mA    34.21mA
-900mV    29.12mA    39.28mA    24.89mA
-830mV    19.01mA    30.67mA    18.7mA
-760mV    11.8mA     22.01mA    13.51mA
-620mV    4.416mA    6.921mA    5.219mA
-550mV    2.174mA    2.865mA    2.414mA
-480mV    813uA      1.102mA    758.3uA
-200mV    3.62uA     22.61uA    424nA
3.3V      0A         0A         0A
[Ramp]
| variable   typ   min   max
dV/dt_r   0.398/0.311n   0.397/0.346n   0.411/0.292n
dV/dt_f   0.444/0.317n   0.423/0.336n   0.492/0.301n
R_load = 50.000
[Rising Waveform]
R_fixture= 50.000
V_fixture= 0.0
V_fixture_min= 0.0
V_fixture_max= 0.0
|time   V(typ)   V(min)   V(max)
0s        0V         0V         0V
319ps     -5.445mV   -79.81uV   16.01mV
467ps     53.44mV    -6.344mV   242.2mV
637ps     313.5mV    34.42mV    490.1mV
854ps     539.2mV    257.6mV    618.6mV
1.005ns   603.4mV    445.5mV    652.4mV
1.154ns   632.9mV    553.2mV    667.7mV
1.432ns   652.4mV    630.5mV    677.7mV
1.926ns   658.1mV    654.2mV    680.6mV
10ns      658.5mV    656.5mV    680.8mV
[Rising Waveform]
R_fixture= 50.000
V_fixture= 3.300
V_fixture_min= 3.140
V_fixture_max= 3.470
|time   V(typ)   V(min)   V(max)
0s        2.557V     2.433V     2.659V
238ps     2.557V     2.433V     2.663V
437ps     2.813V     2.44V      3.07V
515ps     2.919V     2.568V     3.147V
520ps     2.924V     2.578V     3.372V
593ps     2.988V     2.698V     3.414V
600ps     3.202V     2.707V     3.417V
743ps     3.266V     2.835V     3.453V
810ps     3.28V      3.068V     3.46V
10ns      3.3V       3.14V      3.47V
[Falling Waveform]
R_fixture= 50.000
V_fixture= 3.300
V_fixture_min= 3.140
V_fixture_max= 3.470
|time   V(typ)   V(min)   V(max)
0s        3.3V       3.14V      3.47V
299ps     3.303V     3.14V      3.467V
350ps     3.308V     3.14V      3.376V
355ps     3.308V     3.14V      3.145V
453ps     3.201V     3.146V     2.983V
455ps     2.988V     3.146V     2.98V
543ps     2.857V     3.138V     2.875V
691ps     2.714V     2.746V     2.762V
1.061ns   2.583V     2.496V     2.676V
10ns      2.557V     2.433V     2.659V
[Falling Waveform]
R_fixture= 50.000
V_fixture= 0.0
V_fixture_min= 0.0
V_fixture_max= 0.0
|time   V(typ)   V(min)   V(max)
0s        658.5mV    656.5mV    680.8mV
269ps     658.3mV    656.2mV    644.7mV
370ps     582.8mV    658mV      405.4mV
443ps     417.5mV    630.4mV    236.9mV
600ps     137mV      396.5mV    57.81mV
702ps     57.31mV    210.5mV    22.19mV
821ps     19.83mV    92.11mV    7.309mV
1.011ns   3.742mV    20.34mV    1.272mV
1.361ns   210.5uV    1.242mV    68.1uV
10ns      0V         0V         0V
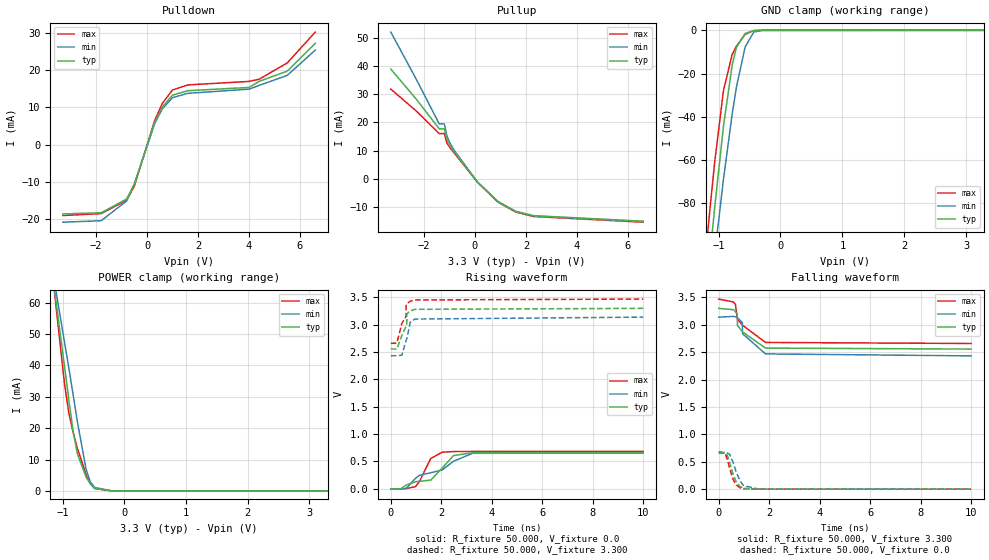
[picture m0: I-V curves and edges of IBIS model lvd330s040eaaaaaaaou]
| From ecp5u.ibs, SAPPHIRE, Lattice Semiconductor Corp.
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|   Model lvd330s040eaaaaaaaou
[Model] lvd330s040eaaaaaaaou
Model_type  Output
Polarity   Non-Inverting
Enable   Active-Low
Vmeas =  1.650V
Cref =  0.0F
Rref =  1.000M
Vref =  0.0V
C_comp   5.000pF   4.000pF   5.500pF
[Temperature Range]   25.000   0.125k   -40.000
[Voltage Range]   3.300V   3.140V   3.470V
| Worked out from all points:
|   slope of the pulldown table from 0 to 0.495 V, typ, clamps not added: 56.1 ohm
|   slope of the pullup table from 0 to 0.495 V, typ, clamps not added: 101 ohm
|   GND clamp passes 1 mA (typ) near -0.54 V on its own axis
|   POWER clamp passes 1 mA (typ) near -0.49 V on its own axis
|   rising waveform, R_fixture 50.000, V_fixture 0.0: 20-80 % time 1.24ns typ, 1.67ns min, 436ps max; typ from 0 V to 0.66 V
|   rising waveform, R_fixture 50.000, V_fixture 3.300: 20-80 % time 255ps typ, 254ps min, 296ps max; typ from 2.56 V to 3.3 V
|   falling waveform, R_fixture 50.000, V_fixture 3.300: 20-80 % time 519ps typ, 485ps min, 615ps max; typ from 3.3 V to 2.56 V
|   falling waveform, R_fixture 50.000, V_fixture 0.0: 20-80 % time 289ps typ, 327ps min, 275ps max; typ from 0.66 V to 0 V
[Pulldown]
|Voltage   I(typ)   I(min)   I(max)
-3.3V     -18.6mA    -20.81mA   -19.02mA
-1.8V     -18.28mA   -20.42mA   -18.51mA
-800mV    -14.6mA    -15.11mA   -14.93mA
-500mV    -10.62mA   -10.65mA   -11.15mA
300mV     5.935mA    5.64mA     6.461mA
600mV     10.11mA    9.593mA    11.07mA
1V        13.29mA    12.61mA    14.67mA
1.6V      14.47mA    13.77mA    16.03mA
4V        15.35mA    14.88mA    16.96mA
4.4V      16.98mA    15.9mA     17.55mA
5.5V      19.73mA    18.58mA    21.93mA
6.6V      27.17mA    25.38mA    30.2mA
[Pullup]
|Voltage   I(typ)   I(min)   I(max)
-3.3V     38.88mA    51.97mA    31.8mA
-2.3V     28.24mA    35.26mA    24.04mA
-1.4V     17.75mA    19.49mA    16.05mA
-1.2V     17.75mA    19.49mA    16.05mA
-1.1V     14.02mA    15.27mA    12.72mA
-1V       12.32mA    13.05mA    11.34mA
-800mV    9.472mA    9.998mA    9.043mA
100mV     -1.105mA   -1.087mA   -1.135mA
900mV     -7.971mA   -7.948mA   -8.143mA
1.6V      -11.44mA   -11.5mA    -11.68mA
2.3V      -12.96mA   -13.07mA   -13.27mA
6.6V      -14.93mA   -15.08mA   -15.27mA
[GND_clamp]
|Voltage   I(typ)   I(min)   I(max)
-3.3V     -912.7mA   -861.5mA   -922.5mA
-1.27V    -145.6mA   -163.6mA   -123.5mA
-1.2V     -123.4mA   -142.6mA   -101.4mA
-1.13V    -102mA     -122.4mA   -80.37mA
-1.06V    -81.56mA   -103.5mA   -60.64mA
-920mV    -44.4mA    -68.93mA   -27.87mA
-780mV    -16.18mA   -38.86mA   -11.24mA
-710mV    -7.839mA   -26.12mA   -7.318mA
-570mV    -1.464mA   -7.654mA   -1.852mA
-430mV    -105.8uA   -801.1uA   -99.73uA
-290mV    -1.56uA    -33.42uA   -868.4nA
3.28V     0A         0A         0A
[POWER_clamp]
|Voltage   I(typ)   I(min)   I(max)
-3.28V    471.5mA    421.2mA    516.6mA
-1.18V    71.72mA    72.75mA    72.14mA
-1.11V    60.88mA    63.98mA    59.38mA
-970mV    39.73mA    47.46mA    34.21mA
-900mV    29.12mA    39.28mA    24.89mA
-830mV    19.01mA    30.67mA    18.7mA
-760mV    11.8mA     22.01mA    13.51mA
-620mV    4.416mA    6.921mA    5.219mA
-550mV    2.174mA    2.865mA    2.414mA
-480mV    813uA      1.102mA    758.3uA
-200mV    3.62uA     22.61uA    424nA
3.3V      0A         0A         0A
[Ramp]
| variable   typ   min   max
dV/dt_r   0.399/1.202n   0.398/1.651n   0.412/0.445n
dV/dt_f   0.444/0.612n   0.423/0.595n   0.492/0.683n
R_load = 50.000
[Rising Waveform]
R_fixture= 50.000
V_fixture= 0.0
V_fixture_min= 0.0
V_fixture_max= 0.0
|time   V(typ)   V(min)   V(max)
0s        0V         0V         0V
367ps     -7.376mV   -431.1uV   -6.563mV
605ps     66.33mV    6.043mV    4.674mV
977ps     129mV      190.3mV    38.09mV
1.131ns   136.3mV    245.5mV    132.1mV
1.584ns   159.3mV    292.8mV    553.5mV
2.031ns   377.9mV    342.6mV    668.4mV
2.488ns   607.6mV    504.4mV    680.9mV
3.238ns   658.6mV    648.1mV    682.2mV
10ns      659.9mV    657.9mV    682.3mV
[Rising Waveform]
R_fixture= 50.000
V_fixture= 3.300
V_fixture_min= 3.140
V_fixture_max= 3.470
|time   V(typ)   V(min)   V(max)
0s        2.557V     2.433V     2.659V
239ps     2.557V     2.433V     2.665V
436ps     2.803V     2.443V     3.024V
601ps     2.97V      2.709V     3.149V
607ps     2.974V     2.716V     3.373V
631ps     2.988V     2.743V     3.384V
637ps     3.2V       2.749V     3.387V
768ps     3.252V     3.042V     3.428V
950ps     3.282V     3.104V     3.454V
10ns      3.3V       3.14V      3.47V
[Falling Waveform]
R_fixture= 50.000
V_fixture= 3.300
V_fixture_min= 3.140
V_fixture_max= 3.470
|time   V(typ)   V(min)   V(max)
0s        3.3V       3.14V      3.47V
580ps     3.276V     3.153V     3.417V
662ps     3.241V     3.147V     3.373V
735ps     3.202V     3.13V      3.112V
742ps     2.988V     3.128V     3.108V
766ps     2.975V     3.12V      3.094V
933ps     2.876V     3.042V     2.998V
943ps     2.871V     2.838V     2.993V
1.853ns   2.575V     2.469V     2.678V
10ns      2.557V     2.433V     2.659V
[Falling Waveform]
R_fixture= 50.000
V_fixture= 0.0
V_fixture_min= 0.0
V_fixture_max= 0.0
|time   V(typ)   V(min)   V(max)
0s        659.9mV    657.9mV    682.3mV
250ps     661.3mV    657.8mV    663.2mV
340ps     620.2mV    660mV      541.3mV
433ps     485.3mV    638.9mV    379.2mV
566ps     280.9mV    491.7mV    184mV
695ps     132.4mV    309.6mV    77.35mV
842ps     47.59mV    153.4mV    25.65mV
982ps     16.85mV    64.98mV    8.653mV
1.599ns   551.2uV    1.455mV    572.8uV
10ns      0V         0V         0V
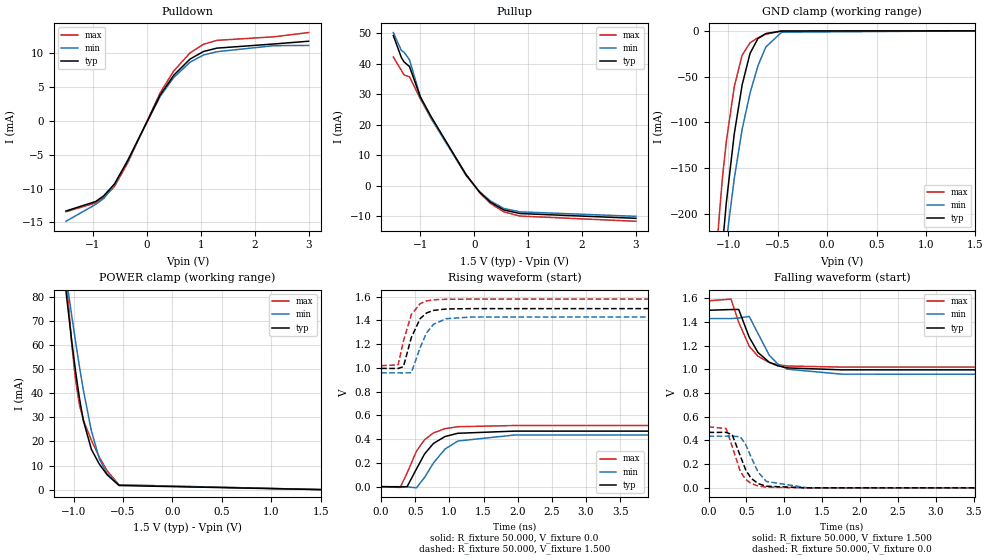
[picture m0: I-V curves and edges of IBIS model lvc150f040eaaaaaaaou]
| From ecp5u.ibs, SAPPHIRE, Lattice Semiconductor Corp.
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|   Model lvc150f040eaaaaaaaou
[Model] lvc150f040eaaaaaaaou
Model_type  Output
Polarity   Non-Inverting
Enable   Active-Low
Vmeas =  0.750V
Cref =  0.0F
Rref =  1.000M
Vref =  0.0V
C_comp   5.000pF   4.000pF   5.500pF
[Temperature Range]   25.000   0.125k   -40.000
[Voltage Range]   1.500V   1.430V   1.580V
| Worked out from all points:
|   slope of the pulldown table from 0 to 0.225 V, typ, clamps not added: 64.1 ohm
|   slope of the pullup table from 0 to 0.225 V, typ, clamps not added: 53.1 ohm
|   GND clamp passes 1 mA (typ) near -0.54 V on its own axis
|   POWER clamp passes 1 mA (typ) near -0.51 V on its own axis
|   rising waveform, R_fixture 50.000, V_fixture 0.0: 20-80 % time 317ps typ, 362ps min, 294ps max; typ from 0 V to 0.468 V
|   rising waveform, R_fixture 50.000, V_fixture 1.500: 20-80 % time 182ps typ, 204ps min, 165ps max; typ from 0.996 V to 1.5 V
|   falling waveform, R_fixture 50.000, V_fixture 1.500: 20-80 % time 258ps typ, 268ps min, 252ps max; typ from 1.5 V to 0.996 V
|   falling waveform, R_fixture 50.000, V_fixture 0.0: 20-80 % time 180ps typ, 202ps min, 166ps max; typ from 0.468 V to 0 V
[Pulldown]
|Voltage   I(typ)   I(min)   I(max)
-1.5V     -13.32mA   -14.84mA   -13.43mA
-950mV    -11.92mA   -12.35mA   -12.12mA
-800mV    -11.08mA   -11.47mA   -11.33mA
-600mV    -9.319mA   -9.44mA    -9.695mA
-350mV    -5.803mA   -5.742mA   -6.134mA
250mV     3.854mA    3.663mA    4.191mA
500mV     6.752mA    6.411mA    7.382mA
800mV     9.128mA    8.66mA     10.04mA
1.05V     10.25mA    9.731mA    11.32mA
1.3V      10.75mA    10.22mA    11.9mA
2.35V     11.36mA    11.11mA    12.42mA
3V        11.77mA    11.15mA    13.05mA
[Pullup]
|Voltage   I(typ)   I(min)   I(max)
-1.5V     49.23mA    50.22mA    42.21mA
-1.35V    42.01mA    44.34mA    37.85mA
-1.3V     40.58mA    43.78mA    36.33mA
-1.2V     39.1mA     41.31mA    35.73mA
-1V       29.18mA    29.26mA    28.54mA
-800mV    22.71mA    22.15mA    22.13mA
-150mV    3.599mA    3.377mA    3.778mA
100mV     -2.069mA   -1.907mA   -2.229mA
300mV     -5.343mA   -4.965mA   -5.748mA
550mV     -7.913mA   -7.416mA   -8.541mA
850mV     -9.084mA   -8.539mA   -9.917mA
3V        -10.65mA   -9.997mA   -11.63mA
[GND_clamp]
|Voltage   I(typ)   I(min)   I(max)
-1.5V     -960.1mA   -762.7mA   -1.034A
-1.14V    -347.3mA   -346mA     -275mA
-1.1V     -290.2mA   -305.8mA   -213.7mA
-1.06V    -236.5mA   -267.1mA   -161mA
-1.02V    -187.7mA   -229.9mA   -120.7mA
-940mV    -112.8mA   -161.5mA   -61.34mA
-860mV    -59.06mA   -107.5mA   -26.59mA
-780mV    -24.6mA    -67.97mA   -13.06mA
-700mV    -8.431mA   -38.1mA    -7.531mA
-620mV    -2.969mA   -17.61mA   -3.668mA
-460mV    -207.8uA   -1.521mA   -211uA
1.5V      0A         0A         0A
[POWER_clamp]
|Voltage   I(typ)   I(min)   I(max)
-1.5V     267.6mA    236.4mA    479.7mA
-1.1V     90.92mA    95.54mA    105.5mA
-1.06V    76.14mA    83.93mA    81.29mA
-1.02V    62.03mA    72.49mA    60.96mA
-980mV    49.07mA    61.38mA    45.36mA
-940mV    37.73mA    50.83mA    34.98mA
-900mV    28.44mA    41.02mA    28.75mA
-820mV    16.72mA    24.41mA    20.46mA
-740mV    10.6mA     12.83mA    13.51mA
-660mV    6.131mA    6.445mA    7.75mA
-540mV    1.697mA    1.964mA    1.966mA
1.5V      0A         0A         0A
[Ramp]
| variable   typ   min   max
dV/dt_r 0.281/0.323n   0.262/0.368n   0.309/0.293n
dV/dt_f 0.302/0.255n   0.283/0.270n   0.336/0.259n
R_load = 50.000
[Rising Waveform]
R_fixture= 50.000
V_fixture= 0.0
V_fixture_min= 0.0
V_fixture_max= 0.0
|time   V(typ)   V(min)   V(max)
0s        0V         0V         0V
279ps     -1.973mV   -251.2uV   -6.683mV
380ps     -192.6uV   -1.235mV   115.3mV
517ps     149.3mV    -10.2mV    298.9mV
635ps     274.9mV    77.17mV    394.8mV
766ps     364mV      199.9mV    452.9mV
935ps     422.2mV    316.8mV    488.7mV
1.123ns   449.7mV    384.5mV    505mV
1.955ns   467.9mV    435.2mV    515.1mV
10ns      468.2mV    436.6mV    515.3mV
[Rising Waveform]
R_fixture= 50.000
V_fixture= 1.500
V_fixture_min= 1.430
V_fixture_max= 1.580
|time   V(typ)   V(min)   V(max)
0s        996.4mV    958.9mV    1.019V
248ps     995.7mV    958.9mV    1.026V
326ps     1.011V     958.4mV    1.227V
441ps     1.255V     959.5mV    1.449V
571ps     1.416V     1.171V     1.542V
664ps     1.463V     1.295V     1.565V
765ps     1.485V     1.367V     1.574V
954ps     1.497V     1.415V     1.579V
1.311ns   1.5V       1.429V     1.58V
10ns      1.5V       1.43V      1.58V
[Falling Waveform]
R_fixture= 50.000
V_fixture= 1.500
V_fixture_min= 1.430
V_fixture_max= 1.580
|time   V(typ)   V(min)   V(max)
0s        1.5V       1.43V      1.58V
296ps     1.506V     1.43V      1.594V
398ps     1.507V     1.434V     1.399V
537ps     1.273V     1.448V     1.196V
652ps     1.144V     1.305V     1.112V
801ps     1.061V     1.121V     1.059V
911ps     1.031V     1.048V     1.04V
1.042ns   1.013V     1.002V     1.029V
1.762ns   996.8mV    960.1mV    1.02V
10ns      996.4mV    958.9mV    1.019V
[Falling Waveform]
R_fixture= 50.000
V_fixture= 0.0
V_fixture_min= 0.0
V_fixture_max= 0.0
|time   V(typ)   V(min)   V(max)
0s        468.2mV    436.6mV    515.3mV
232ps     468.8mV    436.6mV    501.1mV
313ps     448.7mV    436.4mV    348.2mV
420ps     269.1mV    431.4mV    138.2mV
491ps     150.9mV    365.5mV    71.45mV
561ps     81.96mV    261.7mV    37.17mV
654ps     36.04mV    132.8mV    15.58mV
764ps     13.72mV    53.94mV    5.567mV
1.301ns   166.2uV    926.7uV    41.53uV
10ns      0V         0V         0V
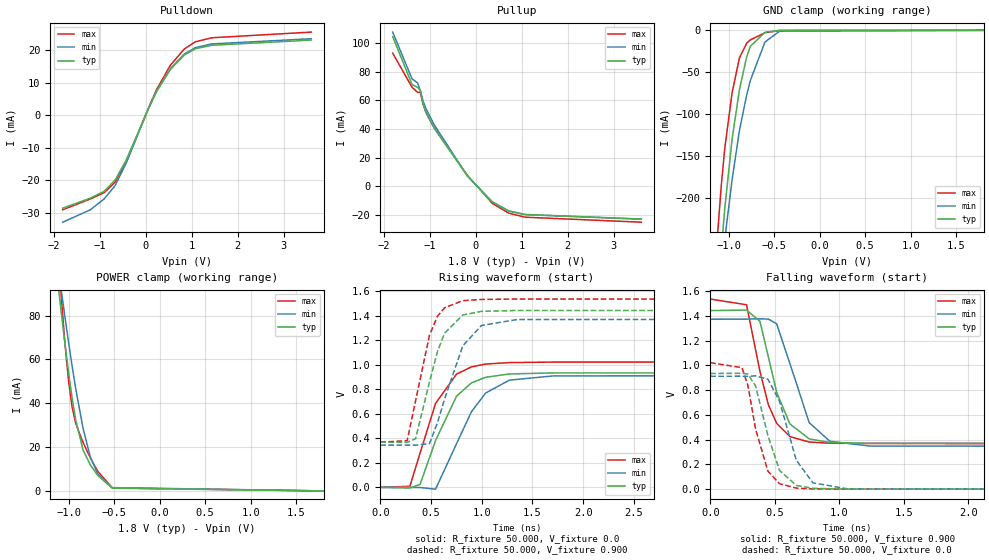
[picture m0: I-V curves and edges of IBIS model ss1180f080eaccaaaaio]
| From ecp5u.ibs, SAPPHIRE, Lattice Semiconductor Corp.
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|   Model ss1180f080eaccaaaaio
| Clamp models does not include dynamic input termination. Please
| use correspodent INPUT models to simulate input termination.
[Model] ss1180f080eaccaaaaio
Model_type I/O
Polarity   Non-Inverting
Enable   Active-Low
Vinl =  0.775V
Vinh =  1.025V
Vmeas =  0.900V
Cref =  30.000pF
Rref =  50.000
Vref =  0.900V
C_comp   5.000pF   4.000pF   5.500pF
[Temperature Range]   25.000   0.125k   -40.000
[Voltage Range]   1.800V   1.710V   1.890V
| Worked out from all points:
|   slope of the pulldown table from 0 to 0.27 V, typ, clamps not added: 33.1 ohm
|   slope of the pullup table from 0 to 0.27 V, typ, clamps not added: 31.2 ohm
|   GND clamp passes 1 mA (typ) near -0.54 V on its own axis
|   POWER clamp passes 1 mA (typ) near -0.51 V on its own axis
|   rising waveform, R_fixture 50.000, V_fixture 0.0: 20-80 % time 287ps typ, 325ps min, 262ps max; typ from 0 V to 0.934 V
|   rising waveform, R_fixture 50.000, V_fixture 0.900: 20-80 % time 209ps typ, 249ps min, 185ps max; typ from 0.369 V to 1.44 V
|   falling waveform, R_fixture 50.000, V_fixture 0.900: 20-80 % time 167ps typ, 179ps min, 155ps max; typ from 1.44 V to 0.369 V
|   falling waveform, R_fixture 50.000, V_fixture 0.0: 20-80 % time 140ps typ, 159ps min, 125ps max; typ from 0.934 V to 0 V
[Pulldown]
|Voltage   I(typ)   I(min)   I(max)
-1.8V     -28.53mA   -32.84mA   -29.01mA
-1.2V     -25.46mA   -29.03mA   -25.7mA
-900mV    -23.35mA   -25.68mA   -23.75mA
-660mV    -19.84mA   -21.55mA   -20.51mA
-420mV    -13.7mA    -14.59mA   -14.42mA
60mV      2.026mA    2.064mA    2.192mA
240mV     7.384mA    7.52mA     8.023mA
540mV     14.17mA    14.41mA    15.5mA
840mV     18.59mA    18.89mA    20.45mA
1.08V     20.52mA    20.88mA    22.66mA
1.44V     21.61mA    22.02mA    23.91mA
3.6V      23.2mA     23.62mA    25.66mA
[Pullup]
|Voltage   I(typ)   I(min)   I(max)
-1.8V     104.5mA    107.6mA    92.84mA
-1.38V    70.9mA     74.9mA     69.09mA
-1.26V    68.99mA    72.12mA    65.48mA
-1.2V     66.93mA    66.81mA    65.48mA
-1.14V    57.38mA    59.48mA    57.36mA
-1.08V    51.83mA    54.35mA    51.48mA
-900mV    40.67mA    42.94mA    40.69mA
-180mV    7.161mA    7.234mA    7.646mA
360mV     -10.95mA   -10.92mA   -11.94mA
720mV     -17.31mA   -17.4mA    -18.86mA
1.08V     -19.76mA   -19.89mA   -21.68mA
3.6V      -22.97mA   -23.08mA   -25.16mA
[GND_clamp]
|Voltage   I(typ)   I(min)   I(max)
-1.8V     -1.552A    -1.161A    -1.853A
-1.16V    -376.9mA   -366.7mA   -307.6mA
-1.12V    -318.4mA   -325.7mA   -243.6mA
-1.08V    -262.9mA   -286.2mA   -185.9mA
-1.04V    -211.3mA   -248.3mA   -139.6mA
-960mV    -129.1mA   -177.6mA   -73.98mA
-880mV    -70.75mA   -119.2mA   -32.93mA
-800mV    -31.34mA   -76.89mA   -15.17mA
-760mV    -19.02mA   -59.64mA   -11.38mA
-600mV    -2.287mA   -13.94mA   -2.904mA
-440mV    -132uA     -1.017mA   -127uA
1.8V      0A         0A         0A
[POWER_clamp]
|Voltage   I(typ)   I(min)   I(max)
-1.8V     409.3mA    360.5mA    777.8mA
-1.12V    96.26mA    103.8mA    113.3mA
-1.08V    81.67mA    91.65mA    88.95mA
-1.04V    67.47mA    79.6mA     67.7mA
-1V       54.18mA    67.94mA    50.47mA
-960mV    42.26mA    56.81mA    38.14mA
-920mV    32.14mA    46.41mA    30.63mA
-840mV    18.58mA    28.47mA    22.09mA
-760mV    11.83mA    15.41mA    15.04mA
-680mV    7.109mA    7.763mA    9.014mA
-520mV    1.243mA    1.515mA    1.386mA
1.8V      0A         0A         0A
[Ramp]
| variable   typ   min   max
dV/dt_r 0.561/0.291n   0.547/0.326n   0.613/0.263n
dV/dt_f 0.564/0.228n   0.550/0.234n   0.620/0.216n
R_load = 50.000
[Rising Waveform]
R_fixture= 50.000
V_fixture= 0.0
V_fixture_min= 0.0
V_fixture_max= 0.0
|time   V(typ)   V(min)   V(max)
0s        0V         0V         0V
292ps     -4.86mV    -190.7uV   9.259mV
392ps     24.06mV    -902.6uV   278.6mV
545ps     382.2mV    -14.42mV   684.7mV
752ps     744.1mV    356.4mV    924.1mV
898ps     851.8mV    616mV      982.6mV
1.038ns   898.1mV    769.1mV    1.006V
1.272ns   925.2mV    874.8mV    1.018V
1.704ns   933.6mV    909.1mV    1.022V
10ns      934.5mV    912.4mV    1.022V
[Rising Waveform]
R_fixture= 50.000
V_fixture= 0.900
V_fixture_min= 0.856
V_fixture_max= 0.946
|time   V(typ)   V(min)   V(max)
0s        369.2mV    344.8mV    368.5mV
265ps     367.6mV    344.8mV    381.3mV
348ps     397.2mV    344.3mV    706.5mV
485ps     859.5mV    357mV      1.241V
564ps     1.109V     528.3mV    1.396V
634ps     1.258V     720.9mV    1.465V
813ps     1.406V     1.154V     1.523V
998ps     1.436V     1.321V     1.533V
1.348ns   1.443V     1.369V     1.536V
10ns      1.443V     1.373V     1.536V
[Falling Waveform]
R_fixture= 50.000
V_fixture= 0.900
V_fixture_min= 0.856
V_fixture_max= 0.946
|time   V(typ)   V(min)   V(max)
0s        1.443V     1.373V     1.536V
281ps     1.447V     1.374V     1.49V
385ps     1.356V     1.377V     952.6mV
450ps     1.07V      1.374V     683.4mV
515ps     781.1mV    1.336V     531mV
617ps     527.2mV    1.016V     424.7mV
767ps     406.1mV    537.3mV    380.8mV
927ps     377.7mV    386.9mV    371.3mV
1.237ns   370.2mV    348.3mV    368.8mV
10ns      369.2mV    344.8mV    368.5mV
[Falling Waveform]
R_fixture= 50.000
V_fixture= 0.0
V_fixture_min= 0.0
V_fixture_max= 0.0
|time   V(typ)   V(min)   V(max)
0s        934.5mV    912.4mV    1.022V
246ps     936.4mV    912.5mV    981.5mV
292ps     930.1mV    911.7mV    836.5mV
351ps     833.7mV    915.7mV    486.3mV
447ps     432.2mV    888.4mV    144.9mV
537ps     151.3mV    709.7mV    43.85mV
667ps     30.08mV    233.8mV    8.455mV
796ps     6.839mV    50.87mV    2.073mV
1.06ns    835.9uV    3.264mV    272.9uV
10ns      0V         0V         0V
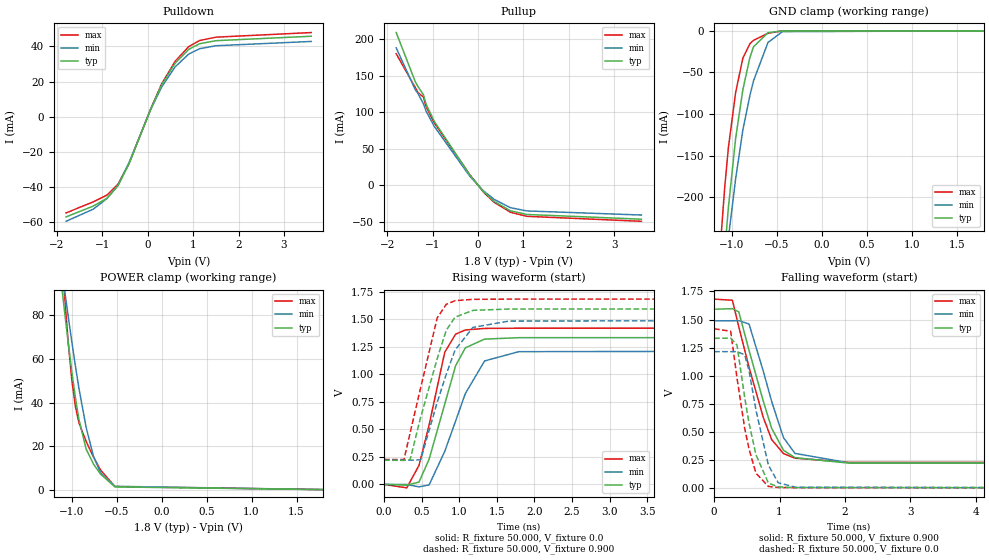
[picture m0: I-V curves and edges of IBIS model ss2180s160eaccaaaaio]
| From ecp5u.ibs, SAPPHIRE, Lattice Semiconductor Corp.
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|   Model ss2180s160eaccaaaaio
| Clamp models does not include dynamic input termination. Please
| use correspodent INPUT models to simulate input termination.
[Model] ss2180s160eaccaaaaio
Model_type I/O
Polarity   Non-Inverting
Enable   Active-Low
Vinl =  0.775V
Vinh =  1.025V
Vmeas =  0.900V
Cref =  30.000pF
Rref =  50.000
Vref =  0.900V
C_comp   5.000pF   4.000pF   5.500pF
[Temperature Range]   25.000   0.125k   -40.000
[Voltage Range]   1.800V   1.710V   1.890V
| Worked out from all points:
|   slope of the pulldown table from 0 to 0.27 V, typ, clamps not added: 16.6 ohm
|   slope of the pullup table from 0 to 0.27 V, typ, clamps not added: 15.6 ohm
|   GND clamp passes 1 mA (typ) near -0.54 V on its own axis
|   POWER clamp passes 1 mA (typ) near -0.51 V on its own axis
|   rising waveform, R_fixture 50.000, V_fixture 0.0: 20-80 % time 327ps typ, 398ps min, 264ps max; typ from 0 V to 1.33 V
|   rising waveform, R_fixture 50.000, V_fixture 0.900: 20-80 % time 339ps typ, 362ps min, 291ps max; typ from 0.219 V to 1.59 V
|   falling waveform, R_fixture 50.000, V_fixture 0.900: 20-80 % time 411ps typ, 381ps min, 420ps max; typ from 1.59 V to 0.219 V
|   falling waveform, R_fixture 50.000, V_fixture 0.0: 20-80 % time 246ps typ, 251ps min, 240ps max; typ from 1.33 V to 0 V
[Pulldown]
|Voltage   I(typ)   I(min)   I(max)
-1.8V     -57.26mA   -59.78mA   -54.99mA
-1.2V     -51.09mA   -52.83mA   -48.7mA
-900mV    -46.65mA   -46.82mA   -44.83mA
-660mV    -39.62mA   -39.31mA   -38.72mA
-420mV    -27.34mA   -26.64mA   -27.21mA
60mV      4.04mA     3.769mA    4.134mA
300mV     17.85mA    16.63mA    18.36mA
600mV     30.4mA     28.29mA    31.47mA
900mV     38.31mA    35.64mA    39.89mA
1.14V     41.54mA    38.7mA     43.38mA
1.5V      43.3mA     40.41mA    45.3mA
3.6V      45.84mA    42.87mA    47.93mA
[Pullup]
|Voltage   I(typ)   I(min)   I(max)
-1.8V     208.6mA    187.7mA    179.7mA
-1.38V    141.5mA    130.5mA    133.6mA
-1.32V    134.9mA    125.4mA    126.6mA
-1.2V     123.7mA    111.3mA    120.7mA
-1.14V    110.5mA    101.2mA    107mA
-960mV    87.38mA    80.47mA    85.17mA
-180mV    14.35mA    12.65mA    14.86mA
120mV     -8.407mA   -7.262mA   -8.924mA
360mV     -21.95mA   -19.1mA    -23.21mA
720mV     -34.68mA   -30.43mA   -36.67mA
1.08V     -39.59mA   -34.77mA   -42.14mA
3.6V      -46.04mA   -40.36mA   -48.91mA
[GND_clamp]
|Voltage   I(typ)   I(min)   I(max)
-1.8V     -1.552A    -1.161A    -1.853A
-1.16V    -376.9mA   -366.7mA   -307.6mA
-1.12V    -318.4mA   -325.7mA   -243.6mA
-1.08V    -262.9mA   -286.2mA   -185.9mA
-1.04V    -211.3mA   -248.3mA   -139.6mA
-960mV    -129.1mA   -177.6mA   -73.98mA
-880mV    -70.75mA   -119.2mA   -32.93mA
-800mV    -31.34mA   -76.89mA   -15.17mA
-760mV    -19.02mA   -59.64mA   -11.38mA
-600mV    -2.287mA   -13.94mA   -2.904mA
-440mV    -132uA     -1.017mA   -127uA
1.8V      0A         0A         0A
[POWER_clamp]
|Voltage   I(typ)   I(min)   I(max)
-1.8V     409.3mA    360.5mA    777.8mA
-1.12V    96.26mA    103.8mA    113.3mA
-1.08V    81.67mA    91.65mA    88.95mA
-1.04V    67.47mA    79.6mA     67.7mA
-1V       54.18mA    67.94mA    50.47mA
-960mV    42.26mA    56.81mA    38.14mA
-920mV    32.14mA    46.41mA    30.63mA
-840mV    18.58mA    28.47mA    22.09mA
-760mV    11.83mA    15.41mA    15.04mA
-680mV    7.109mA    7.763mA    9.014mA
-520mV    1.243mA    1.515mA    1.386mA
1.8V      0A         0A         0A
[Ramp]
| variable   typ   min   max
dV/dt_r 0.561/0.379n   0.497/0.474n   0.601/0.298n
dV/dt_f 0.563/0.542n   0.519/0.492n   0.597/0.598n
R_load = 25.000
[Rising Waveform]
R_fixture= 50.000
V_fixture= 0.0
V_fixture_min= 0.0
V_fixture_max= 0.0
|time   V(typ)   V(min)   V(max)
0s        0V         0V         0V
303ps     -7.224mV   -354uV     -31.43mV
466ps     21.13mV    -22.53mV   172.5mV
600ps     228.3mV    -4.83mV    539.6mV
808ps     729.2mV    299.7mV    1.2V
952ps     1.077V     575.1mV    1.364V
1.082ns   1.24V      825.1mV    1.402V
1.338ns   1.319V     1.121V     1.416V
1.792ns   1.332V     1.205V     1.418V
10ns      1.333V     1.214V     1.418V
[Rising Waveform]
R_fixture= 50.000
V_fixture= 0.900
V_fixture_min= 0.856
V_fixture_max= 0.946
|time   V(typ)   V(min)   V(max)
0s        219.4mV    220mV      226.7mV
266ps     218.1mV    219.9mV    225.1mV
347ps     223mV      219.3mV    466.1mV
488ps     609.8mV    223.5mV    878mV
708ps     1.142V     745.8mV    1.512V
827ps     1.398V     997.4mV    1.634V
945ps     1.518V     1.22V      1.668V
1.182ns   1.58V      1.425V     1.68V
1.662ns   1.592V     1.483V     1.682V
10ns      1.592V     1.489V     1.682V
[Falling Waveform]
R_fixture= 50.000
V_fixture= 0.900
V_fixture_min= 0.856
V_fixture_max= 0.946
|time   V(typ)   V(min)   V(max)
0s        1.592V     1.489V     1.682V
280ps     1.597V     1.489V     1.672V
378ps     1.568V     1.491V     1.434V
534ps     1.226V     1.46V      1.075V
750ps     776mV      1.044V     631.2mV
880ps     530.8mV    770.1mV    430.3mV
1.06ns    335.5mV    448.1mV    305.9mV
1.236ns   269.4mV    307.1mV    264.7mV
2.06ns    220.5mV    222.9mV    227.3mV
10ns      219.4mV    220mV      226.7mV
[Falling Waveform]
R_fixture= 50.000
V_fixture= 0.0
V_fixture_min= 0.0
V_fixture_max= 0.0
|time   V(typ)   V(min)   V(max)
0s        1.333V     1.214V     1.418V
254ps     1.334V     1.214V     1.396V
350ps     1.273V     1.214V     980.7mV
468ps     804.8mV    1.186V     529.5mV
534ps     576mV      1.045V     346.2mV
640ps     295.6mV    693mV      130.3mV
830ps     42.57mV    202.3mV    12.61mV
980ps     8.364mV    45.18mV    3.366mV
1.25ns    2.599mV    5.397mV    1.64mV
10ns      0V         0V         0V
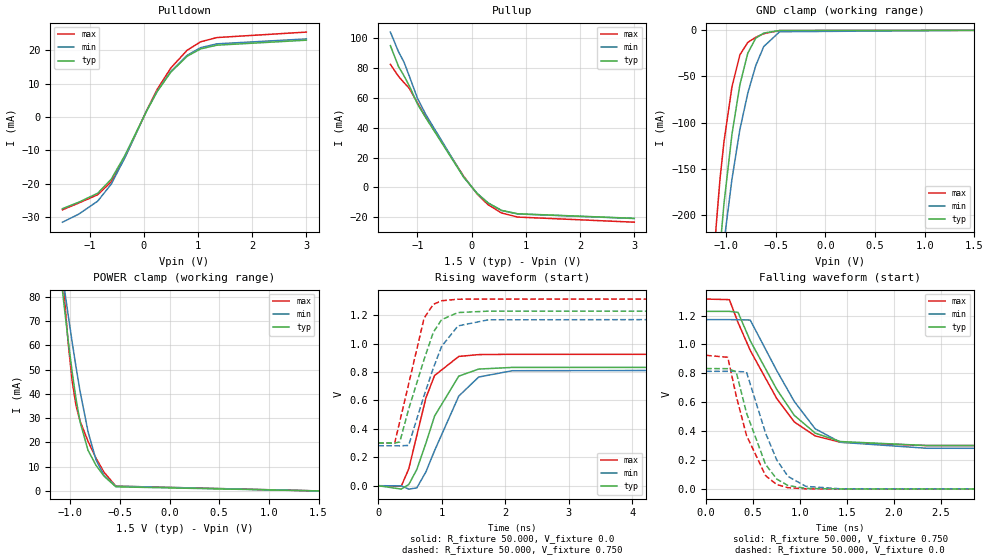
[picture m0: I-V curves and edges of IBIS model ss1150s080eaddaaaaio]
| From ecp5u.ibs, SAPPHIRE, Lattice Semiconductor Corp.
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|   Model ss1150s080eaddaaaaio
| Clamp models does not include dynamic input termination. Please
| use correspodent INPUT models to simulate input termination.
[Model] ss1150s080eaddaaaaio
Model_type I/O
Polarity   Non-Inverting
Enable   Active-Low
Vinl =  0.650V
Vinh =  0.850V
Vmeas =  0.750V
Cref =  30.000pF
Rref =  50.000
Vref =  0.750V
C_comp   5.000pF   4.000pF   5.500pF
[Temperature Range]   25.000   0.125k   -40.000
[Voltage Range]   1.500V   1.430V   1.580V
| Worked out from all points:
|   slope of the pulldown table from 0 to 0.225 V, typ, clamps not added: 32.3 ohm
|   slope of the pullup table from 0 to 0.225 V, typ, clamps not added: 27.3 ohm
|   GND clamp passes 1 mA (typ) near -0.54 V on its own axis
|   POWER clamp passes 1 mA (typ) near -0.51 V on its own axis
|   rising waveform, R_fixture 50.000, V_fixture 0.0: 20-80 % time 409ps typ, 487ps min, 327ps max; typ from 0 V to 0.834 V
|   rising waveform, R_fixture 50.000, V_fixture 0.750: 20-80 % time 390ps typ, 414ps min, 306ps max; typ from 0.301 V to 1.23 V
|   falling waveform, R_fixture 50.000, V_fixture 0.750: 20-80 % time 513ps typ, 488ps min, 521ps max; typ from 1.23 V to 0.301 V
|   falling waveform, R_fixture 50.000, V_fixture 0.0: 20-80 % time 257ps typ, 268ps min, 254ps max; typ from 0.834 V to 0 V
[Pulldown]
|Voltage   I(typ)   I(min)   I(max)
-1.5V     -27.39mA   -31.43mA   -27.72mA
-1.2V     -25.46mA   -29.03mA   -25.7mA
-850mV    -22.78mA   -25.14mA   -23.23mA
-600mV    -18.58mA   -20.07mA   -19.34mA
-350mV    -11.53mA   -12.21mA   -12.18mA
50mV      1.697mA    1.729mA    1.836mA
250mV     7.652mA    7.792mA    8.316mA
500mV     13.41mA    13.64mA    14.65mA
800mV     18.13mA    18.42mA    19.93mA
1.05V     20.35mA    20.7mA     22.46mA
1.35V     21.45mA    21.85mA    23.73mA
3V        22.94mA    23.32mA    25.36mA
[Pullup]
|Voltage   I(typ)   I(min)   I(max)
-1.5V     95.01mA    104.1mA    82.46mA
-1.35V    81.01mA    90.92mA    74.41mA
-1.25V    74.86mA    84.05mA    70.27mA
-1.15V    68.02mA    74.47mA    66.36mA
-1V       55.88mA    59.73mA    56.56mA
-850mV    46.85mA    49.11mA    47.35mA
-150mV    6.997mA    7.036mA    7.57mA
100mV     -4.023mA   -3.974mA   -4.467mA
300mV     -10.39mA   -10.34mA   -11.52mA
550mV     -15.39mA   -15.45mA   -17.12mA
850mV     -17.67mA   -17.8mA    -19.88mA
3V        -20.72mA   -20.84mA   -23.31mA
[GND_clamp]
|Voltage   I(typ)   I(min)   I(max)
-1.5V     -960.1mA   -762.7mA   -1.034A
-1.14V    -347.3mA   -346mA     -275mA
-1.1V     -290.2mA   -305.8mA   -213.7mA
-1.06V    -236.5mA   -267.1mA   -161mA
-1.02V    -187.7mA   -229.9mA   -120.7mA
-940mV    -112.8mA   -161.5mA   -61.34mA
-860mV    -59.06mA   -107.5mA   -26.59mA
-780mV    -24.6mA    -67.97mA   -13.06mA
-700mV    -8.431mA   -38.1mA    -7.531mA
-620mV    -2.969mA   -17.61mA   -3.668mA
-460mV    -207.8uA   -1.521mA   -211uA
1.5V      0A         0A         0A
[POWER_clamp]
|Voltage   I(typ)   I(min)   I(max)
-1.5V     267.6mA    236.4mA    479.7mA
-1.1V     90.92mA    95.54mA    105.5mA
-1.06V    76.14mA    83.93mA    81.29mA
-1.02V    62.03mA    72.49mA    60.96mA
-980mV    49.07mA    61.38mA    45.36mA
-940mV    37.73mA    50.83mA    34.98mA
-900mV    28.44mA    41.02mA    28.75mA
-820mV    16.72mA    24.41mA    20.46mA
-740mV    10.6mA     12.83mA    13.51mA
-660mV    6.131mA    6.445mA    7.75mA
-540mV    1.697mA    1.964mA    1.966mA
1.5V      0A         0A         0A
[Ramp]
| variable   typ   min   max
dV/dt_r 0.500/0.414n   0.489/0.489n   0.555/0.333n
dV/dt_f 0.494/0.536n   0.480/0.488n   0.542/0.578n
R_load = 50.000
[Rising Waveform]
R_fixture= 50.000
V_fixture= 0.0
V_fixture_min= 0.0
V_fixture_max= 0.0
|time   V(typ)   V(min)   V(max)
0s        0V         0V         0V
363ps     -23.75mV   -946.7uV   -3.677mV
482ps     8.458mV    -24.36mV   119.4mV
608ps     114.1mV    -15.2mV    353.8mV
752ps     300.3mV    97.8mV     619.1mV
888ps     490.4mV    247.2mV    775.9mV
1.269ns   771.5mV    630.9mV    910.1mV
1.582ns   821.1mV    765.1mV    923mV
2.112ns   832.8mV    809.6mV    925.1mV
10ns      833.6mV    814.4mV    925.1mV
[Rising Waveform]
R_fixture= 50.000
V_fixture= 0.750
V_fixture_min= 0.713
V_fixture_max= 0.789
|time   V(typ)   V(min)   V(max)
0s        301.2mV    281.5mV    301mV
260ps     300.2mV    281.4mV    300.5mV
340ps     308.1mV    280.7mV    452mV
479ps     538.3mV    283.7mV    714.6mV
723ps     889.4mV    635.7mV    1.18V
868ps     1.08V      827.7mV    1.277V
998ps     1.169V     980mV      1.302V
1.256ns   1.219V     1.125V     1.313V
1.736ns   1.229V     1.168V     1.314V
10ns      1.229V     1.172V     1.314V
[Falling Waveform]
R_fixture= 50.000
V_fixture= 0.750
V_fixture_min= 0.713
V_fixture_max= 0.789
|time   V(typ)   V(min)   V(max)
0s        1.229V     1.172V     1.314V
248ps     1.229V     1.172V     1.31V
340ps     1.222V     1.171V     1.152V
470ps     1.026V     1.169V     959mV
752ps     690.4mV    820.3mV    627mV
939ps     510.4mV    606.7mV    464.7mV
1.162ns   387.4mV    417.4mV    368.2mV
1.429ns   329.2mV    324.2mV    324.5mV
2.352ns   301.6mV    282.7mV    301.2mV
10ns      301.2mV    281.5mV    301mV
[Falling Waveform]
R_fixture= 50.000
V_fixture= 0.0
V_fixture_min= 0.0
V_fixture_max= 0.0
|time   V(typ)   V(min)   V(max)
0s        833.6mV    814.4mV    925.1mV
231ps     832.8mV    814.4mV    911.5mV
320ps     811.6mV    813.8mV    647mV
430ps     527.6mV    810mV      372.1mV
633ps     171.4mV    388.3mV    93.83mV
753ps     69.6mV     201.4mV    31.63mV
873ps     24.99mV    87.94mV    10.05mV
1.063ns   5.317mV    19.35mV    2.432mV
1.429ns   1.35mV     2.584mV    1.049mV
10ns      0V         0V         0V
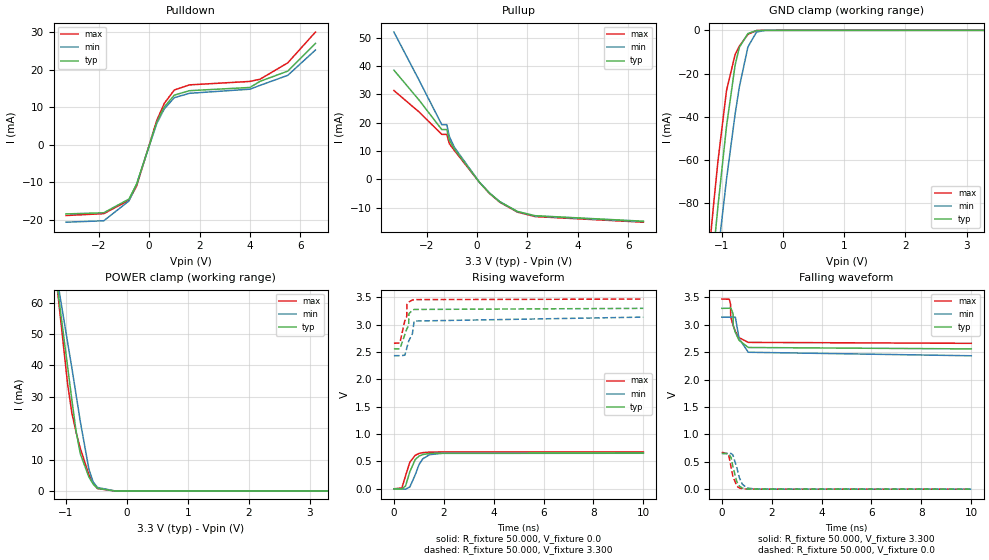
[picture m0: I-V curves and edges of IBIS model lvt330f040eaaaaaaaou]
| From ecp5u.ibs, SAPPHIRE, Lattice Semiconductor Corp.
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|   Model lvt330f040eaaaaaaaou
[Model] lvt330f040eaaaaaaaou
Model_type  Output
Polarity   Non-Inverting
Enable   Active-Low
Vmeas =  1.650V
Cref =  0.0F
Rref =  1.000M
Vref =  0.0V
C_comp   5.000pF   4.000pF   5.500pF
[Temperature Range]   25.000   0.125k   -40.000
[Voltage Range]   3.300V   3.140V   3.470V
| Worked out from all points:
|   slope of the pulldown table from 0 to 0.495 V, typ, clamps not added: 56.4 ohm
|   slope of the pullup table from 0 to 0.495 V, typ, clamps not added: 102 ohm
|   GND clamp passes 1 mA (typ) near -0.54 V on its own axis
|   POWER clamp passes 1 mA (typ) near -0.49 V on its own axis
|   rising waveform, R_fixture 50.000, V_fixture 0.0: 20-80 % time 307ps typ, 345ps min, 291ps max; typ from 0 V to 0.652 V
|   rising waveform, R_fixture 50.000, V_fixture 3.300: 20-80 % time 218ps typ, 233ps min, 212ps max; typ from 2.56 V to 3.3 V
|   falling waveform, R_fixture 50.000, V_fixture 3.300: 20-80 % time 250ps typ, 266ps min, 250ps max; typ from 3.3 V to 2.56 V
|   falling waveform, R_fixture 50.000, V_fixture 0.0: 20-80 % time 206ps typ, 232ps min, 187ps max; typ from 0.652 V to 0 V
[Pulldown]
|Voltage   I(typ)   I(min)   I(max)
-3.3V     -18.5mA    -20.7mA    -18.92mA
-1.8V     -18.18mA   -20.32mA   -18.42mA
-800mV    -14.52mA   -15.03mA   -14.85mA
-500mV    -10.57mA   -10.59mA   -11.09mA
300mV     5.904mA    5.61mA     6.427mA
600mV     10.05mA    9.542mA    11.01mA
1V        13.22mA    12.54mA    14.59mA
1.6V      14.4mA     13.7mA     15.95mA
4V        15.26mA    14.8mA     16.87mA
4.4V      16.89mA    15.82mA    17.46mA
5.5V      19.62mA    18.49mA    21.82mA
6.6V      27.03mA    25.25mA    30.04mA
[Pullup]
|Voltage   I(typ)   I(min)   I(max)
-3.3V     38.51mA    51.93mA    31.33mA
-2.3V     27.94mA    34.95mA    23.75mA
-1.4V     17.55mA    19.28mA    15.87mA
-1.2V     17.55mA    19.28mA    15.87mA
-1.1V     13.87mA    15.1mA     12.57mA
-900mV    10.68mA    11.31mA    10.19mA
100mV     -1.093mA   -1.074mA   -1.122mA
500mV     -4.903mA   -4.858mA   -5.02mA
900mV     -7.881mA   -7.858mA   -8.052mA
1.6V      -11.31mA   -11.37mA   -11.55mA
2.3V      -12.81mA   -12.92mA   -13.12mA
6.6V      -14.76mA   -14.91mA   -15.1mA
[GND_clamp]
|Voltage   I(typ)   I(min)   I(max)
-3.3V     -912.7mA   -861.5mA   -922.5mA
-1.27V    -145.6mA   -163.6mA   -123.5mA
-1.2V     -123.4mA   -142.6mA   -101.4mA
-1.13V    -102mA     -122.4mA   -80.37mA
-1.06V    -81.56mA   -103.5mA   -60.64mA
-920mV    -44.4mA    -68.93mA   -27.87mA
-780mV    -16.18mA   -38.86mA   -11.24mA
-710mV    -7.839mA   -26.12mA   -7.318mA
-570mV    -1.464mA   -7.654mA   -1.852mA
-430mV    -105.8uA   -801.1uA   -99.73uA
-290mV    -1.56uA    -33.42uA   -868.4nA
3.28V     0A         0A         0A
[POWER_clamp]
|Voltage   I(typ)   I(min)   I(max)
-3.28V    471.5mA    421.2mA    516.6mA
-1.18V    71.72mA    72.75mA    72.14mA
-1.11V    60.88mA    63.98mA    59.38mA
-970mV    39.73mA    47.46mA    34.21mA
-900mV    29.12mA    39.28mA    24.89mA
-830mV    19.01mA    30.67mA    18.7mA
-760mV    11.8mA     22.01mA    13.51mA
-620mV    4.416mA    6.921mA    5.219mA
-550mV    2.174mA    2.865mA    2.414mA
-480mV    813uA      1.102mA    758.3uA
-200mV    3.62uA     22.61uA    424nA
3.3V      0A         0A         0A
[Ramp]
| variable   typ   min   max
dV/dt_r   0.394/0.311n   0.393/0.346n   0.407/0.292n
dV/dt_f   0.442/0.317n   0.421/0.336n   0.490/0.301n
R_load = 50.000
[Rising Waveform]
R_fixture= 50.000
V_fixture= 0.0
V_fixture_min= 0.0
V_fixture_max= 0.0
|time   V(typ)   V(min)   V(max)
0s        0V         0V         0V
319ps     -5.395mV   -79.81uV   15.87mV
467ps     52.95mV    -6.285mV   239.9mV
637ps     310.6mV    34.1mV     485.6mV
854ps     534.3mV    255.2mV    613mV
1.005ns   597.8mV    441.4mV    646.4mV
1.154ns   627.1mV    548.1mV    661.6mV
1.432ns   646.4mV    624.7mV    671.5mV
1.926ns   652mV      648.2mV    674.4mV
10ns      652.5mV    650.4mV    674.6mV
[Rising Waveform]
R_fixture= 50.000
V_fixture= 3.300
V_fixture_min= 3.140
V_fixture_max= 3.470
|time   V(typ)   V(min)   V(max)
0s        2.56V      2.435V     2.662V
238ps     2.56V      2.435V     2.666V
437ps     2.817V     2.443V     3.073V
515ps     2.923V     2.571V     3.151V
520ps     2.928V     2.581V     3.372V
593ps     2.991V     2.701V     3.414V
600ps     3.202V     2.71V      3.417V
743ps     3.266V     2.839V     3.453V
810ps     3.28V      3.068V     3.46V
10ns      3.3V       3.14V      3.47V
[Falling Waveform]
R_fixture= 50.000
V_fixture= 3.300
V_fixture_min= 3.140
V_fixture_max= 3.470
|time   V(typ)   V(min)   V(max)
0s        3.3V       3.14V      3.47V
299ps     3.303V     3.14V      3.467V
350ps     3.308V     3.14V      3.376V
355ps     3.308V     3.14V      3.148V
453ps     3.201V     3.146V     2.986V
455ps     2.991V     3.146V     2.984V
543ps     2.861V     3.138V     2.878V
691ps     2.717V     2.75V      2.766V
1.061ns   2.586V     2.499V     2.679V
10ns      2.56V      2.435V     2.662V
[Falling Waveform]
R_fixture= 50.000
V_fixture= 0.0
V_fixture_min= 0.0
V_fixture_max= 0.0
|time   V(typ)   V(min)   V(max)
0s        652.5mV    650.4mV    674.6mV
269ps     652.2mV    650.2mV    638.8mV
370ps     577.4mV    652mV      401.7mV
443ps     413.7mV    624.7mV    234.7mV
600ps     135.8mV    392.8mV    57.28mV
702ps     56.78mV    208.6mV    21.99mV
821ps     19.65mV    91.26mV    7.242mV
1.011ns   3.708mV    20.15mV    1.26mV
1.361ns   208.6uV    1.231mV    68.1uV
10ns      0V         0V         0V
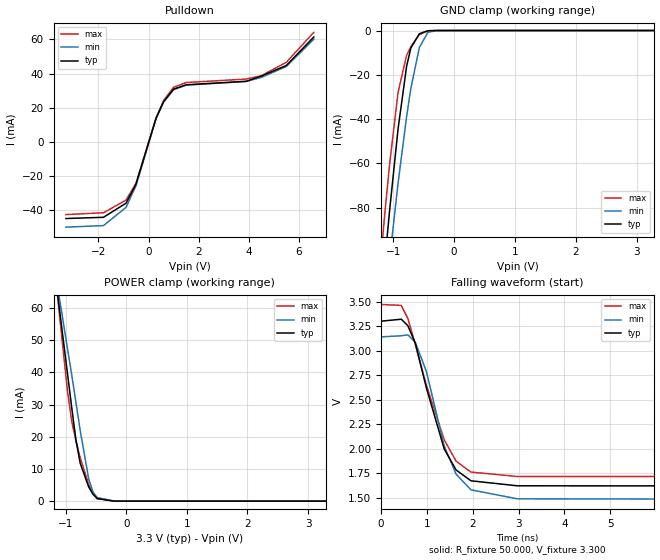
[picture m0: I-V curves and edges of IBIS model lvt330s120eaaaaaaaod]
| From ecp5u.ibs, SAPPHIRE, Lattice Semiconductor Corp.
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|   Model lvt330s120eaaaaaaaod
[Model] lvt330s120eaaaaaaaod
Model_type I/O_open_drain
Polarity   Non-Inverting
Enable   Active-Low
Vinl =  0.800V
Vinh =  2.000V
Vmeas =  1.650V
Cref =  0.0F
Rref =  1.000M
Vref =  3.3V
C_comp   5.000pF   4.000pF   5.500pF
[Temperature Range]   25.000   0.125k   -40.000
[Voltage Range]   3.300V   3.140V   3.470V
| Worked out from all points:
|   slope of the pulldown table from 0 to 0.495 V, typ, clamps not added: 24.2 ohm
|   GND clamp passes 1 mA (typ) near -0.54 V on its own axis
|   POWER clamp passes 1 mA (typ) near -0.49 V on its own axis
|   falling waveform, R_fixture 50.000, V_fixture 3.300: 20-80 % time 602ps typ, 573ps min, 683ps max; typ from 3.3 V to 1.62 V
[Pulldown]
|Voltage   I(typ)   I(min)   I(max)
-3.3V     -45.07mA   -50.13mA   -42.75mA
-1.8V     -44.35mA   -49.21mA   -41.67mA
-900mV    -36.06mA   -38.52mA   -34.28mA
-500mV    -24.74mA   -25.78mA   -24.33mA
300mV     13.77mA    13.66mA    14.07mA
600mV     23.46mA    23.24mA    24.12mA
1V        30.83mA    30.54mA    31.94mA
1.5V      33.4mA     33.17mA    34.73mA
3.9V      35.43mA    35.37mA    36.75mA
4.5V      38.49mA    37.71mA    38.7mA
5.5V      44.71mA    44.12mA    46.58mA
6.6V      61.45mA    60.23mA    64.17mA
[GND_clamp]
|Voltage   I(typ)   I(min)   I(max)
-3.3V     -912.7mA   -861.5mA   -922.5mA
-1.27V    -145.6mA   -163.6mA   -123.5mA
-1.2V     -123.4mA   -142.6mA   -101.4mA
-1.13V    -102mA     -122.4mA   -80.37mA
-1.06V    -81.56mA   -103.5mA   -60.64mA
-920mV    -44.4mA    -68.93mA   -27.87mA
-780mV    -16.18mA   -38.86mA   -11.24mA
-710mV    -7.839mA   -26.12mA   -7.318mA
-570mV    -1.464mA   -7.654mA   -1.852mA
-430mV    -105.8uA   -801.1uA   -99.73uA
-290mV    -1.56uA    -33.42uA   -868.4nA
3.28V     0A         0A         0A
[POWER_clamp]
|Voltage   I(typ)   I(min)   I(max)
-3.28V    471.5mA    421.2mA    516.6mA
-1.18V    71.72mA    72.75mA    72.14mA
-1.11V    60.88mA    63.98mA    59.38mA
-970mV    39.73mA    47.46mA    34.21mA
-900mV    29.12mA    39.28mA    24.89mA
-830mV    19.01mA    30.67mA    18.7mA
-760mV    11.8mA     22.01mA    13.51mA
-620mV    4.416mA    6.921mA    5.219mA
-550mV    2.174mA    2.865mA    2.414mA
-480mV    813uA      1.102mA    758.3uA
-200mV    3.62uA     22.61uA    424nA
3.3V      0A         0A         0A
[Ramp]
| variable   typ   min   max
dV/dt_r   1.008/0.531n   0.994/0.600n   1.053/0.515n
dV/dt_f   1.008/0.611n   0.994/0.582n   1.053/0.689n
R_load = 50.000
[Falling Waveform]
R_fixture= 50.000
V_fixture= 3.300
V_fixture_min= 3.140
V_fixture_max= 3.470
|time   V(typ)   V(min)   V(max)
0s        3.3V       3.14V      3.47V
442ps     3.32V      3.151V     3.461V
585ps     3.254V     3.16V      3.328V
748ps     3.074V     3.084V     3.064V
990ps     2.618V     2.786V     2.646V
1.378ns   1.997V     2.026V     2.09V
1.638ns   1.782V     1.739V     1.872V
1.961ns   1.672V     1.58V      1.761V
2.974ns   1.621V     1.488V     1.716V
10ns      1.619V     1.483V     1.716V
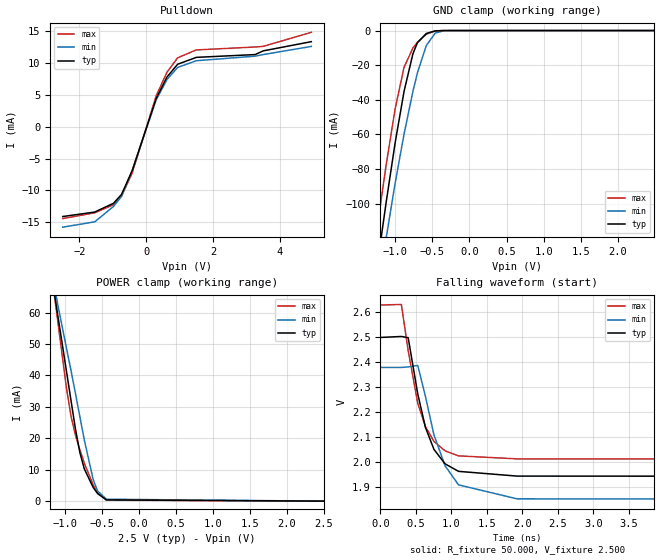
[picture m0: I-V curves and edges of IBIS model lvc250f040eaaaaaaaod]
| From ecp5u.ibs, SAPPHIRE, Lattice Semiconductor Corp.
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|   Model lvc250f040eaaaaaaaod
[Model] lvc250f040eaaaaaaaod
Model_type I/O_open_drain
Polarity   Non-Inverting
Enable   Active-Low
Vinl =  0.700V
Vinh =  1.700V
Vmeas =  1.250V
Cref =  0.0F
Rref =  1.000M
Vref =  2.5V
C_comp   5.000pF   4.000pF   5.500pF
[Temperature Range]   25.000   0.125k   -40.000
[Voltage Range]   2.500V   2.380V   2.630V
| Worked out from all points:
|   slope of the pulldown table from 0 to 0.375 V, typ, clamps not added: 69.2 ohm
|   GND clamp passes 1 mA (typ) near -0.54 V on its own axis
|   POWER clamp passes 1 mA (typ) near -0.49 V on its own axis
|   falling waveform, R_fixture 50.000, V_fixture 2.500: 20-80 % time 288ps typ, 340ps min, 281ps max; typ from 2.5 V to 1.94 V
[Pulldown]
|Voltage   I(typ)   I(min)   I(max)
-2.5V     -14.12mA   -15.79mA   -14.44mA
-1.54V    -13.41mA   -14.95mA   -13.53mA
-980mV    -12.03mA   -12.53mA   -12.26mA
-740mV    -10.64mA   -10.95mA   -10.92mA
-420mV    -6.892mA   -6.861mA   -7.26mA
300mV     4.505mA    4.281mA    4.905mA
620mV     7.84mA     7.441mA    8.594mA
940mV     9.849mA    9.346mA    10.86mA
1.5V      10.93mA    10.4mA     12.1mA
3.26V     11.37mA    11.12mA    12.56mA
3.5V      11.95mA    11.37mA    12.66mA
4.94V     13.4mA     12.65mA    14.87mA
[GND_clamp]
|Voltage   I(typ)   I(min)   I(max)
-2.5V     -600.3mA   -576.2mA   -594.4mA
-1.24V    -136mA     -154.5mA   -113.9mA
-1.18V    -117.2mA   -136.7mA   -95.27mA
-1.12V    -99.04mA   -119.7mA   -77.45mA
-1V       -64.9mA    -88.21mA   -45.19mA
-880mV    -35.12mA   -59.82mA   -21.21mA
-760mV    -13.33mA   -35.03mA   -10mA
-700mV    -7.01mA    -24.46mA   -6.829mA
-580mV    -1.679mA   -8.593mA   -2.127mA
-460mV    -210.1uA   -1.441mA   -213.7uA
-340mV    -8.598uA   -109.2uA   -6.553uA
2.48V     0A         0A         0A
[POWER_clamp]
|Voltage   I(typ)   I(min)   I(max)
-2.48V    301.8mA    269mA      334.4mA
-1.16V    68.59mA    70.21mA    68.47mA
-1.1V     59.33mA    62.74mA    57.51mA
-980mV    41.18mA    48.59mA    35.82mA
-920mV    32.13mA    41.65mA    27.11mA
-860mV    23.04mA    34.34mA    21.08mA
-800mV    15.49mA    26.9mA     16.35mA
-740mV    10.29mA    19.52mA    12.1mA
-620mV    4.381mA    6.888mA    5.184mA
-560mV    2.412mA    3.25mA     2.719mA
-440mV    397.7uA    604uA      311uA
2.5V      0A         0A         0A
[Ramp]
| variable   typ   min   max
dV/dt_r   0.334/0.304n   0.317/0.349n   0.381/0.292n
dV/dt_f   0.334/0.286n   0.317/0.338n   0.370/0.285n
R_load = 50.000
[Falling Waveform]
R_fixture= 50.000
V_fixture= 2.500
V_fixture_min= 2.380
V_fixture_max= 2.630
|time   V(typ)   V(min)   V(max)
0s        2.5V       2.38V      2.63V
297ps     2.504V     2.38V      2.632V
393ps     2.499V     2.382V     2.447V
528ps     2.274V     2.388V     2.236V
636ps     2.14V      2.264V     2.143V
756ps     2.052V     2.11V      2.084V
913ps     1.994V     1.986V     2.046V
1.102ns   1.964V     1.91V      2.026V
1.926ns   1.945V     1.854V     2.014V
10ns      1.944V     1.852V     2.013V
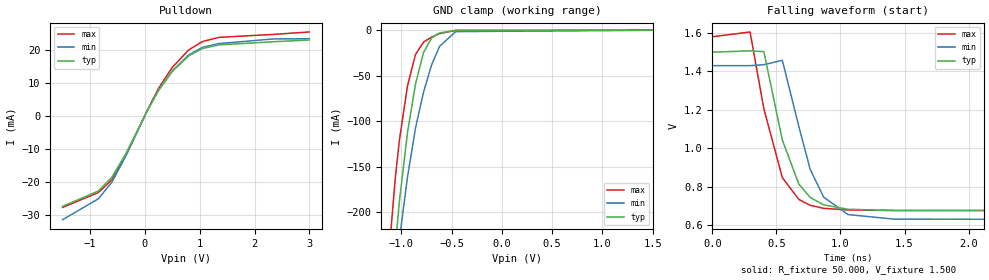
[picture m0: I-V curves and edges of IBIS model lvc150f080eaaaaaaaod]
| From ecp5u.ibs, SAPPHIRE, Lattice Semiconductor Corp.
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|   Model lvc150f080eaaaaaaaod
[Model] lvc150f080eaaaaaaaod
Model_type I/O_open_drain
Polarity   Non-Inverting
Enable   Active-Low
Vinl =  0.375V
Vinh =  1.125V
Vmeas =  0.750V
Cref =  0.0F
Rref =  1.000M
Vref =  1.5V
C_comp   5.000pF   4.000pF   5.500pF
[Temperature Range]   25.000   0.125k   -40.000
[Voltage Range]   1.500V   1.430V   1.580V
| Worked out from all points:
|   slope of the pulldown table from 0 to 0.225 V, typ, clamps not added: 32.3 ohm
|   GND clamp passes 1 mA (typ) near -0.54 V on its own axis
|   falling waveform, R_fixture 50.000, V_fixture 1.500: 20-80 % time 196ps typ, 202ps min, 185ps max; typ from 1.5 V to 0.677 V
[Pulldown]
|Voltage   I(typ)   I(min)   I(max)
-1.5V     -27.39mA   -31.43mA   -27.72mA
-850mV    -22.78mA   -25.14mA   -23.23mA
-600mV    -18.58mA   -20.07mA   -19.34mA
-350mV    -11.53mA   -12.21mA   -12.18mA
50mV      1.697mA    1.729mA    1.836mA
250mV     7.652mA    7.792mA    8.316mA
500mV     13.41mA    13.64mA    14.65mA
800mV     18.13mA    18.42mA    19.93mA
1.05V     20.35mA    20.7mA     22.46mA
1.35V     21.45mA    21.85mA    23.73mA
2.35V     22.41mA    23.26mA    24.63mA
3V        22.92mA    23.32mA    25.36mA
[GND_clamp]
|Voltage   I(typ)   I(min)   I(max)
-1.5V     -960.1mA   -762.7mA   -1.034A
-1.14V    -347.3mA   -346mA     -275mA
-1.1V     -290.2mA   -305.8mA   -213.7mA
-1.06V    -236.5mA   -267.1mA   -161mA
-1.02V    -187.7mA   -229.9mA   -120.7mA
-940mV    -112.8mA   -161.5mA   -61.34mA
-860mV    -59.06mA   -107.5mA   -26.59mA
-780mV    -24.6mA    -67.97mA   -13.06mA
-700mV    -8.431mA   -38.1mA    -7.531mA
-620mV    -2.969mA   -17.61mA   -3.668mA
-460mV    -207.8uA   -1.521mA   -211uA
1.5V      0A         0A         0A
[Ramp]
| variable   typ   min   max
dV/dt_r 0.500/0.299n   0.489/0.333n   0.555/0.259n
dV/dt_f 0.494/0.196n   0.480/0.207n   0.542/0.190n
R_load = 50.000
[Falling Waveform]
R_fixture= 50.000
V_fixture= 1.500
V_fixture_min= 1.430
V_fixture_max= 1.580
|time   V(typ)   V(min)   V(max)
0s        1.5V       1.43V      1.58V
294ps     1.507V     1.43V      1.605V
402ps     1.503V     1.435V     1.206V
546ps     1.044V     1.458V     848.7mV
675ps     814.7mV    1.114V     735.2mV
763ps     745.9mV    892.4mV    704.9mV
868ps     707.1mV    747.5mV    689.2mV
1.059ns   684.1mV    656.7mV    680.3mV
1.422ns   677.9mV    632.7mV    677.8mV
10ns      676.8mV    630.1mV    677mV
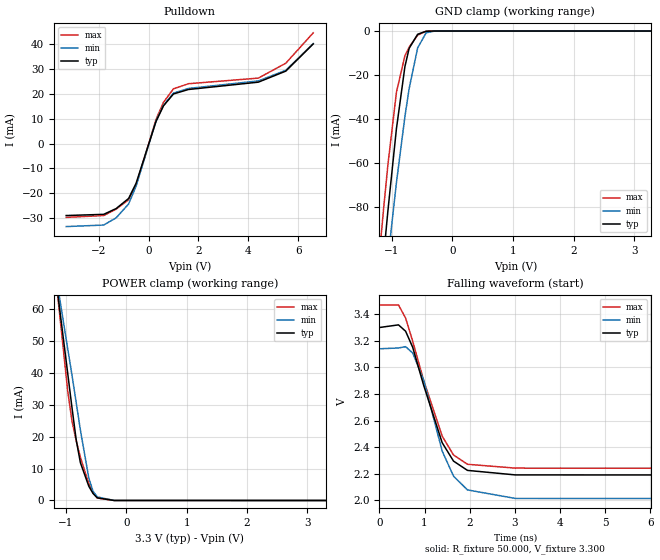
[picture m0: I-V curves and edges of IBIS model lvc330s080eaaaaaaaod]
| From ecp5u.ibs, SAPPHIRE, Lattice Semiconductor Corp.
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|   Model lvc330s080eaaaaaaaod
[Model] lvc330s080eaaaaaaaod
Model_type I/O_open_drain
Polarity   Non-Inverting
Enable   Active-Low
Vinl =  0.800V
Vinh =  2.000V
Vmeas =  1.650V
Cref =  0.0F
Rref =  1.000M
Vref =  3.3V
C_comp   5.000pF   4.000pF   5.500pF
[Temperature Range]   25.000   0.125k   -40.000
[Voltage Range]   3.300V   3.140V   3.470V
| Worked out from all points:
|   slope of the pulldown table from 0 to 0.495 V, typ, clamps not added: 37.2 ohm
|   GND clamp passes 1 mA (typ) near -0.54 V on its own axis
|   POWER clamp passes 1 mA (typ) near -0.49 V on its own axis
|   falling waveform, R_fixture 50.000, V_fixture 3.300: 20-80 % time 612ps typ, 577ps min, 670ps max; typ from 3.3 V to 2.19 V
[Pulldown]
|Voltage   I(typ)   I(min)   I(max)
-3.3V     -29mA      -33.46mA   -29.75mA
-1.8V     -28.53mA   -32.84mA   -29.01mA
-1.3V     -26.2mA    -29.95mA   -26.46mA
-800mV    -22.14mA   -24.37mA   -22.63mA
-500mV    -16.05mA   -17.19mA   -16.84mA
300mV     8.946mA    9.108mA    9.732mA
600mV     15.23mA    15.49mA    16.68mA
1V        20.02mA    20.36mA    22.09mA
1.6V      21.81mA    22.24mA    24.14mA
4.4V      24.77mA    25.27mA    26.4mA
5.5V      29.22mA    29.55mA    32.41mA
6.6V      40.19mA    40.34mA    44.66mA
[GND_clamp]
|Voltage   I(typ)   I(min)   I(max)
-3.3V     -912.7mA   -861.5mA   -922.5mA
-1.27V    -145.6mA   -163.6mA   -123.5mA
-1.2V     -123.4mA   -142.6mA   -101.4mA
-1.13V    -102mA     -122.4mA   -80.37mA
-1.06V    -81.56mA   -103.5mA   -60.64mA
-920mV    -44.4mA    -68.93mA   -27.87mA
-780mV    -16.18mA   -38.86mA   -11.24mA
-710mV    -7.839mA   -26.12mA   -7.318mA
-570mV    -1.464mA   -7.654mA   -1.852mA
-430mV    -105.8uA   -801.1uA   -99.73uA
-290mV    -1.56uA    -33.42uA   -868.4nA
3.28V     0A         0A         0A
[POWER_clamp]
|Voltage   I(typ)   I(min)   I(max)
-3.28V    471.5mA    421.2mA    516.6mA
-1.18V    71.72mA    72.75mA    72.14mA
-1.11V    60.88mA    63.98mA    59.38mA
-970mV    39.73mA    47.46mA    34.21mA
-900mV    29.12mA    39.28mA    24.89mA
-830mV    19.01mA    30.67mA    18.7mA
-760mV    11.8mA     22.01mA    13.51mA
-620mV    4.416mA    6.921mA    5.219mA
-550mV    2.174mA    2.865mA    2.414mA
-480mV    813uA      1.102mA    758.3uA
-200mV    3.62uA     22.61uA    424nA
3.3V      0A         0A         0A
[Ramp]
| variable   typ   min   max
dV/dt_r   0.666/0.854n   0.677/0.619n   0.737/0.493n
dV/dt_f   0.666/0.622n   0.677/0.590n   0.737/0.676n
R_load = 50.000
[Falling Waveform]
R_fixture= 50.000
V_fixture= 3.300
V_fixture_min= 3.140
V_fixture_max= 3.470
|time   V(typ)   V(min)   V(max)
0s        3.3V       3.14V      3.47V
422ps     3.32V      3.146V     3.47V
580ps     3.272V     3.156V     3.371V
737ps     3.151V     3.108V     3.197V
980ps     2.865V     2.904V     2.901V
1.39ns    2.433V     2.37V      2.483V
1.641ns   2.295V     2.182V     2.341V
1.95ns    2.225V     2.078V     2.271V
3.01ns    2.191V     2.014V     2.242V
10ns      2.19V      2.012V     2.241V
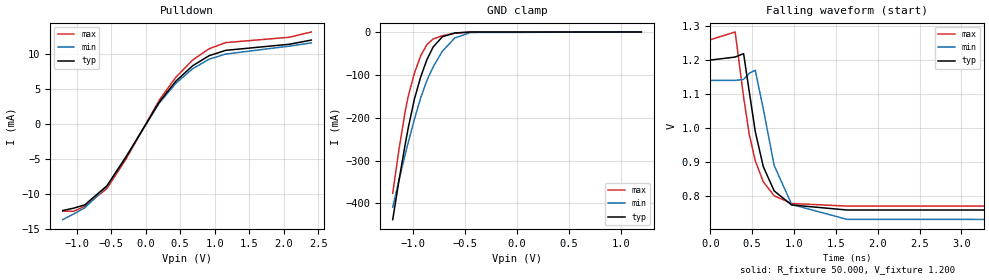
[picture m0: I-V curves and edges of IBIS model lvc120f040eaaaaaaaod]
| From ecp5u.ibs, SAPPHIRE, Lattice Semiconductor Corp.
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|   Model lvc120f040eaaaaaaaod
[Model] lvc120f040eaaaaaaaod
Model_type I/O_open_drain
Polarity   Non-Inverting
Enable   Active-Low
Vinl =  0.420V
Vinh =  0.780V
Vmeas =  0.600V
Cref =  0.0F
Rref =  1.000M
Vref =  1.2V
C_comp   5.000pF   4.000pF   5.500pF
[Temperature Range]   25.000   0.125k   -40.000
[Voltage Range]   1.200V   1.140V   1.260V
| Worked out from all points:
|   slope of the pulldown table from 0 to 0.18 V, typ, clamps not added: 62.6 ohm
|   GND clamp passes 1 mA (typ) near -0.54 V on its own axis
|   falling waveform, R_fixture 50.000, V_fixture 1.200: 20-80 % time 229ps typ, 242ps min, 221ps max; typ from 1.2 V to 0.757 V
[Pulldown]
|Voltage   I(typ)   I(min)   I(max)
-1.2V     -12.39mA   -13.7mA    -12.49mA
-1.04V    -12.05mA   -12.88mA   -12.49mA
-880mV    -11.58mA   -12mA      -11.79mA
-560mV    -8.851mA   -8.925mA   -9.245mA
-280mV    -4.688mA   -4.607mA   -4.974mA
200mV     3.164mA    3.008mA    3.437mA
440mV     6.136mA    5.828mA    6.7mA
680mV     8.315mA    7.89mA     9.126mA
920mV     9.761mA    9.262mA    10.76mA
1.16V     10.53mA    9.999mA    11.64mA
2.08V     11.4mA     11.13mA    12.4mA
2.4V      12mA       11.6mA     13.16mA
[GND_clamp]
|Voltage   I(typ)   I(min)   I(max)
-1.2V     -438mA     -409mA     -376.5mA
-1.14V    -347.3mA   -346mA     -274.9mA
-1.08V    -262.9mA   -286.2mA   -185.9mA
-1.05V    -223.7mA   -257.6mA   -150mA
-990mV    -156.1mA   -203.2mA   -95.66mA
-930mV    -105mA     -153.7mA   -55.58mA
-870mV    -64.74mA   -113.2mA   -29.56mA
-810mV    -35.2mA    -81.56mA   -16.45mA
-720mV    -11.09mA   -44.69mA   -8.691mA
-600mV    -2.287mA   -13.94mA   -2.904mA
-450mV    -166.2uA   -1.247mA   -164.1uA
1.2V      0A         0A         0A
[Ramp]
| variable   typ   min   max
dV/dt_r   0.266/0.326n   0.247/0.376n   0.295/0.306n
dV/dt_f   0.266/0.237n   0.247/0.244n   0.295/0.221n
R_load = 50.000
[Falling Waveform]
R_fixture= 50.000
V_fixture= 1.200
V_fixture_min= 1.140
V_fixture_max= 1.260
|time   V(typ)   V(min)   V(max)
0s        1.2V       1.14V      1.26V
297ps     1.209V     1.14V      1.283V
398ps     1.219V     1.143V     1.091V
466ps     1.106V     1.161V     980mV
537ps     989.3mV    1.17V      902.9mV
633ps     885.5mV    1.056V     840.7mV
763ps     813.8mV    889mV      799.4mV
972ps     772.2mV    773.8mV    776.6mV
1.633ns   757.4mV    729.7mV    769mV
10ns      757.1mV    728.8mV    768.8mV
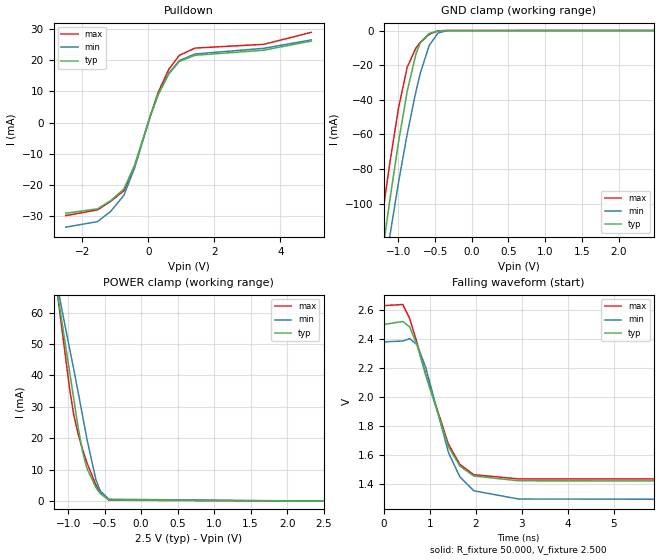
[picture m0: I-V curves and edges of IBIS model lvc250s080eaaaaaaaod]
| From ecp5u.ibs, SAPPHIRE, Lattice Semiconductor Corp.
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|   Model lvc250s080eaaaaaaaod
[Model] lvc250s080eaaaaaaaod
Model_type I/O_open_drain
Polarity   Non-Inverting
Enable   Active-Low
Vinl =  0.700V
Vinh =  1.700V
Vmeas =  1.250V
Cref =  0.0F
Rref =  1.000M
Vref =  2.5V
C_comp   5.000pF   4.000pF   5.500pF
[Temperature Range]   25.000   0.125k   -40.000
[Voltage Range]   2.500V   2.380V   2.630V
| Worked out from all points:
|   slope of the pulldown table from 0 to 0.375 V, typ, clamps not added: 34.9 ohm
|   GND clamp passes 1 mA (typ) near -0.54 V on its own axis
|   POWER clamp passes 1 mA (typ) near -0.49 V on its own axis
|   falling waveform, R_fixture 50.000, V_fixture 2.500: 20-80 % time 640ps typ, 594ps min, 698ps max; typ from 2.5 V to 1.42 V
[Pulldown]
|Voltage   I(typ)   I(min)   I(max)
-2.5V     -29mA      -33.45mA   -29.74mA
-1.54V    -27.59mA   -31.68mA   -27.93mA
-1.14V    -24.97mA   -28.41mA   -25.2mA
-740mV    -21.24mA   -23.27mA   -21.81mA
-420mV    -13.7mA    -14.59mA   -14.42mA
60mV      2.026mA    2.064mA    2.192mA
300mV     8.946mA    9.108mA    9.732mA
620mV     15.57mA    15.83mA    17.06mA
940mV     19.56mA    19.88mA    21.55mA
1.42V     21.58mA    21.99mA    23.88mA
3.5V      23.2mA     23.8mA     25.08mA
4.94V     26.12mA    26.49mA    28.92mA
[GND_clamp]
|Voltage   I(typ)   I(min)   I(max)
-2.5V     -600.3mA   -576.2mA   -594.4mA
-1.24V    -136mA     -154.5mA   -113.9mA
-1.18V    -117.2mA   -136.7mA   -95.27mA
-1.12V    -99.04mA   -119.7mA   -77.45mA
-1V       -64.9mA    -88.21mA   -45.19mA
-880mV    -35.12mA   -59.82mA   -21.21mA
-760mV    -13.33mA   -35.03mA   -10mA
-700mV    -7.01mA    -24.46mA   -6.829mA
-580mV    -1.679mA   -8.593mA   -2.127mA
-460mV    -210.1uA   -1.441mA   -213.7uA
-340mV    -8.598uA   -109.2uA   -6.553uA
2.48V     0A         0A         0A
[POWER_clamp]
|Voltage   I(typ)   I(min)   I(max)
-2.48V    301.8mA    269mA      334.4mA
-1.16V    68.59mA    70.21mA    68.47mA
-1.1V     59.33mA    62.74mA    57.51mA
-980mV    41.18mA    48.59mA    35.82mA
-920mV    32.13mA    41.65mA    27.11mA
-860mV    23.04mA    34.34mA    21.08mA
-800mV    15.49mA    26.9mA     16.35mA
-740mV    10.29mA    19.52mA    12.1mA
-620mV    4.381mA    6.888mA    5.184mA
-560mV    2.412mA    3.25mA     2.719mA
-440mV    397.7uA    604uA      311uA
2.5V      0A         0A         0A
[Ramp]
| variable   typ   min   max
dV/dt_r   0.647/0.589n   0.651/0.626n   0.717/0.501n
dV/dt_f   0.647/0.648n   0.652/0.602n   0.717/0.706n
R_load = 50.000
[Falling Waveform]
R_fixture= 50.000
V_fixture= 2.500
V_fixture_min= 2.380
V_fixture_max= 2.630
|time   V(typ)   V(min)   V(max)
0s        2.5V       2.38V      2.63V
412ps     2.521V     2.386V     2.638V
563ps     2.484V     2.402V     2.542V
723ps     2.359V     2.361V     2.375V
914ps     2.149V     2.203V     2.155V
1.406ns   1.657V     1.617V     1.675V
1.654ns   1.524V     1.449V     1.535V
1.956ns   1.455V     1.353V     1.464V
2.933ns   1.422V     1.296V     1.435V
10ns      1.421V     1.294V     1.435V
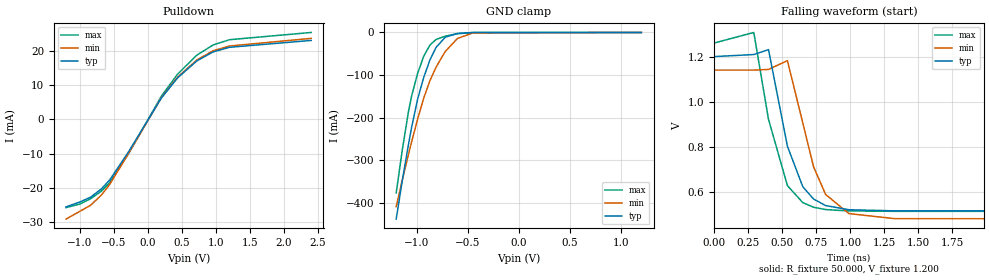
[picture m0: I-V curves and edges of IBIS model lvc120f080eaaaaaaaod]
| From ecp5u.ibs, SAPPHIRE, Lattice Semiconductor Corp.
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|   Model lvc120f080eaaaaaaaod
[Model] lvc120f080eaaaaaaaod
Model_type I/O_open_drain
Polarity   Non-Inverting
Enable   Active-Low
Vinl =  0.420V
Vinh =  0.780V
Vmeas =  0.600V
Cref =  0.0F
Rref =  1.000M
Vref =  1.2V
C_comp   5.000pF   4.000pF   5.500pF
[Temperature Range]   25.000   0.125k   -40.000
[Voltage Range]   1.200V   1.140V   1.260V
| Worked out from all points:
|   slope of the pulldown table from 0 to 0.18 V, typ, clamps not added: 31.5 ohm
|   GND clamp passes 1 mA (typ) near -0.54 V on its own axis
|   falling waveform, R_fixture 50.000, V_fixture 1.200: 20-80 % time 170ps typ, 179ps min, 158ps max; typ from 1.2 V to 0.515 V
[Pulldown]
|Voltage   I(typ)   I(min)   I(max)
-1.2V     -25.46mA   -29.03mA   -25.7mA
-1V       -24.07mA   -26.8mA    -24.67mA
-840mV    -22.66mA   -25mA      -23.11mA
-680mV    -20.21mA   -22.01mA   -20.87mA
-560mV    -17.64mA   -18.97mA   -18.42mA
-280mV    -9.315mA   -9.799mA   -9.876mA
200mV     6.283mA    6.399mA    6.82mA
440mV     12.18mA    12.4mA     13.3mA
720mV     17.09mA    17.37mA    18.76mA
960mV     19.72mA    20.05mA    21.74mA
1.2V      21.05mA    21.43mA    23.27mA
2.4V      23.06mA    23.66mA    25.38mA
[GND_clamp]
|Voltage   I(typ)   I(min)   I(max)
-1.2V     -438mA     -409mA     -376.5mA
-1.14V    -347.3mA   -346mA     -274.9mA
-1.08V    -262.9mA   -286.2mA   -185.9mA
-1.05V    -223.7mA   -257.6mA   -150mA
-990mV    -156.1mA   -203.2mA   -95.66mA
-930mV    -105mA     -153.7mA   -55.58mA
-870mV    -64.74mA   -113.2mA   -29.56mA
-810mV    -35.2mA    -81.56mA   -16.45mA
-720mV    -11.09mA   -44.69mA   -8.691mA
-600mV    -2.287mA   -13.94mA   -2.904mA
-450mV    -166.2uA   -1.247mA   -164.1uA
1.2V      0A         0A         0A
[Ramp]
| variable   typ   min   max
dV/dt_r   0.411/0.309n   0.397/0.378n   0.448/0.269n
dV/dt_f   0.411/0.174n   0.397/0.185n   0.448/0.159n
R_load = 50.000
[Falling Waveform]
R_fixture= 50.000
V_fixture= 1.200
V_fixture_min= 1.140
V_fixture_max= 1.260
|time   V(typ)   V(min)   V(max)
0s        1.2V       1.14V      1.26V
292ps     1.209V     1.14V      1.307V
400ps     1.231V     1.143V     921.6mV
539ps     802.3mV    1.182V     627.5mV
652ps     622.5mV    905.8mV    552mV
731ps     568mV      711.3mV    531.5mV
820ps     538.9mV    588mV      521.2mV
991ps     520.4mV    503.4mV    515.1mV
1.331ns   515.5mV    480.7mV    513.4mV
10ns      515.1mV    479.1mV    513.2mV
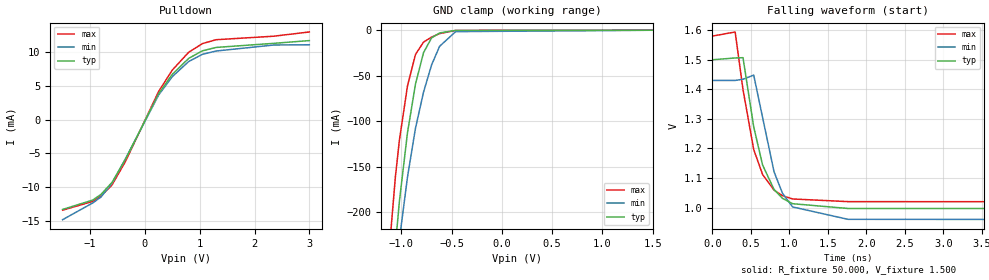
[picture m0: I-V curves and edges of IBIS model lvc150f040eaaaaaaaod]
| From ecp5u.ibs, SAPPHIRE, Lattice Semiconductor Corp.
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|   Model lvc150f040eaaaaaaaod
[Model] lvc150f040eaaaaaaaod
Model_type I/O_open_drain
Polarity   Non-Inverting
Enable   Active-Low
Vinl =  0.375V
Vinh =  1.125V
Vmeas =  0.750V
Cref =  0.0F
Rref =  1.000M
Vref =  1.5V
C_comp   5.000pF   4.000pF   5.500pF
[Temperature Range]   25.000   0.125k   -40.000
[Voltage Range]   1.500V   1.430V   1.580V
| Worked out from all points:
|   slope of the pulldown table from 0 to 0.225 V, typ, clamps not added: 64.1 ohm
|   GND clamp passes 1 mA (typ) near -0.54 V on its own axis
|   falling waveform, R_fixture 50.000, V_fixture 1.500: 20-80 % time 258ps typ, 268ps min, 252ps max; typ from 1.5 V to 0.996 V
[Pulldown]
|Voltage   I(typ)   I(min)   I(max)
-1.5V     -13.32mA   -14.84mA   -13.43mA
-950mV    -11.92mA   -12.35mA   -12.12mA
-800mV    -11.08mA   -11.47mA   -11.33mA
-600mV    -9.319mA   -9.44mA    -9.695mA
-350mV    -5.803mA   -5.742mA   -6.134mA
250mV     3.854mA    3.663mA    4.191mA
500mV     6.752mA    6.411mA    7.382mA
800mV     9.128mA    8.66mA     10.04mA
1.05V     10.25mA    9.731mA    11.32mA
1.3V      10.75mA    10.22mA    11.9mA
2.35V     11.36mA    11.11mA    12.42mA
3V        11.77mA    11.15mA    13.05mA
[GND_clamp]
|Voltage   I(typ)   I(min)   I(max)
-1.5V     -960.1mA   -762.7mA   -1.034A
-1.14V    -347.3mA   -346mA     -275mA
-1.1V     -290.2mA   -305.8mA   -213.7mA
-1.06V    -236.5mA   -267.1mA   -161mA
-1.02V    -187.7mA   -229.9mA   -120.7mA
-940mV    -112.8mA   -161.5mA   -61.34mA
-860mV    -59.06mA   -107.5mA   -26.59mA
-780mV    -24.6mA    -67.97mA   -13.06mA
-700mV    -8.431mA   -38.1mA    -7.531mA
-620mV    -2.969mA   -17.61mA   -3.668mA
-460mV    -207.8uA   -1.521mA   -211uA
1.5V      0A         0A         0A
[Ramp]
| variable   typ   min   max
dV/dt_r   0.302/0.323n   0.283/0.368n   0.336/0.293n
dV/dt_f   0.302/0.255n   0.283/0.270n   0.336/0.259n
R_load = 50.000
[Falling Waveform]
R_fixture= 50.000
V_fixture= 1.500
V_fixture_min= 1.430
V_fixture_max= 1.580
|time   V(typ)   V(min)   V(max)
0s        1.5V       1.43V      1.58V
296ps     1.506V     1.43V      1.594V
398ps     1.507V     1.434V     1.399V
537ps     1.273V     1.448V     1.196V
652ps     1.144V     1.305V     1.112V
801ps     1.061V     1.121V     1.059V
911ps     1.031V     1.048V     1.04V
1.042ns   1.013V     1.002V     1.029V
1.762ns   996.8mV    960.1mV    1.02V
10ns      996.4mV    958.9mV    1.019V
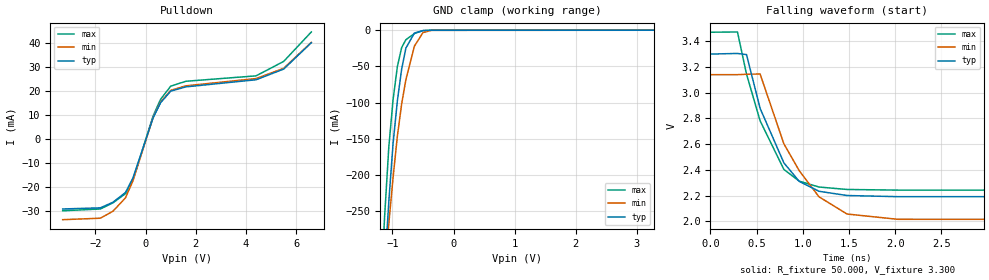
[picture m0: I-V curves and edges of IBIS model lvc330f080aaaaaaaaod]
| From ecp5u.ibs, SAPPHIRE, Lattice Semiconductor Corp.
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|   Model lvc330f080aaaaaaaaod
[Model] lvc330f080aaaaaaaaod
Model_type I/O_open_drain
Polarity   Non-Inverting
Enable   Active-Low
Vinl =  0.800V
Vinh =  2.000V
Vmeas =  1.650V
Cref =  0.0F
Rref =  1.000M
Vref =  3.3V
C_comp   5.000pF   4.000pF   5.500pF
[Temperature Range]   25.000   0.125k   -40.000
[Voltage Range]   3.300V   3.140V   3.470V
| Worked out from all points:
|   slope of the pulldown table from 0 to 0.495 V, typ, clamps not added: 37.2 ohm
|   GND clamp passes 1 mA (typ) near -0.54 V on its own axis
|   falling waveform, R_fixture 50.000, V_fixture 3.300: 20-80 % time 366ps typ, 476ps min, 344ps max; typ from 3.3 V to 2.19 V
[Pulldown]
|Voltage   I(typ)   I(min)   I(max)
-3.3V     -29mA      -33.46mA   -29.75mA
-1.8V     -28.53mA   -32.84mA   -29.01mA
-1.3V     -26.2mA    -29.95mA   -26.46mA
-800mV    -22.14mA   -24.37mA   -22.63mA
-500mV    -16.05mA   -17.19mA   -16.84mA
300mV     8.946mA    9.108mA    9.732mA
600mV     15.23mA    15.49mA    16.68mA
1V        20.02mA    20.36mA    22.09mA
1.6V      21.81mA    22.24mA    24.14mA
4.4V      24.77mA    25.27mA    26.4mA
5.5V      29.22mA    29.55mA    32.41mA
6.6V      40.19mA    40.34mA    44.66mA
[GND_clamp]
|Voltage   I(typ)   I(min)   I(max)
-3.3V     -4.927A    -3.455A    -6.917A
-1.2V     -438mA     -409mA     -376.6mA
-1.13V    -332.7mA   -335.8mA   -258.9mA
-1.06V    -236.4mA   -267mA     -161mA
-990mV    -156.1mA   -203.1mA   -95.6mA
-920mV    -97.57mA   -146.3mA   -50.22mA
-850mV    -53.64mA   -101.9mA   -23.95mA
-780mV    -24.57mA   -67.95mA   -13.06mA
-640mV    -3.835mA   -21.83mA   -4.519mA
-500mV    -471.8uA   -3.197mA   -537.5uA
-360mV    -15.56uA   -174.4uA   -12.69uA
3.28V     0A         0A         0A
[Ramp]
| variable   typ   min   max
dV/dt_r   0.666/0.278n   0.677/0.325n   0.737/0.260n
dV/dt_f   0.666/0.367n   0.677/0.484n   0.737/0.355n
R_load = 50.000
[Falling Waveform]
R_fixture= 50.000
V_fixture= 3.300
V_fixture_min= 3.140
V_fixture_max= 3.470
|time   V(typ)   V(min)   V(max)
0s        3.3V       3.14V      3.47V
294ps     3.305V     3.14V      3.472V
392ps     3.296V     3.143V     3.144V
539ps     2.878V     3.145V     2.781V
796ps     2.454V     2.602V     2.403V
962ps     2.31V      2.393V     2.312V
1.176ns   2.233V     2.19V      2.266V
1.479ns   2.2V       2.056V     2.247V
2.028ns   2.191V     2.015V     2.242V
10ns      2.19V      2.012V     2.241V
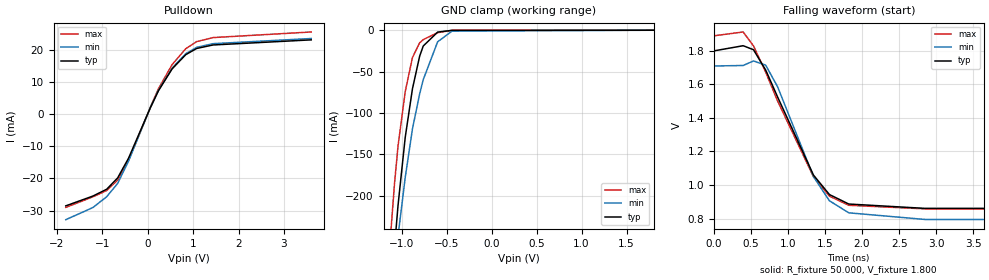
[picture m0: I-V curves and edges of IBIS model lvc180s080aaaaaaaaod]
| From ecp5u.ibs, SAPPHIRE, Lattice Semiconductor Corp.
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|   Model lvc180s080aaaaaaaaod
[Model] lvc180s080aaaaaaaaod
Model_type I/O_open_drain
Polarity   Non-Inverting
Enable   Active-Low
Vinl =  0.630V
Vinh =  1.170V
Vmeas =  0.900V
Cref =  0.0F
Rref =  1.000M
Vref =  1.8V
C_comp   5.000pF   4.000pF   5.500pF
[Temperature Range]   25.000   0.125k   -40.000
[Voltage Range]   1.800V   1.710V   1.890V
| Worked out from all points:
|   slope of the pulldown table from 0 to 0.27 V, typ, clamps not added: 33.1 ohm
|   GND clamp passes 1 mA (typ) near -0.54 V on its own axis
|   falling waveform, R_fixture 50.000, V_fixture 1.800: 20-80 % time 584ps typ, 520ps min, 635ps max; typ from 1.8 V to 0.86 V
[Pulldown]
|Voltage   I(typ)   I(min)   I(max)
-1.8V     -28.53mA   -32.84mA   -29.01mA
-1.2V     -25.46mA   -29.03mA   -25.7mA
-900mV    -23.35mA   -25.68mA   -23.75mA
-660mV    -19.84mA   -21.55mA   -20.51mA
-420mV    -13.7mA    -14.59mA   -14.42mA
60mV      2.026mA    2.064mA    2.192mA
240mV     7.384mA    7.52mA     8.023mA
540mV     14.17mA    14.41mA    15.5mA
840mV     18.59mA    18.89mA    20.45mA
1.08V     20.52mA    20.88mA    22.66mA
1.44V     21.61mA    22.02mA    23.91mA
3.6V      23.2mA     23.62mA    25.66mA
[GND_clamp]
|Voltage   I(typ)   I(min)   I(max)
-1.8V     -1.552A    -1.161A    -1.853A
-1.16V    -376.9mA   -366.7mA   -307.6mA
-1.12V    -318.4mA   -325.7mA   -243.6mA
-1.08V    -262.9mA   -286.2mA   -185.9mA
-1.04V    -211.3mA   -248.3mA   -139.6mA
-960mV    -129.1mA   -177.6mA   -73.98mA
-880mV    -70.75mA   -119.2mA   -32.93mA
-800mV    -31.34mA   -76.89mA   -15.17mA
-760mV    -19.02mA   -59.64mA   -11.38mA
-600mV    -2.287mA   -13.94mA   -2.904mA
-440mV    -132uA     -1.017mA   -127uA
1.8V      0A         0A         0A
[Ramp]
| variable   typ   min   max
dV/dt_r 0.561/0.465n   0.547/0.507n   0.613/0.354n
dV/dt_f 0.564/0.599n   0.550/0.531n   0.620/0.643n
R_load = 50.000
[Falling Waveform]
R_fixture= 50.000
V_fixture= 1.800
V_fixture_min= 1.710
V_fixture_max= 1.890
|time   V(typ)   V(min)   V(max)
0s        1.8V       1.71V      1.89V
396ps     1.831V     1.713V     1.913V
536ps     1.807V     1.74V      1.83V
700ps     1.686V     1.715V     1.673V
860ps     1.526V     1.587V     1.502V
1.345ns   1.059V     1.05V      1.049V
1.56ns    943.1mV    906mV      933.6mV
1.821ns   886.5mV    834mV      879.1mV
2.852ns   860.5mV    794.4mV    857.5mV
10ns      860mV      793.1mV    857.1mV
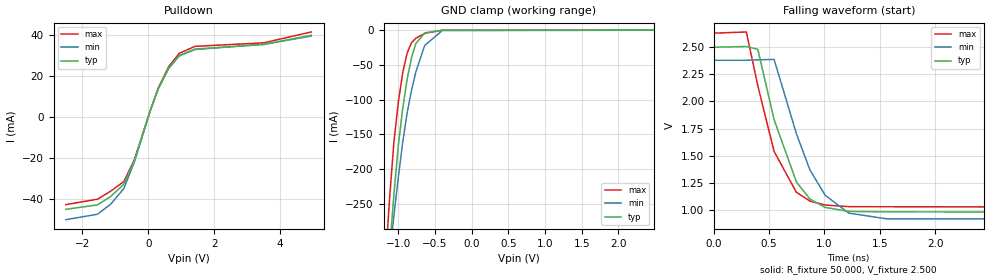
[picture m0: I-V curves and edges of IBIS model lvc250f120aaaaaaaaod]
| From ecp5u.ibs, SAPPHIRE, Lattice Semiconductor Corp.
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|   Model lvc250f120aaaaaaaaod
[Model] lvc250f120aaaaaaaaod
Model_type I/O_open_drain
Polarity   Non-Inverting
Enable   Active-Low
Vinl =  0.700V
Vinh =  1.700V
Vmeas =  1.250V
Cref =  0.0F
Rref =  1.000M
Vref =  2.5V
C_comp   5.000pF   4.000pF   5.500pF
[Temperature Range]   25.000   0.125k   -40.000
[Voltage Range]   2.500V   2.380V   2.630V
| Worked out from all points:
|   slope of the pulldown table from 0 to 0.375 V, typ, clamps not added: 22.6 ohm
|   GND clamp passes 1 mA (typ) near -0.54 V on its own axis
|   falling waveform, R_fixture 50.000, V_fixture 2.500: 20-80 % time 269ps typ, 316ps min, 255ps max; typ from 2.5 V to 0.973 V
[Pulldown]
|Voltage   I(typ)   I(min)   I(max)
-2.5V     -45.07mA   -50.12mA   -42.75mA
-1.54V    -42.89mA   -47.46mA   -40.12mA
-1.14V    -38.8mA    -42.57mA   -36.2mA
-740mV    -32.8mA    -34.91mA   -31.49mA
-420mV    -21.11mA   -21.89mA   -20.84mA
60mV      3.118mA    3.096mA    3.169mA
300mV     13.77mA    13.66mA    14.07mA
620mV     23.97mA    23.75mA    24.66mA
940mV     30.11mA    29.82mA    31.17mA
1.42V     33.22mA    32.98mA    34.53mA
3.5V      35.44mA    35.53mA    36.25mA
4.94V     39.95mA    39.54mA    41.55mA
[GND_clamp]
|Voltage   I(typ)   I(min)   I(max)
-2.5V     -3.07A     -2.187A    -4.081A
-1.18V    -407.1mA   -387.7mA   -341.4mA
-1.12V    -318.3mA   -325.7mA   -243.4mA
-1.06V    -236.4mA   -267mA     -161mA
-1V       -166mA     -211.9mA   -103.6mA
-940mV    -112.7mA   -161.4mA   -61.29mA
-880mV    -70.72mA   -119.2mA   -32.88mA
-820mV    -39.32mA   -86.38mA   -17.94mA
-760mV    -19.01mA   -59.62mA   -11.38mA
-640mV    -3.835mA   -21.83mA   -4.519mA
-400mV    -48.51uA   -432.2uA   -43.03uA
2.48V     0A         0A         0A
[Ramp]
| variable   typ   min   max
dV/dt_r 0.940/0.232n   0.919/0.263n   0.978/0.221n
dV/dt_f 0.916/0.269n   0.882/0.314n   0.965/0.256n
R_load = 50.000
[Falling Waveform]
R_fixture= 50.000
V_fixture= 2.500
V_fixture_min= 2.380
V_fixture_max= 2.630
|time   V(typ)   V(min)   V(max)
0s        2.5V       2.38V      2.63V
294ps     2.507V     2.38V      2.641V
398ps     2.481V     2.384V     2.145V
545ps     1.833V     2.388V     1.539V
747ps     1.257V     1.702V     1.162V
870ps     1.099V     1.366V     1.081V
1.007ns   1.023V     1.135V     1.045V
1.22ns    986mV      970.3mV    1.03V
1.561ns   981.9mV    917.9mV    1.029V
10ns      973.5mV    909.7mV    1.021V
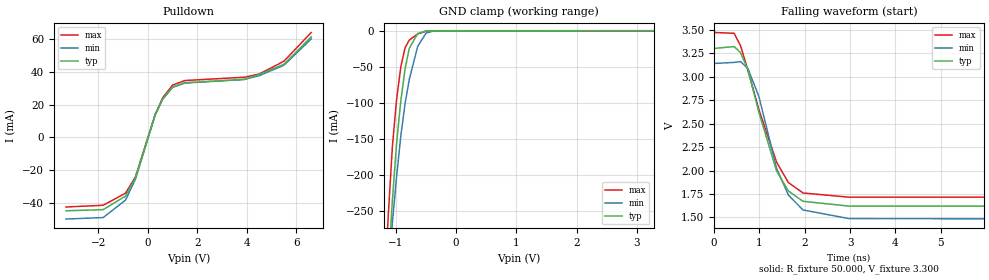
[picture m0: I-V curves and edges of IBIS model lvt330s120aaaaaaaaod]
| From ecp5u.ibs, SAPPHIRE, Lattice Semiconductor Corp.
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|   Model lvt330s120aaaaaaaaod
[Model] lvt330s120aaaaaaaaod
Model_type I/O_open_drain
Polarity   Non-Inverting
Enable   Active-Low
Vinl =  0.800V
Vinh =  2.000V
Vmeas =  1.650V
Cref =  0.0F
Rref =  1.000M
Vref =  3.3V
C_comp   5.000pF   4.000pF   5.500pF
[Temperature Range]   25.000   0.125k   -40.000
[Voltage Range]   3.300V   3.140V   3.470V
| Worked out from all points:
|   slope of the pulldown table from 0 to 0.495 V, typ, clamps not added: 24.2 ohm
|   GND clamp passes 1 mA (typ) near -0.54 V on its own axis
|   falling waveform, R_fixture 50.000, V_fixture 3.300: 20-80 % time 602ps typ, 573ps min, 683ps max; typ from 3.3 V to 1.62 V
[Pulldown]
|Voltage   I(typ)   I(min)   I(max)
-3.3V     -45.07mA   -50.13mA   -42.75mA
-1.8V     -44.35mA   -49.21mA   -41.67mA
-900mV    -36.06mA   -38.52mA   -34.28mA
-500mV    -24.74mA   -25.78mA   -24.33mA
300mV     13.77mA    13.66mA    14.07mA
600mV     23.46mA    23.24mA    24.12mA
1V        30.83mA    30.54mA    31.94mA
1.5V      33.4mA     33.17mA    34.73mA
3.9V      35.43mA    35.37mA    36.75mA
4.5V      38.49mA    37.71mA    38.7mA
5.5V      44.71mA    44.12mA    46.58mA
6.6V      61.45mA    60.23mA    64.17mA
[GND_clamp]
|Voltage   I(typ)   I(min)   I(max)
-3.3V     -4.927A    -3.455A    -6.917A
-1.2V     -438mA     -409mA     -376.6mA
-1.13V    -332.7mA   -335.8mA   -258.9mA
-1.06V    -236.4mA   -267mA     -161mA
-990mV    -156.1mA   -203.1mA   -95.6mA
-920mV    -97.57mA   -146.3mA   -50.22mA
-850mV    -53.64mA   -101.9mA   -23.95mA
-780mV    -24.57mA   -67.95mA   -13.06mA
-640mV    -3.835mA   -21.83mA   -4.519mA
-500mV    -471.8uA   -3.197mA   -537.5uA
-360mV    -15.56uA   -174.4uA   -12.69uA
3.28V     0A         0A         0A
[Ramp]
| variable   typ   min   max
dV/dt_r   1.008/0.531n   0.994/0.600n   1.053/0.515n
dV/dt_f   1.008/0.611n   0.994/0.582n   1.053/0.689n
R_load = 50.000
[Falling Waveform]
R_fixture= 50.000
V_fixture= 3.300
V_fixture_min= 3.140
V_fixture_max= 3.470
|time   V(typ)   V(min)   V(max)
0s        3.3V       3.14V      3.47V
442ps     3.32V      3.151V     3.461V
585ps     3.254V     3.16V      3.328V
748ps     3.074V     3.084V     3.064V
990ps     2.618V     2.786V     2.646V
1.378ns   1.997V     2.026V     2.09V
1.638ns   1.782V     1.739V     1.872V
1.961ns   1.672V     1.58V      1.761V
2.974ns   1.621V     1.488V     1.716V
10ns      1.619V     1.483V     1.716V
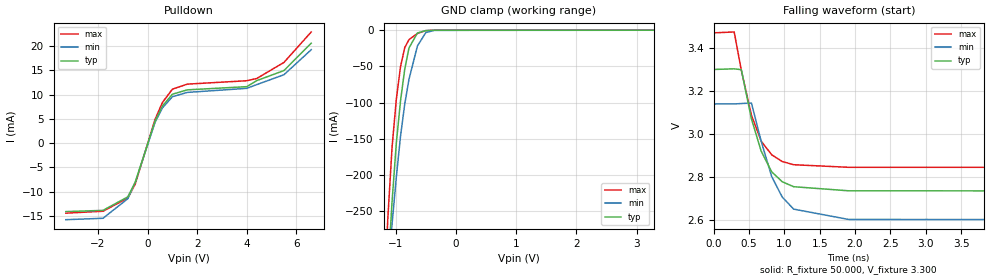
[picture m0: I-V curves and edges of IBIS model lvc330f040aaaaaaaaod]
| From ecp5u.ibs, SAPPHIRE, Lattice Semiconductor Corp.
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|   Model lvc330f040aaaaaaaaod
[Model] lvc330f040aaaaaaaaod
Model_type I/O_open_drain
Polarity   Non-Inverting
Enable   Active-Low
Vinl =  0.800V
Vinh =  2.000V
Vmeas =  1.650V
Cref =  0.0F
Rref =  1.000M
Vref =  3.3V
C_comp   5.000pF   4.000pF   5.500pF
[Temperature Range]   25.000   0.125k   -40.000
[Voltage Range]   3.300V   3.140V   3.470V
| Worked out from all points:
|   slope of the pulldown table from 0 to 0.495 V, typ, clamps not added: 73.9 ohm
|   GND clamp passes 1 mA (typ) near -0.54 V on its own axis
|   falling waveform, R_fixture 50.000, V_fixture 3.300: 20-80 % time 312ps typ, 338ps min, 302ps max; typ from 3.3 V to 2.74 V
[Pulldown]
|Voltage   I(typ)   I(min)   I(max)
-3.3V     -14.12mA   -15.79mA   -14.44mA
-1.8V     -13.87mA   -15.5mA    -14.05mA
-800mV    -11.08mA   -11.47mA   -11.33mA
-500mV    -8.065mA   -8.084mA   -8.464mA
300mV     4.505mA    4.281mA    4.905mA
600mV     7.672mA    7.282mA    8.406mA
1V        10.09mA    9.572mA    11.13mA
1.6V      10.99mA    10.46mA    12.17mA
4V        11.65mA    11.3mA     12.87mA
4.4V      12.89mA    12.07mA    13.33mA
5.5V      14.97mA    14.11mA    16.65mA
6.6V      20.62mA    19.27mA    22.93mA
[GND_clamp]
|Voltage   I(typ)   I(min)   I(max)
-3.3V     -4.927A    -3.455A    -6.917A
-1.2V     -438mA     -409mA     -376.6mA
-1.13V    -332.7mA   -335.8mA   -258.9mA
-1.06V    -236.4mA   -267mA     -161mA
-990mV    -156.1mA   -203.1mA   -95.6mA
-920mV    -97.57mA   -146.3mA   -50.22mA
-850mV    -53.64mA   -101.9mA   -23.95mA
-780mV    -24.57mA   -67.95mA   -13.06mA
-640mV    -3.835mA   -21.83mA   -4.519mA
-500mV    -471.8uA   -3.197mA   -537.5uA
-360mV    -15.56uA   -174.4uA   -12.69uA
3.28V     0A         0A         0A
[Ramp]
| variable   typ   min   max
dV/dt_r   0.338/0.311n   0.322/0.346n   0.375/0.292n
dV/dt_f   0.338/0.317n   0.322/0.336n   0.375/0.301n
R_load = 50.000
[Falling Waveform]
R_fixture= 50.000
V_fixture= 3.300
V_fixture_min= 3.140
V_fixture_max= 3.470
|time   V(typ)   V(min)   V(max)
0s        3.3V       3.14V      3.47V
289ps     3.303V     3.14V      3.474V
390ps     3.299V     3.142V     3.296V
533ps     3.071V     3.144V     3.088V
670ps     2.922V     2.968V     2.968V
820ps     2.825V     2.803V     2.904V
969ps     2.779V     2.708V     2.873V
1.131ns   2.756V     2.652V     2.858V
1.911ns   2.737V     2.604V     2.846V
10ns      2.736V     2.603V     2.846V
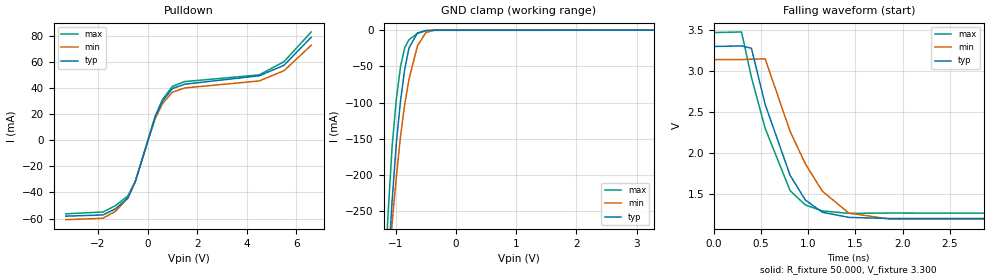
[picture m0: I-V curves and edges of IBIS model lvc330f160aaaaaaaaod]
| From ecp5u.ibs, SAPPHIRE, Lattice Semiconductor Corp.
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|   Model lvc330f160aaaaaaaaod
[Model] lvc330f160aaaaaaaaod
Model_type I/O_open_drain
Polarity   Non-Inverting
Enable   Active-Low
Vinl =  0.800V
Vinh =  2.000V
Vmeas =  1.650V
Cref =  0.0F
Rref =  1.000M
Vref =  3.3V
C_comp   5.000pF   4.000pF   5.500pF
[Temperature Range]   25.000   0.125k   -40.000
[Voltage Range]   3.300V   3.140V   3.470V
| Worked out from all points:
|   slope of the pulldown table from 0 to 0.495 V, typ, clamps not added: 18.7 ohm
|   GND clamp passes 1 mA (typ) near -0.54 V on its own axis
|   falling waveform, R_fixture 50.000, V_fixture 3.300: 20-80 % time 376ps typ, 463ps min, 351ps max; typ from 3.3 V to 1.2 V
[Pulldown]
|Voltage   I(typ)   I(min)   I(max)
-3.3V     -58.2mA    -60.91mA   -56.39mA
-1.8V     -57.26mA   -59.78mA   -54.99mA
-1.3V     -52.58mA   -54.51mA   -50.15mA
-800mV    -44.22mA   -44.44mA   -42.72mA
-500mV    -32.04mA   -31.37mA   -31.77mA
300mV     17.85mA    16.63mA    18.36mA
600mV     30.4mA     28.29mA    31.47mA
1V        39.96mA    37.2mA     41.67mA
1.5V      43.3mA     40.41mA    45.3mA
4.5V      49.76mA    45.79mA    50.43mA
5.5V      57.79mA    53.65mA    60.58mA
6.6V      79.4mA     73.23mA    83.46mA
[GND_clamp]
|Voltage   I(typ)   I(min)   I(max)
-3.3V     -4.927A    -3.455A    -6.917A
-1.2V     -438mA     -409mA     -376.6mA
-1.13V    -332.7mA   -335.8mA   -258.9mA
-1.06V    -236.4mA   -267mA     -161mA
-990mV    -156.1mA   -203.1mA   -95.6mA
-920mV    -97.57mA   -146.3mA   -50.22mA
-850mV    -53.64mA   -101.9mA   -23.95mA
-780mV    -24.57mA   -67.95mA   -13.06mA
-640mV    -3.835mA   -21.83mA   -4.519mA
-500mV    -471.8uA   -3.197mA   -537.5uA
-360mV    -15.56uA   -174.4uA   -12.69uA
3.28V     0A         0A         0A
[Ramp]
| variable   typ   min   max
dV/dt_r   1.260/0.204n   1.171/0.251n   1.328/0.192n
dV/dt_f   1.260/0.379n   1.172/0.466n   1.328/0.354n
R_load = 50.000
[Falling Waveform]
R_fixture= 50.000
V_fixture= 3.300
V_fixture_min= 3.140
V_fixture_max= 3.470
|time   V(typ)   V(min)   V(max)
0s        3.3V       3.14V      3.47V
294ps     3.307V     3.14V      3.477V
398ps     3.279V     3.145V     2.926V
544ps     2.593V     3.149V     2.302V
808ps     1.728V     2.264V     1.541V
969ps     1.427V     1.869V     1.367V
1.149ns   1.278V     1.535V     1.294V
1.429ns   1.215V     1.268V     1.264V
1.859ns   1.201V     1.195V     1.268V
10ns      1.2V       1.187V     1.256V
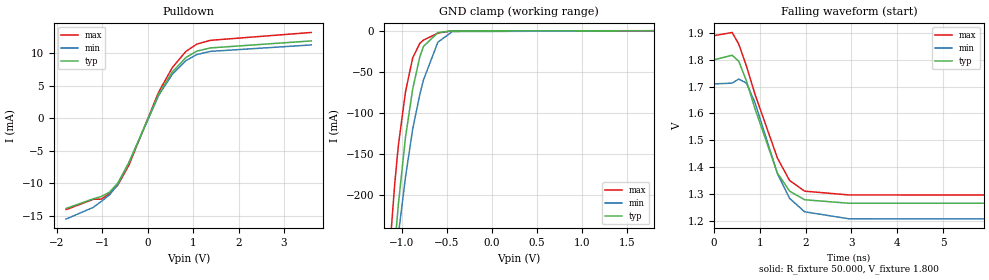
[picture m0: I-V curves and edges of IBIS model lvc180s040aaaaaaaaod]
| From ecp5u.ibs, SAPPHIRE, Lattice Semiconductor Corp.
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|   Model lvc180s040aaaaaaaaod
[Model] lvc180s040aaaaaaaaod
Model_type I/O_open_drain
Polarity   Non-Inverting
Enable   Active-Low
Vinl =  0.630V
Vinh =  1.170V
Vmeas =  0.900V
Cref =  0.0F
Rref =  1.000M
Vref =  1.8V
C_comp   5.000pF   4.000pF   5.500pF
[Temperature Range]   25.000   0.125k   -40.000
[Voltage Range]   1.800V   1.710V   1.890V
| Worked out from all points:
|   slope of the pulldown table from 0 to 0.27 V, typ, clamps not added: 65.7 ohm
|   GND clamp passes 1 mA (typ) near -0.54 V on its own axis
|   falling waveform, R_fixture 50.000, V_fixture 1.800: 20-80 % time 637ps typ, 609ps min, 716ps max; typ from 1.8 V to 1.26 V
[Pulldown]
|Voltage   I(typ)   I(min)   I(max)
-1.8V     -13.87mA   -15.5mA    -14.05mA
-1.2V     -12.39mA   -13.7mA    -12.46mA
-1.02V    -12.02mA   -12.76mA   -12.43mA
-840mV    -11.35mA   -11.76mA   -11.57mA
-660mV    -9.94mA    -10.14mA   -10.28mA
-420mV    -6.892mA   -6.861mA   -7.26mA
240mV     3.719mA    3.535mA    4.043mA
540mV     7.135mA    6.775mA    7.808mA
840mV     9.359mA    8.879mA    10.3mA
1.08V     10.34mA    9.814mA    11.42mA
1.38V     10.83mA    10.3mA     12mA
3.6V      11.91mA    11.29mA    13.21mA
[GND_clamp]
|Voltage   I(typ)   I(min)   I(max)
-1.8V     -1.552A    -1.161A    -1.853A
-1.16V    -376.9mA   -366.7mA   -307.6mA
-1.12V    -318.4mA   -325.7mA   -243.6mA
-1.08V    -262.9mA   -286.2mA   -185.9mA
-1.04V    -211.3mA   -248.3mA   -139.6mA
-960mV    -129.1mA   -177.6mA   -73.98mA
-880mV    -70.75mA   -119.2mA   -32.93mA
-800mV    -31.34mA   -76.89mA   -15.17mA
-760mV    -19.02mA   -59.64mA   -11.38mA
-600mV    -2.287mA   -13.94mA   -2.904mA
-440mV    -132uA     -1.017mA   -127uA
1.8V      0A         0A         0A
[Ramp]
| variable   typ   min   max
dV/dt_r   0.321/0.518n   0.302/0.553n   0.355/0.379n
dV/dt_f   0.321/0.642n   0.302/0.625n   0.357/0.729n
R_load = 50.000
[Falling Waveform]
R_fixture= 50.000
V_fixture= 1.800
V_fixture_min= 1.710
V_fixture_max= 1.890
|time   V(typ)   V(min)   V(max)
0s        1.8V       1.71V      1.89V
394ps     1.817V     1.713V     1.902V
538ps     1.795V     1.728V     1.859V
708ps     1.721V     1.713V     1.776V
894ps     1.617V     1.64V      1.671V
1.384ns   1.377V     1.375V     1.433V
1.649ns   1.31V      1.283V     1.35V
1.978ns   1.278V     1.233V     1.31V
2.944ns   1.265V     1.207V     1.296V
10ns      1.265V     1.206V     1.295V
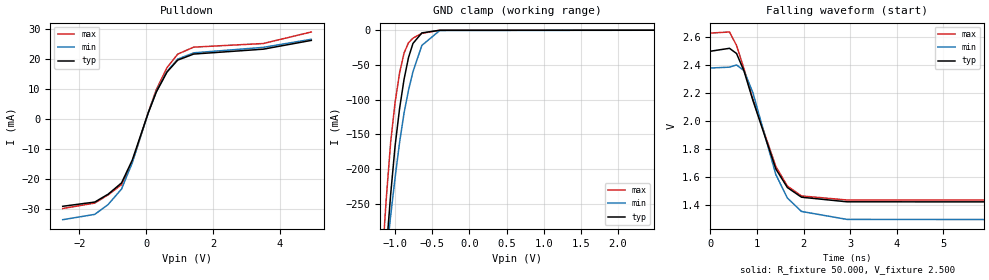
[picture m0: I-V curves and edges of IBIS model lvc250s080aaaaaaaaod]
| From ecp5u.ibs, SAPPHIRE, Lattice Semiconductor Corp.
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|   Model lvc250s080aaaaaaaaod
[Model] lvc250s080aaaaaaaaod
Model_type I/O_open_drain
Polarity   Non-Inverting
Enable   Active-Low
Vinl =  0.700V
Vinh =  1.700V
Vmeas =  1.250V
Cref =  0.0F
Rref =  1.000M
Vref =  2.5V
C_comp   5.000pF   4.000pF   5.500pF
[Temperature Range]   25.000   0.125k   -40.000
[Voltage Range]   2.500V   2.380V   2.630V
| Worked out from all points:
|   slope of the pulldown table from 0 to 0.375 V, typ, clamps not added: 34.9 ohm
|   GND clamp passes 1 mA (typ) near -0.54 V on its own axis
|   falling waveform, R_fixture 50.000, V_fixture 2.500: 20-80 % time 640ps typ, 594ps min, 698ps max; typ from 2.5 V to 1.42 V
[Pulldown]
|Voltage   I(typ)   I(min)   I(max)
-2.5V     -29mA      -33.45mA   -29.74mA
-1.54V    -27.59mA   -31.68mA   -27.93mA
-1.14V    -24.97mA   -28.41mA   -25.2mA
-740mV    -21.24mA   -23.27mA   -21.81mA
-420mV    -13.7mA    -14.59mA   -14.42mA
60mV      2.026mA    2.064mA    2.192mA
300mV     8.946mA    9.108mA    9.732mA
620mV     15.57mA    15.83mA    17.06mA
940mV     19.56mA    19.88mA    21.55mA
1.42V     21.58mA    21.99mA    23.88mA
3.5V      23.2mA     23.8mA     25.08mA
4.94V     26.12mA    26.49mA    28.92mA
[GND_clamp]
|Voltage   I(typ)   I(min)   I(max)
-2.5V     -3.07A     -2.187A    -4.081A
-1.18V    -407.1mA   -387.7mA   -341.4mA
-1.12V    -318.3mA   -325.7mA   -243.4mA
-1.06V    -236.4mA   -267mA     -161mA
-1V       -166mA     -211.9mA   -103.6mA
-940mV    -112.7mA   -161.4mA   -61.29mA
-880mV    -70.72mA   -119.2mA   -32.88mA
-820mV    -39.32mA   -86.38mA   -17.94mA
-760mV    -19.01mA   -59.62mA   -11.38mA
-640mV    -3.835mA   -21.83mA   -4.519mA
-400mV    -48.51uA   -432.2uA   -43.03uA
2.48V     0A         0A         0A
[Ramp]
| variable   typ   min   max
dV/dt_r   0.647/0.589n   0.651/0.626n   0.717/0.501n
dV/dt_f   0.647/0.648n   0.652/0.602n   0.717/0.706n
R_load = 50.000
[Falling Waveform]
R_fixture= 50.000
V_fixture= 2.500
V_fixture_min= 2.380
V_fixture_max= 2.630
|time   V(typ)   V(min)   V(max)
0s        2.5V       2.38V      2.63V
412ps     2.521V     2.386V     2.638V
563ps     2.484V     2.402V     2.542V
723ps     2.359V     2.361V     2.375V
914ps     2.149V     2.203V     2.155V
1.406ns   1.657V     1.617V     1.675V
1.654ns   1.524V     1.449V     1.535V
1.956ns   1.455V     1.353V     1.464V
2.933ns   1.422V     1.296V     1.435V
10ns      1.421V     1.294V     1.435V
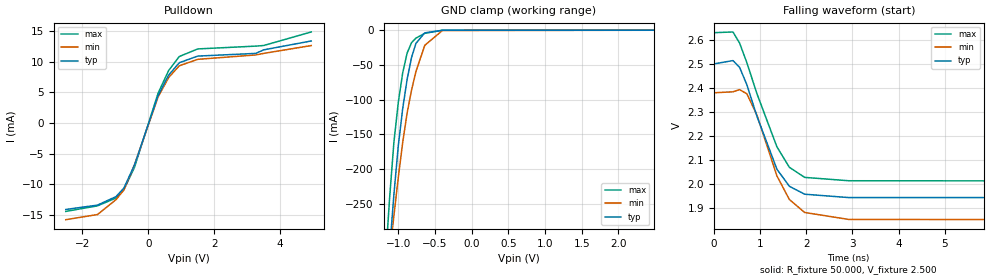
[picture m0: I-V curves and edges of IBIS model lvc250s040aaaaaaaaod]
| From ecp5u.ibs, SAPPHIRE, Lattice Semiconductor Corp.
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|   Model lvc250s040aaaaaaaaod
[Model] lvc250s040aaaaaaaaod
Model_type I/O_open_drain
Polarity   Non-Inverting
Enable   Active-Low
Vinl =  0.700V
Vinh =  1.700V
Vmeas =  1.250V
Cref =  0.0F
Rref =  1.000M
Vref =  2.5V
C_comp   5.000pF   4.000pF   5.500pF
[Temperature Range]   25.000   0.125k   -40.000
[Voltage Range]   2.500V   2.380V   2.630V
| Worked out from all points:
|   slope of the pulldown table from 0 to 0.375 V, typ, clamps not added: 69.2 ohm
|   GND clamp passes 1 mA (typ) near -0.54 V on its own axis
|   falling waveform, R_fixture 50.000, V_fixture 2.500: 20-80 % time 625ps typ, 602ps min, 699ps max; typ from 2.5 V to 1.94 V
[Pulldown]
|Voltage   I(typ)   I(min)   I(max)
-2.5V     -14.12mA   -15.79mA   -14.44mA
-1.54V    -13.41mA   -14.95mA   -13.53mA
-980mV    -12.03mA   -12.53mA   -12.26mA
-740mV    -10.64mA   -10.95mA   -10.92mA
-420mV    -6.892mA   -6.861mA   -7.26mA
300mV     4.505mA    4.281mA    4.905mA
620mV     7.84mA     7.441mA    8.594mA
940mV     9.849mA    9.346mA    10.86mA
1.5V      10.93mA    10.4mA     12.1mA
3.26V     11.37mA    11.12mA    12.56mA
3.5V      11.95mA    11.37mA    12.66mA
4.94V     13.4mA     12.65mA    14.87mA
[GND_clamp]
|Voltage   I(typ)   I(min)   I(max)
-2.5V     -3.07A     -2.187A    -4.081A
-1.18V    -407.1mA   -387.7mA   -341.4mA
-1.12V    -318.3mA   -325.7mA   -243.4mA
-1.06V    -236.4mA   -267mA     -161mA
-1V       -166mA     -211.9mA   -103.6mA
-940mV    -112.7mA   -161.4mA   -61.29mA
-880mV    -70.72mA   -119.2mA   -32.88mA
-820mV    -39.32mA   -86.38mA   -17.94mA
-760mV    -19.01mA   -59.62mA   -11.38mA
-640mV    -3.835mA   -21.83mA   -4.519mA
-400mV    -48.51uA   -432.2uA   -43.03uA
2.48V     0A         0A         0A
[Ramp]
| variable   typ   min   max
dV/dt_r   0.334/0.911n   0.317/0.712n   0.381/0.539n
dV/dt_f   0.334/0.632n   0.317/0.609n   0.370/0.706n
R_load = 50.000
[Falling Waveform]
R_fixture= 50.000
V_fixture= 2.500
V_fixture_min= 2.380
V_fixture_max= 2.630
|time   V(typ)   V(min)   V(max)
0s        2.5V       2.38V      2.63V
415ps     2.514V     2.384V     2.633V
558ps     2.486V     2.393V     2.587V
716ps     2.413V     2.376V     2.505V
936ps     2.281V     2.286V     2.375V
1.366ns   2.062V     2.034V     2.155V
1.635ns   1.991V     1.936V     2.07V
1.966ns   1.958V     1.882V     2.028V
2.92ns    1.944V     1.853V     2.014V
10ns      1.944V     1.852V     2.013V
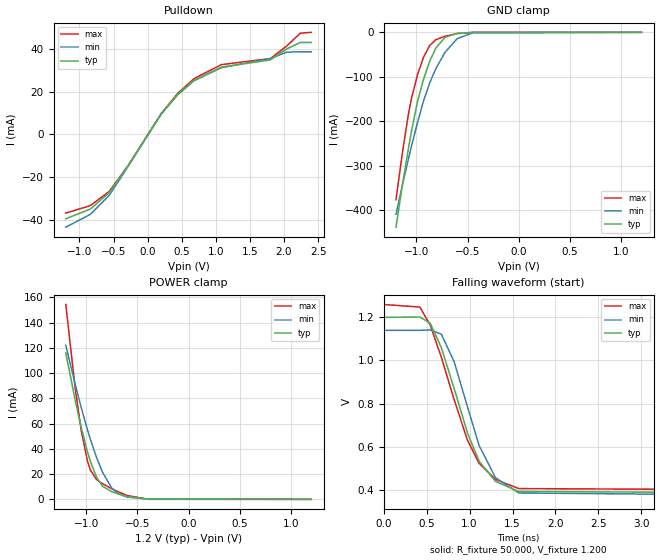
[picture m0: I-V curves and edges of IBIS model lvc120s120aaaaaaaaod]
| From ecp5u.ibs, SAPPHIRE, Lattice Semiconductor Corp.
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|   Model lvc120s120aaaaaaaaod
[Model] lvc120s120aaaaaaaaod
Model_type I/O_open_drain
Polarity   Non-Inverting
Enable   Active-Low
Vinl =  0.420V
Vinh =  0.780V
Vmeas =  0.600V
Cref =  0.0F
Rref =  1.000M
Vref =  1.2V
C_comp   5.000pF   4.000pF   5.500pF
[Temperature Range]   25.000   0.125k   -40.000
[Voltage Range]   1.200V   1.140V   1.260V
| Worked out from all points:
|   slope of the pulldown table from 0 to 0.18 V, typ, clamps not added: 20.5 ohm
|   GND clamp passes 1 mA (typ) near -0.54 V on its own axis
|   POWER clamp passes 1 mA (typ) near -0.52 V on its own axis
|   falling waveform, R_fixture 50.000, V_fixture 1.200: 20-80 % time 408ps typ, 380ps min, 437ps max; typ from 1.2 V to 0.374 V
[Pulldown]
|Voltage   I(typ)   I(min)   I(max)
-1.2V     -39.57mA   -43.49mA   -36.91mA
-840mV    -35mA      -37.5mA    -33.37mA
-560mV    -27.2mA    -28.46mA   -26.61mA
-280mV    -14.34mA   -14.7mA    -14.27mA
200mV     9.672mA    9.598mA    9.859mA
440mV     18.76mA    18.6mA     19.22mA
680mV     25.42mA    25.18mA    26.19mA
1.08V     31.6mA     31.31mA    32.77mA
1.8V      34.98mA    35.62mA    35.62mA
2.04V     40.18mA    38.64mA    41.52mA
2.24V     43.18mA    38.79mA    47.54mA
2.4V      43.18mA    38.79mA    47.93mA
[GND_clamp]
|Voltage   I(typ)   I(min)   I(max)
-1.2V     -438mA     -409mA     -376.5mA
-1.14V    -347.3mA   -346mA     -274.9mA
-1.08V    -262.9mA   -286.2mA   -185.9mA
-1.05V    -223.7mA   -257.6mA   -150mA
-990mV    -156.1mA   -203.2mA   -95.66mA
-930mV    -105mA     -153.7mA   -55.58mA
-870mV    -64.74mA   -113.2mA   -29.56mA
-810mV    -35.2mA    -81.56mA   -16.45mA
-720mV    -11.09mA   -44.69mA   -8.691mA
-600mV    -2.287mA   -13.94mA   -2.904mA
-450mV    -166.2uA   -1.247mA   -164.1uA
1.2V      0A         0A         0A
[POWER_clamp]
|Voltage   I(typ)   I(min)   I(max)
-1.2V     116mA      122mA      154.3mA
-1.11V    79.16mA    91.62mA    88.95mA
-1.05V    57.22mA    72.86mA    54.95mA
-990mV    38.24mA    55.58mA    30.91mA
-960mV    30.16mA    47.6mA     23.26mA
-900mV    17.56mA    33.21mA    15.69mA
-840mV    10.28mA    21.27mA    12.35mA
-750mV    6.057mA    8.879mA    8.362mA
-690mV    4.383mA    4.498mA    6.008mA
-600mV    2.3mA      1.815mA    3.014mA
-390mV    53.86uA    109.2uA    34.95uA
1.2V      0A         0A         0A
[Ramp]
| variable   typ   min   max
dV/dt_r 0.496/0.287n   0.471/0.285n   0.523/0.280n
dV/dt_f 0.496/0.424n   0.471/0.388n   0.523/0.453n
R_load = 50.000
[Falling Waveform]
R_fixture= 50.000
V_fixture= 1.200
V_fixture_min= 1.140
V_fixture_max= 1.260
|time   V(typ)   V(min)   V(max)
0s        1.2V       1.14V      1.26V
421ps     1.202V     1.14V      1.248V
541ps     1.173V     1.142V     1.165V
671ps     1.06V      1.122V     1.015V
821ps     868.4mV    993.4mV    816.2mV
976ps     662.1mV    783.7mV    629.4mV
1.111ns   531.7mV    604.6mV    522.2mV
1.302ns   438.2mV    455.2mV    447.3mV
1.572ns   391.4mV    384.4mV    404.8mV
10ns      374.1mV    354.9mV    388.6mV
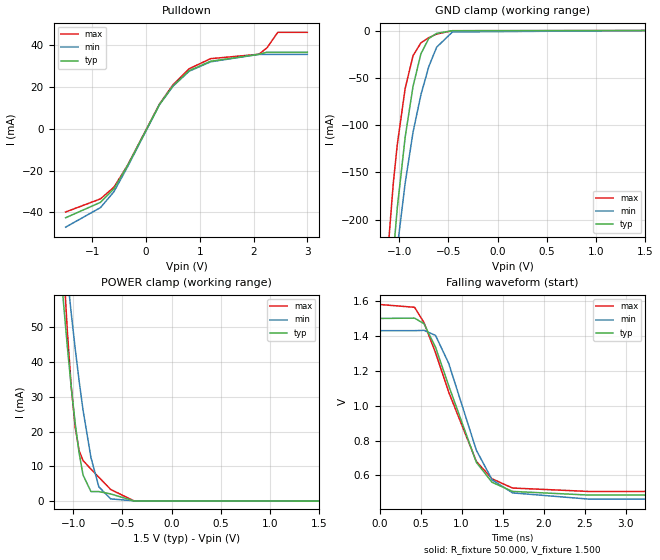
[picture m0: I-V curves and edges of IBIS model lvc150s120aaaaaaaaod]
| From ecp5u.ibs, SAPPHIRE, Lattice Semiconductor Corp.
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|   Model lvc150s120aaaaaaaaod
[Model] lvc150s120aaaaaaaaod
Model_type I/O_open_drain
Polarity   Non-Inverting
Enable   Active-Low
Vinl =  0.375V
Vinh =  1.125V
Vmeas =  0.750V
Cref =  0.0F
Rref =  1.000M
Vref =  1.5V
C_comp   5.000pF   4.000pF   5.500pF
[Temperature Range]   25.000   0.125k   -40.000
[Voltage Range]   1.500V   1.430V   1.580V
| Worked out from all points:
|   slope of the pulldown table from 0 to 0.225 V, typ, clamps not added: 21 ohm
|   GND clamp passes 1 mA (typ) near -0.54 V on its own axis
|   POWER clamp passes 1 mA (typ) near -0.53 V on its own axis
|   falling waveform, R_fixture 50.000, V_fixture 1.500: 20-80 % time 452ps typ, 413ps min, 494ps max; typ from 1.5 V to 0.487 V
[Pulldown]
|Voltage   I(typ)   I(min)   I(max)
-1.5V     -42.59mA   -47.09mA   -39.82mA
-850mV    -35.19mA   -37.71mA   -33.53mA
-600mV    -28.67mA   -30.1mA    -27.92mA
-350mV    -17.76mA   -18.32mA   -17.6mA
250mV     11.78mA    11.69mA    12.02mA
500mV     20.64mA    20.46mA    21.18mA
800mV     27.91mA    27.63mA    28.82mA
1.2V      32.4mA     32.14mA    33.65mA
2.1V      35.74mA    35.71mA    35.76mA
2.25V     36.77mA    35.71mA    38.88mA
2.45V     36.77mA    35.71mA    46.27mA
3V        36.77mA    35.71mA    46.27mA
[GND_clamp]
|Voltage   I(typ)   I(min)   I(max)
-1.5V     -960.1mA   -762.7mA   -1.034A
-1.14V    -347.3mA   -346mA     -275mA
-1.1V     -290.2mA   -305.8mA   -213.7mA
-1.06V    -236.5mA   -267.1mA   -161mA
-1.02V    -187.7mA   -229.9mA   -120.7mA
-940mV    -112.8mA   -161.5mA   -61.34mA
-860mV    -59.06mA   -107.5mA   -26.59mA
-780mV    -24.6mA    -67.97mA   -13.06mA
-700mV    -8.431mA   -38.1mA    -7.531mA
-620mV    -2.969mA   -17.61mA   -3.668mA
-460mV    -207.8uA   -1.521mA   -211uA
1.5V      0A         0A         0A
[POWER_clamp]
|Voltage   I(typ)   I(min)   I(max)
-1.5V     219.9mA    211.4mA    392.2mA
-1.1V     57.42mA    76.24mA    68.86mA
-1.06V    44.49mA    64.83mA    49mA
-1.02V    32.72mA    54.02mA    32.88mA
-980mV    22.39mA    43.9mA     21.21mA
-940mV    13.84mA    34.56mA    14.51mA
-900mV    7.485mA    26.13mA    11.67mA
-820mV    2.749mA    12.54mA    9.219mA
-740mV    2.749mA    4.119mA    6.881mA
-620mV    2.073mA    648uA      3.366mA
-380mV    40.17uA    80.2uA     25.1uA
1.5V      0A         0A         0A
[Ramp]
| variable   typ   min   max
dV/dt_r 0.608/0.280n   0.580/0.285n   0.643/0.281n
dV/dt_f 0.608/0.457n   0.580/0.418n   0.643/0.501n
R_load = 50.000
[Falling Waveform]
R_fixture= 50.000
V_fixture= 1.500
V_fixture_min= 1.430
V_fixture_max= 1.580
|time   V(typ)   V(min)   V(max)
0s        1.5V       1.43V      1.58V
427ps     1.502V     1.43V      1.564V
541ps     1.47V      1.432V     1.477V
682ps     1.336V     1.403V     1.304V
842ps     1.116V     1.244V     1.079V
1.18ns    675.3mV    745.1mV    680.7mV
1.371ns   561.1mV    576mV      581mV
1.621ns   508.6mV    500.2mV    528mV
2.551ns   487.6mV    464.5mV    508.3mV
10ns      487.2mV    463.2mV    508.2mV
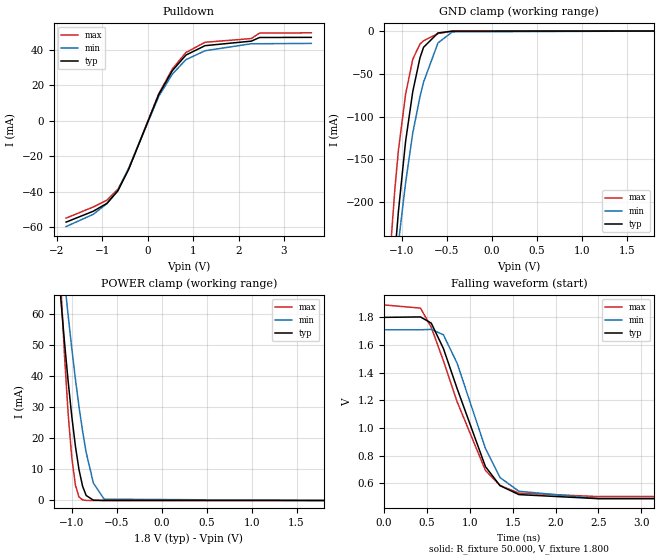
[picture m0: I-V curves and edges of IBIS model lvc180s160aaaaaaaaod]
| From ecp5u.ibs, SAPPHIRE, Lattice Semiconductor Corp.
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|   Model lvc180s160aaaaaaaaod
[Model] lvc180s160aaaaaaaaod
Model_type I/O_open_drain
Polarity   Non-Inverting
Enable   Active-Low
Vinl =  0.630V
Vinh =  1.170V
Vmeas =  0.900V
Cref =  0.0F
Rref =  1.000M
Vref =  1.8V
C_comp   5.000pF   4.000pF   5.500pF
[Temperature Range]   25.000   0.125k   -40.000
[Voltage Range]   1.800V   1.710V   1.890V
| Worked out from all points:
|   slope of the pulldown table from 0 to 0.27 V, typ, clamps not added: 16.6 ohm
|   GND clamp passes 1 mA (typ) near -0.54 V on its own axis
|   POWER clamp passes 1 mA (typ) near -0.82 V on its own axis
|   falling waveform, R_fixture 50.000, V_fixture 1.800: 20-80 % time 444ps typ, 409ps min, 480ps max; typ from 1.8 V to 0.487 V
[Pulldown]
|Voltage   I(typ)   I(min)   I(max)
-1.8V     -57.26mA   -59.78mA   -54.99mA
-1.2V     -51.09mA   -52.83mA   -48.7mA
-900mV    -46.65mA   -46.82mA   -44.83mA
-660mV    -39.62mA   -39.31mA   -38.72mA
-420mV    -27.34mA   -26.64mA   -27.21mA
240mV     14.73mA    13.73mA    15.13mA
540mV     28.27mA    26.32mA    29.23mA
840mV     37.09mA    34.5mA     38.57mA
1.26V     42.38mA    39.51mA    44.3mA
2.28V     44.95mA    43.48mA    46.4mA
2.46V     47mA       43.48mA    49.48mA
3.6V      47.08mA    43.66mA    49.64mA
[GND_clamp]
|Voltage   I(typ)   I(min)   I(max)
-1.8V     -1.552A    -1.161A    -1.853A
-1.16V    -376.9mA   -366.7mA   -307.6mA
-1.12V    -318.4mA   -325.7mA   -243.6mA
-1.08V    -262.9mA   -286.2mA   -185.9mA
-1.04V    -211.3mA   -248.3mA   -139.6mA
-960mV    -129.1mA   -177.6mA   -73.98mA
-880mV    -70.75mA   -119.2mA   -32.93mA
-800mV    -31.34mA   -76.89mA   -15.17mA
-760mV    -19.02mA   -59.64mA   -11.38mA
-600mV    -2.287mA   -13.94mA   -2.904mA
-440mV    -132uA     -1.017mA   -127uA
1.8V      0A         0A         0A
[POWER_clamp]
|Voltage   I(typ)   I(min)   I(max)
-1.8V     359.2mA    326.9mA    707.4mA
-1.12V    63.92mA    82.11mA    68.17mA
-1.08V    50.49mA    70.43mA    45.93mA
-1.04V    38.1mA     59.31mA    27.62mA
-1V       26.99mA    48.82mA    13.76mA
-960mV    17.48mA    39.07mA    4.982mA
-920mV    9.898mA    30.17mA    1.15mA
-880mV    4.583mA    22.24mA    190.3uA
-840mV    1.605mA    15.42mA    33.78uA
-760mV    99.28uA    5.617mA    8.146uA
-640mV    4.035uA    415.3uA    6.912uA
1.8V      0A         0A         0A
[Ramp]
| variable   typ   min   max
dV/dt_r 0.788/0.279n   0.734/0.280n   0.832/0.278n
dV/dt_f 0.788/0.456n   0.734/0.422n   0.832/0.490n
R_load = 50.000
[Falling Waveform]
R_fixture= 50.000
V_fixture= 1.800
V_fixture_min= 1.710
V_fixture_max= 1.890
|time   V(typ)   V(min)   V(max)
0s        1.8V       1.71V      1.89V
425ps     1.803V     1.71V      1.867V
551ps     1.758V     1.713V     1.728V
692ps     1.575V     1.674V     1.486V
852ps     1.285V     1.468V     1.189V
1.182ns   719.9mV    852mV      692.4mV
1.352ns   581.8mV    640.7mV    583.5mV
1.572ns   517.1mV    541.1mV    527.7mV
2.493ns   487.8mV    489.2mV    502.9mV
10ns      487.4mV    487.5mV    502.8mV
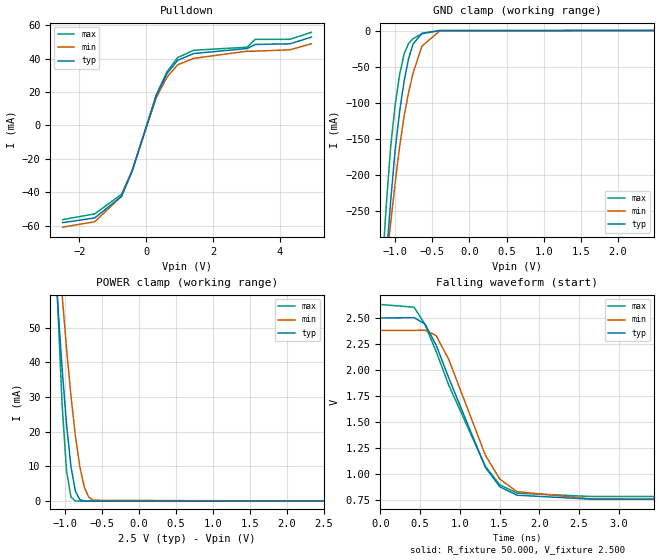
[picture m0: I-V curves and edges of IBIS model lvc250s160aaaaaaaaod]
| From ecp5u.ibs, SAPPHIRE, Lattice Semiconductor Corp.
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|   Model lvc250s160aaaaaaaaod
[Model] lvc250s160aaaaaaaaod
Model_type I/O_open_drain
Polarity   Non-Inverting
Enable   Active-Low
Vinl =  0.700V
Vinh =  1.700V
Vmeas =  1.250V
Cref =  0.0F
Rref =  1.000M
Vref =  2.5V
C_comp   5.000pF   4.000pF   5.500pF
[Temperature Range]   25.000   0.125k   -40.000
[Voltage Range]   2.500V   2.380V   2.630V
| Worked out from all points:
|   slope of the pulldown table from 0 to 0.375 V, typ, clamps not added: 17.5 ohm
|   GND clamp passes 1 mA (typ) near -0.54 V on its own axis
|   POWER clamp passes 1 mA (typ) near -0.81 V on its own axis
|   falling waveform, R_fixture 50.000, V_fixture 2.500: 20-80 % time 543ps typ, 502ps min, 603ps max; typ from 2.5 V to 0.752 V
[Pulldown]
|Voltage   I(typ)   I(min)   I(max)
-2.5V     -58.2mA    -60.91mA   -56.39mA
-1.54V    -55.38mA   -57.65mA   -52.96mA
-740mV    -42.44mA   -42.44mA   -41.18mA
-420mV    -27.34mA   -26.64mA   -27.21mA
300mV     17.85mA    16.63mA    18.36mA
620mV     31.07mA    28.91mA    32.17mA
940mV     39.03mA    36.32mA    40.66mA
1.42V     43.07mA    40.18mA    45.04mA
3.02V     46.08mA    44.49mA    46.86mA
3.26V     48.5mA     44.49mA    51.54mA
4.3V      48.89mA    45.3mA     51.59mA
4.94V     52.89mA    48.89mA    55.77mA
[GND_clamp]
|Voltage   I(typ)   I(min)   I(max)
-2.5V     -3.07A     -2.187A    -4.081A
-1.18V    -407.1mA   -387.7mA   -341.4mA
-1.12V    -318.3mA   -325.7mA   -243.4mA
-1.06V    -236.4mA   -267mA     -161mA
-1V       -166mA     -211.9mA   -103.6mA
-940mV    -112.7mA   -161.4mA   -61.29mA
-880mV    -70.72mA   -119.2mA   -32.88mA
-820mV    -39.32mA   -86.38mA   -17.94mA
-760mV    -19.01mA   -59.62mA   -11.38mA
-640mV    -3.835mA   -21.83mA   -4.519mA
-400mV    -48.51uA   -432.2uA   -43.03uA
2.48V     0A         0A         0A
[POWER_clamp]
|Voltage   I(typ)   I(min)   I(max)
-2.48V    697.4mA    609.7mA    1.52A
-1.16V    78.38mA    94.49mA    93.95mA
-1.1V     57.27mA    76.41mA    56.94mA
-1.04V    38.27mA    59.5mA     27.83mA
-980mV    22.16mA    44.02mA    8.776mA
-920mV    9.963mA    30.32mA    1.16mA
-860mV    2.844mA    18.8mA     75.71uA
-800mV    431.5uA    9.92mA     9.485uA
-740mV    48.76uA    4.059mA    5.733uA
-680mV    7.882uA    1.163mA    5.19uA
-620mV    3.552uA    244uA      4.732uA
2.5V      0A         0A         0A
[Ramp]
| variable   typ   min   max
dV/dt_r 1.049/0.276n   0.976/0.278n   1.111/0.275n
dV/dt_f 1.049/0.550n   0.976/0.511n   1.111/0.607n
R_load = 50.000
[Falling Waveform]
R_fixture= 50.000
V_fixture= 2.500
V_fixture_min= 2.380
V_fixture_max= 2.630
|time   V(typ)   V(min)   V(max)
0s        2.5V       2.38V      2.63V
425ps     2.503V     2.38V      2.604V
560ps     2.444V     2.383V     2.441V
702ps     2.24V      2.331V     2.178V
862ps     1.921V     2.099V     1.852V
1.321ns   1.06V      1.179V     1.071V
1.503ns   873.2mV    947.4mV    892.5mV
1.72ns    791.6mV    825.5mV    811.3mV
2.666ns   752.4mV    754.9mV    778.7mV
10ns      751.8mV    752.6mV    778.5mV
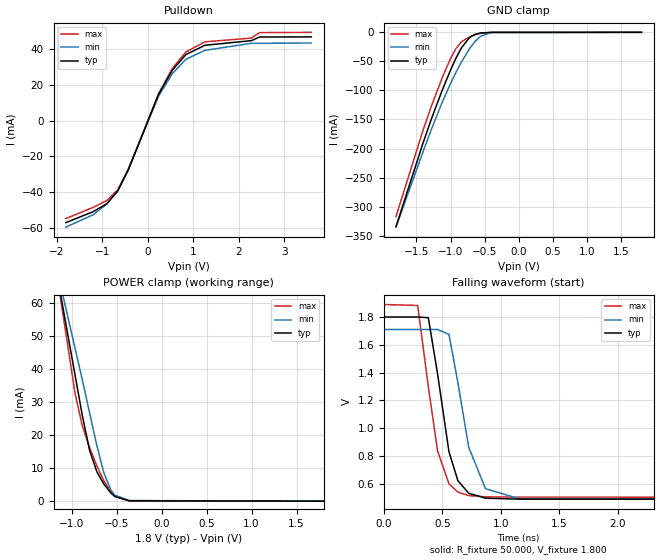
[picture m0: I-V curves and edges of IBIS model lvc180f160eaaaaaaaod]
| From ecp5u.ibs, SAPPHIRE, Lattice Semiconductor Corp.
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|   Model lvc180f160eaaaaaaaod
[Model] lvc180f160eaaaaaaaod
Model_type I/O_open_drain
Polarity   Non-Inverting
Enable   Active-Low
Vinl =  0.630V
Vinh =  1.170V
Vmeas =  0.900V
Cref =  0.0F
Rref =  1.000M
Vref =  1.8V
C_comp   5.000pF   4.000pF   5.500pF
[Temperature Range]   25.000   0.125k   -40.000
[Voltage Range]   1.800V   1.710V   1.890V
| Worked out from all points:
|   slope of the pulldown table from 0 to 0.27 V, typ, clamps not added: 16.6 ohm
|   GND clamp passes 1 mA (typ) near -0.54 V on its own axis
|   POWER clamp passes 1 mA (typ) near -0.49 V on its own axis
|   falling waveform, R_fixture 50.000, V_fixture 1.800: 20-80 % time 141ps typ, 158ps min, 134ps max; typ from 1.8 V to 0.487 V
[Pulldown]
|Voltage   I(typ)   I(min)   I(max)
-1.8V     -57.26mA   -59.78mA   -54.99mA
-1.2V     -51.09mA   -52.83mA   -48.7mA
-900mV    -46.65mA   -46.82mA   -44.83mA
-660mV    -39.62mA   -39.31mA   -38.72mA
-420mV    -27.34mA   -26.64mA   -27.21mA
240mV     14.73mA    13.73mA    15.13mA
540mV     28.27mA    26.32mA    29.23mA
840mV     37.09mA    34.5mA     38.57mA
1.26V     42.38mA    39.51mA    44.3mA
2.28V     44.95mA    43.48mA    46.4mA
2.46V     47mA       43.48mA    49.48mA
3.6V      47.08mA    43.66mA    49.64mA
[GND_clamp]
|Voltage   I(typ)   I(min)   I(max)
-1.8V     -334.4mA   -335.3mA   -317.1mA
-1.4V     -189.3mA   -204.4mA   -167.3mA
-1.28V    -148.9mA   -166.7mA   -126.7mA
-1.12V    -99.04mA   -119.7mA   -77.45mA
-1V       -64.9mA    -88.2mA    -45.18mA
-920mV    -44.4mA    -68.92mA   -27.88mA
-840mV    -26.71mA   -51.09mA   -16.18mA
-720mV    -8.754mA   -27.82mA   -7.821mA
-640mV    -3.53mA    -15.52mA   -4.188mA
-560mV    -1.27mA    -6.791mA   -1.597mA
-400mV    -49.63uA   -425.4uA   -44.12uA
1.8V      0A         0A         0A
[POWER_clamp]
|Voltage   I(typ)   I(min)   I(max)
-1.8V     174.6mA    158.5mA    191.6mA
-1.36V    100.3mA    96.28mA    105.7mA
-1.12V    62.39mA    65.2mA     61.09mA
-960mV    38.11mA    46.28mA    32.52mA
-880mV    25.96mA    36.75mA    22.79mA
-800mV    15.45mA    26.86mA    16.3mA
-720mV    9.004mA    17.05mA    10.75mA
-640mV    5.132mA    8.487mA    6.134mA
-560mV    2.382mA    3.217mA    2.693mA
-520mV    1.425mA    1.849mA    1.506mA
-360mV    88.16uA    177.6uA    42.1uA
1.8V      0A         0A         0A
[Ramp]
| variable   typ   min   max
dV/dt_r 0.788/0.280n   0.734/0.278n   0.832/0.278n
dV/dt_f 0.788/0.142n   0.734/0.160n   0.832/0.135n
R_load = 50.000
[Falling Waveform]
R_fixture= 50.000
V_fixture= 1.800
V_fixture_min= 1.710
V_fixture_max= 1.890
|time   V(typ)   V(min)   V(max)
0s        1.8V       1.71V      1.89V
290ps     1.8V       1.71V      1.883V
381ps     1.795V     1.71V      1.298V
460ps     1.39V      1.71V      835.5mV
557ps     830.9mV    1.675V     599.7mV
633ps     622.6mV    1.33V      539.4mV
726ps     530.9mV    862.2mV    514.2mV
869ps     495.9mV    564.2mV    505.6mV
1.153ns   488.6mV    492.2mV    503.1mV
10ns      487.4mV    487.5mV    502.8mV
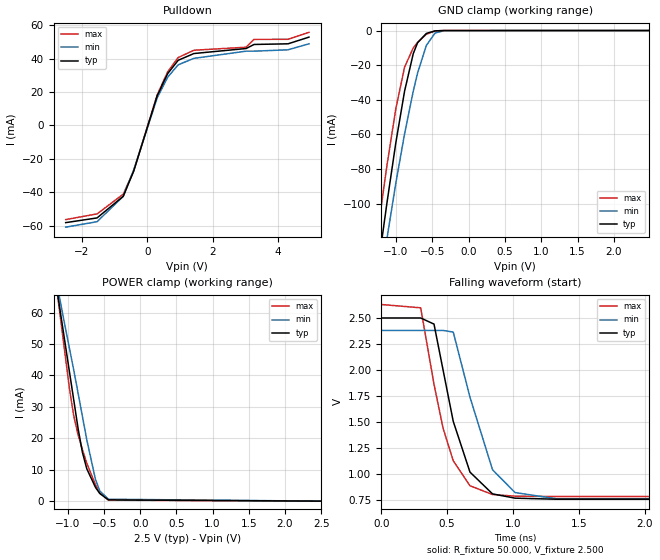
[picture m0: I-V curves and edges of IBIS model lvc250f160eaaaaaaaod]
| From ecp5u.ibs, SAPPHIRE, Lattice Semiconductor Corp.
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|   Model lvc250f160eaaaaaaaod
[Model] lvc250f160eaaaaaaaod
Model_type I/O_open_drain
Polarity   Non-Inverting
Enable   Active-Low
Vinl =  0.700V
Vinh =  1.700V
Vmeas =  1.250V
Cref =  0.0F
Rref =  1.000M
Vref =  2.5V
C_comp   5.000pF   4.000pF   5.500pF
[Temperature Range]   25.000   0.125k   -40.000
[Voltage Range]   2.500V   2.380V   2.630V
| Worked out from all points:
|   slope of the pulldown table from 0 to 0.375 V, typ, clamps not added: 17.5 ohm
|   GND clamp passes 1 mA (typ) near -0.54 V on its own axis
|   POWER clamp passes 1 mA (typ) near -0.49 V on its own axis
|   falling waveform, R_fixture 50.000, V_fixture 2.500: 20-80 % time 193ps typ, 209ps min, 189ps max; typ from 2.5 V to 0.752 V
[Pulldown]
|Voltage   I(typ)   I(min)   I(max)
-2.5V     -58.2mA    -60.91mA   -56.39mA
-1.54V    -55.38mA   -57.65mA   -52.96mA
-740mV    -42.44mA   -42.44mA   -41.18mA
-420mV    -27.34mA   -26.64mA   -27.21mA
300mV     17.85mA    16.63mA    18.36mA
620mV     31.07mA    28.91mA    32.17mA
940mV     39.03mA    36.32mA    40.66mA
1.42V     43.07mA    40.18mA    45.04mA
3.02V     46.08mA    44.49mA    46.86mA
3.26V     48.5mA     44.49mA    51.54mA
4.3V      48.89mA    45.3mA     51.59mA
4.94V     52.89mA    48.89mA    55.77mA
[GND_clamp]
|Voltage   I(typ)   I(min)   I(max)
-2.5V     -600.3mA   -576.2mA   -594.4mA
-1.24V    -136mA     -154.5mA   -113.9mA
-1.18V    -117.2mA   -136.7mA   -95.27mA
-1.12V    -99.04mA   -119.7mA   -77.45mA
-1V       -64.9mA    -88.21mA   -45.19mA
-880mV    -35.12mA   -59.82mA   -21.21mA
-760mV    -13.33mA   -35.03mA   -10mA
-700mV    -7.01mA    -24.46mA   -6.829mA
-580mV    -1.679mA   -8.593mA   -2.127mA
-460mV    -210.1uA   -1.441mA   -213.7uA
-340mV    -8.598uA   -109.2uA   -6.553uA
2.48V     0A         0A         0A
[POWER_clamp]
|Voltage   I(typ)   I(min)   I(max)
-2.48V    301.8mA    269mA      334.4mA
-1.16V    68.59mA    70.21mA    68.47mA
-1.1V     59.33mA    62.74mA    57.51mA
-980mV    41.18mA    48.59mA    35.82mA
-920mV    32.13mA    41.65mA    27.11mA
-860mV    23.04mA    34.34mA    21.08mA
-800mV    15.49mA    26.9mA     16.35mA
-740mV    10.29mA    19.52mA    12.1mA
-620mV    4.381mA    6.888mA    5.184mA
-560mV    2.412mA    3.25mA     2.719mA
-440mV    397.7uA    604uA      311uA
2.5V      0A         0A         0A
[Ramp]
| variable   typ   min   max
dV/dt_r 1.049/0.276n   0.976/0.278n   1.111/0.275n
dV/dt_f 1.049/0.196n   0.976/0.212n   1.111/0.189n
R_load = 50.000
[Falling Waveform]
R_fixture= 50.000
V_fixture= 2.500
V_fixture_min= 2.380
V_fixture_max= 2.630
|time   V(typ)   V(min)   V(max)
0s        2.5V       2.38V      2.63V
299ps     2.5V       2.38V      2.598V
400ps     2.441V     2.38V      1.861V
469ps     1.997V     2.38V      1.436V
546ps     1.503V     2.364V     1.124V
673ps     1.014V     1.736V     882.7mV
844ps     804.1mV    1.037V     798mV
1.015ns   763.1mV    816.8mV    782.4mV
1.325ns   752.9mV    758.2mV    778.8mV
10ns      751.8mV    752.6mV    778.5mV
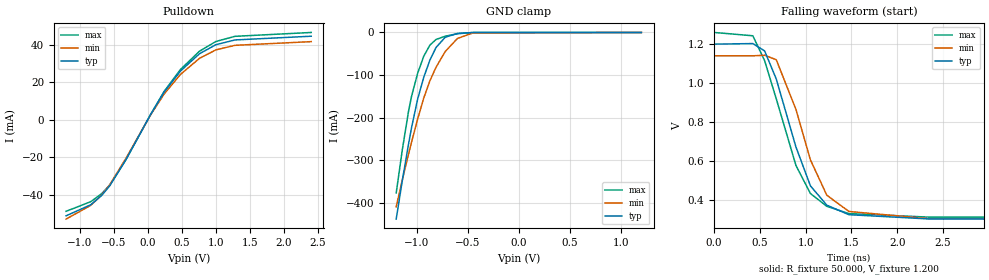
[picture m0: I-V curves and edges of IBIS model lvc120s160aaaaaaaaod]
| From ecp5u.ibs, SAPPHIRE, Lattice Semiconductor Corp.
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|   Model lvc120s160aaaaaaaaod
[Model] lvc120s160aaaaaaaaod
Model_type I/O_open_drain
Polarity   Non-Inverting
Enable   Active-Low
Vinl =  0.420V
Vinh =  0.780V
Vmeas =  0.600V
Cref =  0.0F
Rref =  1.000M
Vref =  1.2V
C_comp   5.000pF   4.000pF   5.500pF
[Temperature Range]   25.000   0.125k   -40.000
[Voltage Range]   1.200V   1.140V   1.260V
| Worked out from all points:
|   slope of the pulldown table from 0 to 0.18 V, typ, clamps not added: 15.8 ohm
|   GND clamp passes 1 mA (typ) near -0.54 V on its own axis
|   falling waveform, R_fixture 50.000, V_fixture 1.200: 20-80 % time 362ps typ, 346ps min, 378ps max; typ from 1.2 V to 0.302 V
[Pulldown]
|Voltage   I(typ)   I(min)   I(max)
-1.2V     -51.08mA   -52.82mA   -48.69mA
-840mV    -45.26mA   -45.58mA   -43.62mA
-680mV    -40.37mA   -40.14mA   -39.38mA
-560mV    -35.22mA   -34.63mA   -34.76mA
-320mV    -21.13mA   -20.42mA   -21.13mA
40mV      2.722mA    2.54mA     2.784mA
240mV     14.74mA    13.74mA    15.14mA
480mV     25.97mA    24.19mA    26.81mA
760mV     35.2mA     32.75mA    36.55mA
1V        39.99mA    37.23mA    41.69mA
1.28V     42.52mA    39.65mA    44.44mA
2.4V      44.5mA     41.62mA    46.5mA
[GND_clamp]
|Voltage   I(typ)   I(min)   I(max)
-1.2V     -438mA     -409.1mA   -376.6mA
-1.14V    -347.3mA   -346mA     -275mA
-1.08V    -262.9mA   -286.2mA   -186mA
-1.05V    -223.7mA   -257.7mA   -150.1mA
-990mV    -156.2mA   -203.2mA   -95.71mA
-930mV    -105.1mA   -153.8mA   -55.64mA
-870mV    -64.79mA   -113.3mA   -29.61mA
-810mV    -35.24mA   -81.59mA   -16.5mA
-720mV    -11.12mA   -44.72mA   -8.737mA
-600mV    -2.308mA   -13.95mA   -2.934mA
-450mV    -169.7uA   -1.25mA    -168.1uA
1.2V      0A         0A         0A
[Ramp]
| variable   typ   min   max
dV/dt_r 0.539/0.277n   0.502/0.273n   0.569/0.276n
dV/dt_f 0.539/0.377n   0.503/0.349n   0.569/0.387n
R_load = 50.000
[Falling Waveform]
R_fixture= 50.000
V_fixture= 1.200
V_fixture_min= 1.140
V_fixture_max= 1.260
|time   V(typ)   V(min)   V(max)
0s        1.2V       1.14V      1.26V
423ps     1.203V     1.14V      1.243V
552ps     1.165V     1.143V     1.115V
679ps     1.021V     1.12V      919.3mV
894ps     671.6mV    864.5mV    577mV
1.052ns   472.5mV    605.8mV    433.2mV
1.231ns   373.3mV    424.3mV    367.4mV
1.472ns   324.5mV    341.1mV    330.1mV
2.353ns   302.5mV    303.6mV    311.9mV
10ns      302.1mV    302.4mV    311.7mV
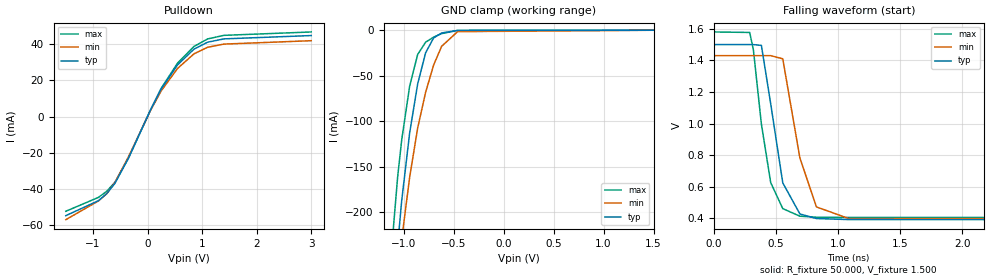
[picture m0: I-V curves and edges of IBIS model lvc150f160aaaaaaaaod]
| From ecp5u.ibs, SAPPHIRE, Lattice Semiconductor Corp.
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|   Model lvc150f160aaaaaaaaod
[Model] lvc150f160aaaaaaaaod
Model_type I/O_open_drain
Polarity   Non-Inverting
Enable   Active-Low
Vinl =  0.375V
Vinh =  1.125V
Vmeas =  0.750V
Cref =  0.0F
Rref =  1.000M
Vref =  1.5V
C_comp   5.000pF   4.000pF   5.500pF
[Temperature Range]   25.000   0.125k   -40.000
[Voltage Range]   1.500V   1.430V   1.580V
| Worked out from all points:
|   slope of the pulldown table from 0 to 0.225 V, typ, clamps not added: 16.2 ohm
|   GND clamp passes 1 mA (typ) near -0.54 V on its own axis
|   falling waveform, R_fixture 50.000, V_fixture 1.500: 20-80 % time 124ps typ, 141ps min, 117ps max; typ from 1.5 V to 0.391 V
[Pulldown]
|Voltage   I(typ)   I(min)   I(max)
-1.5V     -54.97mA   -57.2mA    -52.54mA
-900mV    -46.64mA   -46.81mA   -44.82mA
-750mV    -42.75mA   -42.79mA   -41.44mA
-600mV    -37.11mA   -36.61mA   -36.49mA
-350mV    -23.02mA   -22.31mA   -22.98mA
50mV      3.386mA    3.159mA    3.463mA
250mV     15.27mA    14.24mA    15.69mA
550mV     28.65mA    26.68mA    29.63mA
850mV     37.33mA    34.73mA    38.82mA
1.1V      41.19mA    38.37mA    43mA
1.4V      43.03mA    40.14mA    44.99mA
3V        44.87mA    42.02mA    46.86mA
[GND_clamp]
|Voltage   I(typ)   I(min)   I(max)
-1.5V     -960.1mA   -762.7mA   -1.034A
-1.14V    -347.3mA   -346.1mA   -275mA
-1.1V     -290.3mA   -305.8mA   -213.7mA
-1.06V    -236.5mA   -267.1mA   -161.1mA
-1.02V    -187.7mA   -230mA     -120.8mA
-940mV    -112.8mA   -161.5mA   -61.4mA
-860mV    -59.1mA    -107.5mA   -26.64mA
-780mV    -24.64mA   -68mA      -13.11mA
-700mV    -8.463mA   -38.12mA   -7.575mA
-620mV    -2.993mA   -17.63mA   -3.702mA
-460mV    -212uA     -1.525mA   -216uA
1.5V      0A         0A         0A
[Ramp]
| variable   typ   min   max
dV/dt_r 0.665/0.275n   0.622/0.277n   0.705/0.276n
dV/dt_f 0.665/0.125n   0.622/0.142n   0.705/0.117n
R_load = 50.000
[Falling Waveform]
R_fixture= 50.000
V_fixture= 1.500
V_fixture_min= 1.430
V_fixture_max= 1.580
|time   V(typ)   V(min)   V(max)
0s        1.5V       1.43V      1.58V
289ps     1.5V       1.43V      1.577V
319ps     1.5V       1.43V      1.465V
383ps     1.495V     1.43V      997.2mV
458ps     1.125V     1.43V      625.8mV
555ps     624.3mV    1.41V      461.1mV
693ps     427.1mV    781.2mV    413.1mV
826ps     398.3mV    471.9mV    406.7mV
1.086ns   391.7mV    398.1mV    405.1mV
10ns      391mV      392.8mV    404.9mV
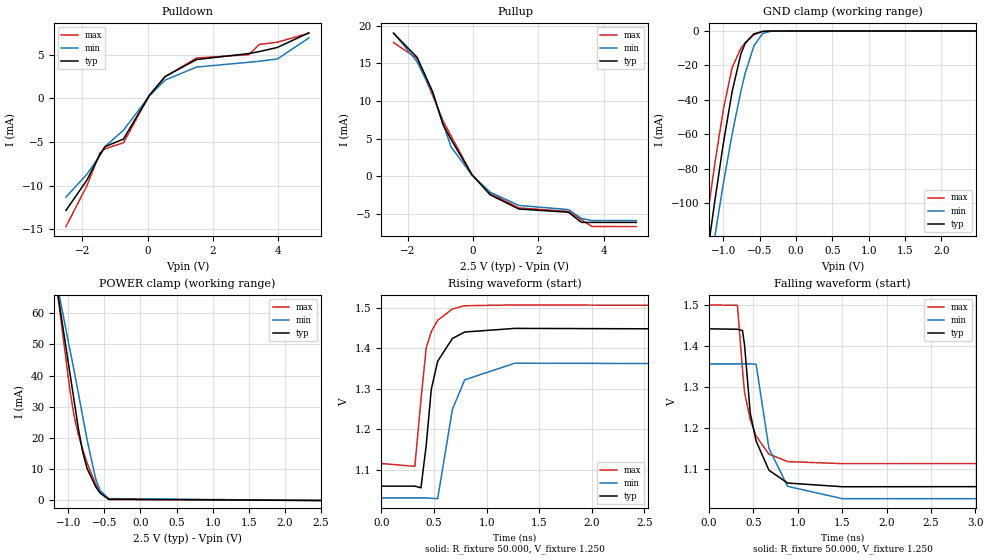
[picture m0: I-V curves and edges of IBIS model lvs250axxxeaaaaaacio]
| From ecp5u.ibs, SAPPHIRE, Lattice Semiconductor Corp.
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|   Model lvs250axxxeaaaaaacio
[Model] lvs250axxxeaaaaaacio
Model_type I/O
Polarity   Non-Inverting
Enable   Active-Low
Vinl =  1.150V
Vinh =  1.350V
Vmeas =  1.250V
Cref =  3.000pF
Rref =  50.000
Vref =  1.250V
C_comp   5.000pF   4.000pF   5.500pF
[Temperature Range]   25.000   0.125k   -40.000
[Voltage Range]   2.500V   2.380V   2.630V
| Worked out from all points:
|   slope of the pulldown table from 0 to 0.375 V, typ, clamps not added: 197 ohm
|   slope of the pullup table from 0 to 0.375 V, typ, clamps not added: 199 ohm
|   GND clamp passes 1 mA (typ) near -0.54 V on its own axis
|   POWER clamp passes 1 mA (typ) near -0.49 V on its own axis
|   rising waveform, R_fixture 50.000, V_fixture 1.250: 20-80 % time 114ps typ, 135ps min, 93.3ps max; typ from 1.06 V to 1.44 V
|   falling waveform, R_fixture 50.000, V_fixture 1.250: 20-80 % time 168ps typ, 182ps min, 155ps max; typ from 1.44 V to 1.06 V
[Pulldown]
|Voltage   I(typ)   I(min)   I(max)
-2.5V     -12.85mA   -11.33mA   -14.71mA
-1.86V    -9.397mA   -8.713mA   -10.04mA
-1.46V    -6.452mA   -6.562mA   -6.261mA
-1.3V     -5.537mA   -5.513mA   -5.787mA
-740mV    -4.676mA   -3.67mA    -5.102mA
60mV      357.1uA    281.5uA    383.3uA
540mV     2.504mA    2.089mA    2.473mA
1.5V      4.444mA    3.582mA    4.621mA
3.1V      5.129mA    4.131mA    4.999mA
3.42V     5.353mA    4.247mA    6.167mA
3.98V     5.832mA    4.513mA    6.438mA
4.94V     7.508mA    6.913mA    7.459mA
[Pullup]
|Voltage   I(typ)   I(min)   I(max)
-2.44V    18.97mA    19.03mA    17.74mA
-1.72V    15.79mA    15.22mA    15.64mA
-1.24V    11.2mA     11mA       10.71mA
-920mV    6.816mA    7.008mA    7.347mA
-680mV    4.923mA    3.923mA    5.386mA
-40mV     238.9uA    193.8uA    245.1uA
520mV     -2.436mA   -2.085mA   -2.218mA
1.4V      -4.324mA   -3.85mA    -4.182mA
2.92V     -4.752mA   -4.398mA   -4.634mA
3.32V     -6.101mA   -5.587mA   -5.766mA
3.64V     -6.101mA   -5.855mA   -6.648mA
5V        -6.101mA   -5.855mA   -6.654mA
[GND_clamp]
|Voltage   I(typ)   I(min)   I(max)
-2.5V     -600.3mA   -576.2mA   -594.4mA
-1.24V    -136mA     -154.5mA   -113.9mA
-1.18V    -117.2mA   -136.7mA   -95.27mA
-1.12V    -99.04mA   -119.7mA   -77.45mA
-1V       -64.9mA    -88.21mA   -45.19mA
-880mV    -35.12mA   -59.82mA   -21.21mA
-760mV    -13.33mA   -35.03mA   -10mA
-700mV    -7.01mA    -24.46mA   -6.829mA
-580mV    -1.679mA   -8.593mA   -2.127mA
-460mV    -210.1uA   -1.441mA   -213.7uA
-340mV    -8.598uA   -109.2uA   -6.553uA
2.48V     0A         0A         0A
[POWER_clamp]
|Voltage   I(typ)   I(min)   I(max)
-2.48V    301.8mA    269mA      334.4mA
-1.16V    68.59mA    70.21mA    68.47mA
-1.1V     59.33mA    62.74mA    57.51mA
-980mV    41.18mA    48.59mA    35.82mA
-920mV    32.13mA    41.65mA    27.11mA
-860mV    23.04mA    34.34mA    21.08mA
-800mV    15.49mA    26.9mA     16.35mA
-740mV    10.29mA    19.52mA    12.1mA
-620mV    4.381mA    6.888mA    5.184mA
-560mV    2.412mA    3.25mA     2.719mA
-440mV    397.7uA    604uA      311uA
2.5V      0A         0A         0A
[Ramp]
| variable   typ   min   max
dV/dt_r 0.140/43.197p   0.123/70.204p   0.139/32.714p
dV/dt_f 0.140/50.213p   0.111/70.145p   0.148/39.697p
R_load = 50.000
[Rising Waveform]
R_fixture= 50.000
V_fixture= 1.250
V_fixture_min= 1.188
V_fixture_max= 1.313
|time   V(typ)   V(min)   V(max)
0s        1.059V     1.03V      1.115V
318ps     1.059V     1.03V      1.108V
376ps     1.055V     1.03V      1.272V
426ps     1.16V      1.03V      1.401V
474ps     1.298V     1.029V     1.441V
535ps     1.368V     1.028V     1.469V
675ps     1.424V     1.249V     1.497V
792ps     1.44V      1.322V     1.505V
1.269ns   1.449V     1.363V     1.507V
10ns      1.442V     1.357V     1.501V
[Falling Waveform]
R_fixture= 50.000
V_fixture= 1.250
V_fixture_min= 1.188
V_fixture_max= 1.313
|time   V(typ)   V(min)   V(max)
0s        1.441V     1.356V     1.499V
321ps     1.44V      1.356V     1.498V
378ps     1.437V     1.356V     1.342V
401ps     1.402V     1.356V     1.287V
465ps     1.237V     1.356V     1.221V
531ps     1.169V     1.355V     1.181V
676ps     1.098V     1.151V     1.137V
886ps     1.067V     1.059V     1.119V
1.504ns   1.058V     1.029V     1.114V
10ns      1.059V     1.029V     1.115V
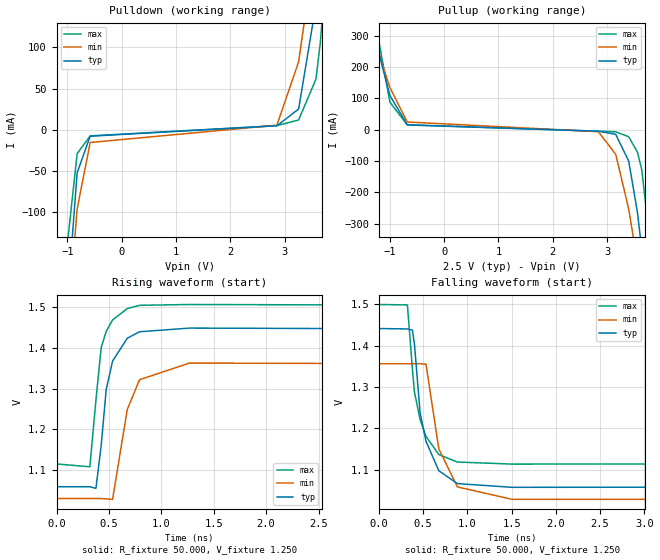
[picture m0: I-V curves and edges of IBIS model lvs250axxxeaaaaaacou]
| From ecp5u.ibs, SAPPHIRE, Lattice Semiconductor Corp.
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|   Model lvs250axxxeaaaaaacou
[Model] lvs250axxxeaaaaaacou
Model_type Output
Polarity   Non-Inverting
Vmeas =  1.250V
Cref =  3.000pF
Rref =  50.000
Vref =  1.250V
C_comp   5.000pF   4.000pF   5.500pF
[Temperature Range]   25.000   0.125k   -40.000
[Voltage Range]   2.500V   2.380V   2.630V
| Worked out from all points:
|   slope of the pulldown table from 0 to 0.375 V, typ, clamps not added: 197 ohm
|   slope of the pullup table from 0 to 0.375 V, typ, clamps not added: 199 ohm
|   rising waveform, R_fixture 50.000, V_fixture 1.250: 20-80 % time 114ps typ, 135ps min, 93.3ps max; typ from 1.06 V to 1.44 V
|   falling waveform, R_fixture 50.000, V_fixture 1.250: 20-80 % time 168ps typ, 182ps min, 155ps max; typ from 1.44 V to 1.06 V
[Pulldown]
|Voltage   I(typ)   I(min)   I(max)
-2.5V     -3.258A    -2.341A    -3.824A
-1.14V    -380.5mA   -377.7mA   -290.8mA
-1.06V    -261.7mA   -292.2mA   -175.1mA
-820mV    -52.21mA   -96.29mA   -28.97mA
-580mV    -7.865mA   -15.5mA    -7.487mA
2.86V     4.844mA    5.564mA    4.955mA
3.26V     25.15mA    82.43mA    11.86mA
3.58V     152.2mA    230.2mA    61.55mA
3.66V     201.5mA    274.1mA    105.9mA
3.82V     309.9mA    367.3mA    239.6mA
3.9V      367.8mA    416.3mA    320.6mA
4.94V     1.272A     1.179A     1.714A
[Pullup]
|Voltage   I(typ)   I(min)   I(max)
-2.44V    1.283A     1.093A     1.926A
-1.56V    498.2mA    450.8mA    666.5mA
-1.4V     374.8mA    351.6mA    471mA
-1V       109.5mA    134.8mA    88.35mA
-680mV    15.95mA    24.74mA    15.17mA
2.84V     -4.768mA   -6.253mA   -4.626mA
3.16V     -14.44mA   -78.13mA   -6.564mA
3.4V      -100.2mA   -253.2mA   -22.42mA
3.56V     -262.8mA   -423.6mA   -71.15mA
3.64V     -381.8mA   -517.3mA   -127.6mA
3.88V     -799.3mA   -824.6mA   -487.4mA
5V        -3.25A     -2.529A    -3.422A
[Ramp]
| variable   typ   min   max
dV/dt_r 0.140/43.197p   0.123/70.204p   0.139/32.714p
dV/dt_f 0.140/50.213p   0.111/70.145p   0.148/39.697p
R_load = 50.000
[Rising Waveform]
R_fixture= 50.000
V_fixture= 1.250
V_fixture_min= 1.188
V_fixture_max= 1.313
|time   V(typ)   V(min)   V(max)
0s        1.059V     1.03V      1.115V
318ps     1.059V     1.03V      1.108V
376ps     1.055V     1.03V      1.272V
426ps     1.16V      1.03V      1.401V
474ps     1.298V     1.029V     1.441V
535ps     1.368V     1.028V     1.469V
675ps     1.424V     1.249V     1.497V
792ps     1.44V      1.322V     1.505V
1.269ns   1.449V     1.363V     1.507V
10ns      1.442V     1.357V     1.501V
[Falling Waveform]
R_fixture= 50.000
V_fixture= 1.250
V_fixture_min= 1.188
V_fixture_max= 1.313
|time   V(typ)   V(min)   V(max)
0s        1.441V     1.356V     1.499V
321ps     1.44V      1.356V     1.498V
378ps     1.437V     1.356V     1.342V
401ps     1.402V     1.356V     1.287V
465ps     1.237V     1.356V     1.221V
531ps     1.169V     1.355V     1.181V
676ps     1.098V     1.151V     1.137V
886ps     1.067V     1.059V     1.119V
1.504ns   1.058V     1.029V     1.114V
10ns      1.059V     1.029V     1.115V
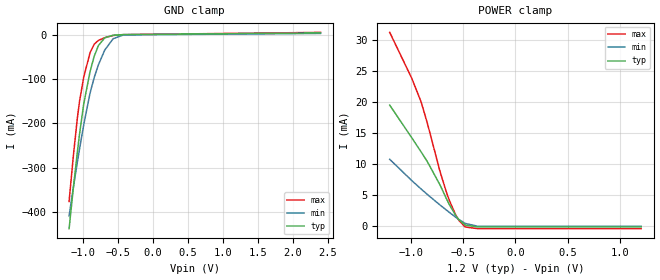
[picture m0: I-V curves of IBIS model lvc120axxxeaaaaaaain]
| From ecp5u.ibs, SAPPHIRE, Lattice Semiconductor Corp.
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|   Model lvc120axxxeaaaaaaain
[Model] lvc120axxxeaaaaaaain
Model_type Input
Polarity   Non-Inverting
Vinl =  0.420V
Vinh =  0.780V
C_comp   3.901pF   3.901pF   3.911pF
[Temperature Range]   25.000   0.125k   -40.000
[Voltage Range]   1.200V   1.140V   1.260V
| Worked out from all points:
|   GND clamp passes 1 mA (typ) near -0.54 V on its own axis
|   POWER clamp passes 1 mA (typ) near -0.54 V on its own axis
[GND_clamp]
|Voltage   I(typ)   I(min)   I(max)
-1.2V     -438mA     -409.1mA   -376.6mA
-1.14V    -347.3mA   -346mA     -275mA
-1.08V    -262.9mA   -286.2mA   -186mA
-1.05V    -223.7mA   -257.7mA   -150.1mA
-990mV    -156.2mA   -203.2mA   -95.71mA
-900mV    -83.64mA   -132.1mA   -40.81mA
-840mV    -48.61mA   -96.59mA   -21.71mA
-780mV    -24.63mA   -67.99mA   -13.11mA
-690mV    -7.398mA   -35.03mA   -7.025mA
-570mV    -1.527mA   -9.488mA   -1.957mA
-420mV    -83.23uA   -670.2uA   -76.79uA
2.4V      3.704mA    2.56mA     4.906mA
[POWER_clamp]
|Voltage   I(typ)   I(min)   I(max)
-1.2V     19.53mA    10.77mA    31.3mA
-990mV    14.26mA    7.336mA    23.89mA
-900mV    11.96mA    5.959mA    20.04mA
-840mV    10.37mA    5.073mA    16.56mA
-720mV    6.62mA     3.379mA    8.8mA
-660mV    4.443mA    2.57mA     5.508mA
-630mV    3.417mA    2.174mA    4.085mA
-570mV    1.681mA    1.398mA    1.76mA
-540mV    1.015mA    1.031mA    892.9uA
-480mV    148.6uA    407.1uA    -173.6uA
-360mV    -173.8uA   -61.24uA   -447.3uA
1.2V      -173.8uA   -65.23uA   -447.3uA
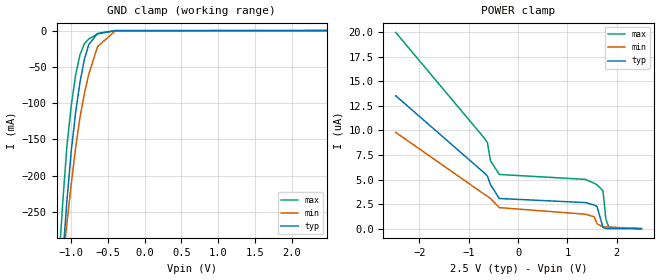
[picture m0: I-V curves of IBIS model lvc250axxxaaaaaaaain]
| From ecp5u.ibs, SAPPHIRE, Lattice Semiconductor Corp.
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|   Model lvc250axxxaaaaaaaain
[Model] lvc250axxxaaaaaaaain
Model_type Input
Polarity   Non-Inverting
Vinl =  0.700V
Vinh =  1.700V
C_comp   3.961pF   3.900pF   4.091pF
[Temperature Range]   25.000   0.125k   -40.000
[Voltage Range]   2.500V   2.380V   2.630V
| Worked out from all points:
|   GND clamp passes 1 mA (typ) near -0.54 V on its own axis
[GND_clamp]
|Voltage   I(typ)   I(min)   I(max)
-2.5V     -3.07A     -2.187A    -4.081A
-1.18V    -407.1mA   -387.7mA   -341.4mA
-1.12V    -318.4mA   -325.7mA   -243.5mA
-1.06V    -236.4mA   -267.1mA   -161.1mA
-1V       -166.1mA   -212mA     -103.6mA
-940mV    -112.8mA   -161.5mA   -61.35mA
-880mV    -70.76mA   -119.2mA   -32.94mA
-820mV    -39.36mA   -86.41mA   -17.99mA
-760mV    -19.05mA   -59.65mA   -11.43mA
-640mV    -3.861mA   -21.85mA   -4.556mA
-400mV    -49.76uA   -433.5uA   -44.23uA
2.48V     0A         0A         0A
[POWER_clamp]
|Voltage   I(typ)   I(min)   I(max)
-2.48V    13.54uA    9.807uA    19.99uA
-680mV    5.657uA    3.488uA    9.198uA
-620mV    5.342uA    3.293uA    8.751uA
-560mV    4.488uA    3.072uA    6.917uA
-380mV    3.071uA    2.141uA    5.519uA
1.36V     2.656uA    1.474uA    5.022uA
1.54V     2.407uA    1.217uA    4.631uA
1.6V      2.248uA    500.1nA    4.47uA
1.72V     130.8nA    175nA      3.869uA
1.78V     17.59nA    161.4nA    946.2nA
1.84V     1.969nA    157.2nA    133.3nA
2.5V      0A         0A         0A
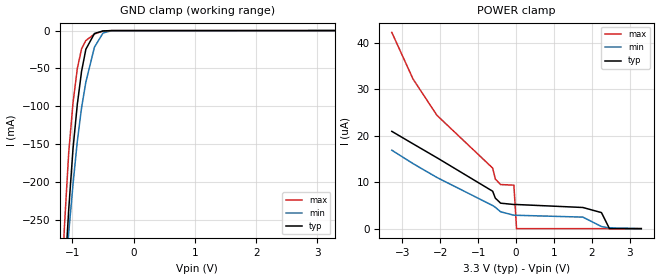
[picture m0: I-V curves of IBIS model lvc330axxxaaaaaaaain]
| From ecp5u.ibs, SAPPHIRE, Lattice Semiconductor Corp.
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|   Model lvc330axxxaaaaaaaain
[Model] lvc330axxxaaaaaaaain
Model_type Input
Polarity   Non-Inverting
Vinl =  0.800V
Vinh =  2.000V
C_comp   3.989pF   3.921pF   4.070pF
[Temperature Range]   25.000   0.125k   -40.000
[Voltage Range]   3.300V   3.140V   3.470V
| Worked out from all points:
|   GND clamp passes 1 mA (typ) near -0.53 V on its own axis
[GND_clamp]
|Voltage   I(typ)   I(min)   I(max)
-3.3V     -4.927A    -3.455A    -6.917A
-1.2V     -438.1mA   -409.1mA   -376.6mA
-1.13V    -332.7mA   -335.8mA   -259mA
-1.06V    -236.4mA   -267.1mA   -161.1mA
-990mV    -156.1mA   -203.2mA   -95.66mA
-920mV    -97.62mA   -146.3mA   -50.27mA
-850mV    -53.69mA   -101.9mA   -24mA
-780mV    -24.61mA   -67.98mA   -13.11mA
-640mV    -3.861mA   -21.85mA   -4.556mA
-500mV    -479.8uA   -3.203mA   -548.3uA
-360mV    -16.03uA   -175uA     -13.11uA
3.28V     0A         0A         0A
[POWER_clamp]
|Voltage   I(typ)   I(min)   I(max)
-3.28V    20.95uA    16.89uA    42.25uA
-2.72V    18.26uA    14uA       32.21uA
-2.09V    15.27uA    11.02uA    24.4uA
-620mV    8.055uA    4.975uA    13.04uA
-550mV    6.572uA    4.601uA    10.68uA
-410mV    5.486uA    3.632uA    9.492uA
-60mV     5.201uA    2.894uA    9.362uA
10mV      5.199uA    2.88uA     0A
1.76V     4.557uA    2.485uA    0A
2.25V     3.456uA    456.3nA    0A
2.46V     27.62nA    159nA      0A
3.3V      0A         0A         0A
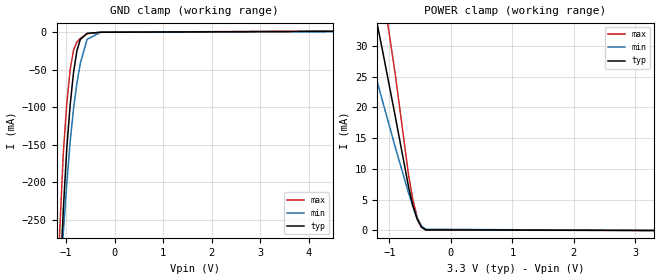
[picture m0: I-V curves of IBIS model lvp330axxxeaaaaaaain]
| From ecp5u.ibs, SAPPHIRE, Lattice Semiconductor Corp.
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|   Model lvp330axxxeaaaaaaain
[Model] lvp330axxxeaaaaaaain
Model_type Input
Polarity   Non-Inverting
Vinl =  1.840V
Vinh =  2.140V
C_comp   3.863pF   3.862pF   3.894pF
[Temperature Range]   25.000   0.125k   -40.000
[Voltage Range]   3.300V   3.140V   3.470V
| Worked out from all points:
|   GND clamp passes 1 mA (typ) near -0.53 V on its own axis
|   POWER clamp passes 1 mA (typ) near -0.50 V on its own axis
[GND_clamp]
|Voltage   I(typ)   I(min)   I(max)
-3.3V     -4.927A    -3.455A    -6.917A
-1.2V     -438.1mA   -409.1mA   -376.6mA
-1.13V    -332.7mA   -335.8mA   -259mA
-1.06V    -236.4mA   -267.1mA   -161.1mA
-990mV    -156.1mA   -203.2mA   -95.66mA
-920mV    -97.62mA   -146.3mA   -50.27mA
-850mV    -53.69mA   -101.9mA   -24mA
-780mV    -24.61mA   -67.98mA   -13.11mA
-710mV    -9.695mA   -41.33mA   -8.146mA
-570mV    -1.528mA   -9.486mA   -1.957mA
-290mV    -1.561uA   -33.47uA   -868.6nA
6.58V     1.74mA     1.178mA    2.308mA
[POWER_clamp]
|Voltage   I(typ)   I(min)   I(max)
-3.28V    129.1mA    106.9mA    153.6mA
-1.6V     52.73mA    39.39mA    69.01mA
-1.32V    39.47mA    28.73mA    52.34mA
-1.25V    36.07mA    26.11mA    48.02mA
-1.11V    29.12mA    20.93mA    39.16mA
-900mV    18.26mA    13.35mA    25mA
-690mV    7.137mA    6.13mA     9.076mA
-620mV    4.083mA    3.935mA    5.064mA
-550mV    1.846mA    2.033mA    2.166mA
-480mV    555.3uA    760.1uA    553.6uA
-410mV    97.55uA    197.5uA    70.38uA
3.3V      0A         0A         0A
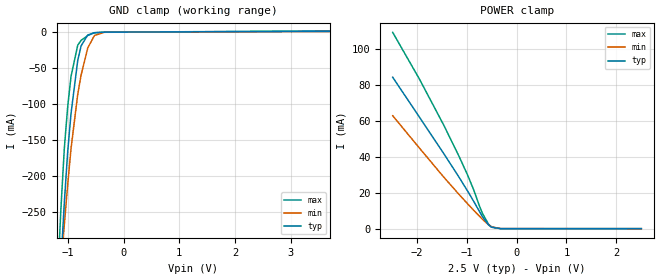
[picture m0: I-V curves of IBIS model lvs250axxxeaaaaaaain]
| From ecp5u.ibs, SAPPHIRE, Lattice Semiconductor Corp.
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|   Model lvs250axxxeaaaaaaain
[Model] lvs250axxxeaaaaaaain
Model_type Input
Polarity   Non-Inverting
Vinl =  1.150V
Vinh =  1.350V
C_comp   3.846pF   3.842pF   3.846pF
[Temperature Range]   25.000   0.125k   -40.000
[Voltage Range]   2.500V   2.380V   2.630V
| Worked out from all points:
|   GND clamp passes 1 mA (typ) near -0.54 V on its own axis
|   POWER clamp passes 1 mA (typ) near -0.51 V on its own axis
[GND_clamp]
|Voltage   I(typ)   I(min)   I(max)
-2.5V     -3.07A     -2.187A    -4.081A
-1.18V    -407.1mA   -387.7mA   -341.4mA
-1.12V    -318.4mA   -325.7mA   -243.5mA
-1.06V    -236.4mA   -267.1mA   -161.1mA
-1V       -166.1mA   -212mA     -103.6mA
-940mV    -112.8mA   -161.5mA   -61.35mA
-820mV    -39.36mA   -86.41mA   -17.99mA
-760mV    -19.05mA   -59.65mA   -11.43mA
-640mV    -3.861mA   -21.85mA   -4.556mA
-520mV    -690.7uA   -4.492mA   -828.9uA
-340mV    -8.603uA   -109.8uA   -6.557uA
4.98V     1.752mA    1.203mA    2.322mA
[POWER_clamp]
|Voltage   I(typ)   I(min)   I(max)
-2.48V    84.32mA    62.88mA    109.3mA
-1.94V    61.91mA    44.74mA    83.06mA
-1.46V    41.93mA    28.79mA    57.77mA
-1.16V    29.03mA    19.33mA    40.78mA
-980mV    20.95mA    13.86mA    29.88mA
-860mV    15.32mA    10.31mA    21.76mA
-740mV    9.474mA    6.847mA    12.43mA
-680mV    6.568mA    5.18mA     8.377mA
-560mV    2.092mA    2.141mA    2.486mA
-500mV    818.1uA    1.015mA    868.6uA
-320mV    4.853uA    22.67uA    1.291uA
2.5V      -341.3nA   -32nA      -512.6nA
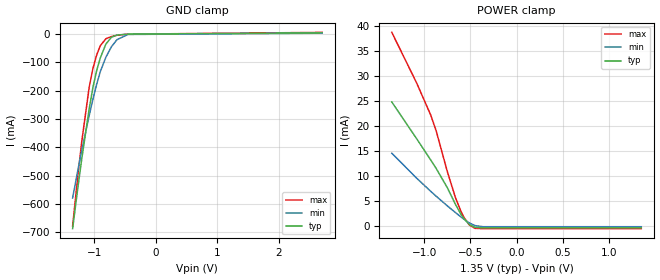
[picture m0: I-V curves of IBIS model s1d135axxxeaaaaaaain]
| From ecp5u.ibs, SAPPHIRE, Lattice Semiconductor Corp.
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|   Model s1d135axxxeaaaaaaain
[Model] s1d135axxxeaaaaaaain
Model_type Input
Polarity   Non-Inverting
Vinl =  0.575V
Vinh =  0.775V
C_comp   3.896pF   3.894pF   3.904pF
[Temperature Range]   25.000   0.125k   -40.000
[Voltage Range]   1.350V   1.280V   1.420V
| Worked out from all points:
|   GND clamp passes 1 mA (typ) near -0.54 V on its own axis
|   POWER clamp passes 1 mA (typ) near -0.55 V on its own axis
[GND_clamp]
|Voltage   I(typ)   I(min)   I(max)
-1.35V    -687.3mA   -578.9mA   -678.2mA
-1.26V    -534.4mA   -475.1mA   -489.7mA
-1.2V     -438.1mA   -409.1mA   -376.7mA
-1.08V    -262.9mA   -286.2mA   -186mA
-1.02V    -187.7mA   -230mA     -120.8mA
-960mV    -129.1mA   -177.6mA   -74.01mA
-900mV    -83.64mA   -132.1mA   -40.81mA
-810mV    -35.24mA   -81.59mA   -16.5mA
-720mV    -11.12mA   -44.72mA   -8.737mA
-630mV    -3.4mA     -19.67mA   -4.118mA
-450mV    -169.7uA   -1.25mA    -168.1uA
2.7V      4.573mA    3.195mA    5.981mA
[POWER_clamp]
|Voltage   I(typ)   I(min)   I(max)
-1.35V    24.83mA    14.55mA    38.8mA
-1.08V    17.43mA    9.524mA    28.6mA
-930mV    13.23mA    6.926mA    22.26mA
-870mV    11.5mA     5.927mA    19.05mA
-750mV    7.661mA    4.003mA    10.92mA
-660mV    4.26mA     2.628mA    5.576mA
-600mV    2.242mA    1.748mA    2.805mA
-570mV    1.419mA    1.323mA    1.7mA
-510mV    230.3uA    557.6uA    138.8uA
-450mV    -318.8uA   33.91uA    -516.7uA
-360mV    -408uA     -196.9uA   -584.4uA
1.35V     -408uA     -196.9uA   -584.4uA
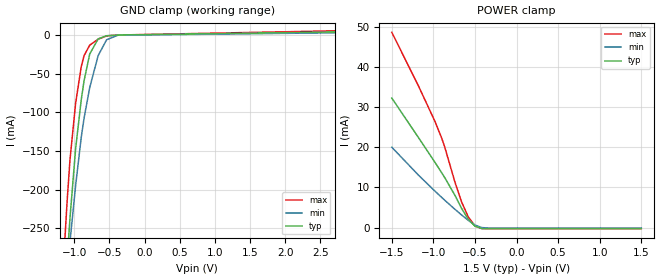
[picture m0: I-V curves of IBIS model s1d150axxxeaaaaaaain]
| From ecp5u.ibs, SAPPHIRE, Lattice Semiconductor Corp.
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|   Model s1d150axxxeaaaaaaain
[Model] s1d150axxxeaaaaaaain
Model_type Input
Polarity   Non-Inverting
Vinl =  0.650V
Vinh =  0.850V
C_comp   3.883pF   3.883pF   3.897pF
[Temperature Range]   25.000   0.125k   -40.000
[Voltage Range]   1.500V   1.430V   1.580V
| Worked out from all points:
|   GND clamp passes 1 mA (typ) near -0.54 V on its own axis
|   POWER clamp passes 1 mA (typ) near -0.54 V on its own axis
[GND_clamp]
|Voltage   I(typ)   I(min)   I(max)
-1.5V     -960.1mA   -762.7mA   -1.034A
-1.14V    -347.3mA   -346.1mA   -275mA
-1.1V     -290.3mA   -305.8mA   -213.7mA
-1.06V    -236.5mA   -267.1mA   -161.1mA
-980mV    -146.8mA   -194.6mA   -88.14mA
-900mV    -83.65mA   -132.2mA   -40.82mA
-860mV    -59.1mA    -107.5mA   -26.64mA
-780mV    -24.64mA   -68mA      -13.11mA
-660mV    -4.986mA   -26.68mA   -5.487mA
-540mV    -966.8uA   -6.158mA   -1.204mA
-380mV    -28.76uA   -276.8uA   -24.65uA
3V        4.35mA     3.138mA    5.945mA
[POWER_clamp]
|Voltage   I(typ)   I(min)   I(max)
-1.5V     32.27mA    20.03mA    48.63mA
-1.18V    22.45mA    13.09mA    35.32mA
-980mV    16.23mA    9.072mA    26.4mA
-900mV    13.66mA    7.526mA    22.3mA
-860mV    12.34mA    6.768mA    19.83mA
-740mV    8.018mA    4.556mA    11.27mA
-660mV    4.771mA    3.142mA    6.361mA
-580mV    2.049mA    1.796mA    2.657mA
-500mV    367uA      646.9uA    441uA
-420mV    -206.1uA   25.55uA    -229.4uA
-340mV    -239.3uA   -103.2uA   -251.2uA
1.5V      -239.3uA   -103.2uA   -251.2uA
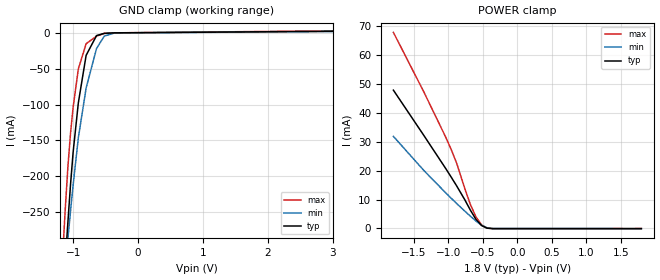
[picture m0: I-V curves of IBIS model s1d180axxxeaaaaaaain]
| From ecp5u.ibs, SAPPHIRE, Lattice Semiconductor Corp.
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|   Model s1d180axxxeaaaaaaain
[Model] s1d180axxxeaaaaaaain
Model_type Input
Polarity   Non-Inverting
Vinl =  0.775V
Vinh =  1.025V
C_comp   3.865pF   3.863pF   3.870pF
[Temperature Range]   25.000   0.125k   -40.000
[Voltage Range]   1.800V   1.710V   1.890V
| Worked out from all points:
|   GND clamp passes 1 mA (typ) near -0.54 V on its own axis
|   POWER clamp passes 1 mA (typ) near -0.52 V on its own axis
[GND_clamp]
|Voltage   I(typ)   I(min)   I(max)
-1.8V     -1.552A    -1.161A    -1.853A
-1.16V    -376.9mA   -366.7mA   -307.7mA
-1.12V    -318.4mA   -325.8mA   -243.6mA
-1.08V    -262.9mA   -286.3mA   -185.9mA
-1.04V    -211.3mA   -248.3mA   -139.7mA
-1V       -166.1mA   -212mA     -103.7mA
-920mV    -97.66mA   -146.3mA   -50.31mA
-800mV    -31.37mA   -76.92mA   -15.22mA
-640mV    -3.861mA   -21.85mA   -4.555mA
-520mV    -690.7uA   -4.491mA   -828.9uA
-360mV    -16.03uA   -175uA     -13.11uA
3.6V      2.526mA    2.22mA     3.258mA
[POWER_clamp]
|Voltage   I(typ)   I(min)   I(max)
-1.8V     47.74mA    31.79mA    67.67mA
-1.36V    32.18mA    20.08mA    47.22mA
-1.04V    20.68mA    12.29mA    31.5mA
-960mV    17.7mA     10.42mA    27.2mA
-880mV    14.64mA    8.593mA    22.43mA
-760mV    9.771mA    5.916mA    13.53mA
-680mV    6.223mA    4.193mA    8.149mA
-600mV    3.116mA    2.552mA    3.955mA
-520mV    1.025mA    1.118mA    1.22mA
-440mV    111.2uA    242.6uA    120.1uA
-360mV    -56.43uA   -21.93uA   -31.74uA
1.8V      -59.26uA   -47.56uA   -33.41uA
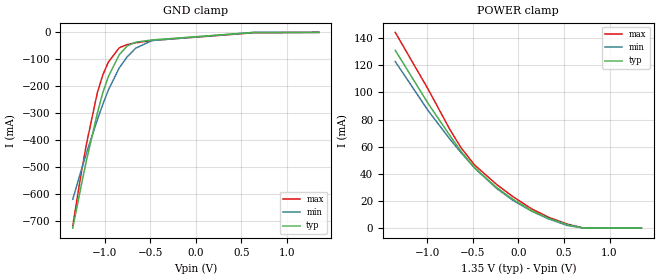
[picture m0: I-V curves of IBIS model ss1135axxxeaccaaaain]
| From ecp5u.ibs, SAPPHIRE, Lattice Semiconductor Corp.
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|   Model ss1135axxxeaccaaaain
[Model] ss1135axxxeaccaaaain
Model_type Input
Polarity   Non-Inverting
Vinl =  0.575V
Vinh =  0.775V
C_comp   4.460pF   4.394pF   4.558pF
[Temperature Range]   25.000   0.125k   -40.000
[Voltage Range]   1.350V   1.280V   1.420V
[GND_clamp]
|Voltage   I(typ)   I(min)   I(max)
-1.35V    -724.9mA   -618.2mA   -716.2mA
-1.26V    -571.4mA   -513.7mA   -527.1mA
-1.2V     -474.7mA   -447.2mA   -413.8mA
-1.08V    -298.6mA   -323.3mA   -222.6mA
-1.02V    -223mA     -266.4mA   -157.5mA
-960mV    -164.2mA   -213.6mA   -110.3mA
-840mV    -82.59mA   -131.5mA   -56.94mA
-750mV    -49.56mA   -89.29mA   -44.95mA
-660mV    -36.49mA   -58.68mA   -38.56mA
-480mV    -28.1mA    -30.1mA    -30.01mA
630mV     -503.8uA   -94.33uA   -1.552mA
1.35V     0A         0A         0A
[POWER_clamp]
|Voltage   I(typ)   I(min)   I(max)
-1.35V    131mA      122.7mA    144.2mA
-990mV    91.84mA    86.61mA    102.4mA
-750mV    68.17mA    65.48mA    72.52mA
-630mV    56.64mA    55.72mA    59.37mA
-480mV    44.42mA    44.31mA    46.48mA
-240mV    30.01mA    29.34mA    32.29mA
-60mV     21.2mA     20.5mA     23.21mA
150mV     12.77mA    12.33mA    14.04mA
330mV     7.274mA    6.837mA    8.051mA
540mV     2.525mA    1.923mA    2.892mA
720mV     0A         0A         0A
1.35V     0A         0A         0A
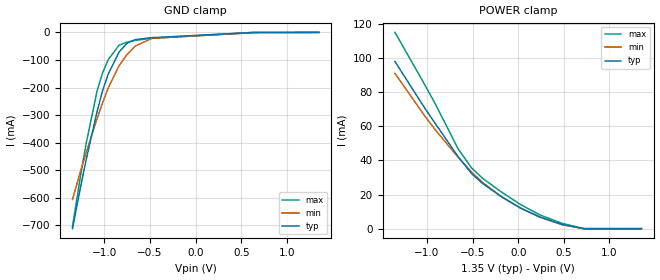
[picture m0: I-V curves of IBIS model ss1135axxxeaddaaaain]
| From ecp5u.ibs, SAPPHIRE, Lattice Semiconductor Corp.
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|   Model ss1135axxxeaddaaaain
[Model] ss1135axxxeaddaaaain
Model_type Input
Polarity   Non-Inverting
Vinl =  0.575V
Vinh =  0.775V
C_comp   4.266pF   4.245pF   4.360pF
[Temperature Range]   25.000   0.125k   -40.000
[Voltage Range]   1.350V   1.280V   1.420V
[GND_clamp]
|Voltage   I(typ)   I(min)   I(max)
-1.35V    -712.3mA   -606.5mA   -705.2mA
-1.26V    -559mA     -502.2mA   -516.3mA
-1.2V     -462.4mA   -435.9mA   -403.1mA
-1.08V    -286.6mA   -312.3mA   -212mA
-1.02V    -211.3mA   -255.5mA   -146.9mA
-960mV    -152.6mA   -202.9mA   -99.8mA
-840mV    -71.36mA   -121.1mA   -46.77mA
-750mV    -38.71mA   -79.26mA   -35.05mA
-660mV    -26.11mA   -49.12mA   -29mA
-480mV    -18.99mA   -21.75mA   -21.42mA
630mV     -363.6uA   -7.324uA   -1.03mA
1.35V     0A         0A         0A
[POWER_clamp]
|Voltage   I(typ)   I(min)   I(max)
-1.35V    98.01mA    91.04mA    115.1mA
-1.02V    70.36mA    65.8mA     84.06mA
-900mV    61mA       57.44mA    72.35mA
-660mV    42.34mA    41.99mA    46.96mA
-510mV    32.27mA    33.17mA    35.55mA
-390mV    26.48mA    27.09mA    29.54mA
-180mV    18.59mA    18.63mA    21.33mA
30mV      11.96mA    11.94mA    14mA
240mV     6.758mA    6.731mA    8.014mA
480mV     2.503mA    2.289mA    3.117mA
720mV     0A         0A         0A
1.35V     0A         0A         0A
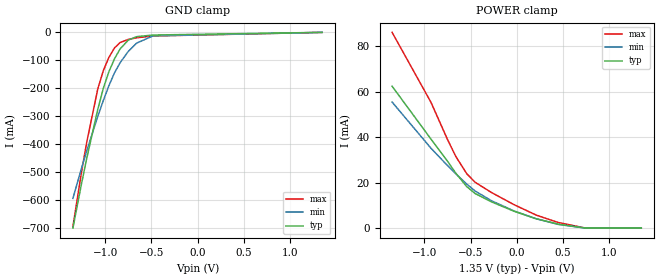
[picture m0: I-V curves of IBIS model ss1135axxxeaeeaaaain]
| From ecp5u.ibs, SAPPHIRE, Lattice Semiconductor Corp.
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|   Model ss1135axxxeaeeaaaain
[Model] ss1135axxxeaeeaaaain
Model_type Input
Polarity   Non-Inverting
Vinl =  0.575V
Vinh =  0.775V
C_comp   4.091pF   4.061pF   4.129pF
[Temperature Range]   25.000   0.125k   -40.000
[Voltage Range]   1.350V   1.280V   1.420V
[GND_clamp]
|Voltage   I(typ)   I(min)   I(max)
-1.35V    -699.5mA   -593.2mA   -694.2mA
-1.26V    -546.3mA   -489.1mA   -505.4mA
-1.2V     -449.9mA   -422.9mA   -392.3mA
-1.08V    -274.4mA   -299.7mA   -201.4mA
-1.02V    -199.3mA   -243.2mA   -136.3mA
-960mV    -140.6mA   -190.7mA   -89.34mA
-900mV    -95mA      -145.1mA   -55.94mA
-840mV    -59.77mA   -109.3mA   -36.61mA
-750mV    -27.48mA   -67.95mA   -25.17mA
-660mV    -15.33mA   -38.36mA   -19.46mA
-480mV    -9.452mA   -12.38mA   -12.88mA
1.35V     0A         0A         0A
[POWER_clamp]
|Voltage   I(typ)   I(min)   I(max)
-1.35V    62.46mA    55.49mA    86.16mA
-930mV    39.27mA    35.23mA    55.47mA
-750mV    29.48mA    27.55mA    39.04mA
-660mV    24.2mA     23.93mA    31.57mA
-540mV    18.23mA    19.34mA    23.89mA
-450mV    15.22mA    16.32mA    20.17mA
-270mV    11.51mA    11.99mA    15.6mA
-30mV     7.458mA    7.584mA    10.35mA
210mV     4.119mA    4.151mA    5.761mA
450mV     1.753mA    1.63mA     2.47mA
750mV     0A         0A         0A
1.35V     0A         0A         0A
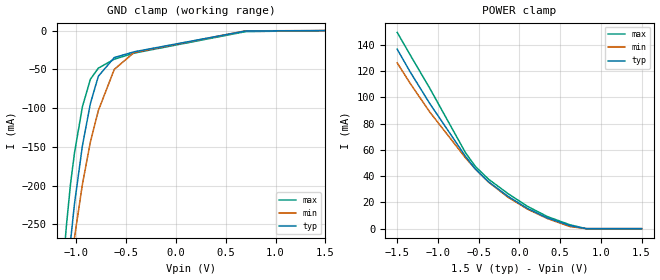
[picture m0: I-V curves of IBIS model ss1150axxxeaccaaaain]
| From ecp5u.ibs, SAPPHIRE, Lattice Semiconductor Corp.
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|   Model ss1150axxxeaccaaaain
[Model] ss1150axxxeaccaaaain
Model_type Input
Polarity   Non-Inverting
Vinl =  0.650V
Vinh =  0.850V
C_comp   4.383pF   4.308pF   4.470pF
[Temperature Range]   25.000   0.125k   -40.000
[Voltage Range]   1.500V   1.430V   1.580V
[GND_clamp]
|Voltage   I(typ)   I(min)   I(max)
-1.5V     -999.5mA   -804.2mA   -1.074A
-1.14V    -384.5mA   -384.9mA   -312.4mA
-1.1V     -327.1mA   -344.3mA   -250.9mA
-1.06V    -273mA     -305.2mA   -198.7mA
-1.02V    -224mA     -267.7mA   -158.2mA
-940mV    -148.7mA   -198.5mA   -98.27mA
-860mV    -94.3mA    -143.9mA   -62.84mA
-780mV    -58.91mA   -103.3mA   -48.5mA
-620mV    -34.81mA   -50.08mA   -36.95mA
-420mV    -27.36mA   -28.19mA   -29.06mA
700mV     -524.6uA   -319.7uA   -1.342mA
1.5V      0A         0A         0A
[POWER_clamp]
|Voltage   I(typ)   I(min)   I(max)
-1.5V     136.8mA    126.4mA    149.6mA
-1.34V    119.4mA    110.7mA    132.4mA
-1.1V     95.38mA    88.9mA     107mA
-660mV    55mA       53.9mA     57.75mA
-540mV    45.47mA    45.43mA    47.4mA
-380mV    35.81mA    35.56mA    37.77mA
-140mV    24.65mA    23.96mA    26.72mA
100mV     15.4mA     14.87mA    17.02mA
340mV     8.267mA    7.801mA    9.323mA
620mV     2.34mA     1.619mA    2.968mA
820mV     0A         0A         0A
1.5V      0A         0A         0A
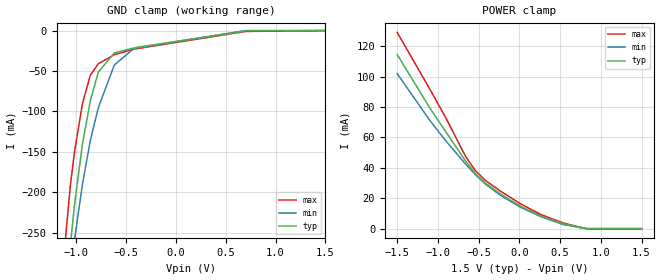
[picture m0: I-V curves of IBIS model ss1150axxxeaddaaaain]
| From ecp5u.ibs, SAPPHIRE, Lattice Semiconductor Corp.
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|   Model ss1150axxxeaddaaaain
[Model] ss1150axxxeaddaaaain
Model_type Input
Polarity   Non-Inverting
Vinl =  0.650V
Vinh =  0.850V
C_comp   4.276pF   4.208pF   4.339pF
[Temperature Range]   25.000   0.125k   -40.000
[Voltage Range]   1.500V   1.430V   1.580V
[GND_clamp]
|Voltage   I(typ)   I(min)   I(max)
-1.5V     -990.4mA   -794.8mA   -1.065A
-1.14V    -375.9mA   -376.1mA   -304.2mA
-1.1V     -318.6mA   -335.6mA   -243mA
-1.06V    -264.6mA   -296.6mA   -190.7mA
-1.02V    -215.9mA   -259.1mA   -150.3mA
-940mV    -140.7mA   -190.1mA   -90.43mA
-860mV    -86.48mA   -135.6mA   -55.14mA
-780mV    -51.3mA    -95.24mA   -40.97mA
-620mV    -27.77mA   -42.64mA   -29.87mA
-420mV    -21.37mA   -21.84mA   -22.89mA
700mV     -305uA     -42.2uA    -1.054mA
1.5V      0A         0A         0A
[POWER_clamp]
|Voltage   I(typ)   I(min)   I(max)
-1.5V     114.5mA    102mA      129.1mA
-1.1V     79.45mA    71.27mA    91.82mA
-900mV    63.46mA    57.57mA    72.65mA
-660mV    44.51mA    42.49mA    47.43mA
-540mV    36.23mA    35.54mA    38.17mA
-420mV    30.05mA    29.43mA    31.83mA
-220mV    22.38mA    21.5mA     24.25mA
20mV      14.65mA    13.93mA    16.2mA
260mV     8.386mA    7.937mA    9.402mA
540mV     3.131mA    2.68mA     3.657mA
820mV     0A         0A         0A
1.5V      0A         0A         0A
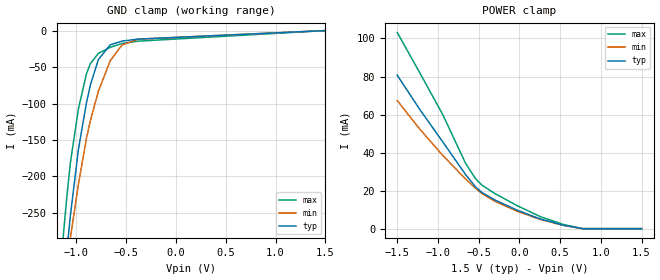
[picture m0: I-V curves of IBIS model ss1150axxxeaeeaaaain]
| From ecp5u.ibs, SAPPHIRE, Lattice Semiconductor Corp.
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|   Model ss1150axxxeaeeaaaain
[Model] ss1150axxxeaeeaaaain
Model_type Input
Polarity   Non-Inverting
Vinl =  0.650V
Vinh =  0.850V
C_comp   4.116pF   4.098pF   4.136pF
[Temperature Range]   25.000   0.125k   -40.000
[Voltage Range]   1.500V   1.430V   1.580V
[GND_clamp]
|Voltage   I(typ)   I(min)   I(max)
-1.5V     -977.5mA   -780.9mA   -1.054A
-1.14V    -363.7mA   -363mA     -294mA
-1.1V     -306.5mA   -322.6mA   -232.8mA
-1.06V    -252.6mA   -283.7mA   -180.4mA
-980mV    -162.8mA   -210.8mA   -107.3mA
-900mV    -99.44mA   -148.2mA   -59.62mA
-860mV    -74.72mA   -123.4mA   -45.27mA
-780mV    -39.84mA   -83.43mA   -31.32mA
-660mV    -19.42mA   -41.2mA    -22.93mA
-540mV    -14.38mA   -19.54mA   -17.62mA
-380mV    -11.69mA   -11.77mA   -14.51mA
1.5V      0A         0A         0A
[POWER_clamp]
|Voltage   I(typ)   I(min)   I(max)
-1.5V     80.72mA    67.38mA    103.2mA
-1.22V    62.55mA    52.2mA     81.75mA
-940mV    45.6mA     38.49mA    59.94mA
-660mV    28.42mA    26.13mA    34.31mA
-540mV    22.03mA    21.31mA    26.41mA
-460mV    19.02mA    18.5mA     22.89mA
-300mV    15.08mA    14.4mA     18.45mA
-20mV     9.603mA    9.044mA    11.94mA
260mV     5.054mA    4.834mA    6.295mA
540mV     1.827mA    1.713mA    2.211mA
780mV     0A         0A         0A
1.5V      0A         0A         0A
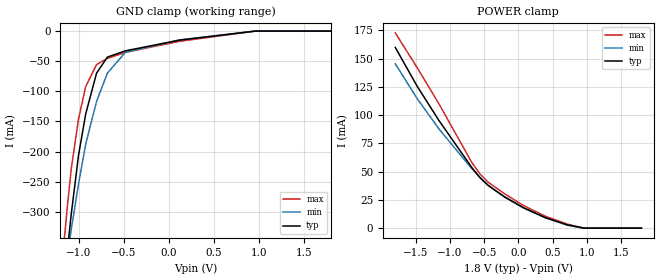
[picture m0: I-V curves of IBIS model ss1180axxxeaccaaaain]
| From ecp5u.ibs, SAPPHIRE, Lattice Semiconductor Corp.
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|   Model ss1180axxxeaccaaaain
[Model] ss1180axxxeaccaaaain
Model_type Input
Polarity   Non-Inverting
Vinl =  0.775V
Vinh =  1.025V
C_comp   4.319pF   4.234pF   4.369pF
[Temperature Range]   25.000   0.125k   -40.000
[Voltage Range]   1.800V   1.710V   1.890V
[GND_clamp]
|Voltage   I(typ)   I(min)   I(max)
-1.8V     -1.597A    -1.208A    -1.899A
-1.16V    -418.2mA   -410.3mA   -349.9mA
-1.12V    -359.4mA   -368.9mA   -285.6mA
-1.08V    -303.5mA   -329mA     -228.2mA
-1V       -206.4mA   -253.9mA   -146mA
-920mV    -137.4mA   -187.5mA   -91.89mA
-800mV    -69.83mA   -116.7mA   -55.62mA
-680mV    -43.17mA   -69.83mA   -45.33mA
-480mV    -32.76mA   -35.15mA   -35.25mA
120mV     -14.99mA   -14.61mA   -16.95mA
960mV     0A         0A         0A
1.8V      0A         0A         0A
[POWER_clamp]
|Voltage   I(typ)   I(min)   I(max)
-1.8V     160mA      145.5mA    172.8mA
-1.48V    125.6mA    114.7mA    142.1mA
-1.16V    95.17mA    87.72mA    109.9mA
-680mV    53.62mA    52.63mA    58.05mA
-560mV    44.6mA     44.83mA    47.86mA
-440mV    37.72mA    37.92mA    40.59mA
-200mV    27.69mA    27.37mA    30.36mA
80mV      17.97mA    17.67mA    19.89mA
400mV     9.202mA    9.026mA    10.43mA
720mV     2.902mA    2.563mA    3.498mA
960mV     0A         0A         0A
1.8V      0A         0A         0A
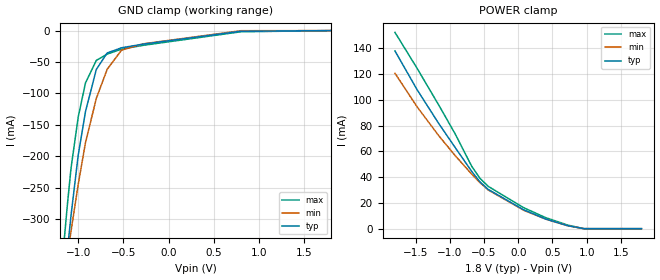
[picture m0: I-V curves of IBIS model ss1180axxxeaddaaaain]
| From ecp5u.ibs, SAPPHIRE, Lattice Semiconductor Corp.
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|   Model ss1180axxxeaddaaaain
[Model] ss1180axxxeaddaaaain
Model_type Input
Polarity   Non-Inverting
Vinl =  0.775V
Vinh =  1.025V
C_comp   4.221pF   4.191pF   4.264pF
[Temperature Range]   25.000   0.125k   -40.000
[Voltage Range]   1.800V   1.710V   1.890V
[GND_clamp]
|Voltage   I(typ)   I(min)   I(max)
-1.8V     -1.587A    -1.198A    -1.89A
-1.16V    -409.4mA   -400.9mA   -341.7mA
-1.12V    -350.6mA   -359.6mA   -277.4mA
-1.08V    -294.9mA   -319.8mA   -219.7mA
-1V       -198.2mA   -244.9mA   -137.5mA
-920mV    -129.3mA   -178.7mA   -83.54mA
-800mV    -61.96mA   -108.2mA   -47.51mA
-680mV    -35.69mA   -61.7mA    -37.54mA
-520mV    -27.36mA   -31.14mA   -29.5mA
-280mV    -21.51mA   -21.07mA   -23.47mA
800mV     -1.08mA    -208.6uA   -1.918mA
1.8V      0A         0A         0A
[POWER_clamp]
|Voltage   I(typ)   I(min)   I(max)
-1.8V     137.9mA    120.6mA    152.3mA
-1.48V    108.1mA    94.78mA    124.7mA
-1.16V    81.52mA    72.09mA    95.85mA
-920mV    62.9mA     56.64mA    73.47mA
-680mV    44.48mA    42.38mA    48.49mA
-560mV    36.4mA     35.79mA    39.17mA
-440mV    30.52mA    30.08mA    32.9mA
80mV      14.64mA    14.26mA    16.27mA
400mV     7.501mA    7.447mA    8.579mA
720mV     2.316mA    2.317mA    2.826mA
960mV     0A         0A         0A
1.8V      0A         0A         0A
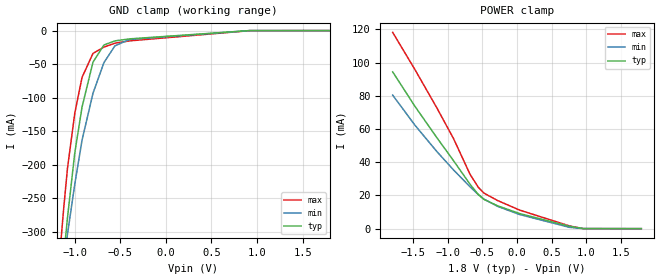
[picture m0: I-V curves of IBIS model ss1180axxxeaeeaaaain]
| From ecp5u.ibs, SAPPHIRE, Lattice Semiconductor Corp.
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|   Model ss1180axxxeaeeaaaain
[Model] ss1180axxxeaeeaaaain
Model_type Input
Polarity   Non-Inverting
Vinl =  0.775V
Vinh =  1.025V
C_comp   4.052pF   4.014pF   4.077pF
[Temperature Range]   25.000   0.125k   -40.000
[Voltage Range]   1.800V   1.710V   1.890V
[GND_clamp]
|Voltage   I(typ)   I(min)   I(max)
-1.8V     -1.57A     -1.18A     -1.874A
-1.16V    -393.8mA   -384.8mA   -327.2mA
-1.12V    -335.2mA   -343.6mA   -263.1mA
-1.08V    -279.5mA   -304mA     -205.7mA
-1V       -182.6mA   -229.4mA   -123.5mA
-920mV    -114mA     -163.4mA   -69.74mA
-800mV    -47.13mA   -93.49mA   -34.09mA
-680mV    -21.5mA    -47.81mA   -24.64mA
-560mV    -15.37mA   -22.86mA   -18.85mA
-400mV    -12.4mA    -13.2mA    -15.36mA
920mV     0A         0A         -101.8uA
1.8V      0A         0A         0A
[POWER_clamp]
|Voltage   I(typ)   I(min)   I(max)
-1.8V     94.4mA     80.41mA    118.2mA
-1.48V    73.8mA     62.41mA    95.92mA
-1.16V    54.75mA    46.4mA     72.67mA
-920mV    40.97mA    35.41mA    54.3mA
-680mV    26.73mA    25.21mA    32.73mA
-560mV    20.51mA    20.52mA    24.88mA
-480mV    17.67mA    17.81mA    21.44mA
-280mV    13.74mA    13.42mA    16.91mA
40mV      9.073mA    8.476mA    11.15mA
760mV     1.418mA    787.1uA    1.65mA
960mV     88.9uA     0A         0A
1.8V      0A         0A         0A
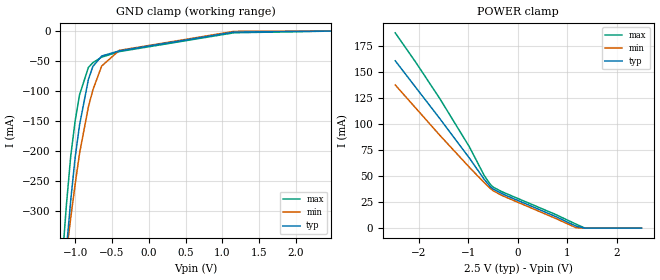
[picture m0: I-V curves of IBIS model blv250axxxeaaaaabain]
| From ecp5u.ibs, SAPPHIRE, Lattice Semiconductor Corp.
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|   Model blv250axxxeaaaaabain
[Model] blv250axxxeaaaaabain
Model_type Input
Polarity   Non-Inverting
Vinl =  1.150V
Vinh =  1.350V
C_comp   5.000pF   4.000pF   5.500pF
[Temperature Range]   25.000   0.125k   -40.000
[Voltage Range]   2.500V   2.380V   2.630V
[GND_clamp]
|Voltage   I(typ)   I(min)   I(max)
-2.5V     -3.144A    -2.26A     -4.157A
-1.18V    -455.7mA   -435.1mA   -391.3mA
-1.12V    -365.8mA   -371.9mA   -292.2mA
-1.06V    -282.6mA   -312.1mA   -208.6mA
-1V       -211.1mA   -255.8mA   -149.9mA
-940mV    -156.6mA   -204.1mA   -106.4mA
-820mV    -80.76mA   -126.6mA   -60.69mA
-760mV    -59.25mA   -98.65mA   -52.93mA
-640mV    -41.66mA   -58.45mA   -43.66mA
-400mV    -33.05mA   -32.23mA   -34.34mA
1.16V     -1.599mA   -445.7uA   -2.803mA
2.48V     0A         0A         0A
[POWER_clamp]
|Voltage   I(typ)   I(min)   I(max)
-2.48V    160.7mA    137.5mA    187.5mA
-2.06V    134.8mA    115mA      158.9mA
-1.58V    105.3mA    89.26mA    124.5mA
-980mV    67.24mA    58.41mA    78.03mA
-680mV    46.85mA    43.72mA    50.51mA
-560mV    39.97mA    38.27mA    42.22mA
-500mV    37.5mA     35.95mA    39.4mA
-320mV    33.08mA    31.35mA    34.93mA
760mV     11.25mA    9.454mA    13.21mA
1.18V     1.884mA    398.1uA    3.781mA
1.36V     0A         0A         0A
2.5V      0A         0A         0A
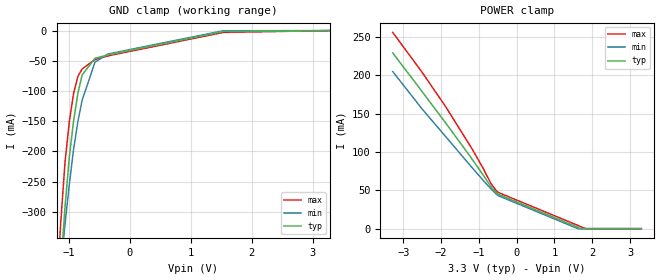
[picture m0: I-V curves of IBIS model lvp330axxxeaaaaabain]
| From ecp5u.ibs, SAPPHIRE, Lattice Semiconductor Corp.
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|   Model lvp330axxxeaaaaabain
[Model] lvp330axxxeaaaaabain
Model_type Input
Polarity   Non-Inverting
Vinl =  1.840V
Vinh =  2.140V
C_comp   5.000pF   4.000pF   5.500pF
[Temperature Range]   25.000   0.125k   -40.000
[Voltage Range]   3.300V   3.140V   3.470V
[GND_clamp]
|Voltage   I(typ)   I(min)   I(max)
-3.3V     -5.026A    -3.552A    -7.018A
-1.2V     -495.1mA   -464.5mA   -435.3mA
-1.13V    -388.3mA   -389.8mA   -316.3mA
-1.06V    -290.6mA   -319.7mA   -217mA
-990mV    -208.9mA   -254.4mA   -150.2mA
-920mV    -149mA     -196.1mA   -103.4mA
-850mV    -103.7mA   -150.3mA   -75.7mA
-780mV    -73.21mA   -115mA     -63.41mA
-570mV    -45.93mA   -52.29mA   -48.06mA
-360mV    -40.22mA   -38.77mA   -41.91mA
1.53V     -1.706mA   -315.8uA   -3.089mA
3.28V     0A         0A         0A
[POWER_clamp]
|Voltage   I(typ)   I(min)   I(max)
-3.28V    229.4mA    205.1mA    256.2mA
-2.51V    179.5mA    156.7mA    204.7mA
-1.88V    138.1mA    120.3mA    159.4mA
-1.18V    90.93mA    79.66mA    104.2mA
-900mV    70.96mA    63.89mA    79.97mA
-690mV    55.63mA    52.47mA    59.84mA
-550mV    47.54mA    45.57mA    50.12mA
-480mV    44.85mA    42.9mA     47.11mA
1.62V     1.655mA    0A         4.277mA
1.69V     82.62uA    0A         2.694mA
1.83V     0A         0A         0A
3.3V      0A         0A         0A
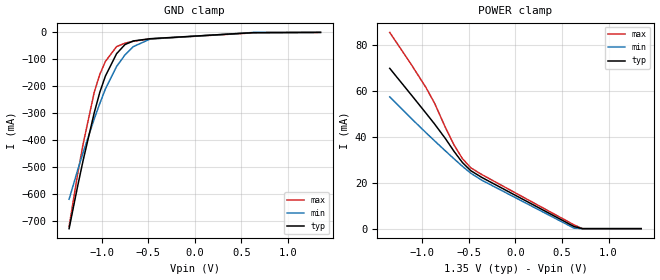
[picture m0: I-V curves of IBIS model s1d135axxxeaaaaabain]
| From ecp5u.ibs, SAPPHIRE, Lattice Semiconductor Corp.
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|   Model s1d135axxxeaaaaabain
[Model] s1d135axxxeaaaaabain
Model_type Input
Polarity   Non-Inverting
Vinl =  0.575V
Vinh =  0.775V
C_comp   5.000pF   4.000pF   5.500pF
[Temperature Range]   25.000   0.125k   -40.000
[Voltage Range]   1.350V   1.280V   1.420V
[GND_clamp]
|Voltage   I(typ)   I(min)   I(max)
-1.35V    -727.8mA   -618.7mA   -719.4mA
-1.26V    -573.1mA   -513.1mA   -529.1mA
-1.2V     -475.6mA   -445.9mA   -414.9mA
-1.08V    -298mA     -320.6mA   -221.8mA
-1.02V    -221.6mA   -263.2mA   -155.4mA
-960mV    -161.8mA   -209.6mA   -107.4mA
-840mV    -78.91mA   -126.2mA   -52.71mA
-750mV    -45.19mA   -83.51mA   -39.89mA
-660mV    -31.69mA   -52.7mA    -32.89mA
-480mV    -23.42mA   -24.63mA   -24.15mA
630mV     -899.6uA   -198.7uA   -1.6mA
1.35V     0A         0A         0A
[POWER_clamp]
|Voltage   I(typ)   I(min)   I(max)
-1.35V    69.85mA    57.4mA     85.51mA
-1.11V    57.85mA    47.68mA    70.99mA
-960mV    50.29mA    41.79mA    61.42mA
-870mV    45.68mA    38.32mA    54.78mA
-750mV    39.13mA    33.79mA    43.9mA
-660mV    33.7mA     30.45mA    36.5mA
-570mV    28.83mA    27.19mA    30.56mA
-480mV    25.26mA    24.16mA    26.51mA
-360mV    22.29mA    21.09mA    23.55mA
630mV     904.9uA    202uA      1.627mA
720mV     0A         0A         0A
1.35V     0A         0A         0A
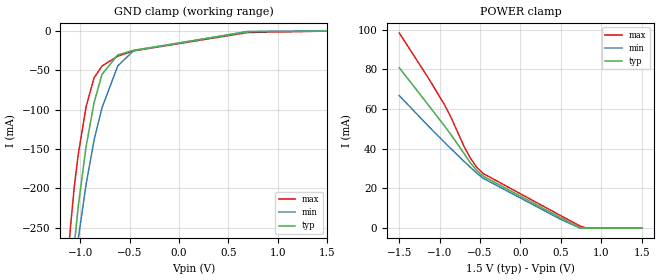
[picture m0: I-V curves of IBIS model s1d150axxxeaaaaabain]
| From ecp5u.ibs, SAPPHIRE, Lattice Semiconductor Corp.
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|   Model s1d150axxxeaaaaabain
[Model] s1d150axxxeaaaaabain
Model_type Input
Polarity   Non-Inverting
Vinl =  0.650V
Vinh =  0.850V
C_comp   5.000pF   4.000pF   5.500pF
[Temperature Range]   25.000   0.125k   -40.000
[Voltage Range]   1.500V   1.430V   1.580V
[GND_clamp]
|Voltage   I(typ)   I(min)   I(max)
-1.5V     -1.005A    -807mA     -1.08A
-1.14V    -385.1mA   -383.2mA   -313.6mA
-1.1V     -327.3mA   -342.1mA   -251.5mA
-1.06V    -272.7mA   -302.6mA   -198.1mA
-1.02V    -223.1mA   -264.7mA   -157mA
-940mV    -146.6mA   -194.6mA   -96mA
-860mV    -91.3mA    -139mA     -59.64mA
-780mV    -55.24mA   -97.9mA    -44.51mA
-620mV    -30.39mA   -44.33mA   -31.9mA
-460mV    -24.41mA   -25.03mA   -25.22mA
700mV     -998.6uA   -296.9uA   -1.799mA
1.5V      0A         0A         0A
[POWER_clamp]
|Voltage   I(typ)   I(min)   I(max)
-1.5V     80.86mA    66.81mA    98.39mA
-1.14V    62.08mA    51.46mA    75.68mA
-940mV    51.51mA    43.26mA    62.24mA
-860mV    47.17mA    40.05mA    55.92mA
-700mV    37.77mA    33.75mA    41.36mA
-620mV    32.96mA    30.68mA    35.31mA
-540mV    29mA       27.71mA    30.61mA
-460mV    26.19mA    25.1mA     27.5mA
500mV     5.209mA    4.402mA    6.267mA
740mV     206.8uA    0A         1.044mA
820mV     0A         0A         0A
1.5V      0A         0A         0A
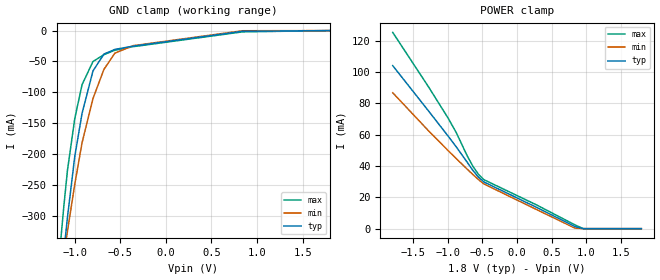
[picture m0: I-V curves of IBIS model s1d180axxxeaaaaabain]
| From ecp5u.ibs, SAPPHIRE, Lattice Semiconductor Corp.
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|   Model s1d180axxxeaaaaabain
[Model] s1d180axxxeaaaaabain
Model_type Input
Polarity   Non-Inverting
Vinl =  0.775V
Vinh =  1.025V
C_comp   5.000pF   4.000pF   5.500pF
[Temperature Range]   25.000   0.125k   -40.000
[Voltage Range]   1.800V   1.710V   1.890V
[GND_clamp]
|Voltage   I(typ)   I(min)   I(max)
-1.8V     -1.606A    -1.214A    -1.908A
-1.16V    -418.1mA   -407mA     -349.8mA
-1.12V    -358.8mA   -365.3mA   -284.9mA
-1.08V    -302.5mA   -325mA     -226.4mA
-1V       -204.1mA   -249.1mA   -142.6mA
-920mV    -134.1mA   -181.8mA   -87.61mA
-800mV    -65.37mA   -110mA     -50.12mA
-680mV    -38.07mA   -62.8mA    -38.99mA
-560mV    -30.52mA   -36.56mA   -31.78mA
-360mV    -25.22mA   -24.48mA   -26.11mA
840mV     -1.187mA   -283uA     -2.085mA
1.8V      0A         0A         0A
[POWER_clamp]
|Voltage   I(typ)   I(min)   I(max)
-1.8V     104mA      86.71mA    125.2mA
-1.28V    75.02mA    62.37mA    90.36mA
-1V       59.18mA    49.92mA    70.69mA
-880mV    52.17mA    44.71mA    61.3mA
-720mV    42.27mA    37.89mA    46.34mA
-640mV    37.2mA     34.57mA    39.9mA
-560mV    32.93mA    31.37mA    34.78mA
-480mV    29.81mA    28.53mA    31.25mA
280mV     13.65mA    12.25mA    15.2mA
840mV     1.291mA    327.4uA    2.384mA
960mV     0A         0A         0A
1.8V      0A         0A         0A
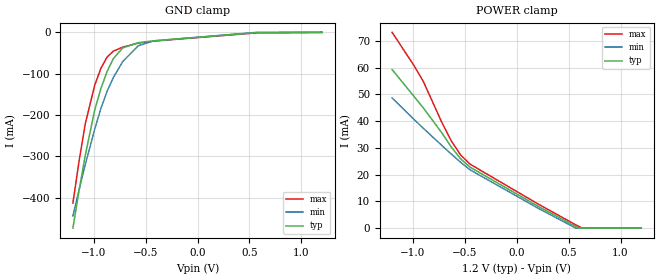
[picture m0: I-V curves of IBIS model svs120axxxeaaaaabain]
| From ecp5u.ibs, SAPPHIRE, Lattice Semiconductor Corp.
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|   Model svs120axxxeaaaaabain
[Model] svs120axxxeaaaaabain
Model_type Input
Polarity   Non-Inverting
Vinl =  0.0V
Vinh =  0.400V
C_comp   5.000pF   4.000pF   5.500pF
[Temperature Range]   25.000   0.125k   -40.000
[Voltage Range]   1.200V   1.140V   1.260V
[GND_clamp]
|Voltage   I(typ)   I(min)   I(max)
-1.2V     -474mA     -444.5mA   -413.2mA
-1.14V    -382.1mA   -380.2mA   -310.4mA
-1.08V    -296.5mA   -319.2mA   -220.2mA
-990mV    -188mA     -234.4mA   -128.1mA
-930mV    -135.7mA   -183.8mA   -86.84mA
-870mV    -94.19mA   -142.1mA   -59.61mA
-810mV    -63.44mA   -109.2mA   -45.3mA
-720mV    -37.52mA   -70.52mA   -35.74mA
-570mV    -24.93mA   -32.29mA   -25.96mA
-420mV    -20.48mA   -20.47mA   -21.08mA
570mV     -599.9uA   0A         -1.2mA
1.2V      0A         0A         0A
[POWER_clamp]
|Voltage   I(typ)   I(min)   I(max)
-1.2V     59.32mA    48.7mA     73.22mA
-990mV    49.32mA    40.71mA    60.88mA
-900mV    44.99mA    37.38mA    54.92mA
-720mV    35.59mA    30.88mA    39.47mA
-630mV    30.36mA    27.72mA    32.64mA
-540mV    25.93mA    24.63mA    27.34mA
-450mV    22.83mA    21.83mA    23.95mA
210mV     8.088mA    7.364mA    8.936mA
570mV     600.9uA    693.9nA    1.204mA
600mV     356.7nA    0A         601.5uA
630mV     0A         0A         550.5nA
1.2V      0A         0A         0A
